# This Lef is suitable for top metal5 design.
#
# ==================STATEMENT===================================
# Copyright (c) 2001-2019 Grace Semiconductor Manufacturing Corporation.
# All Rights Reserved.
# Forwarding or copying of this document, in any medium, in whole or 
# in part, or disclosure of its contents, to other than an authorized 
# recipient, is strictly prohibited.
#
# =============IMPORTANT APPLICATION NOTES======================
# M1~ M5 layers Must NOT be used for routing over the IP region. 
# 
# LEF OUT API 
# User Name : daisb 
# Date : Thu Mar 28 11:13:39 2019
# 
NAMESCASESENSITIVE ON ;
BUSBITCHARS "[]" ;
DIVIDERCHAR "/" ;
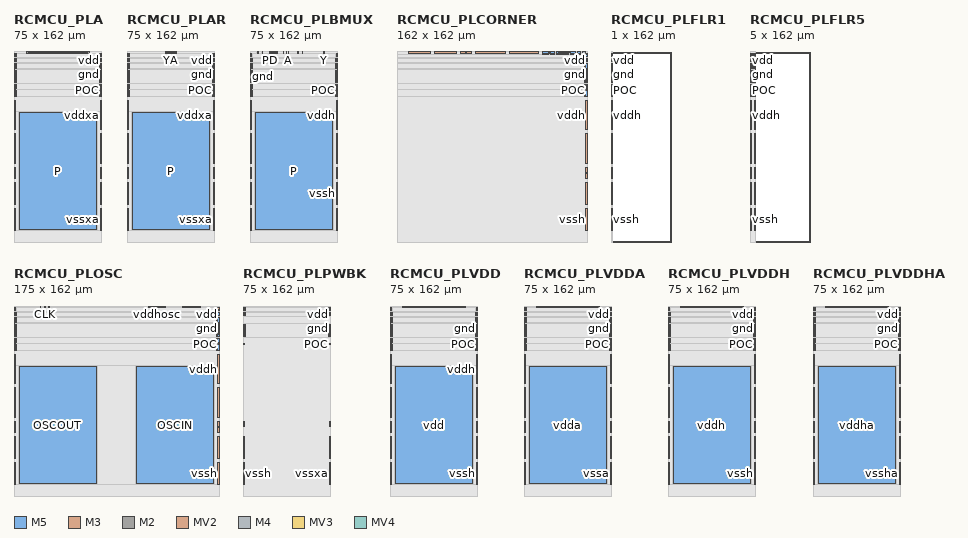
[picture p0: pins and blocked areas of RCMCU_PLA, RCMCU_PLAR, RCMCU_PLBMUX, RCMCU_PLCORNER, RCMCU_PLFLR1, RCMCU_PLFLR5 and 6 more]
MACRO RCMCU_PLA
 CLASS PAD ;
 FOREIGN RCMCU_PLA ;
 ORIGIN 0 0 ;
 SIZE 75 BY 162 ;
 SYMMETRY X Y R90 ;
 PIN P
 USE SIGNAL ;
 DIRECTION INOUT ;
 PORT
 LAYER M5 ;
 RECT 4.5 10.5 70.5 110.5 ;
 END
 PORT
 LAYER M3 ;
 RECT 10.77 160.82 64.77 162 ;
 END
 PORT
 LAYER M2 ;
 RECT 10.77 160.82 64.77 162 ;
 END
 PORT
 LAYER MV2 ;
 RECT 25.21 161.515 25.4 161.705 ;
 RECT 30.71 160.965 30.9 161.155 ;
 RECT 30.16 160.965 30.35 161.155 ;
 RECT 29.61 160.965 29.8 161.155 ;
 RECT 29.06 160.965 29.25 161.155 ;
 RECT 28.51 160.965 28.7 161.155 ;
 RECT 30.71 161.515 30.9 161.705 ;
 RECT 28.51 161.515 28.7 161.705 ;
 RECT 29.06 161.515 29.25 161.705 ;
 RECT 29.61 161.515 29.8 161.705 ;
 RECT 30.16 161.515 30.35 161.705 ;
 RECT 34.01 160.965 34.2 161.155 ;
 RECT 33.46 160.965 33.65 161.155 ;
 RECT 32.91 160.965 33.1 161.155 ;
 RECT 32.36 160.965 32.55 161.155 ;
 RECT 31.81 160.965 32 161.155 ;
 RECT 32.91 161.515 33.1 161.705 ;
 RECT 33.46 161.515 33.65 161.705 ;
 RECT 34.01 161.515 34.2 161.705 ;
 RECT 32.36 161.515 32.55 161.705 ;
 RECT 31.81 161.515 32 161.705 ;
 RECT 35.66 160.965 35.85 161.155 ;
 RECT 36.21 160.965 36.4 161.155 ;
 RECT 36.76 160.965 36.95 161.155 ;
 RECT 37.31 160.965 37.5 161.155 ;
 RECT 35.11 160.965 35.3 161.155 ;
 RECT 34.56 160.965 34.75 161.155 ;
 RECT 35.11 161.515 35.3 161.705 ;
 RECT 37.31 161.515 37.5 161.705 ;
 RECT 36.76 161.515 36.95 161.705 ;
 RECT 36.21 161.515 36.4 161.705 ;
 RECT 35.66 161.515 35.85 161.705 ;
 RECT 34.56 161.515 34.75 161.705 ;
 RECT 31.26 160.965 31.45 161.155 ;
 RECT 31.26 161.515 31.45 161.705 ;
 RECT 40.06 160.965 40.25 161.155 ;
 RECT 40.61 160.965 40.8 161.155 ;
 RECT 39.51 160.965 39.7 161.155 ;
 RECT 38.96 160.965 39.15 161.155 ;
 RECT 38.41 160.965 38.6 161.155 ;
 RECT 37.86 160.965 38.05 161.155 ;
 RECT 40.61 161.515 40.8 161.705 ;
 RECT 40.06 161.515 40.25 161.705 ;
 RECT 37.86 161.515 38.05 161.705 ;
 RECT 38.41 161.515 38.6 161.705 ;
 RECT 38.96 161.515 39.15 161.705 ;
 RECT 39.51 161.515 39.7 161.705 ;
 RECT 42.26 160.965 42.45 161.155 ;
 RECT 42.81 160.965 43 161.155 ;
 RECT 43.36 160.965 43.55 161.155 ;
 RECT 41.16 160.965 41.35 161.155 ;
 RECT 41.71 160.965 41.9 161.155 ;
 RECT 42.26 161.515 42.45 161.705 ;
 RECT 42.81 161.515 43 161.705 ;
 RECT 43.36 161.515 43.55 161.705 ;
 RECT 41.71 161.515 41.9 161.705 ;
 RECT 41.16 161.515 41.35 161.705 ;
 RECT 44.46 160.965 44.65 161.155 ;
 RECT 45.01 160.965 45.2 161.155 ;
 RECT 45.56 160.965 45.75 161.155 ;
 RECT 46.11 160.965 46.3 161.155 ;
 RECT 46.66 160.965 46.85 161.155 ;
 RECT 44.46 161.515 44.65 161.705 ;
 RECT 46.66 161.515 46.85 161.705 ;
 RECT 46.11 161.515 46.3 161.705 ;
 RECT 45.56 161.515 45.75 161.705 ;
 RECT 45.01 161.515 45.2 161.705 ;
 RECT 49.96 160.965 50.15 161.155 ;
 RECT 49.41 160.965 49.6 161.155 ;
 RECT 48.86 160.965 49.05 161.155 ;
 RECT 48.31 160.965 48.5 161.155 ;
 RECT 47.76 160.965 47.95 161.155 ;
 RECT 47.21 160.965 47.4 161.155 ;
 RECT 49.96 161.515 50.15 161.705 ;
 RECT 49.41 161.515 49.6 161.705 ;
 RECT 47.21 161.515 47.4 161.705 ;
 RECT 47.76 161.515 47.95 161.705 ;
 RECT 48.31 161.515 48.5 161.705 ;
 RECT 48.86 161.515 49.05 161.705 ;
 RECT 43.91 160.965 44.1 161.155 ;
 RECT 43.91 161.515 44.1 161.705 ;
 RECT 51.61 160.965 51.8 161.155 ;
 RECT 52.16 160.965 52.35 161.155 ;
 RECT 52.71 160.965 52.9 161.155 ;
 RECT 50.51 160.965 50.7 161.155 ;
 RECT 51.06 160.965 51.25 161.155 ;
 RECT 51.61 161.515 51.8 161.705 ;
 RECT 52.16 161.515 52.35 161.705 ;
 RECT 52.71 161.515 52.9 161.705 ;
 RECT 51.06 161.515 51.25 161.705 ;
 RECT 50.51 161.515 50.7 161.705 ;
 RECT 53.81 160.965 54 161.155 ;
 RECT 54.36 160.965 54.55 161.155 ;
 RECT 54.91 160.965 55.1 161.155 ;
 RECT 56.01 160.965 56.2 161.155 ;
 RECT 55.46 160.965 55.65 161.155 ;
 RECT 53.81 161.515 54 161.705 ;
 RECT 56.01 161.515 56.2 161.705 ;
 RECT 55.46 161.515 55.65 161.705 ;
 RECT 54.91 161.515 55.1 161.705 ;
 RECT 54.36 161.515 54.55 161.705 ;
 RECT 53.26 160.965 53.45 161.155 ;
 RECT 53.26 161.515 53.45 161.705 ;
 RECT 59.31 160.965 59.5 161.155 ;
 RECT 58.76 160.965 58.95 161.155 ;
 RECT 57.11 160.965 57.3 161.155 ;
 RECT 56.56 160.965 56.75 161.155 ;
 RECT 58.21 160.965 58.4 161.155 ;
 RECT 57.66 160.965 57.85 161.155 ;
 RECT 59.31 161.515 59.5 161.705 ;
 RECT 58.76 161.515 58.95 161.705 ;
 RECT 56.56 161.515 56.75 161.705 ;
 RECT 57.11 161.515 57.3 161.705 ;
 RECT 57.66 161.515 57.85 161.705 ;
 RECT 58.21 161.515 58.4 161.705 ;
 RECT 60.96 160.965 61.15 161.155 ;
 RECT 61.51 160.965 61.7 161.155 ;
 RECT 62.06 160.965 62.25 161.155 ;
 RECT 62.61 160.965 62.8 161.155 ;
 RECT 60.41 160.965 60.6 161.155 ;
 RECT 59.86 160.965 60.05 161.155 ;
 RECT 60.96 161.515 61.15 161.705 ;
 RECT 61.51 161.515 61.7 161.705 ;
 RECT 62.61 161.515 62.8 161.705 ;
 RECT 62.06 161.515 62.25 161.705 ;
 RECT 60.41 161.515 60.6 161.705 ;
 RECT 59.86 161.515 60.05 161.705 ;
 RECT 15.31 160.965 15.5 161.155 ;
 RECT 14.76 160.965 14.95 161.155 ;
 RECT 14.21 160.965 14.4 161.155 ;
 RECT 12.56 160.965 12.75 161.155 ;
 RECT 13.11 160.965 13.3 161.155 ;
 RECT 13.66 160.965 13.85 161.155 ;
 RECT 14.21 161.515 14.4 161.705 ;
 RECT 14.76 161.515 14.95 161.705 ;
 RECT 15.31 161.515 15.5 161.705 ;
 RECT 12.56 161.515 12.75 161.705 ;
 RECT 13.11 161.515 13.3 161.705 ;
 RECT 13.66 161.515 13.85 161.705 ;
 RECT 18.61 160.965 18.8 161.155 ;
 RECT 16.96 160.965 17.15 161.155 ;
 RECT 16.41 160.965 16.6 161.155 ;
 RECT 18.06 160.965 18.25 161.155 ;
 RECT 17.51 160.965 17.7 161.155 ;
 RECT 15.86 160.965 16.05 161.155 ;
 RECT 18.61 161.515 18.8 161.705 ;
 RECT 16.41 161.515 16.6 161.705 ;
 RECT 18.06 161.515 18.25 161.705 ;
 RECT 17.51 161.515 17.7 161.705 ;
 RECT 16.96 161.515 17.15 161.705 ;
 RECT 15.86 161.515 16.05 161.705 ;
 RECT 21.36 160.965 21.55 161.155 ;
 RECT 20.81 160.965 21 161.155 ;
 RECT 20.26 160.965 20.45 161.155 ;
 RECT 19.71 160.965 19.9 161.155 ;
 RECT 19.16 160.965 19.35 161.155 ;
 RECT 21.36 161.515 21.55 161.705 ;
 RECT 19.16 161.515 19.35 161.705 ;
 RECT 19.71 161.515 19.9 161.705 ;
 RECT 20.26 161.515 20.45 161.705 ;
 RECT 20.81 161.515 21 161.705 ;
 RECT 23.56 160.965 23.75 161.155 ;
 RECT 24.11 160.965 24.3 161.155 ;
 RECT 24.66 160.965 24.85 161.155 ;
 RECT 22.46 160.965 22.65 161.155 ;
 RECT 23.01 160.965 23.2 161.155 ;
 RECT 23.56 161.515 23.75 161.705 ;
 RECT 24.11 161.515 24.3 161.705 ;
 RECT 24.66 161.515 24.85 161.705 ;
 RECT 23.01 161.515 23.2 161.705 ;
 RECT 22.46 161.515 22.65 161.705 ;
 RECT 21.91 160.965 22.1 161.155 ;
 RECT 21.91 161.515 22.1 161.705 ;
 RECT 27.96 160.965 28.15 161.155 ;
 RECT 25.76 160.965 25.95 161.155 ;
 RECT 26.31 160.965 26.5 161.155 ;
 RECT 26.86 160.965 27.05 161.155 ;
 RECT 27.41 160.965 27.6 161.155 ;
 RECT 25.21 160.965 25.4 161.155 ;
 RECT 27.96 161.515 28.15 161.705 ;
 RECT 25.76 161.515 25.95 161.705 ;
 RECT 27.41 161.515 27.6 161.705 ;
 RECT 26.86 161.515 27.05 161.705 ;
 RECT 26.31 161.515 26.5 161.705 ;
 END
 END P
 PIN POC
 USE POWER ;
 DIRECTION INOUT ;
 PORT
 LAYER M3 ;
 RECT 73.72 129.1 75 130 ;
 END
 PORT
 LAYER M3 ;
 RECT 0 129.1 1.28 130 ;
 END
 END POC
 PIN gnd
 USE GROUND ;
 DIRECTION INOUT ;
 PORT
 LAYER M5 ;
 RECT 73.415 135.99 75 146.46 ;
 END
 PORT
 LAYER M5 ;
 RECT 0 135.99 1.585 146.46 ;
 END
 PORT
 LAYER M5 ;
 RECT 0 157.97 1.585 160.47 ;
 END
 PORT
 LAYER M5 ;
 RECT 73.415 157.97 75 160.47 ;
 END
 PORT
 LAYER M4 ;
 RECT 73 135.99 75 146.46 ;
 END
 PORT
 LAYER M4 ;
 RECT 0 135.99 2 146.46 ;
 END
 PORT
 LAYER M4 ;
 RECT 0 157.97 2 160.47 ;
 END
 PORT
 LAYER M4 ;
 RECT 73 157.97 75 160.47 ;
 END
 PORT
 LAYER M3 ;
 RECT 73.72 59.66 75 63.66 ;
 END
 PORT
 LAYER M3 ;
 RECT 0 59.66 1.28 63.66 ;
 END
 END gnd
 PIN vdd
 USE POWER ;
 DIRECTION INOUT ;
 PORT
 LAYER M5 ;
 RECT 73.415 153.8 75 156.3 ;
 END
 PORT
 LAYER M5 ;
 RECT 0 153.8 1.585 156.3 ;
 END
 PORT
 LAYER M4 ;
 RECT 73 153.8 75 156.3 ;
 END
 PORT
 LAYER M4 ;
 RECT 0 153.8 2 156.3 ;
 END
 END vdd
 PIN vddxa
 USE POWER ;
 DIRECTION INOUT ;
 PORT
 LAYER M5 ;
 RECT 73.415 130.82 75 134.32 ;
 END
 PORT
 LAYER M5 ;
 RECT 0 130.82 1.585 134.32 ;
 END
 PORT
 LAYER M4 ;
 RECT 73 130.82 75 134.32 ;
 END
 PORT
 LAYER M4 ;
 RECT 0 130.82 2 134.32 ;
 END
 PORT
 LAYER M3 ;
 RECT 73.72 53.99 75 57.99 ;
 END
 PORT
 LAYER M3 ;
 RECT 0 53.99 1.28 57.99 ;
 END
 PORT
 LAYER M3 ;
 RECT 73.72 66.96 75 92.24 ;
 END
 PORT
 LAYER M3 ;
 RECT 0 66.96 1.28 92.24 ;
 END
 PORT
 LAYER M3 ;
 RECT 0 95.54 1.28 120.85 ;
 END
 PORT
 LAYER M3 ;
 RECT 73.72 95.54 75 120.85 ;
 END
 PORT
 LAYER M3 ;
 RECT 0 137.66 0.6 150.47 ;
 END
 PORT
 LAYER M3 ;
 RECT 74.4 137.66 75 150.47 ;
 END
 END vddxa
 PIN vssxa
 USE GROUND ;
 DIRECTION INOUT ;
 PORT
 LAYER M5 ;
 RECT 73.415 124.15 75 129.15 ;
 END
 PORT
 LAYER M5 ;
 RECT 0 124.15 1.585 129.15 ;
 END
 PORT
 LAYER M5 ;
 RECT 0 148.13 1.585 152.13 ;
 END
 PORT
 LAYER M5 ;
 RECT 73.415 148.13 75 152.13 ;
 END
 PORT
 LAYER M4 ;
 RECT 73 124.15 75 129.15 ;
 END
 PORT
 LAYER M4 ;
 RECT 0 124.15 2 129.15 ;
 END
 PORT
 LAYER M4 ;
 RECT 0 148.13 2 152.13 ;
 END
 PORT
 LAYER M4 ;
 RECT 73 148.13 75 152.13 ;
 END
 PORT
 LAYER M3 ;
 RECT 73.72 9.91 75 28.65 ;
 END
 PORT
 LAYER M3 ;
 RECT 0 9.91 1.28 28.65 ;
 END
 PORT
 LAYER M3 ;
 RECT 0 31.95 1.28 50.69 ;
 END
 PORT
 LAYER M3 ;
 RECT 73.72 31.95 75 50.69 ;
 END
 END vssxa
 OBS
 LAYER GATE ;
 RECT 0 0 75 162 ;
 LAYER MV1 ;
 RECT 0 0 75 162 ;
 LAYER MV2 ;
 RECT 0 0 75 162 ;
 LAYER MV3 ;
 RECT 0 0 75 162 ;
 LAYER MV4 ;
 RECT 0 0 75 162 ;
 LAYER M1 ;
 RECT 0 0 75 162 ;
 LAYER M2 ;
 RECT 65.37 160.22 75 162 ;
 RECT 0 160.22 10.17 162 ;
 RECT 0 0 75 160.22 ;
 LAYER M3 ;
 RECT 0 0 75 9.31 ;
 RECT 0 29.25 75 31.35 ;
 RECT 1.88 9.31 73.12 29.25 ;
 RECT 0 160.22 10.17 162 ;
 RECT 0 51.29 75 53.75 ;
 RECT 1.88 31.35 73.12 51.29 ;
 RECT 0 58.23 75 59.42 ;
 RECT 1.52 53.75 73.48 58.23 ;
 RECT 1.88 66.36 73.12 92.84 ;
 RECT 1.88 94.94 73.12 121.45 ;
 RECT 0 63.9 75 66.36 ;
 RECT 1.52 59.42 73.48 63.9 ;
 RECT 0 92.84 75 94.94 ;
 RECT 0 121.45 75 128.86 ;
 RECT 0 130.24 75 137.06 ;
 RECT 1.52 128.86 73.48 130.24 ;
 RECT 0 151.07 75 160.22 ;
 RECT 1.2 137.06 73.8 151.07 ;
 RECT 65.37 160.22 75 162 ;
 LAYER M4 ;
 RECT 0 0 75 123.91 ;
 RECT 0 129.39 75 130.58 ;
 RECT 2.24 123.91 72.76 129.39 ;
 RECT 2.6 135.39 72.4 147.06 ;
 RECT 0 134.56 75 135.39 ;
 RECT 2.24 130.58 72.76 134.56 ;
 RECT 0 147.06 75 147.89 ;
 RECT 0 152.37 75 153.56 ;
 RECT 2.24 147.89 72.76 152.37 ;
 RECT 0 156.54 75 157.73 ;
 RECT 2.24 153.56 72.76 156.54 ;
 RECT 0 160.71 75 162 ;
 RECT 2.24 157.73 72.76 160.71 ;
 LAYER M5 ;
 RECT 0 9.9 3.9 111.1 ;
 RECT 71.1 9.9 75 111.1 ;
 RECT 0 0 75 9.9 ;
 RECT 0 111.1 75 123.69 ;
 RECT 0 129.61 75 130.36 ;
 RECT 2.045 123.69 72.955 129.61 ;
 RECT 2.185 135.39 72.815 147.06 ;
 RECT 0 134.78 75 135.39 ;
 RECT 2.045 130.36 72.955 134.78 ;
 RECT 0 147.06 75 147.67 ;
 RECT 0 152.59 75 153.34 ;
 RECT 2.045 147.67 72.955 152.59 ;
 RECT 0 156.76 75 157.51 ;
 RECT 2.045 153.34 72.955 156.76 ;
 RECT 0 160.93 75 162 ;
 RECT 2.045 157.51 72.955 160.93 ;
 END
END RCMCU_PLA

MACRO RCMCU_PLAR
 CLASS PAD ;
 FOREIGN RCMCU_PLAR ;
 ORIGIN 0 0 ;
 SIZE 75 BY 162 ;
 SYMMETRY X Y R90 ;
 PIN P
 USE SIGNAL ;
 DIRECTION INOUT ;
 PORT
 LAYER M5 ;
 RECT 4.5 10.5 70.5 110.5 ;
 END
 END P
 PIN POC
 USE POWER ;
 DIRECTION INOUT ;
 PORT
 LAYER M3 ;
 RECT 73.72 129.1 75 130 ;
 END
 PORT
 LAYER M3 ;
 RECT 0 129.1 1.28 130 ;
 END
 END POC
 PIN YA
 USE SIGNAL ;
 DIRECTION OUTPUT ;
 PORT
 LAYER M3 ;
 RECT 32.5 160.82 42.5 162 ;
 END
 PORT
 LAYER M2 ;
 RECT 32.5 160.82 42.5 162 ;
 END
 PORT
 LAYER MV2 ;
 RECT 35.475 160.965 35.665 161.155 ;
 RECT 36.575 160.965 36.765 161.155 ;
 RECT 37.125 160.965 37.315 161.155 ;
 RECT 36.025 160.965 36.215 161.155 ;
 RECT 34.375 160.965 34.565 161.155 ;
 RECT 33.825 160.965 34.015 161.155 ;
 RECT 33.275 160.965 33.465 161.155 ;
 RECT 34.925 160.965 35.115 161.155 ;
 RECT 35.475 161.515 35.665 161.705 ;
 RECT 36.025 161.515 36.215 161.705 ;
 RECT 37.125 161.515 37.315 161.705 ;
 RECT 36.575 161.515 36.765 161.705 ;
 RECT 33.275 161.515 33.465 161.705 ;
 RECT 33.825 161.515 34.015 161.705 ;
 RECT 34.375 161.515 34.565 161.705 ;
 RECT 34.925 161.515 35.115 161.705 ;
 RECT 39.875 160.965 40.065 161.155 ;
 RECT 40.425 160.965 40.615 161.155 ;
 RECT 40.975 160.965 41.165 161.155 ;
 RECT 41.525 160.965 41.715 161.155 ;
 RECT 38.225 160.965 38.415 161.155 ;
 RECT 39.325 160.965 39.515 161.155 ;
 RECT 38.775 160.965 38.965 161.155 ;
 RECT 37.675 160.965 37.865 161.155 ;
 RECT 41.525 161.515 41.715 161.705 ;
 RECT 40.975 161.515 41.165 161.705 ;
 RECT 40.425 161.515 40.615 161.705 ;
 RECT 39.875 161.515 40.065 161.705 ;
 RECT 39.325 161.515 39.515 161.705 ;
 RECT 38.775 161.515 38.965 161.705 ;
 RECT 38.225 161.515 38.415 161.705 ;
 RECT 37.675 161.515 37.865 161.705 ;
 END
 END YA
 PIN gnd
 USE GROUND ;
 DIRECTION INOUT ;
 PORT
 LAYER M5 ;
 RECT 73.415 135.99 75 146.46 ;
 END
 PORT
 LAYER M5 ;
 RECT 0 135.99 1.585 146.46 ;
 END
 PORT
 LAYER M5 ;
 RECT 0 157.97 1.585 160.47 ;
 END
 PORT
 LAYER M5 ;
 RECT 73.415 157.97 75 160.47 ;
 END
 PORT
 LAYER M4 ;
 RECT 73 135.99 75 146.46 ;
 END
 PORT
 LAYER M4 ;
 RECT 0 135.99 2 146.46 ;
 END
 PORT
 LAYER M4 ;
 RECT 0 157.97 2 160.47 ;
 END
 PORT
 LAYER M4 ;
 RECT 73 157.97 75 160.47 ;
 END
 PORT
 LAYER M3 ;
 RECT 73.72 59.66 75 63.66 ;
 END
 PORT
 LAYER M3 ;
 RECT 0 59.66 1.28 63.66 ;
 END
 END gnd
 PIN vdd
 USE POWER ;
 DIRECTION INOUT ;
 PORT
 LAYER M5 ;
 RECT 73.415 153.8 75 156.3 ;
 END
 PORT
 LAYER M5 ;
 RECT 0 153.8 1.585 156.3 ;
 END
 PORT
 LAYER M4 ;
 RECT 73 153.8 75 156.3 ;
 END
 PORT
 LAYER M4 ;
 RECT 0 153.8 2 156.3 ;
 END
 END vdd
 PIN vddxa
 USE POWER ;
 DIRECTION INOUT ;
 PORT
 LAYER M5 ;
 RECT 73.415 130.82 75 134.32 ;
 END
 PORT
 LAYER M5 ;
 RECT 0 130.82 1.585 134.32 ;
 END
 PORT
 LAYER M4 ;
 RECT 73 130.82 75 134.32 ;
 END
 PORT
 LAYER M4 ;
 RECT 0 130.82 2 134.32 ;
 END
 PORT
 LAYER M3 ;
 RECT 73.72 53.99 75 57.99 ;
 END
 PORT
 LAYER M3 ;
 RECT 0 53.99 1.28 57.99 ;
 END
 PORT
 LAYER M3 ;
 RECT 73.72 66.96 75 92.24 ;
 END
 PORT
 LAYER M3 ;
 RECT 0 66.96 1.28 92.24 ;
 END
 PORT
 LAYER M3 ;
 RECT 0 95.54 1.28 120.85 ;
 END
 PORT
 LAYER M3 ;
 RECT 73.72 95.54 75 120.85 ;
 END
 PORT
 LAYER M3 ;
 RECT 0 137.66 0.6 150.47 ;
 END
 PORT
 LAYER M3 ;
 RECT 74.4 137.66 75 150.47 ;
 END
 END vddxa
 PIN vssxa
 USE GROUND ;
 DIRECTION INOUT ;
 PORT
 LAYER M5 ;
 RECT 73.415 124.15 75 129.15 ;
 END
 PORT
 LAYER M5 ;
 RECT 0 124.15 1.585 129.15 ;
 END
 PORT
 LAYER M5 ;
 RECT 0 148.13 1.585 152.13 ;
 END
 PORT
 LAYER M5 ;
 RECT 73.415 148.13 75 152.13 ;
 END
 PORT
 LAYER M4 ;
 RECT 73 124.15 75 129.15 ;
 END
 PORT
 LAYER M4 ;
 RECT 0 124.15 2 129.15 ;
 END
 PORT
 LAYER M4 ;
 RECT 0 148.13 2 152.13 ;
 END
 PORT
 LAYER M4 ;
 RECT 73 148.13 75 152.13 ;
 END
 PORT
 LAYER M3 ;
 RECT 73.72 9.91 75 28.65 ;
 END
 PORT
 LAYER M3 ;
 RECT 0 9.91 1.28 28.65 ;
 END
 PORT
 LAYER M3 ;
 RECT 0 31.95 1.28 50.69 ;
 END
 PORT
 LAYER M3 ;
 RECT 73.72 31.95 75 50.69 ;
 END
 END vssxa
 OBS
 LAYER GATE ;
 RECT 0 0 75 162 ;
 LAYER MV1 ;
 RECT 0 0 75 162 ;
 LAYER MV2 ;
 RECT 0 0 75 162 ;
 LAYER MV3 ;
 RECT 0 0 75 162 ;
 LAYER MV4 ;
 RECT 0 0 75 162 ;
 LAYER M1 ;
 RECT 0 0 75 162 ;
 LAYER M2 ;
 RECT 42.74 160.58 75 162 ;
 RECT 0 160.58 32.26 162 ;
 RECT 0 0 75 160.58 ;
 LAYER M3 ;
 RECT 0 0 75 9.31 ;
 RECT 0 29.25 75 31.35 ;
 RECT 1.88 9.31 73.12 29.25 ;
 RECT 0 160.58 32.26 162 ;
 RECT 0 51.29 75 53.75 ;
 RECT 1.88 31.35 73.12 51.29 ;
 RECT 0 58.23 75 59.42 ;
 RECT 1.52 53.75 73.48 58.23 ;
 RECT 1.88 66.36 73.12 92.84 ;
 RECT 1.88 94.94 73.12 121.45 ;
 RECT 0 63.9 75 66.36 ;
 RECT 1.52 59.42 73.48 63.9 ;
 RECT 0 92.84 75 94.94 ;
 RECT 0 121.45 75 128.86 ;
 RECT 0 130.24 75 137.06 ;
 RECT 1.52 128.86 73.48 130.24 ;
 RECT 0 151.07 75 160.58 ;
 RECT 1.2 137.06 73.8 151.07 ;
 RECT 42.74 160.58 75 162 ;
 LAYER M4 ;
 RECT 0 0 75 123.91 ;
 RECT 0 129.39 75 130.58 ;
 RECT 2.24 123.91 72.76 129.39 ;
 RECT 2.6 135.39 72.4 147.06 ;
 RECT 0 134.56 75 135.39 ;
 RECT 2.24 130.58 72.76 134.56 ;
 RECT 0 147.06 75 147.89 ;
 RECT 0 152.37 75 153.56 ;
 RECT 2.24 147.89 72.76 152.37 ;
 RECT 0 156.54 75 157.73 ;
 RECT 2.24 153.56 72.76 156.54 ;
 RECT 0 160.71 75 162 ;
 RECT 2.24 157.73 72.76 160.71 ;
 LAYER M5 ;
 RECT 0 9.9 3.9 111.1 ;
 RECT 71.1 9.9 75 111.1 ;
 RECT 0 0 75 9.9 ;
 RECT 0 111.1 75 123.69 ;
 RECT 0 129.61 75 130.36 ;
 RECT 2.045 123.69 72.955 129.61 ;
 RECT 2.185 135.39 72.815 147.06 ;
 RECT 0 134.78 75 135.39 ;
 RECT 2.045 130.36 72.955 134.78 ;
 RECT 0 147.06 75 147.67 ;
 RECT 0 152.59 75 153.34 ;
 RECT 2.045 147.67 72.955 152.59 ;
 RECT 0 156.76 75 157.51 ;
 RECT 2.045 153.34 72.955 156.76 ;
 RECT 0 160.93 75 162 ;
 RECT 2.045 157.51 72.955 160.93 ;
 END
END RCMCU_PLAR


MACRO RCMCU_PLBMUX
  CLASS PAD ;
  ORIGIN 0 0 ;
  FOREIGN RCMCU_PLBMUX 0 0 ;
  SIZE 75 BY 162 ;
  SYMMETRY X Y R90 ;
  PIN A
    DIRECTION INPUT ;
    USE SIGNAL ;
    PORT
      LAYER MV2 ;
        RECT 32.645 160.885 32.835 161.075 ;
        RECT 32.645 161.405 32.835 161.595 ;
    END
    PORT
      LAYER M2 ;
        RECT 32.49 160.79 32.99 162 ;
    END
    PORT
      LAYER M3 ;
        RECT 32.49 160.79 32.99 162 ;
    END
  END A
  PIN CS
    DIRECTION INPUT ;
    USE SIGNAL ;
    PORT
      LAYER MV2 ;
        RECT 44.685 161.405 44.875 161.595 ;
        RECT 44.685 160.885 44.875 161.075 ;
    END
    PORT
      LAYER M2 ;
        RECT 44.53 160.79 45.03 162 ;
    END
    PORT
      LAYER M3 ;
        RECT 44.53 160.79 45.03 162 ;
    END
  END CS
  PIN DR
    DIRECTION INPUT ;
    USE SIGNAL ;
    PORT
      LAYER MV2 ;
        RECT 23.505 160.885 23.695 161.075 ;
        RECT 23.505 161.405 23.695 161.595 ;
    END
    PORT
      LAYER M2 ;
        RECT 23.35 160.79 23.85 162 ;
    END
    PORT
      LAYER M3 ;
        RECT 23.35 160.79 23.85 162 ;
    END
  END DR
  PIN IE
    DIRECTION INPUT ;
    USE SIGNAL ;
    PORT
      LAYER MV2 ;
        RECT 40.885 161.405 41.075 161.595 ;
        RECT 40.885 160.885 41.075 161.075 ;
    END
    PORT
      LAYER M2 ;
        RECT 40.73 160.79 41.23 162 ;
    END
    PORT
      LAYER M3 ;
        RECT 40.73 160.79 41.23 162 ;
    END
  END IE
  PIN OD
    DIRECTION INPUT ;
    USE SIGNAL ;
    PORT
      LAYER MV2 ;
        RECT 28.585 161.405 28.775 161.595 ;
        RECT 28.585 160.885 28.775 161.075 ;
    END
    PORT
      LAYER M2 ;
        RECT 28.43 160.79 28.93 162 ;
    END
    PORT
      LAYER M3 ;
        RECT 28.43 160.79 28.93 162 ;
    END
  END OD
  PIN OE
    DIRECTION INPUT ;
    USE SIGNAL ;
    PORT
      LAYER MV2 ;
        RECT 31.105 161.405 31.295 161.595 ;
        RECT 31.105 160.885 31.295 161.075 ;
    END
    PORT
      LAYER M2 ;
        RECT 30.95 160.79 31.45 162 ;
    END
    PORT
      LAYER M3 ;
        RECT 30.95 160.79 31.45 162 ;
    END
  END OE
  PIN OS
    DIRECTION INPUT ;
    USE SIGNAL ;
    PORT
      LAYER MV2 ;
        RECT 21.855 160.885 22.045 161.075 ;
        RECT 21.855 161.405 22.045 161.595 ;
    END
    PORT
      LAYER M2 ;
        RECT 21.7 160.79 22.2 162 ;
    END
    PORT
      LAYER M3 ;
        RECT 21.7 160.79 22.2 162 ;
    END
  END OS
  PIN P
    DIRECTION INOUT ;
    USE SIGNAL ;
    PORT
      LAYER M5 ;
        RECT 4.5 10.5 70.5 110.5 ;
    END
  END P
  PIN PD
    DIRECTION INPUT ;
    USE SIGNAL ;
    PORT
      LAYER MV2 ;
        RECT 17.065 160.885 17.255 161.075 ;
        RECT 17.065 161.405 17.255 161.595 ;
    END
    PORT
      LAYER M2 ;
        RECT 16.91 160.79 17.41 162 ;
    END
    PORT
      LAYER M3 ;
        RECT 16.91 160.79 17.41 162 ;
    END
  END PD
  PIN POC
    DIRECTION OUTPUT ;
    USE POWER ;
    PORT
      LAYER MV2 ;
        RECT 6.655 160.905 6.845 161.095 ;
    END
    PORT
      LAYER MV2 ;
        RECT 6.655 161.385 6.845 161.575 ;
    END
    PORT
      LAYER M3 ;
        RECT 6.06 160.79 6.96 162 ;
    END
    PORT
      LAYER MV2 ;
        RECT 6.175 160.905 6.365 161.095 ;
    END
    PORT
      LAYER MV2 ;
        RECT 6.175 161.385 6.365 161.575 ;
    END
    PORT
      LAYER M2 ;
        RECT 6.06 160.79 6.96 162 ;
    END
    PORT
      LAYER M3 ;
        RECT 0 129.1 1.28 130 ;
    END
    PORT
      LAYER M3 ;
        RECT 73.72 129.1 75 130 ;
    END
  END POC
  PIN PU
    DIRECTION INPUT ;
    USE SIGNAL ;
    PORT
      LAYER MV2 ;
        RECT 18.605 161.405 18.795 161.595 ;
        RECT 18.605 160.885 18.795 161.075 ;
    END
    PORT
      LAYER M2 ;
        RECT 18.45 160.79 18.95 162 ;
    END
    PORT
      LAYER M3 ;
        RECT 18.45 160.79 18.95 162 ;
    END
  END PU
  PIN SR
    DIRECTION INPUT ;
    USE SIGNAL ;
    PORT
      LAYER MV2 ;
        RECT 20.315 160.885 20.505 161.075 ;
        RECT 20.315 161.405 20.505 161.595 ;
    END
    PORT
      LAYER M2 ;
        RECT 20.16 160.79 20.66 162 ;
    END
    PORT
      LAYER M3 ;
        RECT 20.16 160.79 20.66 162 ;
    END
  END SR
  PIN Y
    DIRECTION OUTPUT ;
    USE SIGNAL ;
    PORT
      LAYER MV2 ;
        RECT 62.955 161.405 63.145 161.595 ;
        RECT 62.955 160.885 63.145 161.075 ;
    END
    PORT
      LAYER M2 ;
        RECT 62.8 160.79 63.3 162 ;
    END
    PORT
      LAYER M3 ;
        RECT 62.8 160.79 63.3 162 ;
    END
  END Y
  PIN YA
    DIRECTION INOUT ;
    USE SIGNAL ;
    PORT
      LAYER MV2 ;
        RECT 10.425 160.885 10.615 161.075 ;
        RECT 10.425 161.405 10.615 161.595 ;
    END
    PORT
      LAYER M2 ;
        RECT 10.27 160.79 10.77 162 ;
    END
    PORT
      LAYER M3 ;
        RECT 10.27 160.79 10.77 162 ;
    END
  END YA
  PIN gnd
    DIRECTION INOUT ;
    USE GROUND ;
    PORT
      LAYER MV3 ;
        RECT 73.6 158.44 73.79 158.63 ;
        RECT 74.21 158.44 74.4 158.63 ;
        RECT 73.6 159.05 73.79 159.24 ;
        RECT 74.21 159.05 74.4 159.24 ;
        RECT 73.6 159.66 73.79 159.85 ;
        RECT 74.21 159.66 74.4 159.85 ;
        RECT 0.6 158.44 0.79 158.63 ;
        RECT 1.21 158.44 1.4 158.63 ;
        RECT 0.6 159.05 0.79 159.24 ;
        RECT 1.21 159.05 1.4 159.24 ;
        RECT 0.6 159.66 0.79 159.85 ;
        RECT 1.21 159.66 1.4 159.85 ;
    END
    PORT
      LAYER M3 ;
        RECT 73.415 157.97 75 160.37 ;
    END
    PORT
      LAYER M3 ;
        RECT 0 157.97 1.585 160.37 ;
    END
    PORT
      LAYER M3 ;
        RECT 0 59.66 1.28 63.66 ;
    END
    PORT
      LAYER M3 ;
        RECT 73.72 59.66 75 63.66 ;
    END
    PORT
      LAYER M4 ;
        RECT 73.415 157.97 75 160.47 ;
    END
    PORT
      LAYER M4 ;
        RECT 0 157.97 1.585 160.47 ;
    END
    PORT
      LAYER M4 ;
        RECT 0 135.99 2 146.46 ;
    END
    PORT
      LAYER M4 ;
        RECT 73 135.99 75 146.46 ;
    END
    PORT
      LAYER M5 ;
        RECT 73.415 157.97 75 160.47 ;
    END
    PORT
      LAYER M5 ;
        RECT 0 157.97 1.585 160.47 ;
    END
    PORT
      LAYER M5 ;
        RECT 0 135.99 1.585 146.46 ;
    END
    PORT
      LAYER M5 ;
        RECT 73.415 135.99 75 146.46 ;
    END
  END gnd
  PIN vdd
    DIRECTION INOUT ;
    USE POWER ;
    PORT
      LAYER M4 ;
        RECT 0 153.8 2 156.3 ;
    END
    PORT
      LAYER M4 ;
        RECT 73 153.8 75 156.3 ;
    END
    PORT
      LAYER M5 ;
        RECT 0 153.8 1.585 156.3 ;
    END
    PORT
      LAYER M5 ;
        RECT 73.415 153.8 75 156.3 ;
    END
  END vdd
  PIN vddh
    DIRECTION INOUT ;
    USE POWER ;
    PORT
      LAYER M3 ;
        RECT 74.4 137.66 75 150.47 ;
    END
    PORT
      LAYER M3 ;
        RECT 0 137.66 0.6 150.47 ;
    END
    PORT
      LAYER M3 ;
        RECT 73.72 95.54 75 120.85 ;
    END
    PORT
      LAYER M3 ;
        RECT 0 95.54 1.28 120.85 ;
    END
    PORT
      LAYER M3 ;
        RECT 0 66.96 1.28 92.24 ;
    END
    PORT
      LAYER M3 ;
        RECT 73.72 66.96 75 92.24 ;
    END
    PORT
      LAYER M3 ;
        RECT 0 53.99 1.28 57.99 ;
    END
    PORT
      LAYER M3 ;
        RECT 73.72 53.99 75 57.99 ;
    END
    PORT
      LAYER M4 ;
        RECT 0 130.82 2 134.32 ;
    END
    PORT
      LAYER M4 ;
        RECT 73 130.82 75 134.32 ;
    END
    PORT
      LAYER M5 ;
        RECT 0 130.82 1.585 134.32 ;
    END
    PORT
      LAYER M5 ;
        RECT 73.415 130.82 75 134.32 ;
    END
  END vddh
  PIN vssh
    DIRECTION INOUT ;
    USE GROUND ;
    PORT
      LAYER M3 ;
        RECT 73.72 31.95 75 50.69 ;
    END
    PORT
      LAYER M3 ;
        RECT 0 31.95 1.28 50.69 ;
    END
    PORT
      LAYER M3 ;
        RECT 0 9.91 1.28 28.65 ;
    END
    PORT
      LAYER M3 ;
        RECT 73.72 9.91 75 28.65 ;
    END
    PORT
      LAYER M4 ;
        RECT 73 148.13 75 152.13 ;
    END
    PORT
      LAYER M4 ;
        RECT 0 148.13 2 152.13 ;
    END
    PORT
      LAYER M4 ;
        RECT 0 124.15 2 129.15 ;
    END
    PORT
      LAYER M4 ;
        RECT 73 124.15 75 129.15 ;
    END
    PORT
      LAYER M5 ;
        RECT 73.415 148.13 75 152.13 ;
    END
    PORT
      LAYER M5 ;
        RECT 0 148.13 1.585 152.13 ;
    END
    PORT
      LAYER M5 ;
        RECT 0 124.15 1.585 129.15 ;
    END
    PORT
      LAYER M5 ;
        RECT 73.415 124.15 75 129.15 ;
    END
  END vssh
  OBS
    LAYER GATE ;
      RECT 0 0 75 162 ;
    LAYER MV1 ;
      RECT 0 0 75 162 ;
    LAYER MV2 ;
      RECT 0 0 75 162 ;
    LAYER MV3 ;
      RECT 0 0 75 162 ;
    LAYER MV4 ;
      RECT 0 0 75 162 ;
    LAYER M1 ;
      RECT 0 0 75 162 ;
    LAYER M2 ;
      RECT 0 0 75 160.55 ;
      RECT 11.01 160.55 16.67 162 ;
      RECT 17.65 160.55 18.21 162 ;
      RECT 19.19 160.55 19.92 162 ;
      RECT 20.9 160.55 21.46 162 ;
      RECT 22.44 160.55 23.11 162 ;
      RECT 24.09 160.55 28.19 162 ;
      RECT 29.17 160.55 30.71 162 ;
      RECT 31.69 160.55 32.25 162 ;
      RECT 33.23 160.55 40.49 162 ;
      RECT 41.47 160.55 44.29 162 ;
      RECT 45.27 160.55 62.56 162 ;
      RECT 63.54 160.55 75 162 ;
    LAYER M3 ;
      RECT 7.2 160.55 10.03 160.61 ;
    LAYER M2 ;
      RECT 7.2 160.55 10.03 162 ;
    LAYER M3 ;
      RECT 11.01 160.55 16.67 162 ;
      RECT 17.65 160.55 18.21 162 ;
      RECT 19.19 160.55 19.92 162 ;
      RECT 20.9 160.55 21.46 162 ;
      RECT 22.44 160.55 23.11 162 ;
      RECT 24.09 160.55 28.19 162 ;
      RECT 29.17 160.55 30.71 162 ;
      RECT 31.69 160.55 32.25 162 ;
      RECT 33.23 160.55 40.49 162 ;
      RECT 41.47 160.55 44.29 162 ;
      RECT 45.27 160.55 62.56 162 ;
      RECT 1.825 157.73 73.175 160.55 ;
      RECT 63.54 160.61 75 162 ;
      RECT 63.54 160.55 73.175 160.61 ;
      RECT 1.88 94.94 73.12 121.45 ;
      RECT 1.88 31.35 73.12 51.29 ;
      RECT 1.88 9.31 73.12 29.25 ;
      RECT 1.88 66.36 73.12 92.84 ;
      RECT 0 151.07 75 157.73 ;
      RECT 1.52 128.86 73.48 130.24 ;
      RECT 1.52 59.42 73.48 63.9 ;
      RECT 1.52 53.75 73.48 58.23 ;
      RECT 0 130.24 75 137.06 ;
      RECT 1.2 137.06 73.8 151.07 ;
      RECT 0 121.45 75 128.86 ;
      RECT 0 92.84 75 94.94 ;
      RECT 0 58.23 75 59.42 ;
      RECT 0 63.9 75 66.36 ;
      RECT 0 51.29 75 53.75 ;
      RECT 0 29.25 75 31.35 ;
      RECT 0 0 75 9.31 ;
    LAYER M4 ;
      RECT 0 0 75 123.91 ;
      RECT 0 129.39 75 130.58 ;
      RECT 2.24 123.91 72.76 129.39 ;
      RECT 2.6 135.39 72.4 147.06 ;
      RECT 0 134.56 75 135.39 ;
      RECT 2.24 130.58 72.76 134.56 ;
      RECT 0 147.06 75 147.89 ;
      RECT 0 152.37 75 153.56 ;
      RECT 2.24 147.89 72.76 152.37 ;
      RECT 0 156.54 75 157.73 ;
      RECT 2.24 153.56 72.76 156.54 ;
      RECT 0 160.71 75 162 ;
      RECT 1.825 157.73 73.175 160.71 ;
    LAYER M5 ;
      RECT 0 9.9 3.9 111.1 ;
      RECT 71.1 9.9 75 111.1 ;
      RECT 0 0 75 9.9 ;
      RECT 0 111.1 75 123.69 ;
      RECT 0 129.61 75 130.36 ;
      RECT 2.045 123.69 72.955 129.61 ;
      RECT 2.185 135.39 72.815 147.06 ;
      RECT 0 134.78 75 135.39 ;
      RECT 2.045 130.36 72.955 134.78 ;
      RECT 0 147.06 75 147.67 ;
      RECT 0 152.59 75 153.34 ;
      RECT 2.045 147.67 72.955 152.59 ;
      RECT 0 156.76 75 157.51 ;
      RECT 2.045 153.34 72.955 156.76 ;
      RECT 0 160.93 75 162 ;
      RECT 2.045 157.51 72.955 160.93 ;
    LAYER M3 ;
      RECT 7.2 160.61 10.03 162 ;
      RECT 0 160.61 5.82 162 ;
      RECT 1.825 160.55 5.82 160.61 ;
    LAYER M2 ;
      RECT 0 160.55 5.82 162 ;
  END
END RCMCU_PLBMUX


#MACRO RCMCU_PLBMUX
# CLASS PAD ;
# FOREIGN RCMCU_PLBMUX ;
# ORIGIN 0 0 ;
# SIZE 75 BY 162 ;
# SYMMETRY X Y R90 ;
# PIN A
# USE SIGNAL ;
# DIRECTION INPUT ;
# PORT
# LAYER M3 ;
# RECT 32.49 160.79 32.99 162 ;
# END
# PORT
# LAYER M2 ;
# RECT 32.49 160.79 32.99 162 ;
# END
# PORT
# LAYER MV2 ;
# RECT 32.645 160.885 32.835 161.075 ;
# RECT 32.645 161.405 32.835 161.595 ;
# END
# END A
# PIN CS
# USE SIGNAL ;
# DIRECTION INPUT ;
# PORT
# LAYER M3 ;
# RECT 44.53 160.79 45.03 162 ;
# END
# PORT
# LAYER M2 ;
# RECT 44.53 160.79 45.03 162 ;
# END
# PORT
# LAYER MV2 ;
# RECT 44.685 161.405 44.875 161.595 ;
# RECT 44.685 160.885 44.875 161.075 ;
# END
# END CS
# PIN DR
# USE SIGNAL ;
# DIRECTION INPUT ;
# PORT
# LAYER M3 ;
# RECT 23.35 160.79 23.85 162 ;
# END
# PORT
# LAYER M2 ;
# RECT 23.35 160.79 23.85 162 ;
# END
# PORT
# LAYER MV2 ;
# RECT 23.505 160.885 23.695 161.075 ;
# RECT 23.505 161.405 23.695 161.595 ;
# END
# END DR
# PIN IE
# USE SIGNAL ;
# DIRECTION INPUT ;
# PORT
# LAYER M3 ;
# RECT 40.73 160.79 41.23 162 ;
# END
# PORT
# LAYER M2 ;
# RECT 40.73 160.79 41.23 162 ;
# END
# PORT
# LAYER MV2 ;
# RECT 40.885 161.405 41.075 161.595 ;
# RECT 40.885 160.885 41.075 161.075 ;
# END
# END IE
# PIN OD
# USE SIGNAL ;
# DIRECTION INPUT ;
# PORT
# LAYER M3 ;
# RECT 28.43 160.79 28.93 162 ;
# END
# PORT
# LAYER M2 ;
# RECT 28.43 160.79 28.93 162 ;
# END
# PORT
# LAYER MV2 ;
# RECT 28.585 161.405 28.775 161.595 ;
# RECT 28.585 160.885 28.775 161.075 ;
# END
# END OD
# PIN OE
# USE SIGNAL ;
# DIRECTION INPUT ;
# PORT
# LAYER M3 ;
# RECT 30.95 160.79 31.45 162 ;
# END
# PORT
# LAYER M2 ;
# RECT 30.95 160.79 31.45 162 ;
# END
# PORT
# LAYER MV2 ;
# RECT 31.105 161.405 31.295 161.595 ;
# RECT 31.105 160.885 31.295 161.075 ;
# END
# END OE
# PIN OS
# USE SIGNAL ;
# DIRECTION INPUT ;
# PORT
# LAYER M3 ;
# RECT 21.7 160.79 22.2 162 ;
# END
# PORT
# LAYER M2 ;
# RECT 21.7 160.79 22.2 162 ;
# END
# PORT
# LAYER MV2 ;
# RECT 21.855 160.885 22.045 161.075 ;
# RECT 21.855 161.405 22.045 161.595 ;
# END
# END OS
# PIN P
# USE SIGNAL ;
# DIRECTION INOUT ;
# PORT
# LAYER M5 ;
# RECT 4.5 10.5 70.5 110.5 ;
# END
# END P
# PIN PD
# USE SIGNAL ;
# DIRECTION INPUT ;
# PORT
# LAYER M3 ;
# RECT 16.91 160.79 17.41 162 ;
# END
# PORT
# LAYER M2 ;
# RECT 16.91 160.79 17.41 162 ;
# END
# PORT
# LAYER MV2 ;
# RECT 17.065 160.885 17.255 161.075 ;
# RECT 17.065 161.405 17.255 161.595 ;
# END
# END PD
# PIN POC
# USE POWER ;
# DIRECTION INOUT ;
# PORT
# LAYER M3 ;
# RECT 73.72 129.1 75 130 ;
# END
# PORT
# LAYER M3 ;
# RECT 0 129.1 1.28 130 ;
# END
# END POC
# PIN PU
# USE SIGNAL ;
# DIRECTION INPUT ;
# PORT
# LAYER M3 ;
# RECT 18.45 160.79 18.95 162 ;
# END
# PORT
# LAYER M2 ;
# RECT 18.45 160.79 18.95 162 ;
# END
# PORT
# LAYER MV2 ;
# RECT 18.605 161.405 18.795 161.595 ;
# RECT 18.605 160.885 18.795 161.075 ;
# END
# END PU
# PIN SR
# USE SIGNAL ;
# DIRECTION INPUT ;
# PORT
# LAYER M3 ;
# RECT 20.16 160.79 20.66 162 ;
# END
# PORT
# LAYER M2 ;
# RECT 20.16 160.79 20.66 162 ;
# END
# PORT
# LAYER MV2 ;
# RECT 20.315 160.885 20.505 161.075 ;
# RECT 20.315 161.405 20.505 161.595 ;
# END
# END SR
# PIN Y
# USE SIGNAL ;
# DIRECTION OUTPUT ;
# PORT
# LAYER M3 ;
# RECT 62.8 160.79 63.3 162 ;
# END
# PORT
# LAYER M2 ;
# RECT 62.8 160.79 63.3 162 ;
# END
# PORT
# LAYER MV2 ;
# RECT 62.955 161.405 63.145 161.595 ;
# RECT 62.955 160.885 63.145 161.075 ;
# END
# END Y
# PIN YA
# USE SIGNAL ;
# DIRECTION INOUT ;
# PORT
# LAYER M3 ;
# RECT 10.27 160.79 10.77 162 ;
# END
# PORT
# LAYER M2 ;
# RECT 10.27 160.79 10.77 162 ;
# END
# PORT
# LAYER MV2 ;
# RECT 10.425 160.885 10.615 161.075 ;
# RECT 10.425 161.405 10.615 161.595 ;
# END
# END YA
# PIN gnd
# USE GROUND ;
# DIRECTION INOUT ;
# PORT
# LAYER M5 ;
# RECT 73.415 135.99 75 146.46 ;
# END
# PORT
# LAYER M5 ;
# RECT 0 135.99 1.585 146.46 ;
# END
# PORT
# LAYER M5 ;
# RECT 0 157.97 1.585 160.47 ;
# END
# PORT
# LAYER M5 ;
# RECT 73.415 157.97 75 160.47 ;
# END
# PORT
# LAYER M4 ;
# RECT 73 135.99 75 146.46 ;
# END
# PORT
# LAYER M4 ;
# RECT 0 135.99 2 146.46 ;
# END
# PORT
# LAYER M4 ;
# RECT 0 157.97 1.585 160.47 ;
# END
# PORT
# LAYER M4 ;
# RECT 73.415 157.97 75 160.47 ;
# END
# PORT
# LAYER M3 ;
# RECT 73.72 59.66 75 63.66 ;
# END
# PORT
# LAYER M3 ;
# RECT 0 59.66 1.28 63.66 ;
# END
# PORT
# LAYER M3 ;
# RECT 0 157.97 1.585 160.37 ;
# END
# PORT
# LAYER M3 ;
# RECT 73.415 157.97 75 160.37 ;
# END
# PORT
# LAYER MV3 ;
# RECT 73.6 158.44 73.79 158.63 ;
# RECT 74.21 158.44 74.4 158.63 ;
# RECT 73.6 159.05 73.79 159.24 ;
# RECT 74.21 159.05 74.4 159.24 ;
# RECT 73.6 159.66 73.79 159.85 ;
# RECT 74.21 159.66 74.4 159.85 ;
# RECT 0.6 158.44 0.79 158.63 ;
# RECT 1.21 158.44 1.4 158.63 ;
# RECT 0.6 159.05 0.79 159.24 ;
# RECT 1.21 159.05 1.4 159.24 ;
# RECT 0.6 159.66 0.79 159.85 ;
# RECT 1.21 159.66 1.4 159.85 ;
# END
# END gnd
# PIN vdd
# USE POWER ;
# DIRECTION INOUT ;
# PORT
# LAYER M5 ;
# RECT 73.415 153.8 75 156.3 ;
# END
# PORT
# LAYER M5 ;
# RECT 0 153.8 1.585 156.3 ;
# END
# PORT
# LAYER M4 ;
# RECT 73 153.8 75 156.3 ;
# END
# PORT
# LAYER M4 ;
# RECT 0 153.8 2 156.3 ;
# END
# END vdd
# PIN vddh
# USE POWER ;
# DIRECTION INOUT ;
# PORT
# LAYER M5 ;
# RECT 73.415 130.82 75 134.32 ;
# END
# PORT
# LAYER M5 ;
# RECT 0 130.82 1.585 134.32 ;
# END
# PORT
# LAYER M4 ;
# RECT 73 130.82 75 134.32 ;
# END
# PORT
# LAYER M4 ;
# RECT 0 130.82 2 134.32 ;
# END
# PORT
# LAYER M3 ;
# RECT 73.72 53.99 75 57.99 ;
# END
# PORT
# LAYER M3 ;
# RECT 0 53.99 1.28 57.99 ;
# END
# PORT
# LAYER M3 ;
# RECT 73.72 66.96 75 92.24 ;
# END
# PORT
# LAYER M3 ;
# RECT 0 66.96 1.28 92.24 ;
# END
# PORT
# LAYER M3 ;
# RECT 0 95.54 1.28 120.85 ;
# END
# PORT
# LAYER M3 ;
# RECT 73.72 95.54 75 120.85 ;
# END
# PORT
# LAYER M3 ;
# RECT 0 137.66 0.6 150.47 ;
# END
# PORT
# LAYER M3 ;
# RECT 74.4 137.66 75 150.47 ;
# END
# END vddh
# PIN vssh
# USE GROUND ;
# DIRECTION INOUT ;
# PORT
# LAYER M5 ;
# RECT 73.415 124.15 75 129.15 ;
# END
# PORT
# LAYER M5 ;
# RECT 0 124.15 1.585 129.15 ;
# END
# PORT
# LAYER M5 ;
# RECT 0 148.13 1.585 152.13 ;
# END
# PORT
# LAYER M5 ;
# RECT 73.415 148.13 75 152.13 ;
# END
# PORT
# LAYER M4 ;
# RECT 73 124.15 75 129.15 ;
# END
# PORT
# LAYER M4 ;
# RECT 0 124.15 2 129.15 ;
# END
# PORT
# LAYER M4 ;
# RECT 0 148.13 2 152.13 ;
# END
# PORT
# LAYER M4 ;
# RECT 73 148.13 75 152.13 ;
# END
# PORT
# LAYER M3 ;
# RECT 73.72 9.91 75 28.65 ;
# END
# PORT
# LAYER M3 ;
# RECT 0 9.91 1.28 28.65 ;
# END
# PORT
# LAYER M3 ;
# RECT 0 31.95 1.28 50.69 ;
# END
# PORT
# LAYER M3 ;
# RECT 73.72 31.95 75 50.69 ;
# END
# END vssh
# OBS
# LAYER GATE ;
# RECT 0 0 75 162 ;
# LAYER MV1 ;
# RECT 0 0 75 162 ;
# LAYER MV2 ;
# RECT 0 0 75 162 ;
# LAYER MV3 ;
# RECT 0 0 75 162 ;
# LAYER MV4 ;
# RECT 0 0 75 162 ;
# LAYER M1 ;
# RECT 0 0 75 162 ;
# LAYER M2 ;
# RECT 0 0 75 160.55 ;
# RECT 11.01 160.55 16.67 162 ;
# RECT 0 160.55 10.03 162 ;
# RECT 17.65 160.55 18.21 162 ;
# RECT 19.19 160.55 19.92 162 ;
# RECT 20.9 160.55 21.46 162 ;
# RECT 22.44 160.55 23.11 162 ;
# RECT 24.09 160.55 28.19 162 ;
# RECT 29.17 160.55 30.71 162 ;
# RECT 31.69 160.55 32.25 162 ;
# RECT 33.23 160.55 40.49 162 ;
# RECT 41.47 160.55 44.29 162 ;
# RECT 45.27 160.55 62.56 162 ;
# RECT 63.54 160.55 75 162 ;
# LAYER M3 ;
# RECT 0 160.61 10.03 162 ;
# RECT 1.825 160.55 10.03 160.61 ;
# RECT 11.01 160.55 16.67 162 ;
# RECT 17.65 160.55 18.21 162 ;
# RECT 19.19 160.55 19.92 162 ;
# RECT 20.9 160.55 21.46 162 ;
# RECT 22.44 160.55 23.11 162 ;
# RECT 24.09 160.55 28.19 162 ;
# RECT 29.17 160.55 30.71 162 ;
# RECT 31.69 160.55 32.25 162 ;
# RECT 33.23 160.55 40.49 162 ;
# RECT 41.47 160.55 44.29 162 ;
# RECT 45.27 160.55 62.56 162 ;
# RECT 1.825 157.73 73.175 160.55 ;
# RECT 63.54 160.61 75 162 ;
# RECT 63.54 160.55 73.175 160.61 ;
# RECT 1.88 94.94 73.12 121.45 ;
# RECT 1.88 31.35 73.12 51.29 ;
# RECT 1.88 9.31 73.12 29.25 ;
# RECT 1.88 66.36 73.12 92.84 ;
# RECT 0 151.07 75 157.73 ;
# RECT 1.52 128.86 73.48 130.24 ;
# RECT 1.52 59.42 73.48 63.9 ;
# RECT 1.52 53.75 73.48 58.23 ;
# RECT 0 130.24 75 137.06 ;
# RECT 1.2 137.06 73.8 151.07 ;
# RECT 0 121.45 75 128.86 ;
# RECT 0 92.84 75 94.94 ;
# RECT 0 58.23 75 59.42 ;
# RECT 0 63.9 75 66.36 ;
# RECT 0 51.29 75 53.75 ;
# RECT 0 29.25 75 31.35 ;
# RECT 0 0 75 9.31 ;
# LAYER M4 ;
# RECT 0 0 75 123.91 ;
# RECT 0 129.39 75 130.58 ;
# RECT 2.24 123.91 72.76 129.39 ;
# RECT 2.6 135.39 72.4 147.06 ;
# RECT 0 134.56 75 135.39 ;
# RECT 2.24 130.58 72.76 134.56 ;
# RECT 0 147.06 75 147.89 ;
# RECT 0 152.37 75 153.56 ;
# RECT 2.24 147.89 72.76 152.37 ;
# RECT 0 156.54 75 157.73 ;
# RECT 2.24 153.56 72.76 156.54 ;
# RECT 0 160.71 75 162 ;
# RECT 1.825 157.73 73.175 160.71 ;
# LAYER M5 ;
# RECT 0 9.9 3.9 111.1 ;
# RECT 71.1 9.9 75 111.1 ;
# RECT 0 0 75 9.9 ;
# RECT 0 111.1 75 123.69 ;
# RECT 0 129.61 75 130.36 ;
# RECT 2.045 123.69 72.955 129.61 ;
# RECT 2.185 135.39 72.815 147.06 ;
# RECT 0 134.78 75 135.39 ;
# RECT 2.045 130.36 72.955 134.78 ;
# RECT 0 147.06 75 147.67 ;
# RECT 0 152.59 75 153.34 ;
# RECT 2.045 147.67 72.955 152.59 ;
# RECT 0 156.76 75 157.51 ;
# RECT 2.045 153.34 72.955 156.76 ;
# RECT 0 160.93 75 162 ;
# RECT 2.045 157.51 72.955 160.93 ;
# END
#END RCMCU_PLBMUX

MACRO RCMCU_PLCORNER
 CLASS PAD SPACER ;
 FOREIGN RCMCU_PLCORNER ;
 ORIGIN 0 0 ;
 SIZE 162 BY 162 ;
 SYMMETRY X Y R90 ;
 PIN POC
 USE POWER ;
 DIRECTION INOUT ;
 PORT
 LAYER M3 ;
 RECT 160.72 129.1 162 130 ;
 END
 PORT
 LAYER M3 ;
 RECT 129.1 160.72 130 162 ;
 END
 END POC
 PIN gnd
 USE GROUND ;
 DIRECTION INOUT ;
 PORT
 LAYER M5 ;
 RECT 160.415 135.99 162 146.46 ;
 END
 PORT
 LAYER M5 ;
 RECT 157.97 160.47 160.47 162 ;
 RECT 157.97 160.415 162 160.47 ;
 RECT 160.415 157.97 162 160.415 ;
 END
 PORT
 LAYER M5 ;
 RECT 135.99 160.415 146.46 162 ;
 END
 PORT
 LAYER M4 ;
 RECT 160 135.99 162 146.46 ;
 END
 PORT
 LAYER M4 ;
 RECT 157.97 160.47 160.47 162 ;
 RECT 157.97 160 162 160.47 ;
 RECT 160 157.97 162 160 ;
 END
 PORT
 LAYER M4 ;
 RECT 135.99 160 146.46 162 ;
 END
 PORT
 LAYER M3 ;
 RECT 160.72 59.66 162 63.66 ;
 END
 PORT
 LAYER M3 ;
 RECT 59.66 160.72 63.66 162 ;
 END
 PORT
 LAYER MV4 ;
 RECT 161.27 136.095 161.63 136.455 ;
 RECT 160.415 136.095 160.73 136.455 ;
 RECT 160.415 136.995 160.73 137.355 ;
 RECT 161.27 136.995 161.63 137.355 ;
 RECT 160.415 137.895 160.73 138.255 ;
 RECT 161.27 137.895 161.63 138.255 ;
 RECT 160.415 138.795 160.73 139.155 ;
 RECT 161.27 138.795 161.63 139.155 ;
 RECT 160.415 139.695 160.73 140.055 ;
 RECT 161.27 139.695 161.63 140.055 ;
 RECT 160.415 140.595 160.73 140.955 ;
 RECT 161.27 140.595 161.63 140.955 ;
 RECT 160.415 141.495 160.73 141.855 ;
 RECT 161.27 141.495 161.63 141.855 ;
 RECT 160.415 142.395 160.73 142.755 ;
 RECT 161.27 142.395 161.63 142.755 ;
 RECT 160.415 143.295 160.73 143.655 ;
 RECT 161.27 143.295 161.63 143.655 ;
 RECT 160.415 144.195 160.73 144.555 ;
 RECT 161.27 144.195 161.63 144.555 ;
 RECT 161.27 145.095 161.63 145.455 ;
 RECT 160.415 145.095 160.73 145.455 ;
 RECT 160.415 145.995 160.73 146.355 ;
 RECT 161.27 145.995 161.63 146.355 ;
 RECT 160.415 158.14 160.73 158.5 ;
 RECT 161.27 158.14 161.63 158.5 ;
 RECT 160.415 159.04 160.73 159.4 ;
 RECT 161.27 159.04 161.63 159.4 ;
 RECT 161.27 159.94 161.63 160.3 ;
 RECT 160.415 159.94 160.73 160.3 ;
 RECT 141.805 160.415 142.165 160.665 ;
 RECT 142.705 160.415 143.065 160.665 ;
 RECT 143.605 160.415 143.965 160.665 ;
 RECT 140.905 160.415 141.265 160.665 ;
 RECT 140.005 160.415 140.365 160.665 ;
 RECT 139.105 160.415 139.465 160.665 ;
 RECT 138.205 160.415 138.565 160.665 ;
 RECT 137.305 160.415 137.665 160.665 ;
 RECT 136.405 160.415 136.765 160.665 ;
 RECT 158.445 160.515 158.805 160.875 ;
 RECT 144.835 160.565 145.195 160.925 ;
 RECT 145.735 160.565 146.095 160.925 ;
 END
 END gnd
 PIN vdd
 USE POWER ;
 DIRECTION INOUT ;
 PORT
 LAYER M5 ;
 RECT 160.415 153.8 162 156.3 ;
 END
 PORT
 LAYER M5 ;
 RECT 153.8 160.415 156.3 162 ;
 END
 PORT
 LAYER M4 ;
 RECT 160 153.8 162 156.3 ;
 END
 PORT
 LAYER M4 ;
 RECT 153.8 160 156.3 162 ;
 END
 PORT
 LAYER MV4 ;
 RECT 161.27 155.77 161.63 156.13 ;
 RECT 160.415 155.77 160.73 156.13 ;
 RECT 161.27 154.87 161.63 155.23 ;
 RECT 160.415 154.87 160.73 155.23 ;
 RECT 161.27 153.97 161.63 154.33 ;
 RECT 160.415 153.97 160.73 154.33 ;
 RECT 155.77 160.415 156.13 160.76 ;
 RECT 154.87 160.415 155.23 160.76 ;
 RECT 153.97 160.415 154.33 160.76 ;
 END
 END vdd
 PIN vddh
 USE POWER ;
 DIRECTION INOUT ;
 PORT
 LAYER M5 ;
 RECT 160.415 130.82 162 134.32 ;
 END
 PORT
 LAYER M5 ;
 RECT 130.82 160.415 134.32 162 ;
 END
 PORT
 LAYER M4 ;
 RECT 160 130.82 162 134.32 ;
 END
 PORT
 LAYER M4 ;
 RECT 130.82 160 134.32 162 ;
 END
 PORT
 LAYER M3 ;
 RECT 160.72 54.39 162 57.99 ;
 END
 PORT
 LAYER M3 ;
 RECT 160.72 66.96 162 92.24 ;
 END
 PORT
 LAYER M3 ;
 RECT 160.72 95.54 162 120.85 ;
 END
 PORT
 LAYER M3 ;
 RECT 161.4 137.66 162 150.47 ;
 END
 PORT
 LAYER M3 ;
 RECT 66.96 160.72 92.24 162 ;
 END
 PORT
 LAYER M3 ;
 RECT 95.54 160.72 120.85 162 ;
 END
 PORT
 LAYER M3 ;
 RECT 53.99 160.72 57.99 162 ;
 END
 PORT
 LAYER M3 ;
 RECT 137.66 161.4 150.47 162 ;
 END
 PORT
 LAYER MV4 ;
 RECT 160.415 131.94 160.73 132.3 ;
 RECT 161.27 131.94 161.63 132.3 ;
 RECT 160.415 132.84 160.73 133.2 ;
 RECT 161.27 132.84 161.63 133.2 ;
 RECT 160.415 133.74 160.73 134.1 ;
 RECT 161.27 133.74 161.63 134.1 ;
 RECT 160.415 131.04 160.73 131.4 ;
 RECT 161.27 131.04 161.63 131.4 ;
 RECT 131.94 160.645 132.3 161.005 ;
 RECT 133.74 160.645 134.1 161.005 ;
 RECT 132.84 160.645 133.2 161.005 ;
 RECT 131.04 160.645 131.4 161.005 ;
 END
 END vddh
 PIN vssh
 USE GROUND ;
 DIRECTION INOUT ;
 PORT
 LAYER M5 ;
 RECT 160.415 124.15 162 129.15 ;
 END
 PORT
 LAYER M5 ;
 RECT 160.415 148.13 162 152.13 ;
 END
 PORT
 LAYER M5 ;
 RECT 148.13 160.415 152.13 162 ;
 END
 PORT
 LAYER M5 ;
 RECT 124.15 160.415 129.15 162 ;
 END
 PORT
 LAYER M4 ;
 RECT 160 124.15 162 129.15 ;
 END
 PORT
 LAYER M4 ;
 RECT 160 148.13 162 152.13 ;
 END
 PORT
 LAYER M4 ;
 RECT 148.13 160 152.13 162 ;
 END
 PORT
 LAYER M4 ;
 RECT 124.15 160 129.15 162 ;
 END
 PORT
 LAYER M3 ;
 RECT 160.72 9.91 162 28.65 ;
 END
 PORT
 LAYER M3 ;
 RECT 160.72 31.95 162 50.69 ;
 END
 PORT
 LAYER M3 ;
 RECT 31.95 160.72 50.69 162 ;
 END
 PORT
 LAYER M3 ;
 RECT 9.91 160.72 28.65 162 ;
 END
 PORT
 LAYER MV4 ;
 RECT 160.415 124.67 160.73 125.03 ;
 RECT 161.27 124.67 161.63 125.03 ;
 RECT 160.415 125.57 160.73 125.93 ;
 RECT 161.27 125.57 161.63 125.93 ;
 RECT 160.415 126.47 160.73 126.83 ;
 RECT 161.27 126.47 161.63 126.83 ;
 RECT 160.415 127.37 160.73 127.73 ;
 RECT 161.27 127.37 161.63 127.73 ;
 RECT 160.415 128.27 160.73 128.63 ;
 RECT 161.27 128.27 161.63 128.63 ;
 RECT 160.415 148.6 160.73 148.96 ;
 RECT 161.27 148.6 161.63 148.96 ;
 RECT 161.27 149.5 161.63 149.86 ;
 RECT 160.415 149.5 160.73 149.86 ;
 RECT 161.27 150.4 161.63 150.76 ;
 RECT 160.415 150.4 160.73 150.76 ;
 RECT 161.27 151.3 161.63 151.66 ;
 RECT 160.415 151.3 160.73 151.66 ;
 RECT 148.6 160.415 148.96 160.705 ;
 RECT 149.5 160.415 149.86 160.705 ;
 RECT 150.4 160.415 150.76 160.705 ;
 RECT 151.3 160.415 151.66 160.705 ;
 RECT 128.27 160.7 128.63 161.06 ;
 RECT 127.37 160.7 127.73 161.06 ;
 RECT 126.47 160.7 126.83 161.06 ;
 RECT 125.57 160.7 125.93 161.06 ;
 RECT 124.67 160.7 125.03 161.06 ;
 END
 END vssh
 OBS
 LAYER GATE ;
 RECT 0 0 162 162 ;
 LAYER MV1 ;
 RECT 0 0 162 162 ;
 LAYER MV2 ;
 RECT 0 0 162 162 ;
 LAYER MV3 ;
 RECT 0 0 162 162 ;
 LAYER MV4 ;
 RECT 0 0 162 162 ;
 LAYER M1 ;
 RECT 0 0 162 162 ;
 LAYER M2 ;
 RECT 0 0 162 162 ;
 LAYER M3 ;
 RECT 29.25 160.12 31.35 162 ;
 RECT 0 160.12 9.31 162 ;
 RECT 51.29 160.12 66.36 160.48 ;
 RECT 51.29 160.48 53.75 162 ;
 RECT 58.23 160.48 59.42 162 ;
 RECT 63.9 160.48 66.36 162 ;
 RECT 92.84 160.12 94.94 162 ;
 RECT 121.45 160.48 128.86 162 ;
 RECT 130.24 160.8 137.06 162 ;
 RECT 0 9.31 160.12 29.25 ;
 RECT 0 0 162 9.31 ;
 RECT 0 29.25 162 31.35 ;
 RECT 0 31.35 160.12 51.29 ;
 RECT 0 51.29 162 54.15 ;
 RECT 0 66.36 160.12 92.84 ;
 RECT 0 94.94 160.12 121.45 ;
 RECT 0 54.15 160.48 58.23 ;
 RECT 0 58.23 162 59.42 ;
 RECT 0 59.42 160.48 63.9 ;
 RECT 0 63.9 162 66.36 ;
 RECT 0 92.84 162 94.94 ;
 RECT 0 121.45 162 128.86 ;
 RECT 0 128.86 160.48 130.24 ;
 RECT 0 130.24 162 137.06 ;
 RECT 0 137.06 160.8 151.07 ;
 RECT 0 151.07 162 160.12 ;
 RECT 121.45 160.12 162 160.48 ;
 RECT 130.24 160.48 162 160.8 ;
 RECT 151.07 160.8 162 162 ;
 LAYER M4 ;
 RECT 134.56 159.76 135.39 162 ;
 RECT 147.06 159.76 147.89 162 ;
 RECT 152.37 159.76 153.56 162 ;
 RECT 0 157.73 159.76 159.4 ;
 RECT 147.06 159.4 159.76 159.76 ;
 RECT 0 156.54 162 157.73 ;
 RECT 160.71 160.71 162 162 ;
 RECT 0 123.91 159.76 129.39 ;
 RECT 0 0 162 123.91 ;
 RECT 0 129.39 162 130.58 ;
 RECT 0 130.58 159.76 134.56 ;
 RECT 0 134.56 162 135.39 ;
 RECT 0 147.06 162 147.89 ;
 RECT 0 147.89 159.76 152.37 ;
 RECT 0 152.37 162 153.56 ;
 RECT 0 153.56 159.76 156.54 ;
 RECT 156.54 159.76 157.73 162 ;
 RECT 0 135.39 159.4 147.06 ;
 RECT 0 159.4 135.39 159.76 ;
 RECT 129.39 159.76 130.58 162 ;
 RECT 0 159.76 123.91 162 ;
 LAYER M5 ;
 RECT 0 159.815 135.39 159.955 ;
 RECT 129.61 159.955 130.36 162 ;
 RECT 0 159.955 123.69 162 ;
 RECT 134.78 159.955 135.39 162 ;
 RECT 147.06 159.955 147.67 162 ;
 RECT 152.59 159.955 153.34 162 ;
 RECT 156.76 159.955 157.51 162 ;
 RECT 0 135.39 159.815 147.06 ;
 RECT 0 123.69 159.955 129.61 ;
 RECT 0 0 162 123.69 ;
 RECT 0 129.61 162 130.36 ;
 RECT 0 130.36 159.955 134.78 ;
 RECT 0 134.78 162 135.39 ;
 RECT 0 147.06 162 147.67 ;
 RECT 0 147.67 159.955 152.59 ;
 RECT 0 152.59 162 153.34 ;
 RECT 0 153.34 159.955 156.76 ;
 RECT 0 156.76 162 157.51 ;
 RECT 147.06 159.815 159.955 159.955 ;
 RECT 0 157.51 159.955 159.815 ;
 RECT 160.93 160.93 162 162 ;
 END
END RCMCU_PLCORNER

MACRO RCMCU_PLFLR1
 CLASS PAD SPACER ;
 FOREIGN RCMCU_PLFLR1 ;
 ORIGIN 0 0 ;
 SIZE 1 BY 162 ;
 SYMMETRY X Y R90 ;
 PIN POC
 USE POWER ;
 DIRECTION INOUT ;
 PORT
 LAYER M3 ;
 RECT 0 129.1 1 130 ;
 END
 END POC
 PIN gnd
 USE GROUND ;
 DIRECTION INOUT ;
 PORT
 LAYER M5 ;
 RECT 0 135.99 1 146.46 ;
 END
 PORT
 LAYER M5 ;
 RECT 0 157.97 1 160.47 ;
 END
 PORT
 LAYER M4 ;
 RECT 0 135.99 1 146.46 ;
 END
 PORT
 LAYER M4 ;
 RECT 0 157.97 1 160.47 ;
 END
 PORT
 LAYER M3 ;
 RECT 0 59.66 1 63.66 ;
 END
 PORT
 LAYER MV4 ;
 RECT 0.32 158.33 0.68 158.69 ;
 RECT 0.32 159.04 0.68 159.4 ;
 RECT 0.32 159.75 0.68 160.11 ;
 RECT 0.32 141.4 0.68 141.76 ;
 RECT 0.32 142.11 0.68 142.47 ;
 RECT 0.32 142.82 0.68 143.18 ;
 RECT 0.32 143.53 0.68 143.89 ;
 RECT 0.32 144.95 0.68 145.31 ;
 RECT 0.32 145.66 0.68 146.02 ;
 RECT 0.32 144.24 0.68 144.6 ;
 RECT 0.32 136.43 0.68 136.79 ;
 RECT 0.32 137.14 0.68 137.5 ;
 RECT 0.32 137.85 0.68 138.21 ;
 RECT 0.32 138.56 0.68 138.92 ;
 RECT 0.32 139.27 0.68 139.63 ;
 RECT 0.32 139.98 0.68 140.34 ;
 RECT 0.32 140.69 0.68 141.05 ;
 END
 END gnd
 PIN vdd
 USE POWER ;
 DIRECTION INOUT ;
 PORT
 LAYER M5 ;
 RECT 0 153.8 1 156.3 ;
 END
 PORT
 LAYER M4 ;
 RECT 0 153.8 1 156.3 ;
 END
 PORT
 LAYER MV4 ;
 RECT 0.32 154.16 0.68 154.52 ;
 RECT 0.32 154.87 0.68 155.23 ;
 RECT 0.32 155.58 0.68 155.94 ;
 END
 END vdd
 PIN vddh
 USE POWER ;
 DIRECTION INOUT ;
 PORT
 LAYER M5 ;
 RECT 0 130.82 1 134.32 ;
 END
 PORT
 LAYER M4 ;
 RECT 0 130.82 1 134.32 ;
 END
 PORT
 LAYER M3 ;
 RECT 0 53.99 1 57.99 ;
 END
 PORT
 LAYER M3 ;
 RECT 0 66.96 1 92.24 ;
 END
 PORT
 LAYER M3 ;
 RECT 0 95.54 1 120.85 ;
 END
 PORT
 LAYER M3 ;
 RECT 0 137.66 1 150.47 ;
 END
 PORT
 LAYER MV4 ;
 RECT 0.32 131.68 0.68 132.04 ;
 RECT 0.32 132.39 0.68 132.75 ;
 RECT 0.32 133.1 0.68 133.46 ;
 RECT 0.32 133.81 0.68 134.17 ;
 RECT 0.32 130.97 0.68 131.33 ;
 END
 END vddh
 PIN vssh
 USE GROUND ;
 DIRECTION INOUT ;
 PORT
 LAYER M5 ;
 RECT 0 124.15 1 129.15 ;
 END
 PORT
 LAYER M5 ;
 RECT 0 148.13 1 152.13 ;
 END
 PORT
 LAYER M4 ;
 RECT 0 124.15 1 129.15 ;
 END
 PORT
 LAYER M4 ;
 RECT 0 148.13 1 152.13 ;
 END
 PORT
 LAYER M3 ;
 RECT 0 9.91 1 28.65 ;
 END
 PORT
 LAYER M3 ;
 RECT 0 31.95 1 50.69 ;
 END
 PORT
 LAYER MV4 ;
 RECT 0.32 148.53 0.68 148.89 ;
 RECT 0.32 149.24 0.68 149.6 ;
 RECT 0.32 149.95 0.68 150.31 ;
 RECT 0.32 150.66 0.68 151.02 ;
 RECT 0.32 151.37 0.68 151.73 ;
 RECT 0.32 124.34 0.68 124.7 ;
 RECT 0.32 125.05 0.68 125.41 ;
 RECT 0.32 125.76 0.68 126.12 ;
 RECT 0.32 126.47 0.68 126.83 ;
 RECT 0.32 127.18 0.68 127.54 ;
 RECT 0.32 127.89 0.68 128.25 ;
 RECT 0.32 128.6 0.68 128.96 ;
 END
 END vssh
 OBS
 LAYER GATE ;
 RECT 0 0 1 162 ;
 LAYER MV1 ;
 RECT 0 0 1 162 ;
 LAYER MV2 ;
 RECT 0 0 1 162 ;
 LAYER MV3 ;
 RECT 0 0 1 162 ;
 LAYER MV4 ;
 RECT 0 0 1 162 ;
 LAYER M1 ;
 RECT 0 0 1 162 ;
 LAYER M2 ;
 RECT 0 0 1 162 ;
 LAYER M3 ;
 RECT 0 0 1 9.31 ;
 RECT 0 29.25 1 31.35 ;
 RECT 0 51.29 1 53.75 ;
 RECT 0 58.23 1 59.42 ;
 RECT 0 63.9 1 66.36 ;
 RECT 0 92.84 1 94.94 ;
 RECT 0 121.45 1 128.86 ;
 RECT 0 130.24 1 137.06 ;
 RECT 0 151.07 1 162 ;
 LAYER M4 ;
 RECT 0 0 1 123.91 ;
 RECT 0 129.39 1 130.58 ;
 RECT 0 134.56 1 135.39 ;
 RECT 0 147.06 1 147.89 ;
 RECT 0 152.37 1 153.56 ;
 RECT 0 156.54 1 157.73 ;
 RECT 0 160.71 1 162 ;
 LAYER M5 ;
 RECT 0 0 1 123.69 ;
 RECT 0 129.61 1 130.36 ;
 RECT 0 134.78 1 135.39 ;
 RECT 0 147.06 1 147.67 ;
 RECT 0 152.59 1 153.34 ;
 RECT 0 156.76 1 157.51 ;
 RECT 0 160.93 1 162 ;
 END
END RCMCU_PLFLR1

MACRO RCMCU_PLFLR5
 CLASS PAD SPACER ;
 FOREIGN RCMCU_PLFLR5 ;
 ORIGIN 0 0 ;
 SIZE 5 BY 162 ;
 SYMMETRY X Y R90 ;
 PIN POC
 USE POWER ;
 DIRECTION INOUT ;
 PORT
 LAYER M3 ;
 RECT 3.72 129.1 5 130 ;
 END
 PORT
 LAYER M3 ;
 RECT 0 129.1 1.28 130 ;
 END
 END POC
 PIN gnd
 USE GROUND ;
 DIRECTION INOUT ;
 PORT
 LAYER M5 ;
 RECT 3.415 135.99 5 146.46 ;
 END
 PORT
 LAYER M5 ;
 RECT 0 135.99 1.585 146.46 ;
 END
 PORT
 LAYER M5 ;
 RECT 0 157.97 1.585 160.47 ;
 END
 PORT
 LAYER M5 ;
 RECT 3.415 157.97 5 160.47 ;
 END
 PORT
 LAYER M4 ;
 RECT 3 135.99 5 146.46 ;
 END
 PORT
 LAYER M4 ;
 RECT 0 135.99 2 146.46 ;
 END
 PORT
 LAYER M4 ;
 RECT 0 157.97 2 160.47 ;
 END
 PORT
 LAYER M4 ;
 RECT 3 157.97 5 160.47 ;
 END
 PORT
 LAYER M3 ;
 RECT 3.72 59.66 5 63.66 ;
 END
 PORT
 LAYER M3 ;
 RECT 0 59.66 1.28 63.66 ;
 END
 PORT
 LAYER MV4 ;
 RECT 4.11 136.43 4.47 136.79 ;
 RECT 3.415 136.43 3.57 136.79 ;
 RECT 1.41 136.43 1.585 136.79 ;
 RECT 0.51 136.43 0.87 136.79 ;
 RECT 4.11 137.33 4.47 137.69 ;
 RECT 3.415 137.33 3.57 137.69 ;
 RECT 1.41 137.33 1.585 137.69 ;
 RECT 0.51 137.33 0.87 137.69 ;
 RECT 4.11 138.23 4.47 138.59 ;
 RECT 3.415 138.23 3.57 138.59 ;
 RECT 1.41 138.23 1.585 138.59 ;
 RECT 0.51 138.23 0.87 138.59 ;
 RECT 4.11 139.13 4.47 139.49 ;
 RECT 3.415 139.13 3.57 139.49 ;
 RECT 1.41 139.13 1.585 139.49 ;
 RECT 0.51 139.13 0.87 139.49 ;
 RECT 4.11 140.03 4.47 140.39 ;
 RECT 3.415 140.03 3.57 140.39 ;
 RECT 1.41 140.03 1.585 140.39 ;
 RECT 0.51 140.03 0.87 140.39 ;
 RECT 4.11 140.93 4.47 141.29 ;
 RECT 3.415 140.93 3.57 141.29 ;
 RECT 1.41 140.93 1.585 141.29 ;
 RECT 0.51 140.93 0.87 141.29 ;
 RECT 4.11 141.83 4.47 142.19 ;
 RECT 3.415 141.83 3.57 142.19 ;
 RECT 1.41 141.83 1.585 142.19 ;
 RECT 0.51 141.83 0.87 142.19 ;
 RECT 4.11 142.73 4.47 143.09 ;
 RECT 3.415 142.73 3.57 143.09 ;
 RECT 1.41 142.73 1.585 143.09 ;
 RECT 0.51 142.73 0.87 143.09 ;
 RECT 4.11 143.63 4.47 143.99 ;
 RECT 3.415 143.63 3.57 143.99 ;
 RECT 1.41 143.63 1.585 143.99 ;
 RECT 0.51 143.63 0.87 143.99 ;
 RECT 4.11 144.53 4.47 144.89 ;
 RECT 3.415 144.53 3.57 144.89 ;
 RECT 1.41 144.53 1.585 144.89 ;
 RECT 0.51 144.53 0.87 144.89 ;
 RECT 4.11 145.43 4.47 145.79 ;
 RECT 3.415 145.43 3.57 145.79 ;
 RECT 1.41 145.43 1.585 145.79 ;
 RECT 0.51 145.43 0.87 145.79 ;
 RECT 4.11 158.635 4.47 158.995 ;
 RECT 3.415 158.635 3.57 158.995 ;
 RECT 1.41 158.635 1.585 158.995 ;
 RECT 0.51 158.635 0.87 158.995 ;
 RECT 4.11 159.535 4.47 159.895 ;
 RECT 3.415 159.535 3.57 159.895 ;
 RECT 1.41 159.535 1.585 159.895 ;
 RECT 0.51 159.535 0.87 159.895 ;
 END
 END gnd
 PIN vdd
 USE POWER ;
 DIRECTION INOUT ;
 PORT
 LAYER M5 ;
 RECT 3.415 153.8 5 156.3 ;
 END
 PORT
 LAYER M5 ;
 RECT 0 153.8 1.585 156.3 ;
 END
 PORT
 LAYER M4 ;
 RECT 3 153.8 5 156.3 ;
 END
 PORT
 LAYER M4 ;
 RECT 0 153.8 2 156.3 ;
 END
 PORT
 LAYER MV4 ;
 RECT 4.11 155.375 4.47 155.735 ;
 RECT 4.11 154.475 4.47 154.835 ;
 RECT 3.415 155.375 3.57 155.735 ;
 RECT 3.415 154.475 3.57 154.835 ;
 RECT 1.41 155.375 1.585 155.735 ;
 RECT 1.41 154.475 1.585 154.835 ;
 RECT 0.51 155.375 0.87 155.735 ;
 RECT 0.51 154.475 0.87 154.835 ;
 END
 END vdd
 PIN vddh
 USE POWER ;
 DIRECTION INOUT ;
 PORT
 LAYER M5 ;
 RECT 3.415 130.82 5 134.32 ;
 END
 PORT
 LAYER M5 ;
 RECT 0 130.82 1.585 134.32 ;
 END
 PORT
 LAYER M4 ;
 RECT 3 130.82 5 134.32 ;
 END
 PORT
 LAYER M4 ;
 RECT 0 130.82 2 134.32 ;
 END
 PORT
 LAYER M3 ;
 RECT 3.72 53.99 5 57.99 ;
 END
 PORT
 LAYER M3 ;
 RECT 0 53.99 1.28 57.99 ;
 END
 PORT
 LAYER M3 ;
 RECT 3.72 66.96 5 92.24 ;
 END
 PORT
 LAYER M3 ;
 RECT 0 66.96 1.28 92.24 ;
 END
 PORT
 LAYER M3 ;
 RECT 0 95.54 1.28 120.85 ;
 END
 PORT
 LAYER M3 ;
 RECT 3.72 95.54 5 120.85 ;
 END
 PORT
 LAYER M3 ;
 RECT 0 137.67 0.6 150.47 ;
 END
 PORT
 LAYER M3 ;
 RECT 4.4 137.67 5 150.47 ;
 END
 PORT
 LAYER MV4 ;
 RECT 4.11 132.84 4.47 133.2 ;
 RECT 4.11 133.74 4.47 134.1 ;
 RECT 4.11 131.94 4.47 132.3 ;
 RECT 4.11 131.04 4.47 131.4 ;
 RECT 3.415 133.74 3.57 134.1 ;
 RECT 3.415 132.84 3.57 133.2 ;
 RECT 3.415 131.94 3.57 132.3 ;
 RECT 3.415 131.04 3.57 131.4 ;
 RECT 1.41 133.74 1.585 134.1 ;
 RECT 1.41 132.84 1.585 133.2 ;
 RECT 1.41 131.94 1.585 132.3 ;
 RECT 1.41 131.04 1.585 131.4 ;
 RECT 0.51 133.74 0.87 134.1 ;
 RECT 0.51 132.84 0.87 133.2 ;
 RECT 0.51 131.94 0.87 132.3 ;
 RECT 0.51 131.04 0.87 131.4 ;
 END
 END vddh
 PIN vssh
 USE GROUND ;
 DIRECTION INOUT ;
 PORT
 LAYER M5 ;
 RECT 3.415 124.15 5 129.15 ;
 END
 PORT
 LAYER M5 ;
 RECT 0 124.15 1.585 129.15 ;
 END
 PORT
 LAYER M5 ;
 RECT 0 148.13 1.585 152.13 ;
 END
 PORT
 LAYER M5 ;
 RECT 3.415 148.13 5 152.13 ;
 END
 PORT
 LAYER M4 ;
 RECT 3 124.15 5 129.15 ;
 END
 PORT
 LAYER M4 ;
 RECT 0 124.15 2 129.15 ;
 END
 PORT
 LAYER M4 ;
 RECT 0 148.13 2 152.13 ;
 END
 PORT
 LAYER M4 ;
 RECT 3 148.13 5 152.13 ;
 END
 PORT
 LAYER M3 ;
 RECT 3.72 9.91 5 28.65 ;
 END
 PORT
 LAYER M3 ;
 RECT 0 9.91 1.28 28.65 ;
 END
 PORT
 LAYER M3 ;
 RECT 0 31.95 1.28 50.69 ;
 END
 PORT
 LAYER M3 ;
 RECT 3.72 31.95 5 50.69 ;
 END
 PORT
 LAYER MV4 ;
 RECT 4.11 124.67 4.47 125.03 ;
 RECT 3.415 124.67 3.57 125.03 ;
 RECT 1.41 124.67 1.585 125.03 ;
 RECT 0.51 124.67 0.87 125.03 ;
 RECT 4.11 125.57 4.47 125.93 ;
 RECT 3.415 125.57 3.57 125.93 ;
 RECT 1.41 125.57 1.585 125.93 ;
 RECT 0.51 125.57 0.87 125.93 ;
 RECT 4.11 126.47 4.47 126.83 ;
 RECT 3.415 126.47 3.57 126.83 ;
 RECT 1.41 126.47 1.585 126.83 ;
 RECT 0.51 126.47 0.87 126.83 ;
 RECT 4.11 127.37 4.47 127.73 ;
 RECT 3.415 127.37 3.57 127.73 ;
 RECT 1.41 127.37 1.585 127.73 ;
 RECT 0.51 127.37 0.87 127.73 ;
 RECT 4.11 128.27 4.47 128.63 ;
 RECT 3.415 128.27 3.57 128.63 ;
 RECT 1.41 128.27 1.585 128.63 ;
 RECT 0.51 128.27 0.87 128.63 ;
 RECT 4.11 148.53 4.47 148.89 ;
 RECT 3.415 148.53 3.57 148.89 ;
 RECT 1.41 148.53 1.585 148.89 ;
 RECT 0.51 148.53 0.87 148.89 ;
 RECT 4.11 149.43 4.47 149.79 ;
 RECT 3.415 149.43 3.57 149.79 ;
 RECT 1.41 149.43 1.585 149.79 ;
 RECT 0.51 149.43 0.87 149.79 ;
 RECT 4.11 150.33 4.47 150.69 ;
 RECT 3.415 150.33 3.57 150.69 ;
 RECT 1.41 150.33 1.585 150.69 ;
 RECT 0.51 150.33 0.87 150.69 ;
 RECT 4.11 151.23 4.47 151.59 ;
 RECT 3.415 151.23 3.57 151.59 ;
 RECT 1.41 151.23 1.585 151.59 ;
 RECT 0.51 151.23 0.87 151.59 ;
 END
 END vssh
 OBS
 LAYER GATE ;
 RECT 0 0 5 162 ;
 LAYER MV1 ;
 RECT 0 0 5 162 ;
 LAYER MV2 ;
 RECT 0 0 5 162 ;
 LAYER MV3 ;
 RECT 0 0 5 162 ;
 LAYER MV4 ;
 RECT 0 0 5 162 ;
 LAYER M1 ;
 RECT 0 0 5 162 ;
 LAYER M2 ;
 RECT 0 0 5 162 ;
 LAYER M3 ;
 RECT 0 0 5 9.31 ;
 RECT 0 29.25 5 31.35 ;
 RECT 1.88 9.31 3.12 29.25 ;
 RECT 0 51.29 5 53.75 ;
 RECT 1.88 31.35 3.12 51.29 ;
 RECT 0 58.23 5 59.42 ;
 RECT 1.52 53.75 3.48 58.23 ;
 RECT 1.88 66.36 3.12 92.84 ;
 RECT 1.88 94.94 3.12 121.45 ;
 RECT 0 63.9 5 66.36 ;
 RECT 1.52 59.42 3.48 63.9 ;
 RECT 0 92.84 5 94.94 ;
 RECT 0 121.45 5 128.86 ;
 RECT 0 130.24 5 137.07 ;
 RECT 1.52 128.86 3.48 130.24 ;
 RECT 0 151.07 5 162 ;
 RECT 1.2 137.07 3.8 151.07 ;
 LAYER M4 ;
 RECT 0 160.71 5 162 ;
 RECT 2.24 157.73 2.76 160.71 ;
 RECT 0 0 5 123.91 ;
 RECT 0 129.39 5 130.58 ;
 RECT 2.24 123.91 2.76 129.39 ;
 RECT 0 134.56 5 135.39 ;
 RECT 2.24 130.58 2.76 134.56 ;
 RECT 0 147.06 5 147.89 ;
 RECT 0 152.37 5 153.56 ;
 RECT 2.24 147.89 2.76 152.37 ;
 RECT 0 156.54 5 157.73 ;
 RECT 2.24 153.56 2.76 156.54 ;
 LAYER M5 ;
 RECT 0 0 5 123.69 ;
 RECT 0 129.61 5 130.36 ;
 RECT 2.045 123.69 2.955 129.61 ;
 RECT 2.185 135.39 2.815 147.06 ;
 RECT 0 134.78 5 135.39 ;
 RECT 2.045 130.36 2.955 134.78 ;
 RECT 0 147.06 5 147.67 ;
 RECT 0 152.59 5 153.34 ;
 RECT 2.045 147.67 2.955 152.59 ;
 RECT 0 156.76 5 157.51 ;
 RECT 2.045 153.34 2.955 156.76 ;
 RECT 0 160.93 5 162 ;
 RECT 2.045 157.51 2.955 160.93 ;
 END
END RCMCU_PLFLR5

MACRO RCMCU_PLOSC
 CLASS PAD ;
 FOREIGN RCMCU_PLOSC ;
 ORIGIN 0 0 ;
 SIZE 175 BY 162 ;
 SYMMETRY X Y R90 ;
 PIN CLK
 USE SIGNAL ;
 DIRECTION OUTPUT ;
 PORT
 LAYER M3 ;
 RECT 26 160.79 26.5 162 ;
 END
 PORT
 LAYER M2 ;
 RECT 26 160.79 26.5 162 ;
 END
 PORT
 LAYER MV2 ;
 RECT 26.155 161.405 26.345 161.595 ;
 RECT 26.155 160.885 26.345 161.075 ;
 END
 END CLK
 PIN EI
 USE SIGNAL ;
 DIRECTION INPUT ;
 PORT
 LAYER M3 ;
 RECT 29.5 160.79 30 162 ;
 END
 PORT
 LAYER M2 ;
 RECT 29.5 160.79 30 162 ;
 END
 PORT
 LAYER MV2 ;
 RECT 29.655 161.405 29.845 161.595 ;
 RECT 29.655 160.885 29.845 161.075 ;
 END
 END EI
 PIN EO
 USE SIGNAL ;
 DIRECTION INPUT ;
 PORT
 LAYER M3 ;
 RECT 22.5 160.79 23 162 ;
 END
 PORT
 LAYER M2 ;
 RECT 22.5 160.79 23 162 ;
 END
 PORT
 LAYER MV2 ;
 RECT 22.655 161.405 22.845 161.595 ;
 RECT 22.655 160.885 22.845 161.075 ;
 END
 END EO
 PIN OSCIN
 USE SIGNAL ;
 DIRECTION INPUT ;
 PORT
 LAYER M5 ;
 RECT 104.5 10.5 170.5 110.5 ;
 END
 END OSCIN
 PIN OSCOUT
 USE SIGNAL ;
 DIRECTION OUTPUT ;
 PORT
 LAYER M5 ;
 RECT 4.5 10.5 70.5 110.5 ;
 END
 END OSCOUT
 PIN POC
 USE POWER ;
 DIRECTION INOUT ;
 PORT
 LAYER M3 ;
 RECT 173.72 129.1 175 130 ;
 END
 PORT
 LAYER M3 ;
 RECT 0 129.1 1.28 130 ;
 END
 END POC
 PIN gnd
 USE GROUND ;
 DIRECTION INOUT ;
 PORT
 LAYER M5 ;
 RECT 173.415 135.99 175 146.46 ;
 END
 PORT
 LAYER M5 ;
 RECT 0 135.99 1.585 146.46 ;
 END
 PORT
 LAYER M5 ;
 RECT 0 157.97 1.585 160.47 ;
 END
 PORT
 LAYER M5 ;
 RECT 173.415 157.97 175 160.47 ;
 END
 PORT
 LAYER M4 ;
 RECT 173 135.99 175 146.46 ;
 END
 PORT
 LAYER M4 ;
 RECT 0 135.99 2 146.46 ;
 END
 PORT
 LAYER M4 ;
 RECT 0 157.97 1.585 160.47 ;
 END
 PORT
 LAYER M4 ;
 RECT 173.415 157.97 175 160.47 ;
 END
 PORT
 LAYER M3 ;
 RECT 173.72 59.66 175 63.66 ;
 END
 PORT
 LAYER M3 ;
 RECT 0 59.66 1.28 63.66 ;
 END
 PORT
 LAYER M3 ;
 RECT 0 157.97 1.585 160.37 ;
 END
 PORT
 LAYER M3 ;
 RECT 173.415 157.97 175 160.37 ;
 END
 PORT
 LAYER MV3 ;
 RECT 173.6 158.44 173.79 158.63 ;
 RECT 174.21 158.44 174.4 158.63 ;
 RECT 173.6 159.05 173.79 159.24 ;
 RECT 174.21 159.05 174.4 159.24 ;
 RECT 173.6 159.66 173.79 159.85 ;
 RECT 174.21 159.66 174.4 159.85 ;
 RECT 0.6 158.44 0.79 158.63 ;
 RECT 1.21 158.44 1.4 158.63 ;
 RECT 0.6 159.05 0.79 159.24 ;
 RECT 1.21 159.05 1.4 159.24 ;
 RECT 0.6 159.66 0.79 159.85 ;
 RECT 1.21 159.66 1.4 159.85 ;
 END
 END gnd
 PIN vdd
 USE POWER ;
 DIRECTION INOUT ;
 PORT
 LAYER M5 ;
 RECT 173.415 153.8 175 156.3 ;
 END
 PORT
 LAYER M5 ;
 RECT 0 153.8 1.585 156.3 ;
 END
 PORT
 LAYER M4 ;
 RECT 173 153.8 175 156.3 ;
 END
 PORT
 LAYER M4 ;
 RECT 0 153.8 2 156.3 ;
 END
 END vdd
 PIN vddh
 USE POWER ;
 DIRECTION INOUT ;
 PORT
 LAYER M5 ;
 RECT 173.415 130.82 175 134.32 ;
 END
 PORT
 LAYER M5 ;
 RECT 0 130.82 1.585 134.32 ;
 END
 PORT
 LAYER M4 ;
 RECT 173 130.82 175 134.32 ;
 END
 PORT
 LAYER M4 ;
 RECT 0 130.82 2 134.32 ;
 END
 PORT
 LAYER M3 ;
 RECT 173.72 53.99 175 57.99 ;
 END
 PORT
 LAYER M3 ;
 RECT 0 53.99 1.28 57.99 ;
 END
 PORT
 LAYER M3 ;
 RECT 173.72 66.96 175 92.24 ;
 END
 PORT
 LAYER M3 ;
 RECT 0 66.96 1.28 92.24 ;
 END
 PORT
 LAYER M3 ;
 RECT 0 95.54 1.28 120.85 ;
 END
 PORT
 LAYER M3 ;
 RECT 173.72 95.54 175 120.85 ;
 END
 PORT
 LAYER M3 ;
 RECT 0 137.66 0.6 150.47 ;
 END
 PORT
 LAYER M3 ;
 RECT 174.4 137.66 175 150.47 ;
 END
 END vddh
 PIN vddhosc
 USE POWER ;
 DIRECTION INOUT ;
 PORT
 LAYER M3 ;
 RECT 114.385 160.82 129.385 162 ;
 END
 PORT
 LAYER M2 ;
 RECT 114.385 160.82 129.385 162 ;
 END
 PORT
 LAYER MV2 ;
 RECT 117.52 160.955 117.71 161.145 ;
 RECT 114.72 160.955 114.91 161.145 ;
 RECT 115.84 160.955 116.03 161.145 ;
 RECT 116.96 160.955 117.15 161.145 ;
 RECT 116.4 160.955 116.59 161.145 ;
 RECT 115.28 160.955 115.47 161.145 ;
 RECT 117.52 161.515 117.71 161.705 ;
 RECT 114.72 161.515 114.91 161.705 ;
 RECT 115.28 161.515 115.47 161.705 ;
 RECT 115.84 161.515 116.03 161.705 ;
 RECT 116.4 161.515 116.59 161.705 ;
 RECT 116.96 161.515 117.15 161.705 ;
 RECT 120.32 160.955 120.51 161.145 ;
 RECT 120.88 160.955 121.07 161.145 ;
 RECT 121.44 160.955 121.63 161.145 ;
 RECT 118.64 160.955 118.83 161.145 ;
 RECT 119.2 160.955 119.39 161.145 ;
 RECT 119.76 160.955 119.95 161.145 ;
 RECT 120.32 161.515 120.51 161.705 ;
 RECT 120.88 161.515 121.07 161.705 ;
 RECT 121.44 161.515 121.63 161.705 ;
 RECT 118.64 161.515 118.83 161.705 ;
 RECT 119.2 161.515 119.39 161.705 ;
 RECT 119.76 161.515 119.95 161.705 ;
 RECT 118.08 160.955 118.27 161.145 ;
 RECT 118.08 161.515 118.27 161.705 ;
 RECT 124.24 160.955 124.43 161.145 ;
 RECT 124.8 160.955 124.99 161.145 ;
 RECT 123.12 160.955 123.31 161.145 ;
 RECT 123.68 160.955 123.87 161.145 ;
 RECT 122 160.955 122.19 161.145 ;
 RECT 122.56 160.955 122.75 161.145 ;
 RECT 124.8 161.515 124.99 161.705 ;
 RECT 124.24 161.515 124.43 161.705 ;
 RECT 123.68 161.515 123.87 161.705 ;
 RECT 123.12 161.515 123.31 161.705 ;
 RECT 122 161.515 122.19 161.705 ;
 RECT 122.56 161.515 122.75 161.705 ;
 RECT 125.92 160.955 126.11 161.145 ;
 RECT 126.48 160.955 126.67 161.145 ;
 RECT 127.04 160.955 127.23 161.145 ;
 RECT 127.6 160.955 127.79 161.145 ;
 RECT 128.16 160.955 128.35 161.145 ;
 RECT 128.72 160.955 128.91 161.145 ;
 RECT 128.72 161.515 128.91 161.705 ;
 RECT 128.16 161.515 128.35 161.705 ;
 RECT 127.6 161.515 127.79 161.705 ;
 RECT 127.04 161.515 127.23 161.705 ;
 RECT 126.48 161.515 126.67 161.705 ;
 RECT 125.92 161.515 126.11 161.705 ;
 RECT 125.36 160.955 125.55 161.145 ;
 RECT 125.36 161.515 125.55 161.705 ;
 END
 END vddhosc
 PIN vssh
 USE GROUND ;
 DIRECTION INOUT ;
 PORT
 LAYER M5 ;
 RECT 173.415 124.15 175 129.15 ;
 END
 PORT
 LAYER M5 ;
 RECT 0 124.15 1.585 129.15 ;
 END
 PORT
 LAYER M5 ;
 RECT 0 148.13 1.585 152.13 ;
 END
 PORT
 LAYER M5 ;
 RECT 173.415 148.13 175 152.13 ;
 END
 PORT
 LAYER M4 ;
 RECT 173 124.15 175 129.15 ;
 END
 PORT
 LAYER M4 ;
 RECT 0 124.15 2 129.15 ;
 END
 PORT
 LAYER M4 ;
 RECT 0 148.13 2 152.13 ;
 END
 PORT
 LAYER M4 ;
 RECT 173 148.13 175 152.13 ;
 END
 PORT
 LAYER M3 ;
 RECT 173.72 9.91 175 28.65 ;
 END
 PORT
 LAYER M3 ;
 RECT 0 9.91 1.28 28.65 ;
 END
 PORT
 LAYER M3 ;
 RECT 0 31.95 1.28 50.69 ;
 END
 PORT
 LAYER M3 ;
 RECT 173.72 31.95 175 50.69 ;
 END
 END vssh
 PIN vsshosc
 USE GROUND ;
 DIRECTION INOUT ;
 PORT
 LAYER M3 ;
 RECT 143.605 160.82 158.605 162 ;
 END
 PORT
 LAYER M2 ;
 RECT 143.605 160.82 158.605 162 ;
 END
 PORT
 LAYER MV2 ;
 RECT 146.885 160.955 147.075 161.145 ;
 RECT 146.325 160.955 146.515 161.145 ;
 RECT 145.765 160.955 145.955 161.145 ;
 RECT 145.205 160.955 145.395 161.145 ;
 RECT 143.97 160.955 144.16 161.145 ;
 RECT 144.53 160.955 144.72 161.145 ;
 RECT 145.205 161.515 145.395 161.705 ;
 RECT 145.765 161.515 145.955 161.705 ;
 RECT 146.325 161.515 146.515 161.705 ;
 RECT 146.885 161.515 147.075 161.705 ;
 RECT 143.97 161.515 144.16 161.705 ;
 RECT 144.53 161.515 144.72 161.705 ;
 RECT 150.805 160.955 150.995 161.145 ;
 RECT 150.245 160.955 150.435 161.145 ;
 RECT 149.685 160.955 149.875 161.145 ;
 RECT 149.125 160.955 149.315 161.145 ;
 RECT 148.565 160.955 148.755 161.145 ;
 RECT 148.005 160.955 148.195 161.145 ;
 RECT 150.245 161.515 150.435 161.705 ;
 RECT 150.805 161.515 150.995 161.705 ;
 RECT 149.125 161.515 149.315 161.705 ;
 RECT 149.685 161.515 149.875 161.705 ;
 RECT 148.005 161.515 148.195 161.705 ;
 RECT 148.565 161.515 148.755 161.705 ;
 RECT 147.445 160.955 147.635 161.145 ;
 RECT 147.445 161.515 147.635 161.705 ;
 RECT 154.165 160.955 154.355 161.145 ;
 RECT 153.605 160.955 153.795 161.145 ;
 RECT 153.045 160.955 153.235 161.145 ;
 RECT 152.485 160.955 152.675 161.145 ;
 RECT 151.925 160.955 152.115 161.145 ;
 RECT 151.365 160.955 151.555 161.145 ;
 RECT 153.045 161.515 153.235 161.705 ;
 RECT 153.605 161.515 153.795 161.705 ;
 RECT 154.165 161.515 154.355 161.705 ;
 RECT 151.365 161.515 151.555 161.705 ;
 RECT 151.925 161.515 152.115 161.705 ;
 RECT 152.485 161.515 152.675 161.705 ;
 RECT 156.405 160.955 156.595 161.145 ;
 RECT 156.965 160.955 157.155 161.145 ;
 RECT 157.525 160.955 157.715 161.145 ;
 RECT 158.085 160.955 158.275 161.145 ;
 RECT 155.845 160.955 156.035 161.145 ;
 RECT 155.285 160.955 155.475 161.145 ;
 RECT 154.725 160.955 154.915 161.145 ;
 RECT 156.405 161.515 156.595 161.705 ;
 RECT 158.085 161.515 158.275 161.705 ;
 RECT 157.525 161.515 157.715 161.705 ;
 RECT 156.965 161.515 157.155 161.705 ;
 RECT 155.845 161.515 156.035 161.705 ;
 RECT 154.725 161.515 154.915 161.705 ;
 RECT 155.285 161.515 155.475 161.705 ;
 END
 END vsshosc
 OBS
 LAYER GATE ;
 RECT 0 0 175 162 ;
 LAYER MV1 ;
 RECT 0 0 175 162 ;
 LAYER MV2 ;
 RECT 0 0 175 162 ;
 LAYER MV3 ;
 RECT 0 0 175 162 ;
 LAYER MV4 ;
 RECT 0 0 175 162 ;
 LAYER M1 ;
 RECT 0 0 175 162 ;
 LAYER M2 ;
 RECT 0 160.22 113.785 160.55 ;
 RECT 23.24 160.55 25.76 162 ;
 RECT 0 160.55 22.26 162 ;
 RECT 26.74 160.55 29.26 162 ;
 RECT 30.24 160.55 113.785 162 ;
 RECT 0 0 175 160.22 ;
 RECT 129.985 160.22 143.005 162 ;
 RECT 159.205 160.22 175 162 ;
 LAYER M3 ;
 RECT 0 0 175 9.31 ;
 RECT 0 29.25 175 31.35 ;
 RECT 1.88 9.31 173.12 29.25 ;
 RECT 1.825 160.22 113.785 160.55 ;
 RECT 1.825 160.55 22.26 160.61 ;
 RECT 0 160.61 22.26 162 ;
 RECT 23.24 160.55 25.76 162 ;
 RECT 26.74 160.55 29.26 162 ;
 RECT 30.24 160.55 113.785 162 ;
 RECT 129.985 160.22 143.005 162 ;
 RECT 0 51.29 175 53.75 ;
 RECT 1.88 31.35 173.12 51.29 ;
 RECT 0 58.23 175 59.42 ;
 RECT 1.52 53.75 173.48 58.23 ;
 RECT 1.88 66.36 173.12 92.84 ;
 RECT 1.88 94.94 173.12 121.45 ;
 RECT 1.825 157.73 173.175 160.22 ;
 RECT 159.205 160.22 173.175 160.61 ;
 RECT 0 63.9 175 66.36 ;
 RECT 1.52 59.42 173.48 63.9 ;
 RECT 0 92.84 175 94.94 ;
 RECT 0 121.45 175 128.86 ;
 RECT 0 130.24 175 137.06 ;
 RECT 1.52 128.86 173.48 130.24 ;
 RECT 0 151.07 175 157.73 ;
 RECT 1.2 137.06 173.8 151.07 ;
 RECT 159.205 160.61 175 162 ;
 LAYER M4 ;
 RECT 0 0 175 123.91 ;
 RECT 0 129.39 175 130.58 ;
 RECT 2.24 123.91 172.76 129.39 ;
 RECT 2.6 135.39 172.4 147.06 ;
 RECT 0 134.56 175 135.39 ;
 RECT 2.24 130.58 172.76 134.56 ;
 RECT 0 147.06 175 147.89 ;
 RECT 0 152.37 175 153.56 ;
 RECT 2.24 147.89 172.76 152.37 ;
 RECT 0 156.54 175 157.73 ;
 RECT 2.24 153.56 172.76 156.54 ;
 RECT 0 160.71 175 162 ;
 RECT 1.825 157.73 173.175 160.71 ;
 LAYER M5 ;
 RECT 2.045 147.67 172.955 152.59 ;
 RECT 0 156.76 175 157.51 ;
 RECT 2.045 153.34 172.955 156.76 ;
 RECT 0 160.93 175 162 ;
 RECT 2.045 157.51 172.955 160.93 ;
 RECT 0 0 175 9.9 ;
 RECT 0 111.1 175 123.69 ;
 RECT 0 9.9 3.9 111.1 ;
 RECT 71.1 9.9 103.9 111.1 ;
 RECT 171.1 9.9 175 111.1 ;
 RECT 0 129.61 175 130.36 ;
 RECT 2.045 123.69 172.955 129.61 ;
 RECT 2.185 135.39 172.815 147.06 ;
 RECT 0 134.78 175 135.39 ;
 RECT 2.045 130.36 172.955 134.78 ;
 RECT 0 147.06 175 147.67 ;
 RECT 0 152.59 175 153.34 ;
 END
END RCMCU_PLOSC

MACRO RCMCU_PLPWBK
 CLASS PAD ;
 FOREIGN RCMCU_PLPWBK ;
 ORIGIN 0 0 ;
 SIZE 75 BY 162 ;
 SYMMETRY X Y R90 ;
 PIN POC
 USE POWER ;
 DIRECTION INOUT ;
 PORT
 LAYER M3 ;
 RECT 73.72 129.1 75 130 ;
 END
 PORT
 LAYER M3 ;
 RECT 0 129.1 1.28 130 ;
 END
 END POC
 PIN gnd
 USE GROUND ;
 DIRECTION INOUT ;
 PORT
 LAYER M5 ;
 RECT 73.415 135.99 75 146.46 ;
 END
 PORT
 LAYER M5 ;
 RECT 0 135.99 1.585 146.46 ;
 END
 PORT
 LAYER M5 ;
 RECT 0 157.97 1.585 160.47 ;
 END
 PORT
 LAYER M5 ;
 RECT 73.415 157.97 75 160.47 ;
 END
 PORT
 LAYER M4 ;
 RECT 73 135.99 75 146.46 ;
 END
 PORT
 LAYER M4 ;
 RECT 0 135.99 2 146.46 ;
 END
 PORT
 LAYER M4 ;
 RECT 0 157.97 2 160.47 ;
 END
 PORT
 LAYER M4 ;
 RECT 73 157.97 75 160.47 ;
 END
 PORT
 LAYER M3 ;
 RECT 73.72 59.66 75 63.66 ;
 END
 PORT
 LAYER M3 ;
 RECT 0 59.66 1.28 63.66 ;
 END
 PORT
 LAYER M3 ;
 RECT 0 157.97 1.28 160.37 ;
 END
 PORT
 LAYER M3 ;
 RECT 73.72 157.97 75 160.37 ;
 END
 PORT
 LAYER MV3 ;
 RECT 74.175 158.525 74.365 158.715 ;
 RECT 74.175 159.325 74.365 159.515 ;
 RECT 0.635 158.525 0.825 158.715 ;
 RECT 0.635 159.325 0.825 159.515 ;
 END
 END gnd
 PIN vdd
 USE POWER ;
 DIRECTION INOUT ;
 PORT
 LAYER M5 ;
 RECT 73.415 153.8 75 156.3 ;
 END
 PORT
 LAYER M5 ;
 RECT 0 153.8 1.585 156.3 ;
 END
 PORT
 LAYER M4 ;
 RECT 73 153.8 75 156.3 ;
 END
 PORT
 LAYER M4 ;
 RECT 0 153.8 2 156.3 ;
 END
 END vdd
 PIN vssh
 USE GROUND ;
 DIRECTION INOUT ;
 PORT
 LAYER M3 ;
 RECT 0 9.91 1.28 28.65 ;
 END
 PORT
 LAYER M3 ;
 RECT 0 31.95 1.28 50.69 ;
 END
 END vssh
 PIN vssxa
 USE GROUND ;
 DIRECTION INOUT ;
 PORT
 LAYER M3 ;
 RECT 73.72 9.91 75 28.65 ;
 END
 PORT
 LAYER M3 ;
 RECT 73.72 31.95 75 50.69 ;
 END
 END vssxa
 OBS
 LAYER GATE ;
 RECT 0 0 75 162 ;
 LAYER MV1 ;
 RECT 0 0 75 162 ;
 LAYER MV2 ;
 RECT 0 0 75 162 ;
 LAYER MV3 ;
 RECT 0 0 75 162 ;
 LAYER MV4 ;
 RECT 0 0 75 162 ;
 LAYER M1 ;
 RECT 0 0 75 162 ;
 LAYER M2 ;
 RECT 0 0 75 162 ;
 LAYER M3 ;
 RECT 0 0 75 9.31 ;
 RECT 0 29.25 75 31.35 ;
 RECT 1.88 9.31 73.12 29.25 ;
 RECT 0 51.29 75 59.42 ;
 RECT 1.88 31.35 73.12 51.29 ;
 RECT 0 63.9 75 128.86 ;
 RECT 1.52 59.42 73.48 63.9 ;
 RECT 0 130.24 75 157.73 ;
 RECT 1.52 128.86 73.48 130.24 ;
 RECT 0 160.61 75 162 ;
 RECT 1.52 157.73 73.48 160.61 ;
 LAYER M4 ;
 RECT 0 0 75 135.39 ;
 RECT 0 147.06 75 153.56 ;
 RECT 2.6 135.39 72.4 147.06 ;
 RECT 0 156.54 75 157.73 ;
 RECT 2.24 153.56 72.76 156.54 ;
 RECT 0 160.71 75 162 ;
 RECT 2.24 157.73 72.76 160.71 ;
 LAYER M5 ;
 RECT 0 0 75 135.39 ;
 RECT 0 147.06 75 153.34 ;
 RECT 2.185 135.39 72.815 147.06 ;
 RECT 0 156.76 75 157.51 ;
 RECT 2.045 153.34 72.955 156.76 ;
 RECT 0 160.93 75 162 ;
 RECT 2.045 157.51 72.955 160.93 ;
 END
END RCMCU_PLPWBK

MACRO RCMCU_PLVDD
 CLASS PAD ;
 FOREIGN RCMCU_PLVDD ;
 ORIGIN 0 0 ;
 SIZE 75 BY 162 ;
 SYMMETRY X Y R90 ;
 PIN POC
 USE POWER ;
 DIRECTION INOUT ;
 PORT
 LAYER M3 ;
 RECT 73.72 129.1 75 130 ;
 END
 PORT
 LAYER M3 ;
 RECT 0 129.1 1.28 130 ;
 END
 END POC
 PIN gnd
 USE GROUND ;
 DIRECTION INOUT ;
 PORT
 LAYER M5 ;
 RECT 73.415 135.99 75 146.46 ;
 END
 PORT
 LAYER M5 ;
 RECT 0 135.99 1.585 146.46 ;
 END
 PORT
 LAYER M5 ;
 RECT 0 157.97 1.585 160.47 ;
 END
 PORT
 LAYER M5 ;
 RECT 73.415 157.97 75 160.47 ;
 END
 PORT
 LAYER M4 ;
 RECT 73 135.99 75 146.46 ;
 END
 PORT
 LAYER M4 ;
 RECT 0 135.99 2 146.46 ;
 END
 PORT
 LAYER M4 ;
 RECT 0 157.97 1.585 160.47 ;
 END
 PORT
 LAYER M4 ;
 RECT 73.415 157.97 75 160.47 ;
 END
 PORT
 LAYER M3 ;
 RECT 73.72 59.66 75 63.66 ;
 END
 PORT
 LAYER M3 ;
 RECT 0 59.66 1.28 63.66 ;
 END
 PORT
 LAYER M3 ;
 RECT 0 157.97 1.585 160.37 ;
 END
 PORT
 LAYER M3 ;
 RECT 73.415 157.97 75 160.37 ;
 END
 PORT
 LAYER MV3 ;
 RECT 73.6 158.44 73.79 158.63 ;
 RECT 74.21 158.44 74.4 158.63 ;
 RECT 73.6 159.05 73.79 159.24 ;
 RECT 74.21 159.05 74.4 159.24 ;
 RECT 73.6 159.66 73.79 159.85 ;
 RECT 74.21 159.66 74.4 159.85 ;
 RECT 0.6 158.44 0.79 158.63 ;
 RECT 1.21 158.44 1.4 158.63 ;
 RECT 0.6 159.05 0.79 159.24 ;
 RECT 1.21 159.05 1.4 159.24 ;
 RECT 0.6 159.66 0.79 159.85 ;
 RECT 1.21 159.66 1.4 159.85 ;
 END
 END gnd
 PIN vdd
 USE POWER ;
 DIRECTION INOUT ;
 PORT
 LAYER M5 ;
 RECT 4.5 10.5 70.5 110.5 ;
 END
 PORT
 LAYER M5 ;
 RECT 0 153.8 1.585 156.3 ;
 END
 PORT
 LAYER M5 ;
 RECT 73.415 153.8 75 156.3 ;
 END
 PORT
 LAYER M4 ;
 RECT 73 153.8 75 156.3 ;
 END
 PORT
 LAYER M4 ;
 RECT 0 153.8 2 156.3 ;
 END
 PORT
 LAYER M3 ;
 RECT 10.5 160.445 64.5 162 ;
 END
 PORT
 LAYER M2 ;
 RECT 10.5 160.445 64.5 162 ;
 END
 PORT
 LAYER MV2 ;
 RECT 27.59 160.63 27.78 160.82 ;
 RECT 30.39 161.19 30.58 161.38 ;
 RECT 28.15 161.19 28.34 161.38 ;
 RECT 28.71 161.19 28.9 161.38 ;
 RECT 29.27 161.19 29.46 161.38 ;
 RECT 29.83 161.19 30.02 161.38 ;
 RECT 27.59 161.19 27.78 161.38 ;
 RECT 32.63 160.63 32.82 160.82 ;
 RECT 33.75 160.63 33.94 160.82 ;
 RECT 33.19 160.63 33.38 160.82 ;
 RECT 30.95 160.63 31.14 160.82 ;
 RECT 31.51 160.63 31.7 160.82 ;
 RECT 32.07 160.63 32.26 160.82 ;
 RECT 32.63 161.19 32.82 161.38 ;
 RECT 33.19 161.19 33.38 161.38 ;
 RECT 33.75 161.19 33.94 161.38 ;
 RECT 32.07 161.19 32.26 161.38 ;
 RECT 31.51 161.19 31.7 161.38 ;
 RECT 30.95 161.19 31.14 161.38 ;
 RECT 37.11 160.63 37.3 160.82 ;
 RECT 36.55 160.63 36.74 160.82 ;
 RECT 35.99 160.63 36.18 160.82 ;
 RECT 35.43 160.63 35.62 160.82 ;
 RECT 34.87 160.63 35.06 160.82 ;
 RECT 34.31 160.63 34.5 160.82 ;
 RECT 37.11 161.19 37.3 161.38 ;
 RECT 36.55 161.19 36.74 161.38 ;
 RECT 35.99 161.19 36.18 161.38 ;
 RECT 35.43 161.19 35.62 161.38 ;
 RECT 34.31 161.19 34.5 161.38 ;
 RECT 34.87 161.19 35.06 161.38 ;
 RECT 39.91 160.63 40.1 160.82 ;
 RECT 40.47 160.63 40.66 160.82 ;
 RECT 39.35 160.63 39.54 160.82 ;
 RECT 38.79 160.63 38.98 160.82 ;
 RECT 38.23 160.63 38.42 160.82 ;
 RECT 37.67 160.63 37.86 160.82 ;
 RECT 39.91 161.19 40.1 161.38 ;
 RECT 40.47 161.19 40.66 161.38 ;
 RECT 37.67 161.19 37.86 161.38 ;
 RECT 38.23 161.19 38.42 161.38 ;
 RECT 38.79 161.19 38.98 161.38 ;
 RECT 39.35 161.19 39.54 161.38 ;
 RECT 42.15 160.63 42.34 160.82 ;
 RECT 42.71 160.63 42.9 160.82 ;
 RECT 43.27 160.63 43.46 160.82 ;
 RECT 43.83 160.63 44.02 160.82 ;
 RECT 41.03 160.63 41.22 160.82 ;
 RECT 41.59 160.63 41.78 160.82 ;
 RECT 42.15 161.19 42.34 161.38 ;
 RECT 42.71 161.19 42.9 161.38 ;
 RECT 43.27 161.19 43.46 161.38 ;
 RECT 43.83 161.19 44.02 161.38 ;
 RECT 41.59 161.19 41.78 161.38 ;
 RECT 41.03 161.19 41.22 161.38 ;
 RECT 47.19 160.63 47.38 160.82 ;
 RECT 44.39 160.63 44.58 160.82 ;
 RECT 44.95 160.63 45.14 160.82 ;
 RECT 45.51 160.63 45.7 160.82 ;
 RECT 46.07 160.63 46.26 160.82 ;
 RECT 46.63 160.63 46.82 160.82 ;
 RECT 47.19 161.19 47.38 161.38 ;
 RECT 44.39 161.19 44.58 161.38 ;
 RECT 46.63 161.19 46.82 161.38 ;
 RECT 46.07 161.19 46.26 161.38 ;
 RECT 45.51 161.19 45.7 161.38 ;
 RECT 44.95 161.19 45.14 161.38 ;
 RECT 50.55 160.63 50.74 160.82 ;
 RECT 49.99 160.63 50.18 160.82 ;
 RECT 49.43 160.63 49.62 160.82 ;
 RECT 48.87 160.63 49.06 160.82 ;
 RECT 48.31 160.63 48.5 160.82 ;
 RECT 47.75 160.63 47.94 160.82 ;
 RECT 49.43 161.19 49.62 161.38 ;
 RECT 49.99 161.19 50.18 161.38 ;
 RECT 50.55 161.19 50.74 161.38 ;
 RECT 48.87 161.19 49.06 161.38 ;
 RECT 48.31 161.19 48.5 161.38 ;
 RECT 47.75 161.19 47.94 161.38 ;
 RECT 53.91 160.63 54.1 160.82 ;
 RECT 53.35 160.63 53.54 160.82 ;
 RECT 52.79 160.63 52.98 160.82 ;
 RECT 52.23 160.63 52.42 160.82 ;
 RECT 51.67 160.63 51.86 160.82 ;
 RECT 51.11 160.63 51.3 160.82 ;
 RECT 53.91 161.19 54.1 161.38 ;
 RECT 51.67 161.19 51.86 161.38 ;
 RECT 52.23 161.19 52.42 161.38 ;
 RECT 52.79 161.19 52.98 161.38 ;
 RECT 53.35 161.19 53.54 161.38 ;
 RECT 51.11 161.19 51.3 161.38 ;
 RECT 56.15 160.63 56.34 160.82 ;
 RECT 56.71 160.63 56.9 160.82 ;
 RECT 57.27 160.63 57.46 160.82 ;
 RECT 55.03 160.63 55.22 160.82 ;
 RECT 55.59 160.63 55.78 160.82 ;
 RECT 54.47 160.63 54.66 160.82 ;
 RECT 56.15 161.19 56.34 161.38 ;
 RECT 56.71 161.19 56.9 161.38 ;
 RECT 57.27 161.19 57.46 161.38 ;
 RECT 55.59 161.19 55.78 161.38 ;
 RECT 55.03 161.19 55.22 161.38 ;
 RECT 54.47 161.19 54.66 161.38 ;
 RECT 58.95 160.63 59.14 160.82 ;
 RECT 59.51 160.63 59.7 160.82 ;
 RECT 60.07 160.63 60.26 160.82 ;
 RECT 60.63 160.63 60.82 160.82 ;
 RECT 57.83 160.63 58.02 160.82 ;
 RECT 58.39 160.63 58.58 160.82 ;
 RECT 60.63 161.19 60.82 161.38 ;
 RECT 60.07 161.19 60.26 161.38 ;
 RECT 59.51 161.19 59.7 161.38 ;
 RECT 58.95 161.19 59.14 161.38 ;
 RECT 57.83 161.19 58.02 161.38 ;
 RECT 58.39 161.19 58.58 161.38 ;
 RECT 62.31 160.63 62.5 160.82 ;
 RECT 63.43 160.63 63.62 160.82 ;
 RECT 63.99 160.63 64.18 160.82 ;
 RECT 61.75 160.63 61.94 160.82 ;
 RECT 61.19 160.63 61.38 160.82 ;
 RECT 62.87 160.63 63.06 160.82 ;
 RECT 61.19 161.19 61.38 161.38 ;
 RECT 61.75 161.19 61.94 161.38 ;
 RECT 62.31 161.19 62.5 161.38 ;
 RECT 62.87 161.19 63.06 161.38 ;
 RECT 63.43 161.19 63.62 161.38 ;
 RECT 63.99 161.19 64.18 161.38 ;
 RECT 10.79 160.63 10.98 160.82 ;
 RECT 11.91 160.63 12.1 160.82 ;
 RECT 12.47 160.63 12.66 160.82 ;
 RECT 13.03 160.63 13.22 160.82 ;
 RECT 13.59 160.63 13.78 160.82 ;
 RECT 11.35 160.63 11.54 160.82 ;
 RECT 10.79 161.19 10.98 161.38 ;
 RECT 11.35 161.19 11.54 161.38 ;
 RECT 11.91 161.19 12.1 161.38 ;
 RECT 12.47 161.19 12.66 161.38 ;
 RECT 13.03 161.19 13.22 161.38 ;
 RECT 13.59 161.19 13.78 161.38 ;
 RECT 16.95 160.63 17.14 160.82 ;
 RECT 16.39 160.63 16.58 160.82 ;
 RECT 15.83 160.63 16.02 160.82 ;
 RECT 15.27 160.63 15.46 160.82 ;
 RECT 14.71 160.63 14.9 160.82 ;
 RECT 14.15 160.63 14.34 160.82 ;
 RECT 16.39 161.19 16.58 161.38 ;
 RECT 16.95 161.19 17.14 161.38 ;
 RECT 14.15 161.19 14.34 161.38 ;
 RECT 14.71 161.19 14.9 161.38 ;
 RECT 15.27 161.19 15.46 161.38 ;
 RECT 15.83 161.19 16.02 161.38 ;
 RECT 20.31 160.63 20.5 160.82 ;
 RECT 19.75 160.63 19.94 160.82 ;
 RECT 19.19 160.63 19.38 160.82 ;
 RECT 18.63 160.63 18.82 160.82 ;
 RECT 18.07 160.63 18.26 160.82 ;
 RECT 17.51 160.63 17.7 160.82 ;
 RECT 18.63 161.19 18.82 161.38 ;
 RECT 19.19 161.19 19.38 161.38 ;
 RECT 19.75 161.19 19.94 161.38 ;
 RECT 20.31 161.19 20.5 161.38 ;
 RECT 18.07 161.19 18.26 161.38 ;
 RECT 17.51 161.19 17.7 161.38 ;
 RECT 23.67 160.63 23.86 160.82 ;
 RECT 23.11 160.63 23.3 160.82 ;
 RECT 22.55 160.63 22.74 160.82 ;
 RECT 21.99 160.63 22.18 160.82 ;
 RECT 21.43 160.63 21.62 160.82 ;
 RECT 20.87 160.63 21.06 160.82 ;
 RECT 23.67 161.19 23.86 161.38 ;
 RECT 23.11 161.19 23.3 161.38 ;
 RECT 22.55 161.19 22.74 161.38 ;
 RECT 21.99 161.19 22.18 161.38 ;
 RECT 21.43 161.19 21.62 161.38 ;
 RECT 20.87 161.19 21.06 161.38 ;
 RECT 25.91 160.63 26.1 160.82 ;
 RECT 26.47 160.63 26.66 160.82 ;
 RECT 27.03 160.63 27.22 160.82 ;
 RECT 24.23 160.63 24.42 160.82 ;
 RECT 24.79 160.63 24.98 160.82 ;
 RECT 25.35 160.63 25.54 160.82 ;
 RECT 27.03 161.19 27.22 161.38 ;
 RECT 26.47 161.19 26.66 161.38 ;
 RECT 25.91 161.19 26.1 161.38 ;
 RECT 24.23 161.19 24.42 161.38 ;
 RECT 24.79 161.19 24.98 161.38 ;
 RECT 25.35 161.19 25.54 161.38 ;
 RECT 30.39 160.63 30.58 160.82 ;
 RECT 29.83 160.63 30.02 160.82 ;
 RECT 29.27 160.63 29.46 160.82 ;
 RECT 28.71 160.63 28.9 160.82 ;
 RECT 28.15 160.63 28.34 160.82 ;
 END
 END vdd
 PIN vddh
 USE POWER ;
 DIRECTION INOUT ;
 PORT
 LAYER M5 ;
 RECT 73.415 130.82 75 134.32 ;
 END
 PORT
 LAYER M5 ;
 RECT 0 130.82 1.585 134.32 ;
 END
 PORT
 LAYER M4 ;
 RECT 73 130.82 75 134.32 ;
 END
 PORT
 LAYER M4 ;
 RECT 0 130.82 2 134.32 ;
 END
 PORT
 LAYER M3 ;
 RECT 73.72 53.99 75 57.99 ;
 END
 PORT
 LAYER M3 ;
 RECT 0 53.99 1.28 57.99 ;
 END
 PORT
 LAYER M3 ;
 RECT 73.72 66.96 75 92.24 ;
 END
 PORT
 LAYER M3 ;
 RECT 0 66.96 1.28 92.24 ;
 END
 PORT
 LAYER M3 ;
 RECT 0 95.54 1.28 120.85 ;
 END
 PORT
 LAYER M3 ;
 RECT 73.72 95.54 75 120.85 ;
 END
 PORT
 LAYER M3 ;
 RECT 0 137.66 0.6 150.47 ;
 END
 PORT
 LAYER M3 ;
 RECT 74.4 137.66 75 150.47 ;
 END
 END vddh
 PIN vssh
 USE GROUND ;
 DIRECTION INOUT ;
 PORT
 LAYER M5 ;
 RECT 73.415 124.15 75 129.15 ;
 END
 PORT
 LAYER M5 ;
 RECT 0 124.15 1.585 129.15 ;
 END
 PORT
 LAYER M5 ;
 RECT 0 148.13 1.585 152.13 ;
 END
 PORT
 LAYER M5 ;
 RECT 73.415 148.13 75 152.13 ;
 END
 PORT
 LAYER M4 ;
 RECT 73 124.15 75 129.15 ;
 END
 PORT
 LAYER M4 ;
 RECT 0 124.15 2 129.15 ;
 END
 PORT
 LAYER M4 ;
 RECT 0 148.13 2 152.13 ;
 END
 PORT
 LAYER M4 ;
 RECT 73 148.13 75 152.13 ;
 END
 PORT
 LAYER M3 ;
 RECT 73.72 9.91 75 28.65 ;
 END
 PORT
 LAYER M3 ;
 RECT 0 9.91 1.28 28.65 ;
 END
 PORT
 LAYER M3 ;
 RECT 0 31.95 1.28 50.69 ;
 END
 PORT
 LAYER M3 ;
 RECT 73.72 31.95 75 50.69 ;
 END
 END vssh
 OBS
 LAYER GATE ;
 RECT 0 0 75 162 ;
 LAYER MV1 ;
 RECT 0 0 75 162 ;
 LAYER MV2 ;
 RECT 0 0 75 162 ;
 LAYER MV3 ;
 RECT 0 0 75 162 ;
 LAYER MV4 ;
 RECT 0 0 75 162 ;
 LAYER M1 ;
 RECT 0 0 75 162 ;
 LAYER M2 ;
 RECT 65.1 159.845 75 162 ;
 RECT 0 159.845 9.9 162 ;
 RECT 0 0 75 159.845 ;
 LAYER M3 ;
 RECT 0 29.25 75 31.35 ;
 RECT 1.88 9.31 73.12 29.25 ;
 RECT 1.825 159.845 9.9 160.61 ;
 RECT 0 160.61 9.9 162 ;
 RECT 0 51.29 75 53.75 ;
 RECT 1.88 31.35 73.12 51.29 ;
 RECT 0 58.23 75 59.42 ;
 RECT 1.52 53.75 73.48 58.23 ;
 RECT 1.88 66.36 73.12 92.84 ;
 RECT 1.88 94.94 73.12 121.45 ;
 RECT 1.825 157.73 73.175 159.845 ;
 RECT 65.1 159.845 73.175 160.61 ;
 RECT 0 63.9 75 66.36 ;
 RECT 1.52 59.42 73.48 63.9 ;
 RECT 0 92.84 75 94.94 ;
 RECT 0 121.45 75 128.86 ;
 RECT 0 130.24 75 137.06 ;
 RECT 1.52 128.86 73.48 130.24 ;
 RECT 0 151.07 75 157.73 ;
 RECT 1.2 137.06 73.8 151.07 ;
 RECT 65.1 160.61 75 162 ;
 RECT 0 0 75 9.31 ;
 LAYER M4 ;
 RECT 0 0 75 123.91 ;
 RECT 0 129.39 75 130.58 ;
 RECT 2.24 123.91 72.76 129.39 ;
 RECT 2.6 135.39 72.4 147.06 ;
 RECT 0 134.56 75 135.39 ;
 RECT 2.24 130.58 72.76 134.56 ;
 RECT 0 147.06 75 147.89 ;
 RECT 0 152.37 75 153.56 ;
 RECT 2.24 147.89 72.76 152.37 ;
 RECT 0 156.54 75 157.73 ;
 RECT 2.24 153.56 72.76 156.54 ;
 RECT 0 160.71 75 162 ;
 RECT 1.825 157.73 73.175 160.71 ;
 LAYER M5 ;
 RECT 0 9.9 3.9 111.1 ;
 RECT 71.1 9.9 75 111.1 ;
 RECT 0 0 75 9.9 ;
 RECT 0 111.1 75 123.69 ;
 RECT 0 129.61 75 130.36 ;
 RECT 2.045 123.69 72.955 129.61 ;
 RECT 2.185 135.39 72.815 147.06 ;
 RECT 0 134.78 75 135.39 ;
 RECT 2.045 130.36 72.955 134.78 ;
 RECT 0 147.06 75 147.67 ;
 RECT 0 152.59 75 153.34 ;
 RECT 2.045 147.67 72.955 152.59 ;
 RECT 0 156.76 75 157.51 ;
 RECT 2.045 153.34 72.955 156.76 ;
 RECT 0 160.93 75 162 ;
 RECT 2.045 157.51 72.955 160.93 ;
 END
END RCMCU_PLVDD

MACRO RCMCU_PLVDDA
 CLASS PAD ;
 FOREIGN RCMCU_PLVDDA ;
 ORIGIN 0 0 ;
 SIZE 75 BY 162 ;
 SYMMETRY X Y R90 ;
 PIN POC
 USE POWER ;
 DIRECTION INOUT ;
 PORT
 LAYER M3 ;
 RECT 73.72 129.1 75 130 ;
 END
 PORT
 LAYER M3 ;
 RECT 0 129.1 1.28 130 ;
 END
 END POC
 PIN gnd
 USE GROUND ;
 DIRECTION INOUT ;
 PORT
 LAYER M5 ;
 RECT 73.415 135.99 75 146.46 ;
 END
 PORT
 LAYER M5 ;
 RECT 0 135.99 1.585 146.46 ;
 END
 PORT
 LAYER M5 ;
 RECT 0 157.97 1.585 160.47 ;
 END
 PORT
 LAYER M5 ;
 RECT 73.415 157.97 75 160.47 ;
 END
 PORT
 LAYER M4 ;
 RECT 73 135.99 75 146.46 ;
 END
 PORT
 LAYER M4 ;
 RECT 0 135.99 2 146.46 ;
 END
 PORT
 LAYER M4 ;
 RECT 0 157.97 2 160.47 ;
 END
 PORT
 LAYER M4 ;
 RECT 73 157.97 75 160.47 ;
 END
 PORT
 LAYER M3 ;
 RECT 73.72 59.66 75 63.66 ;
 END
 PORT
 LAYER M3 ;
 RECT 0 59.66 1.28 63.66 ;
 END
 PORT
 LAYER M3 ;
 RECT 0 157.97 1.28 160.37 ;
 END
 PORT
 LAYER M3 ;
 RECT 73.72 157.97 75 160.37 ;
 END
 PORT
 LAYER MV3 ;
 RECT 74.175 158.525 74.365 158.715 ;
 RECT 74.175 159.325 74.365 159.515 ;
 RECT 0.635 158.525 0.825 158.715 ;
 RECT 0.635 159.325 0.825 159.515 ;
 END
 END gnd
 PIN vdd
 USE POWER ;
 DIRECTION INOUT ;
 PORT
 LAYER M5 ;
 RECT 73.415 153.8 75 156.3 ;
 END
 PORT
 LAYER M5 ;
 RECT 0 153.8 1.585 156.3 ;
 END
 PORT
 LAYER M4 ;
 RECT 73 153.8 75 156.3 ;
 END
 PORT
 LAYER M4 ;
 RECT 0 153.8 2 156.3 ;
 END
 END vdd
 PIN vdda
 USE POWER ;
 DIRECTION INOUT ;
 PORT
 LAYER M5 ;
 RECT 4.5 10.5 70.5 110.5 ;
 END
 PORT
 LAYER M5 ;
 RECT 0 130.82 1.585 134.32 ;
 END
 PORT
 LAYER M5 ;
 RECT 73.415 130.82 75 134.32 ;
 END
 PORT
 LAYER M4 ;
 RECT 73 130.82 75 134.32 ;
 END
 PORT
 LAYER M4 ;
 RECT 0 130.82 2 134.32 ;
 END
 PORT
 LAYER M3 ;
 RECT 73.72 53.99 75 57.99 ;
 END
 PORT
 LAYER M3 ;
 RECT 0 53.99 1.28 57.99 ;
 END
 PORT
 LAYER M3 ;
 RECT 73.72 66.96 75 92.24 ;
 END
 PORT
 LAYER M3 ;
 RECT 0 66.96 1.28 92.24 ;
 END
 PORT
 LAYER M3 ;
 RECT 0 95.54 1.28 120.85 ;
 END
 PORT
 LAYER M3 ;
 RECT 73.72 95.54 75 120.85 ;
 END
 PORT
 LAYER M3 ;
 RECT 0 137.66 0.6 150.47 ;
 END
 PORT
 LAYER M3 ;
 RECT 74.4 137.66 75 150.47 ;
 END
 PORT
 LAYER M3 ;
 RECT 10.5 160.82 64.5 162 ;
 END
 PORT
 LAYER M2 ;
 RECT 10.5 160.82 64.5 162 ;
 END
 PORT
 LAYER MV2 ;
 RECT 29.27 161.515 29.46 161.705 ;
 RECT 29.83 161.515 30.02 161.705 ;
 RECT 27.59 161.515 27.78 161.705 ;
 RECT 32.63 160.955 32.82 161.145 ;
 RECT 33.75 160.955 33.94 161.145 ;
 RECT 33.19 160.955 33.38 161.145 ;
 RECT 30.95 160.955 31.14 161.145 ;
 RECT 31.51 160.955 31.7 161.145 ;
 RECT 32.07 160.955 32.26 161.145 ;
 RECT 32.63 161.515 32.82 161.705 ;
 RECT 33.19 161.515 33.38 161.705 ;
 RECT 33.75 161.515 33.94 161.705 ;
 RECT 32.07 161.515 32.26 161.705 ;
 RECT 31.51 161.515 31.7 161.705 ;
 RECT 30.95 161.515 31.14 161.705 ;
 RECT 37.11 160.955 37.3 161.145 ;
 RECT 36.55 160.955 36.74 161.145 ;
 RECT 35.99 160.955 36.18 161.145 ;
 RECT 35.43 160.955 35.62 161.145 ;
 RECT 34.87 160.955 35.06 161.145 ;
 RECT 34.31 160.955 34.5 161.145 ;
 RECT 37.11 161.515 37.3 161.705 ;
 RECT 36.55 161.515 36.74 161.705 ;
 RECT 35.99 161.515 36.18 161.705 ;
 RECT 35.43 161.515 35.62 161.705 ;
 RECT 34.31 161.515 34.5 161.705 ;
 RECT 34.87 161.515 35.06 161.705 ;
 RECT 39.91 160.955 40.1 161.145 ;
 RECT 40.47 160.955 40.66 161.145 ;
 RECT 39.35 160.955 39.54 161.145 ;
 RECT 38.79 160.955 38.98 161.145 ;
 RECT 38.23 160.955 38.42 161.145 ;
 RECT 37.67 160.955 37.86 161.145 ;
 RECT 39.91 161.515 40.1 161.705 ;
 RECT 40.47 161.515 40.66 161.705 ;
 RECT 37.67 161.515 37.86 161.705 ;
 RECT 38.23 161.515 38.42 161.705 ;
 RECT 38.79 161.515 38.98 161.705 ;
 RECT 39.35 161.515 39.54 161.705 ;
 RECT 42.15 160.955 42.34 161.145 ;
 RECT 42.71 160.955 42.9 161.145 ;
 RECT 43.27 160.955 43.46 161.145 ;
 RECT 43.83 160.955 44.02 161.145 ;
 RECT 41.03 160.955 41.22 161.145 ;
 RECT 41.59 160.955 41.78 161.145 ;
 RECT 42.15 161.515 42.34 161.705 ;
 RECT 42.71 161.515 42.9 161.705 ;
 RECT 43.27 161.515 43.46 161.705 ;
 RECT 43.83 161.515 44.02 161.705 ;
 RECT 41.59 161.515 41.78 161.705 ;
 RECT 41.03 161.515 41.22 161.705 ;
 RECT 47.19 160.955 47.38 161.145 ;
 RECT 44.39 160.955 44.58 161.145 ;
 RECT 44.95 160.955 45.14 161.145 ;
 RECT 45.51 160.955 45.7 161.145 ;
 RECT 46.07 160.955 46.26 161.145 ;
 RECT 46.63 160.955 46.82 161.145 ;
 RECT 47.19 161.515 47.38 161.705 ;
 RECT 44.39 161.515 44.58 161.705 ;
 RECT 46.63 161.515 46.82 161.705 ;
 RECT 46.07 161.515 46.26 161.705 ;
 RECT 45.51 161.515 45.7 161.705 ;
 RECT 44.95 161.515 45.14 161.705 ;
 RECT 50.55 160.955 50.74 161.145 ;
 RECT 49.99 160.955 50.18 161.145 ;
 RECT 49.43 160.955 49.62 161.145 ;
 RECT 48.87 160.955 49.06 161.145 ;
 RECT 48.31 160.955 48.5 161.145 ;
 RECT 47.75 160.955 47.94 161.145 ;
 RECT 49.43 161.515 49.62 161.705 ;
 RECT 49.99 161.515 50.18 161.705 ;
 RECT 50.55 161.515 50.74 161.705 ;
 RECT 48.87 161.515 49.06 161.705 ;
 RECT 48.31 161.515 48.5 161.705 ;
 RECT 47.75 161.515 47.94 161.705 ;
 RECT 53.91 160.955 54.1 161.145 ;
 RECT 53.35 160.955 53.54 161.145 ;
 RECT 52.79 160.955 52.98 161.145 ;
 RECT 52.23 160.955 52.42 161.145 ;
 RECT 51.67 160.955 51.86 161.145 ;
 RECT 51.11 160.955 51.3 161.145 ;
 RECT 53.91 161.515 54.1 161.705 ;
 RECT 51.67 161.515 51.86 161.705 ;
 RECT 52.23 161.515 52.42 161.705 ;
 RECT 52.79 161.515 52.98 161.705 ;
 RECT 53.35 161.515 53.54 161.705 ;
 RECT 51.11 161.515 51.3 161.705 ;
 RECT 56.15 160.955 56.34 161.145 ;
 RECT 56.71 160.955 56.9 161.145 ;
 RECT 57.27 160.955 57.46 161.145 ;
 RECT 55.03 160.955 55.22 161.145 ;
 RECT 55.59 160.955 55.78 161.145 ;
 RECT 54.47 160.955 54.66 161.145 ;
 RECT 56.15 161.515 56.34 161.705 ;
 RECT 56.71 161.515 56.9 161.705 ;
 RECT 57.27 161.515 57.46 161.705 ;
 RECT 55.59 161.515 55.78 161.705 ;
 RECT 55.03 161.515 55.22 161.705 ;
 RECT 54.47 161.515 54.66 161.705 ;
 RECT 58.95 160.955 59.14 161.145 ;
 RECT 59.51 160.955 59.7 161.145 ;
 RECT 60.07 160.955 60.26 161.145 ;
 RECT 60.63 160.955 60.82 161.145 ;
 RECT 57.83 160.955 58.02 161.145 ;
 RECT 58.39 160.955 58.58 161.145 ;
 RECT 60.63 161.515 60.82 161.705 ;
 RECT 60.07 161.515 60.26 161.705 ;
 RECT 59.51 161.515 59.7 161.705 ;
 RECT 58.95 161.515 59.14 161.705 ;
 RECT 57.83 161.515 58.02 161.705 ;
 RECT 58.39 161.515 58.58 161.705 ;
 RECT 62.31 160.955 62.5 161.145 ;
 RECT 63.43 160.955 63.62 161.145 ;
 RECT 63.99 160.955 64.18 161.145 ;
 RECT 61.75 160.955 61.94 161.145 ;
 RECT 61.19 160.955 61.38 161.145 ;
 RECT 62.87 160.955 63.06 161.145 ;
 RECT 61.19 161.515 61.38 161.705 ;
 RECT 61.75 161.515 61.94 161.705 ;
 RECT 62.31 161.515 62.5 161.705 ;
 RECT 62.87 161.515 63.06 161.705 ;
 RECT 63.43 161.515 63.62 161.705 ;
 RECT 63.99 161.515 64.18 161.705 ;
 RECT 10.79 160.955 10.98 161.145 ;
 RECT 11.91 160.955 12.1 161.145 ;
 RECT 12.47 160.955 12.66 161.145 ;
 RECT 13.03 160.955 13.22 161.145 ;
 RECT 13.59 160.955 13.78 161.145 ;
 RECT 11.35 160.955 11.54 161.145 ;
 RECT 10.79 161.515 10.98 161.705 ;
 RECT 11.35 161.515 11.54 161.705 ;
 RECT 11.91 161.515 12.1 161.705 ;
 RECT 12.47 161.515 12.66 161.705 ;
 RECT 13.03 161.515 13.22 161.705 ;
 RECT 13.59 161.515 13.78 161.705 ;
 RECT 16.95 160.955 17.14 161.145 ;
 RECT 16.39 160.955 16.58 161.145 ;
 RECT 15.83 160.955 16.02 161.145 ;
 RECT 15.27 160.955 15.46 161.145 ;
 RECT 14.71 160.955 14.9 161.145 ;
 RECT 14.15 160.955 14.34 161.145 ;
 RECT 16.39 161.515 16.58 161.705 ;
 RECT 16.95 161.515 17.14 161.705 ;
 RECT 14.15 161.515 14.34 161.705 ;
 RECT 14.71 161.515 14.9 161.705 ;
 RECT 15.27 161.515 15.46 161.705 ;
 RECT 15.83 161.515 16.02 161.705 ;
 RECT 20.31 160.955 20.5 161.145 ;
 RECT 19.75 160.955 19.94 161.145 ;
 RECT 19.19 160.955 19.38 161.145 ;
 RECT 18.63 160.955 18.82 161.145 ;
 RECT 18.07 160.955 18.26 161.145 ;
 RECT 17.51 160.955 17.7 161.145 ;
 RECT 18.63 161.515 18.82 161.705 ;
 RECT 19.19 161.515 19.38 161.705 ;
 RECT 19.75 161.515 19.94 161.705 ;
 RECT 20.31 161.515 20.5 161.705 ;
 RECT 18.07 161.515 18.26 161.705 ;
 RECT 17.51 161.515 17.7 161.705 ;
 RECT 23.67 160.955 23.86 161.145 ;
 RECT 23.11 160.955 23.3 161.145 ;
 RECT 22.55 160.955 22.74 161.145 ;
 RECT 21.99 160.955 22.18 161.145 ;
 RECT 21.43 160.955 21.62 161.145 ;
 RECT 20.87 160.955 21.06 161.145 ;
 RECT 23.67 161.515 23.86 161.705 ;
 RECT 23.11 161.515 23.3 161.705 ;
 RECT 22.55 161.515 22.74 161.705 ;
 RECT 21.99 161.515 22.18 161.705 ;
 RECT 21.43 161.515 21.62 161.705 ;
 RECT 20.87 161.515 21.06 161.705 ;
 RECT 25.91 160.955 26.1 161.145 ;
 RECT 26.47 160.955 26.66 161.145 ;
 RECT 27.03 160.955 27.22 161.145 ;
 RECT 24.23 160.955 24.42 161.145 ;
 RECT 24.79 160.955 24.98 161.145 ;
 RECT 25.35 160.955 25.54 161.145 ;
 RECT 27.03 161.515 27.22 161.705 ;
 RECT 26.47 161.515 26.66 161.705 ;
 RECT 25.91 161.515 26.1 161.705 ;
 RECT 24.23 161.515 24.42 161.705 ;
 RECT 24.79 161.515 24.98 161.705 ;
 RECT 25.35 161.515 25.54 161.705 ;
 RECT 30.39 160.955 30.58 161.145 ;
 RECT 29.83 160.955 30.02 161.145 ;
 RECT 29.27 160.955 29.46 161.145 ;
 RECT 28.71 160.955 28.9 161.145 ;
 RECT 28.15 160.955 28.34 161.145 ;
 RECT 27.59 160.955 27.78 161.145 ;
 RECT 30.39 161.515 30.58 161.705 ;
 RECT 28.15 161.515 28.34 161.705 ;
 RECT 28.71 161.515 28.9 161.705 ;
 END
 END vdda
 PIN vssa
 USE GROUND ;
 DIRECTION INOUT ;
 PORT
 LAYER M5 ;
 RECT 73.415 124.15 75 129.15 ;
 END
 PORT
 LAYER M5 ;
 RECT 0 124.15 1.585 129.15 ;
 END
 PORT
 LAYER M5 ;
 RECT 0 148.13 1.585 152.13 ;
 END
 PORT
 LAYER M5 ;
 RECT 73.415 148.13 75 152.13 ;
 END
 PORT
 LAYER M4 ;
 RECT 73 124.15 75 129.15 ;
 END
 PORT
 LAYER M4 ;
 RECT 0 124.15 2 129.15 ;
 END
 PORT
 LAYER M4 ;
 RECT 0 148.13 2 152.13 ;
 END
 PORT
 LAYER M4 ;
 RECT 73 148.13 75 152.13 ;
 END
 PORT
 LAYER M3 ;
 RECT 73.72 9.91 75 28.65 ;
 END
 PORT
 LAYER M3 ;
 RECT 0 9.91 1.28 28.65 ;
 END
 PORT
 LAYER M3 ;
 RECT 0 31.95 1.28 50.69 ;
 END
 PORT
 LAYER M3 ;
 RECT 73.72 31.95 75 50.69 ;
 END
 END vssa
 OBS
 LAYER GATE ;
 RECT 0 0 75 162 ;
 LAYER MV1 ;
 RECT 0 0 75 162 ;
 LAYER MV2 ;
 RECT 0 0 75 162 ;
 LAYER MV3 ;
 RECT 0 0 75 162 ;
 LAYER MV4 ;
 RECT 0 0 75 162 ;
 LAYER M1 ;
 RECT 0 0 75 162 ;
 LAYER M2 ;
 RECT 65.1 160.22 75 162 ;
 RECT 0 160.22 9.9 162 ;
 RECT 0 0 75 160.22 ;
 LAYER M3 ;
 RECT 0 0 75 9.31 ;
 RECT 0 29.25 75 31.35 ;
 RECT 1.88 9.31 73.12 29.25 ;
 RECT 1.52 160.22 9.9 160.61 ;
 RECT 0 160.61 9.9 162 ;
 RECT 0 51.29 75 53.75 ;
 RECT 1.88 31.35 73.12 51.29 ;
 RECT 0 58.23 75 59.42 ;
 RECT 1.52 53.75 73.48 58.23 ;
 RECT 1.88 66.36 73.12 92.84 ;
 RECT 1.88 94.94 73.12 121.45 ;
 RECT 0 63.9 75 66.36 ;
 RECT 1.52 59.42 73.48 63.9 ;
 RECT 0 92.84 75 94.94 ;
 RECT 0 121.45 75 128.86 ;
 RECT 0 130.24 75 137.06 ;
 RECT 1.52 128.86 73.48 130.24 ;
 RECT 0 151.07 75 157.73 ;
 RECT 1.2 137.06 73.8 151.07 ;
 RECT 1.52 157.73 73.48 160.22 ;
 RECT 65.1 160.22 73.48 160.61 ;
 RECT 65.1 160.61 75 162 ;
 LAYER M4 ;
 RECT 0 0 75 123.91 ;
 RECT 0 129.39 75 130.58 ;
 RECT 2.24 123.91 72.76 129.39 ;
 RECT 2.6 135.39 72.4 147.06 ;
 RECT 0 134.56 75 135.39 ;
 RECT 2.24 130.58 72.76 134.56 ;
 RECT 0 147.06 75 147.89 ;
 RECT 0 152.37 75 153.56 ;
 RECT 2.24 147.89 72.76 152.37 ;
 RECT 0 156.54 75 157.73 ;
 RECT 2.24 153.56 72.76 156.54 ;
 RECT 0 160.71 75 162 ;
 RECT 2.24 157.73 72.76 160.71 ;
 LAYER M5 ;
 RECT 0 9.9 3.9 111.1 ;
 RECT 71.1 9.9 75 111.1 ;
 RECT 0 0 75 9.9 ;
 RECT 0 111.1 75 123.69 ;
 RECT 0 129.61 75 130.36 ;
 RECT 2.045 123.69 72.955 129.61 ;
 RECT 2.185 135.39 72.815 147.06 ;
 RECT 0 134.78 75 135.39 ;
 RECT 2.045 130.36 72.955 134.78 ;
 RECT 0 147.06 75 147.67 ;
 RECT 0 152.59 75 153.34 ;
 RECT 2.045 147.67 72.955 152.59 ;
 RECT 0 156.76 75 157.51 ;
 RECT 2.045 153.34 72.955 156.76 ;
 RECT 0 160.93 75 162 ;
 RECT 2.045 157.51 72.955 160.93 ;
 END
END RCMCU_PLVDDA

MACRO RCMCU_PLVDDH
 CLASS PAD ;
 FOREIGN RCMCU_PLVDDH ;
 ORIGIN 0 0 ;
 SIZE 75 BY 162 ;
 SYMMETRY X Y R90 ;
 PIN POC
 USE POWER ;
 DIRECTION INOUT ;
 PORT
 LAYER M3 ;
 RECT 73.72 129.1 75 130 ;
 END
 PORT
 LAYER M3 ;
 RECT 0 129.1 1.28 130 ;
 END
 END POC
 PIN gnd
 USE GROUND ;
 DIRECTION INOUT ;
 PORT
 LAYER M5 ;
 RECT 73.415 135.99 75 146.46 ;
 END
 PORT
 LAYER M5 ;
 RECT 0 135.99 1.585 146.46 ;
 END
 PORT
 LAYER M5 ;
 RECT 0 157.97 1.585 160.47 ;
 END
 PORT
 LAYER M5 ;
 RECT 73.415 157.97 75 160.47 ;
 END
 PORT
 LAYER M4 ;
 RECT 73 135.99 75 146.46 ;
 END
 PORT
 LAYER M4 ;
 RECT 0 135.99 2 146.46 ;
 END
 PORT
 LAYER M4 ;
 RECT 0 157.97 1.585 160.47 ;
 END
 PORT
 LAYER M4 ;
 RECT 73.415 157.97 75 160.47 ;
 END
 PORT
 LAYER M3 ;
 RECT 73.72 59.66 75 63.66 ;
 END
 PORT
 LAYER M3 ;
 RECT 0 59.66 1.28 63.66 ;
 END
 PORT
 LAYER M3 ;
 RECT 0 157.97 1.585 160.37 ;
 END
 PORT
 LAYER M3 ;
 RECT 73.415 157.97 75 160.37 ;
 END
 PORT
 LAYER MV3 ;
 RECT 73.6 158.44 73.79 158.63 ;
 RECT 74.21 158.44 74.4 158.63 ;
 RECT 73.6 159.05 73.79 159.24 ;
 RECT 74.21 159.05 74.4 159.24 ;
 RECT 73.6 159.66 73.79 159.85 ;
 RECT 74.21 159.66 74.4 159.85 ;
 RECT 0.6 158.44 0.79 158.63 ;
 RECT 1.21 158.44 1.4 158.63 ;
 RECT 0.6 159.05 0.79 159.24 ;
 RECT 1.21 159.05 1.4 159.24 ;
 RECT 0.6 159.66 0.79 159.85 ;
 RECT 1.21 159.66 1.4 159.85 ;
 END
 END gnd
 PIN vdd
 USE POWER ;
 DIRECTION INOUT ;
 PORT
 LAYER M5 ;
 RECT 73.415 153.8 75 156.3 ;
 END
 PORT
 LAYER M5 ;
 RECT 0 153.8 1.585 156.3 ;
 END
 PORT
 LAYER M4 ;
 RECT 73 153.8 75 156.3 ;
 END
 PORT
 LAYER M4 ;
 RECT 0 153.8 2 156.3 ;
 END
 END vdd
 PIN vddh
 USE POWER ;
 DIRECTION INOUT ;
 PORT
 LAYER M5 ;
 RECT 4.5 10.5 70.5 110.5 ;
 END
 PORT
 LAYER M5 ;
 RECT 0 130.82 1.585 134.32 ;
 END
 PORT
 LAYER M5 ;
 RECT 73.415 130.82 75 134.32 ;
 END
 PORT
 LAYER M4 ;
 RECT 73 130.82 75 134.32 ;
 END
 PORT
 LAYER M4 ;
 RECT 0 130.82 2 134.32 ;
 END
 PORT
 LAYER M3 ;
 RECT 73.72 53.99 75 57.99 ;
 END
 PORT
 LAYER M3 ;
 RECT 0 53.99 1.28 57.99 ;
 END
 PORT
 LAYER M3 ;
 RECT 73.72 66.96 75 92.24 ;
 END
 PORT
 LAYER M3 ;
 RECT 0 66.96 1.28 92.24 ;
 END
 PORT
 LAYER M3 ;
 RECT 0 95.54 1.28 120.85 ;
 END
 PORT
 LAYER M3 ;
 RECT 73.72 95.54 75 120.85 ;
 END
 PORT
 LAYER M3 ;
 RECT 0 137.66 0.6 150.47 ;
 END
 PORT
 LAYER M3 ;
 RECT 74.4 137.66 75 150.47 ;
 END
 PORT
 LAYER M3 ;
 RECT 10.5 160.82 64.5 162 ;
 END
 PORT
 LAYER M2 ;
 RECT 10.5 160.82 64.5 162 ;
 END
 PORT
 LAYER MV2 ;
 RECT 32.615 160.955 32.805 161.145 ;
 RECT 33.175 161.515 33.365 161.705 ;
 RECT 33.735 161.515 33.925 161.705 ;
 RECT 32.615 161.515 32.805 161.705 ;
 RECT 32.055 161.515 32.245 161.705 ;
 RECT 31.495 161.515 31.685 161.705 ;
 RECT 30.935 161.515 31.125 161.705 ;
 RECT 37.095 160.955 37.285 161.145 ;
 RECT 36.535 160.955 36.725 161.145 ;
 RECT 35.975 160.955 36.165 161.145 ;
 RECT 35.415 160.955 35.605 161.145 ;
 RECT 34.855 160.955 35.045 161.145 ;
 RECT 34.295 160.955 34.485 161.145 ;
 RECT 37.095 161.515 37.285 161.705 ;
 RECT 36.535 161.515 36.725 161.705 ;
 RECT 35.975 161.515 36.165 161.705 ;
 RECT 35.415 161.515 35.605 161.705 ;
 RECT 34.295 161.515 34.485 161.705 ;
 RECT 34.855 161.515 35.045 161.705 ;
 RECT 39.895 160.955 40.085 161.145 ;
 RECT 40.455 160.955 40.645 161.145 ;
 RECT 39.335 160.955 39.525 161.145 ;
 RECT 38.775 160.955 38.965 161.145 ;
 RECT 38.215 160.955 38.405 161.145 ;
 RECT 37.655 160.955 37.845 161.145 ;
 RECT 39.895 161.515 40.085 161.705 ;
 RECT 40.455 161.515 40.645 161.705 ;
 RECT 37.655 161.515 37.845 161.705 ;
 RECT 38.215 161.515 38.405 161.705 ;
 RECT 38.775 161.515 38.965 161.705 ;
 RECT 39.335 161.515 39.525 161.705 ;
 RECT 42.135 160.955 42.325 161.145 ;
 RECT 42.695 160.955 42.885 161.145 ;
 RECT 43.255 160.955 43.445 161.145 ;
 RECT 43.815 160.955 44.005 161.145 ;
 RECT 41.015 160.955 41.205 161.145 ;
 RECT 41.575 160.955 41.765 161.145 ;
 RECT 42.135 161.515 42.325 161.705 ;
 RECT 42.695 161.515 42.885 161.705 ;
 RECT 43.255 161.515 43.445 161.705 ;
 RECT 43.815 161.515 44.005 161.705 ;
 RECT 41.575 161.515 41.765 161.705 ;
 RECT 41.015 161.515 41.205 161.705 ;
 RECT 47.175 160.955 47.365 161.145 ;
 RECT 44.375 160.955 44.565 161.145 ;
 RECT 44.935 160.955 45.125 161.145 ;
 RECT 45.495 160.955 45.685 161.145 ;
 RECT 46.055 160.955 46.245 161.145 ;
 RECT 46.615 160.955 46.805 161.145 ;
 RECT 47.175 161.515 47.365 161.705 ;
 RECT 44.375 161.515 44.565 161.705 ;
 RECT 46.615 161.515 46.805 161.705 ;
 RECT 46.055 161.515 46.245 161.705 ;
 RECT 45.495 161.515 45.685 161.705 ;
 RECT 44.935 161.515 45.125 161.705 ;
 RECT 50.535 160.955 50.725 161.145 ;
 RECT 49.975 160.955 50.165 161.145 ;
 RECT 49.415 160.955 49.605 161.145 ;
 RECT 48.855 160.955 49.045 161.145 ;
 RECT 48.295 160.955 48.485 161.145 ;
 RECT 47.735 160.955 47.925 161.145 ;
 RECT 49.415 161.515 49.605 161.705 ;
 RECT 49.975 161.515 50.165 161.705 ;
 RECT 50.535 161.515 50.725 161.705 ;
 RECT 48.855 161.515 49.045 161.705 ;
 RECT 48.295 161.515 48.485 161.705 ;
 RECT 47.735 161.515 47.925 161.705 ;
 RECT 53.895 160.955 54.085 161.145 ;
 RECT 53.335 160.955 53.525 161.145 ;
 RECT 52.775 160.955 52.965 161.145 ;
 RECT 52.215 160.955 52.405 161.145 ;
 RECT 51.655 160.955 51.845 161.145 ;
 RECT 51.095 160.955 51.285 161.145 ;
 RECT 53.895 161.515 54.085 161.705 ;
 RECT 51.655 161.515 51.845 161.705 ;
 RECT 52.215 161.515 52.405 161.705 ;
 RECT 52.775 161.515 52.965 161.705 ;
 RECT 53.335 161.515 53.525 161.705 ;
 RECT 51.095 161.515 51.285 161.705 ;
 RECT 56.135 160.955 56.325 161.145 ;
 RECT 56.695 160.955 56.885 161.145 ;
 RECT 57.255 160.955 57.445 161.145 ;
 RECT 55.015 160.955 55.205 161.145 ;
 RECT 55.575 160.955 55.765 161.145 ;
 RECT 54.455 160.955 54.645 161.145 ;
 RECT 56.135 161.515 56.325 161.705 ;
 RECT 56.695 161.515 56.885 161.705 ;
 RECT 57.255 161.515 57.445 161.705 ;
 RECT 55.575 161.515 55.765 161.705 ;
 RECT 55.015 161.515 55.205 161.705 ;
 RECT 54.455 161.515 54.645 161.705 ;
 RECT 58.935 160.955 59.125 161.145 ;
 RECT 59.495 160.955 59.685 161.145 ;
 RECT 60.055 160.955 60.245 161.145 ;
 RECT 60.615 160.955 60.805 161.145 ;
 RECT 57.815 160.955 58.005 161.145 ;
 RECT 58.375 160.955 58.565 161.145 ;
 RECT 60.615 161.515 60.805 161.705 ;
 RECT 60.055 161.515 60.245 161.705 ;
 RECT 59.495 161.515 59.685 161.705 ;
 RECT 58.935 161.515 59.125 161.705 ;
 RECT 57.815 161.515 58.005 161.705 ;
 RECT 58.375 161.515 58.565 161.705 ;
 RECT 62.295 160.955 62.485 161.145 ;
 RECT 63.415 160.955 63.605 161.145 ;
 RECT 63.975 160.955 64.165 161.145 ;
 RECT 61.735 160.955 61.925 161.145 ;
 RECT 61.175 160.955 61.365 161.145 ;
 RECT 62.855 160.955 63.045 161.145 ;
 RECT 61.175 161.515 61.365 161.705 ;
 RECT 61.735 161.515 61.925 161.705 ;
 RECT 62.295 161.515 62.485 161.705 ;
 RECT 62.855 161.515 63.045 161.705 ;
 RECT 63.415 161.515 63.605 161.705 ;
 RECT 63.975 161.515 64.165 161.705 ;
 RECT 10.775 160.955 10.965 161.145 ;
 RECT 11.895 160.955 12.085 161.145 ;
 RECT 12.455 160.955 12.645 161.145 ;
 RECT 13.015 160.955 13.205 161.145 ;
 RECT 13.575 160.955 13.765 161.145 ;
 RECT 11.335 160.955 11.525 161.145 ;
 RECT 10.775 161.515 10.965 161.705 ;
 RECT 11.335 161.515 11.525 161.705 ;
 RECT 11.895 161.515 12.085 161.705 ;
 RECT 12.455 161.515 12.645 161.705 ;
 RECT 13.015 161.515 13.205 161.705 ;
 RECT 13.575 161.515 13.765 161.705 ;
 RECT 16.935 160.955 17.125 161.145 ;
 RECT 16.375 160.955 16.565 161.145 ;
 RECT 15.815 160.955 16.005 161.145 ;
 RECT 15.255 160.955 15.445 161.145 ;
 RECT 14.695 160.955 14.885 161.145 ;
 RECT 14.135 160.955 14.325 161.145 ;
 RECT 16.375 161.515 16.565 161.705 ;
 RECT 16.935 161.515 17.125 161.705 ;
 RECT 14.135 161.515 14.325 161.705 ;
 RECT 14.695 161.515 14.885 161.705 ;
 RECT 15.255 161.515 15.445 161.705 ;
 RECT 15.815 161.515 16.005 161.705 ;
 RECT 20.295 160.955 20.485 161.145 ;
 RECT 19.735 160.955 19.925 161.145 ;
 RECT 19.175 160.955 19.365 161.145 ;
 RECT 18.615 160.955 18.805 161.145 ;
 RECT 18.055 160.955 18.245 161.145 ;
 RECT 17.495 160.955 17.685 161.145 ;
 RECT 18.615 161.515 18.805 161.705 ;
 RECT 19.175 161.515 19.365 161.705 ;
 RECT 19.735 161.515 19.925 161.705 ;
 RECT 20.295 161.515 20.485 161.705 ;
 RECT 18.055 161.515 18.245 161.705 ;
 RECT 17.495 161.515 17.685 161.705 ;
 RECT 23.655 160.955 23.845 161.145 ;
 RECT 23.095 160.955 23.285 161.145 ;
 RECT 22.535 160.955 22.725 161.145 ;
 RECT 21.975 160.955 22.165 161.145 ;
 RECT 21.415 160.955 21.605 161.145 ;
 RECT 20.855 160.955 21.045 161.145 ;
 RECT 23.655 161.515 23.845 161.705 ;
 RECT 23.095 161.515 23.285 161.705 ;
 RECT 22.535 161.515 22.725 161.705 ;
 RECT 21.975 161.515 22.165 161.705 ;
 RECT 21.415 161.515 21.605 161.705 ;
 RECT 20.855 161.515 21.045 161.705 ;
 RECT 25.895 160.955 26.085 161.145 ;
 RECT 26.455 160.955 26.645 161.145 ;
 RECT 27.015 160.955 27.205 161.145 ;
 RECT 24.215 160.955 24.405 161.145 ;
 RECT 24.775 160.955 24.965 161.145 ;
 RECT 25.335 160.955 25.525 161.145 ;
 RECT 27.015 161.515 27.205 161.705 ;
 RECT 26.455 161.515 26.645 161.705 ;
 RECT 25.895 161.515 26.085 161.705 ;
 RECT 24.215 161.515 24.405 161.705 ;
 RECT 24.775 161.515 24.965 161.705 ;
 RECT 25.335 161.515 25.525 161.705 ;
 RECT 30.375 160.955 30.565 161.145 ;
 RECT 29.815 160.955 30.005 161.145 ;
 RECT 29.255 160.955 29.445 161.145 ;
 RECT 28.695 160.955 28.885 161.145 ;
 RECT 28.135 160.955 28.325 161.145 ;
 RECT 27.575 160.955 27.765 161.145 ;
 RECT 30.375 161.515 30.565 161.705 ;
 RECT 28.135 161.515 28.325 161.705 ;
 RECT 28.695 161.515 28.885 161.705 ;
 RECT 29.255 161.515 29.445 161.705 ;
 RECT 29.815 161.515 30.005 161.705 ;
 RECT 27.575 161.515 27.765 161.705 ;
 RECT 33.735 160.955 33.925 161.145 ;
 RECT 33.175 160.955 33.365 161.145 ;
 RECT 30.935 160.955 31.125 161.145 ;
 RECT 31.495 160.955 31.685 161.145 ;
 RECT 32.055 160.955 32.245 161.145 ;
 END
 END vddh
 PIN vssh
 USE GROUND ;
 DIRECTION INOUT ;
 PORT
 LAYER M5 ;
 RECT 73.415 124.15 75 129.15 ;
 END
 PORT
 LAYER M5 ;
 RECT 0 124.15 1.585 129.15 ;
 END
 PORT
 LAYER M5 ;
 RECT 0 148.13 1.585 152.13 ;
 END
 PORT
 LAYER M5 ;
 RECT 73.415 148.13 75 152.13 ;
 END
 PORT
 LAYER M4 ;
 RECT 73 124.15 75 129.15 ;
 END
 PORT
 LAYER M4 ;
 RECT 0 124.15 2 129.15 ;
 END
 PORT
 LAYER M4 ;
 RECT 0 148.13 2 152.13 ;
 END
 PORT
 LAYER M4 ;
 RECT 73 148.13 75 152.13 ;
 END
 PORT
 LAYER M3 ;
 RECT 73.72 9.91 75 28.65 ;
 END
 PORT
 LAYER M3 ;
 RECT 0 9.91 1.28 28.65 ;
 END
 PORT
 LAYER M3 ;
 RECT 0 31.95 1.28 50.69 ;
 END
 PORT
 LAYER M3 ;
 RECT 73.72 31.95 75 50.69 ;
 END
 END vssh
 OBS
 LAYER GATE ;
 RECT 0 0 75 162 ;
 LAYER MV1 ;
 RECT 0 0 75 162 ;
 LAYER MV2 ;
 RECT 0 0 75 162 ;
 LAYER MV3 ;
 RECT 0 0 75 162 ;
 LAYER MV4 ;
 RECT 0 0 75 162 ;
 LAYER M1 ;
 RECT 0 0 75 162 ;
 LAYER M2 ;
 RECT 65.1 160.22 75 162 ;
 RECT 0 160.22 9.9 162 ;
 RECT 0 0 75 160.22 ;
 LAYER M3 ;
 RECT 0 29.25 75 31.35 ;
 RECT 1.88 9.31 73.12 29.25 ;
 RECT 1.825 160.22 9.9 160.61 ;
 RECT 0 160.61 9.9 162 ;
 RECT 0 51.29 75 53.75 ;
 RECT 1.88 31.35 73.12 51.29 ;
 RECT 0 58.23 75 59.42 ;
 RECT 1.52 53.75 73.48 58.23 ;
 RECT 1.88 66.36 73.12 92.84 ;
 RECT 1.88 94.94 73.12 121.45 ;
 RECT 1.825 157.73 73.175 160.22 ;
 RECT 65.1 160.22 73.175 160.61 ;
 RECT 0 63.9 75 66.36 ;
 RECT 1.52 59.42 73.48 63.9 ;
 RECT 0 92.84 75 94.94 ;
 RECT 0 121.45 75 128.86 ;
 RECT 0 130.24 75 137.06 ;
 RECT 1.52 128.86 73.48 130.24 ;
 RECT 0 151.07 75 157.73 ;
 RECT 1.2 137.06 73.8 151.07 ;
 RECT 65.1 160.61 75 162 ;
 RECT 0 0 75 9.31 ;
 LAYER M4 ;
 RECT 0 0 75 123.91 ;
 RECT 0 129.39 75 130.58 ;
 RECT 2.24 123.91 72.76 129.39 ;
 RECT 2.6 135.39 72.4 147.06 ;
 RECT 0 134.56 75 135.39 ;
 RECT 2.24 130.58 72.76 134.56 ;
 RECT 0 147.06 75 147.89 ;
 RECT 0 152.37 75 153.56 ;
 RECT 2.24 147.89 72.76 152.37 ;
 RECT 0 156.54 75 157.73 ;
 RECT 2.24 153.56 72.76 156.54 ;
 RECT 0 160.71 75 162 ;
 RECT 1.825 157.73 73.175 160.71 ;
 LAYER M5 ;
 RECT 0 9.9 3.9 111.1 ;
 RECT 71.1 9.9 75 111.1 ;
 RECT 0 0 75 9.9 ;
 RECT 0 111.1 75 123.69 ;
 RECT 0 129.61 75 130.36 ;
 RECT 2.045 123.69 72.955 129.61 ;
 RECT 2.185 135.39 72.815 147.06 ;
 RECT 0 134.78 75 135.39 ;
 RECT 2.045 130.36 72.955 134.78 ;
 RECT 0 147.06 75 147.67 ;
 RECT 0 152.59 75 153.34 ;
 RECT 2.045 147.67 72.955 152.59 ;
 RECT 0 156.76 75 157.51 ;
 RECT 2.045 153.34 72.955 156.76 ;
 RECT 0 160.93 75 162 ;
 RECT 2.045 157.51 72.955 160.93 ;
 END
END RCMCU_PLVDDH

MACRO RCMCU_PLVDDHA
 CLASS PAD ;
 FOREIGN RCMCU_PLVDDHA ;
 ORIGIN 0 0 ;
 SIZE 75 BY 162 ;
 SYMMETRY X Y R90 ;
 PIN POC
 USE POWER ;
 DIRECTION INOUT ;
 PORT
 LAYER M3 ;
 RECT 73.72 129.1 75 130 ;
 END
 PORT
 LAYER M3 ;
 RECT 0 129.1 1.28 130 ;
 END
 END POC
 PIN gnd
 USE GROUND ;
 DIRECTION INOUT ;
 PORT
 LAYER M5 ;
 RECT 73.415 135.99 75 146.46 ;
 END
 PORT
 LAYER M5 ;
 RECT 0 135.99 1.585 146.46 ;
 END
 PORT
 LAYER M5 ;
 RECT 0 157.97 1.585 160.47 ;
 END
 PORT
 LAYER M5 ;
 RECT 73.415 157.97 75 160.47 ;
 END
 PORT
 LAYER M4 ;
 RECT 73 135.99 75 146.46 ;
 END
 PORT
 LAYER M4 ;
 RECT 0 135.99 2 146.46 ;
 END
 PORT
 LAYER M4 ;
 RECT 0 157.97 2 160.47 ;
 END
 PORT
 LAYER M4 ;
 RECT 73 157.97 75 160.47 ;
 END
 PORT
 LAYER M3 ;
 RECT 73.72 59.66 75 63.66 ;
 END
 PORT
 LAYER M3 ;
 RECT 0 59.66 1.28 63.66 ;
 END
 PORT
 LAYER M3 ;
 RECT 0 157.97 1.28 160.37 ;
 END
 PORT
 LAYER M3 ;
 RECT 73.72 157.97 75 160.37 ;
 END
 PORT
 LAYER MV3 ;
 RECT 74.175 158.525 74.365 158.715 ;
 RECT 74.175 159.325 74.365 159.515 ;
 RECT 0.635 158.525 0.825 158.715 ;
 RECT 0.635 159.325 0.825 159.515 ;
 END
 END gnd
 PIN vdd
 USE POWER ;
 DIRECTION INOUT ;
 PORT
 LAYER M5 ;
 RECT 73.415 153.8 75 156.3 ;
 END
 PORT
 LAYER M5 ;
 RECT 0 153.8 1.585 156.3 ;
 END
 PORT
 LAYER M4 ;
 RECT 73 153.8 75 156.3 ;
 END
 PORT
 LAYER M4 ;
 RECT 0 153.8 2 156.3 ;
 END
 END vdd
 PIN vddha
 USE POWER ;
 DIRECTION INOUT ;
 PORT
 LAYER M5 ;
 RECT 4.5 10.5 70.5 110.5 ;
 END
 PORT
 LAYER M5 ;
 RECT 0 130.82 1.585 134.32 ;
 END
 PORT
 LAYER M5 ;
 RECT 73.415 130.82 75 134.32 ;
 END
 PORT
 LAYER M4 ;
 RECT 73 130.82 75 134.32 ;
 END
 PORT
 LAYER M4 ;
 RECT 0 130.82 2 134.32 ;
 END
 PORT
 LAYER M3 ;
 RECT 73.72 53.99 75 57.99 ;
 END
 PORT
 LAYER M3 ;
 RECT 0 53.99 1.28 57.99 ;
 END
 PORT
 LAYER M3 ;
 RECT 73.72 66.96 75 92.24 ;
 END
 PORT
 LAYER M3 ;
 RECT 0 66.96 1.28 92.24 ;
 END
 PORT
 LAYER M3 ;
 RECT 0 95.54 1.28 120.85 ;
 END
 PORT
 LAYER M3 ;
 RECT 73.72 95.54 75 120.85 ;
 END
 PORT
 LAYER M3 ;
 RECT 0 137.66 0.6 150.47 ;
 END
 PORT
 LAYER M3 ;
 RECT 74.4 137.66 75 150.47 ;
 END
 PORT
 LAYER M3 ;
 RECT 10.5 160.82 64.5 162 ;
 END
 PORT
 LAYER M2 ;
 RECT 10.5 160.82 64.5 162 ;
 END
 PORT
 LAYER MV2 ;
 RECT 29.255 161.515 29.445 161.705 ;
 RECT 29.815 161.515 30.005 161.705 ;
 RECT 27.575 161.515 27.765 161.705 ;
 RECT 33.735 160.955 33.925 161.145 ;
 RECT 33.175 160.955 33.365 161.145 ;
 RECT 30.935 160.955 31.125 161.145 ;
 RECT 31.495 160.955 31.685 161.145 ;
 RECT 32.055 160.955 32.245 161.145 ;
 RECT 32.615 160.955 32.805 161.145 ;
 RECT 33.175 161.515 33.365 161.705 ;
 RECT 33.735 161.515 33.925 161.705 ;
 RECT 32.615 161.515 32.805 161.705 ;
 RECT 32.055 161.515 32.245 161.705 ;
 RECT 31.495 161.515 31.685 161.705 ;
 RECT 30.935 161.515 31.125 161.705 ;
 RECT 37.095 160.955 37.285 161.145 ;
 RECT 36.535 160.955 36.725 161.145 ;
 RECT 35.975 160.955 36.165 161.145 ;
 RECT 35.415 160.955 35.605 161.145 ;
 RECT 34.855 160.955 35.045 161.145 ;
 RECT 34.295 160.955 34.485 161.145 ;
 RECT 37.095 161.515 37.285 161.705 ;
 RECT 36.535 161.515 36.725 161.705 ;
 RECT 35.975 161.515 36.165 161.705 ;
 RECT 35.415 161.515 35.605 161.705 ;
 RECT 34.295 161.515 34.485 161.705 ;
 RECT 34.855 161.515 35.045 161.705 ;
 RECT 39.895 160.955 40.085 161.145 ;
 RECT 40.455 160.955 40.645 161.145 ;
 RECT 39.335 160.955 39.525 161.145 ;
 RECT 38.775 160.955 38.965 161.145 ;
 RECT 38.215 160.955 38.405 161.145 ;
 RECT 37.655 160.955 37.845 161.145 ;
 RECT 39.895 161.515 40.085 161.705 ;
 RECT 40.455 161.515 40.645 161.705 ;
 RECT 37.655 161.515 37.845 161.705 ;
 RECT 38.215 161.515 38.405 161.705 ;
 RECT 38.775 161.515 38.965 161.705 ;
 RECT 39.335 161.515 39.525 161.705 ;
 RECT 42.135 160.955 42.325 161.145 ;
 RECT 42.695 160.955 42.885 161.145 ;
 RECT 43.255 160.955 43.445 161.145 ;
 RECT 43.815 160.955 44.005 161.145 ;
 RECT 41.015 160.955 41.205 161.145 ;
 RECT 41.575 160.955 41.765 161.145 ;
 RECT 42.135 161.515 42.325 161.705 ;
 RECT 42.695 161.515 42.885 161.705 ;
 RECT 43.255 161.515 43.445 161.705 ;
 RECT 43.815 161.515 44.005 161.705 ;
 RECT 41.575 161.515 41.765 161.705 ;
 RECT 41.015 161.515 41.205 161.705 ;
 RECT 47.175 160.955 47.365 161.145 ;
 RECT 44.375 160.955 44.565 161.145 ;
 RECT 44.935 160.955 45.125 161.145 ;
 RECT 45.495 160.955 45.685 161.145 ;
 RECT 46.055 160.955 46.245 161.145 ;
 RECT 46.615 160.955 46.805 161.145 ;
 RECT 47.175 161.515 47.365 161.705 ;
 RECT 44.375 161.515 44.565 161.705 ;
 RECT 46.615 161.515 46.805 161.705 ;
 RECT 46.055 161.515 46.245 161.705 ;
 RECT 45.495 161.515 45.685 161.705 ;
 RECT 44.935 161.515 45.125 161.705 ;
 RECT 50.535 160.955 50.725 161.145 ;
 RECT 49.975 160.955 50.165 161.145 ;
 RECT 49.415 160.955 49.605 161.145 ;
 RECT 48.855 160.955 49.045 161.145 ;
 RECT 48.295 160.955 48.485 161.145 ;
 RECT 47.735 160.955 47.925 161.145 ;
 RECT 49.415 161.515 49.605 161.705 ;
 RECT 49.975 161.515 50.165 161.705 ;
 RECT 50.535 161.515 50.725 161.705 ;
 RECT 48.855 161.515 49.045 161.705 ;
 RECT 48.295 161.515 48.485 161.705 ;
 RECT 47.735 161.515 47.925 161.705 ;
 RECT 53.895 160.955 54.085 161.145 ;
 RECT 53.335 160.955 53.525 161.145 ;
 RECT 52.775 160.955 52.965 161.145 ;
 RECT 52.215 160.955 52.405 161.145 ;
 RECT 51.655 160.955 51.845 161.145 ;
 RECT 51.095 160.955 51.285 161.145 ;
 RECT 53.895 161.515 54.085 161.705 ;
 RECT 51.655 161.515 51.845 161.705 ;
 RECT 52.215 161.515 52.405 161.705 ;
 RECT 52.775 161.515 52.965 161.705 ;
 RECT 53.335 161.515 53.525 161.705 ;
 RECT 51.095 161.515 51.285 161.705 ;
 RECT 56.135 160.955 56.325 161.145 ;
 RECT 56.695 160.955 56.885 161.145 ;
 RECT 57.255 160.955 57.445 161.145 ;
 RECT 55.015 160.955 55.205 161.145 ;
 RECT 55.575 160.955 55.765 161.145 ;
 RECT 54.455 160.955 54.645 161.145 ;
 RECT 56.135 161.515 56.325 161.705 ;
 RECT 56.695 161.515 56.885 161.705 ;
 RECT 57.255 161.515 57.445 161.705 ;
 RECT 55.575 161.515 55.765 161.705 ;
 RECT 55.015 161.515 55.205 161.705 ;
 RECT 54.455 161.515 54.645 161.705 ;
 RECT 58.935 160.955 59.125 161.145 ;
 RECT 59.495 160.955 59.685 161.145 ;
 RECT 60.055 160.955 60.245 161.145 ;
 RECT 60.615 160.955 60.805 161.145 ;
 RECT 57.815 160.955 58.005 161.145 ;
 RECT 58.375 160.955 58.565 161.145 ;
 RECT 60.615 161.515 60.805 161.705 ;
 RECT 60.055 161.515 60.245 161.705 ;
 RECT 59.495 161.515 59.685 161.705 ;
 RECT 58.935 161.515 59.125 161.705 ;
 RECT 57.815 161.515 58.005 161.705 ;
 RECT 58.375 161.515 58.565 161.705 ;
 RECT 62.295 160.955 62.485 161.145 ;
 RECT 63.415 160.955 63.605 161.145 ;
 RECT 63.975 160.955 64.165 161.145 ;
 RECT 61.735 160.955 61.925 161.145 ;
 RECT 61.175 160.955 61.365 161.145 ;
 RECT 62.855 160.955 63.045 161.145 ;
 RECT 61.175 161.515 61.365 161.705 ;
 RECT 61.735 161.515 61.925 161.705 ;
 RECT 62.295 161.515 62.485 161.705 ;
 RECT 62.855 161.515 63.045 161.705 ;
 RECT 63.415 161.515 63.605 161.705 ;
 RECT 63.975 161.515 64.165 161.705 ;
 RECT 10.775 160.955 10.965 161.145 ;
 RECT 11.895 160.955 12.085 161.145 ;
 RECT 12.455 160.955 12.645 161.145 ;
 RECT 13.015 160.955 13.205 161.145 ;
 RECT 13.575 160.955 13.765 161.145 ;
 RECT 11.335 160.955 11.525 161.145 ;
 RECT 10.775 161.515 10.965 161.705 ;
 RECT 11.335 161.515 11.525 161.705 ;
 RECT 11.895 161.515 12.085 161.705 ;
 RECT 12.455 161.515 12.645 161.705 ;
 RECT 13.015 161.515 13.205 161.705 ;
 RECT 13.575 161.515 13.765 161.705 ;
 RECT 16.935 160.955 17.125 161.145 ;
 RECT 16.375 160.955 16.565 161.145 ;
 RECT 15.815 160.955 16.005 161.145 ;
 RECT 15.255 160.955 15.445 161.145 ;
 RECT 14.695 160.955 14.885 161.145 ;
 RECT 14.135 160.955 14.325 161.145 ;
 RECT 16.375 161.515 16.565 161.705 ;
 RECT 16.935 161.515 17.125 161.705 ;
 RECT 14.135 161.515 14.325 161.705 ;
 RECT 14.695 161.515 14.885 161.705 ;
 RECT 15.255 161.515 15.445 161.705 ;
 RECT 15.815 161.515 16.005 161.705 ;
 RECT 20.295 160.955 20.485 161.145 ;
 RECT 19.735 160.955 19.925 161.145 ;
 RECT 19.175 160.955 19.365 161.145 ;
 RECT 18.615 160.955 18.805 161.145 ;
 RECT 18.055 160.955 18.245 161.145 ;
 RECT 17.495 160.955 17.685 161.145 ;
 RECT 18.615 161.515 18.805 161.705 ;
 RECT 19.175 161.515 19.365 161.705 ;
 RECT 19.735 161.515 19.925 161.705 ;
 RECT 20.295 161.515 20.485 161.705 ;
 RECT 18.055 161.515 18.245 161.705 ;
 RECT 17.495 161.515 17.685 161.705 ;
 RECT 23.655 160.955 23.845 161.145 ;
 RECT 23.095 160.955 23.285 161.145 ;
 RECT 22.535 160.955 22.725 161.145 ;
 RECT 21.975 160.955 22.165 161.145 ;
 RECT 21.415 160.955 21.605 161.145 ;
 RECT 20.855 160.955 21.045 161.145 ;
 RECT 23.655 161.515 23.845 161.705 ;
 RECT 23.095 161.515 23.285 161.705 ;
 RECT 22.535 161.515 22.725 161.705 ;
 RECT 21.975 161.515 22.165 161.705 ;
 RECT 21.415 161.515 21.605 161.705 ;
 RECT 20.855 161.515 21.045 161.705 ;
 RECT 25.895 160.955 26.085 161.145 ;
 RECT 26.455 160.955 26.645 161.145 ;
 RECT 27.015 160.955 27.205 161.145 ;
 RECT 24.215 160.955 24.405 161.145 ;
 RECT 24.775 160.955 24.965 161.145 ;
 RECT 25.335 160.955 25.525 161.145 ;
 RECT 27.015 161.515 27.205 161.705 ;
 RECT 26.455 161.515 26.645 161.705 ;
 RECT 25.895 161.515 26.085 161.705 ;
 RECT 24.215 161.515 24.405 161.705 ;
 RECT 24.775 161.515 24.965 161.705 ;
 RECT 25.335 161.515 25.525 161.705 ;
 RECT 30.375 160.955 30.565 161.145 ;
 RECT 29.815 160.955 30.005 161.145 ;
 RECT 29.255 160.955 29.445 161.145 ;
 RECT 28.695 160.955 28.885 161.145 ;
 RECT 28.135 160.955 28.325 161.145 ;
 RECT 27.575 160.955 27.765 161.145 ;
 RECT 30.375 161.515 30.565 161.705 ;
 RECT 28.135 161.515 28.325 161.705 ;
 RECT 28.695 161.515 28.885 161.705 ;
 END
 END vddha
 PIN vssha
 USE GROUND ;
 DIRECTION INOUT ;
 PORT
 LAYER M5 ;
 RECT 73.415 124.15 75 129.15 ;
 END
 PORT
 LAYER M5 ;
 RECT 0 124.15 1.585 129.15 ;
 END
 PORT
 LAYER M5 ;
 RECT 0 148.13 1.585 152.13 ;
 END
 PORT
 LAYER M5 ;
 RECT 73.415 148.13 75 152.13 ;
 END
 PORT
 LAYER M4 ;
 RECT 73 124.15 75 129.15 ;
 END
 PORT
 LAYER M4 ;
 RECT 0 124.15 2 129.15 ;
 END
 PORT
 LAYER M4 ;
 RECT 0 148.13 2 152.13 ;
 END
 PORT
 LAYER M4 ;
 RECT 73 148.13 75 152.13 ;
 END
 PORT
 LAYER M3 ;
 RECT 73.72 9.91 75 28.65 ;
 END
 PORT
 LAYER M3 ;
 RECT 0 9.91 1.28 28.65 ;
 END
 PORT
 LAYER M3 ;
 RECT 0 31.95 1.28 50.69 ;
 END
 PORT
 LAYER M3 ;
 RECT 73.72 31.95 75 50.69 ;
 END
 END vssha
 OBS
 LAYER GATE ;
 RECT 0 0 75 162 ;
 LAYER MV1 ;
 RECT 0 0 75 162 ;
 LAYER MV2 ;
 RECT 0 0 75 162 ;
 LAYER MV3 ;
 RECT 0 0 75 162 ;
 LAYER MV4 ;
 RECT 0 0 75 162 ;
 LAYER M1 ;
 RECT 0 0 75 162 ;
 LAYER M2 ;
 RECT 65.1 160.22 75 162 ;
 RECT 0 160.22 9.9 162 ;
 RECT 0 0 75 160.22 ;
 LAYER M3 ;
 RECT 0 0 75 9.31 ;
 RECT 0 29.25 75 31.35 ;
 RECT 1.88 9.31 73.12 29.25 ;
 RECT 1.52 160.22 9.9 160.61 ;
 RECT 0 160.61 9.9 162 ;
 RECT 0 51.29 75 53.75 ;
 RECT 1.88 31.35 73.12 51.29 ;
 RECT 0 58.23 75 59.42 ;
 RECT 1.52 53.75 73.48 58.23 ;
 RECT 1.88 66.36 73.12 92.84 ;
 RECT 1.88 94.94 73.12 121.45 ;
 RECT 0 63.9 75 66.36 ;
 RECT 1.52 59.42 73.48 63.9 ;
 RECT 0 92.84 75 94.94 ;
 RECT 0 121.45 75 128.86 ;
 RECT 0 130.24 75 137.06 ;
 RECT 1.52 128.86 73.48 130.24 ;
 RECT 0 151.07 75 157.73 ;
 RECT 1.2 137.06 73.8 151.07 ;
 RECT 1.52 157.73 73.48 160.22 ;
 RECT 65.1 160.22 73.48 160.61 ;
 RECT 65.1 160.61 75 162 ;
 LAYER M4 ;
 RECT 0 0 75 123.91 ;
 RECT 0 129.39 75 130.58 ;
 RECT 2.24 123.91 72.76 129.39 ;
 RECT 2.6 135.39 72.4 147.06 ;
 RECT 0 134.56 75 135.39 ;
 RECT 2.24 130.58 72.76 134.56 ;
 RECT 0 147.06 75 147.89 ;
 RECT 0 152.37 75 153.56 ;
 RECT 2.24 147.89 72.76 152.37 ;
 RECT 0 156.54 75 157.73 ;
 RECT 2.24 153.56 72.76 156.54 ;
 RECT 0 160.71 75 162 ;
 RECT 2.24 157.73 72.76 160.71 ;
 LAYER M5 ;
 RECT 0 9.9 3.9 111.1 ;
 RECT 71.1 9.9 75 111.1 ;
 RECT 0 0 75 9.9 ;
 RECT 0 111.1 75 123.69 ;
 RECT 0 129.61 75 130.36 ;
 RECT 2.045 123.69 72.955 129.61 ;
 RECT 2.185 135.39 72.815 147.06 ;
 RECT 0 134.78 75 135.39 ;
 RECT 2.045 130.36 72.955 134.78 ;
 RECT 0 147.06 75 147.67 ;
 RECT 0 152.59 75 153.34 ;
 RECT 2.045 147.67 72.955 152.59 ;
 RECT 0 156.76 75 157.51 ;
 RECT 2.045 153.34 72.955 156.76 ;
 RECT 0 160.93 75 162 ;
 RECT 2.045 157.51 72.955 160.93 ;
 END
END RCMCU_PLVDDHA

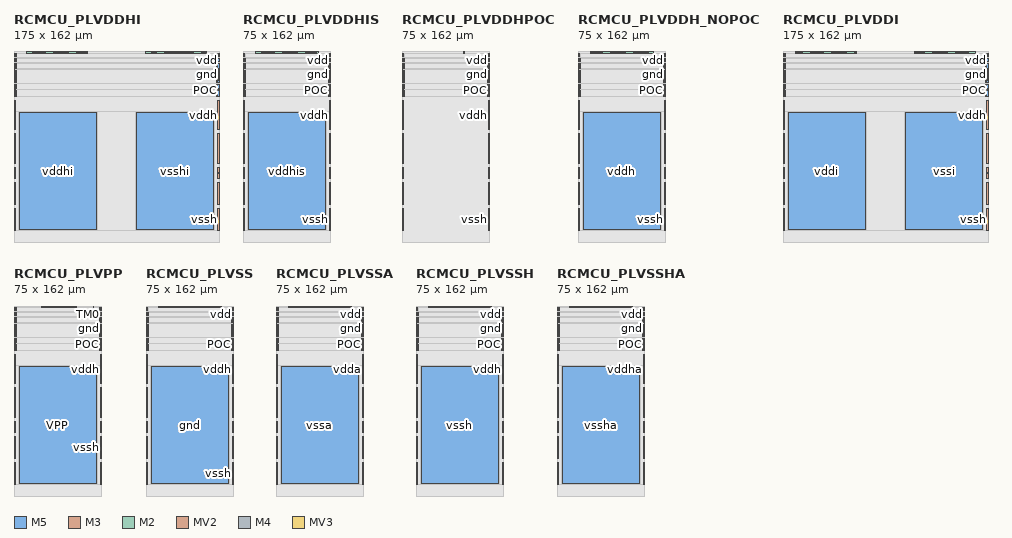
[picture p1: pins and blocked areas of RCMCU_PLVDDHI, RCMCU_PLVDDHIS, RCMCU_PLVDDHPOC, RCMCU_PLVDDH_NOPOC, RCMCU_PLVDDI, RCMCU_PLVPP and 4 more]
MACRO RCMCU_PLVDDHI
 CLASS PAD ;
 FOREIGN RCMCU_PLVDDHI ;
 ORIGIN 0 0 ;
 SIZE 175 BY 162 ;
 SYMMETRY X Y R90 ;
 PIN POC
 USE POWER ;
 DIRECTION INOUT ;
 PORT
 LAYER M3 ;
 RECT 173.72 129.1 175 130 ;
 END
 PORT
 LAYER M3 ;
 RECT 0 129.1 1.28 130 ;
 END
 END POC
 PIN gnd
 USE GROUND ;
 DIRECTION INOUT ;
 PORT
 LAYER M5 ;
 RECT 173.415 135.99 175 146.46 ;
 END
 PORT
 LAYER M5 ;
 RECT 0 135.99 1.585 146.46 ;
 END
 PORT
 LAYER M5 ;
 RECT 0 157.97 1.585 160.47 ;
 END
 PORT
 LAYER M5 ;
 RECT 173.415 157.97 175 160.47 ;
 END
 PORT
 LAYER M4 ;
 RECT 173 135.99 175 146.46 ;
 END
 PORT
 LAYER M4 ;
 RECT 0 135.99 2 146.46 ;
 END
 PORT
 LAYER M4 ;
 RECT 0 157.97 2 160.47 ;
 END
 PORT
 LAYER M4 ;
 RECT 173 157.97 175 160.47 ;
 END
 PORT
 LAYER M3 ;
 RECT 173.72 59.66 175 63.66 ;
 END
 PORT
 LAYER M3 ;
 RECT 0 59.66 1.28 63.66 ;
 END
 PORT
 LAYER M3 ;
 RECT 0 157.97 1.28 160.37 ;
 END
 PORT
 LAYER M3 ;
 RECT 173.72 157.97 175 160.37 ;
 END
 PORT
 LAYER MV3 ;
 RECT 174.175 158.525 174.365 158.715 ;
 RECT 174.175 159.325 174.365 159.515 ;
 RECT 0.635 158.525 0.825 158.715 ;
 RECT 0.635 159.325 0.825 159.515 ;
 END
 END gnd
 PIN vdd
 USE POWER ;
 DIRECTION INOUT ;
 PORT
 LAYER M5 ;
 RECT 173.415 153.8 175 156.3 ;
 END
 PORT
 LAYER M5 ;
 RECT 0 153.8 1.585 156.3 ;
 END
 PORT
 LAYER M4 ;
 RECT 173 153.8 175 156.3 ;
 END
 PORT
 LAYER M4 ;
 RECT 0 153.8 2 156.3 ;
 END
 END vdd
 PIN vddh
 USE POWER ;
 DIRECTION INOUT ;
 PORT
 LAYER M5 ;
 RECT 173.415 130.82 175 134.32 ;
 END
 PORT
 LAYER M5 ;
 RECT 0 130.82 1.585 134.32 ;
 END
 PORT
 LAYER M4 ;
 RECT 173 130.82 175 134.32 ;
 END
 PORT
 LAYER M4 ;
 RECT 0 130.82 2 134.32 ;
 END
 PORT
 LAYER M3 ;
 RECT 173.72 53.99 175 57.99 ;
 END
 PORT
 LAYER M3 ;
 RECT 0 53.99 1.28 57.99 ;
 END
 PORT
 LAYER M3 ;
 RECT 173.72 66.96 175 92.24 ;
 END
 PORT
 LAYER M3 ;
 RECT 0 66.96 1.28 92.24 ;
 END
 PORT
 LAYER M3 ;
 RECT 0 95.54 1.28 120.85 ;
 END
 PORT
 LAYER M3 ;
 RECT 173.72 95.54 175 120.85 ;
 END
 PORT
 LAYER M3 ;
 RECT 0 137.66 0.6 150.47 ;
 END
 PORT
 LAYER M3 ;
 RECT 174.4 137.66 175 150.47 ;
 END
 END vddh
 PIN vddhi
 USE POWER ;
 DIRECTION INOUT ;
 PORT
 LAYER M5 ;
 RECT 4.5 10.5 70.5 110.5 ;
 END
 PORT
 LAYER M3 ;
 RECT 10.5 160.82 62.55 162 ;
 END
 PORT
 LAYER M2 ;
 RECT 10.5 160.82 62.55 162 ;
 END
 PORT
 LAYER MV2 ;
 RECT 40.26 161.515 40.45 161.705 ;
 RECT 40.82 161.515 41.01 161.705 ;
 RECT 43.62 160.955 43.81 161.145 ;
 RECT 44.18 160.955 44.37 161.145 ;
 RECT 44.74 160.955 44.93 161.145 ;
 RECT 45.3 160.955 45.49 161.145 ;
 RECT 45.86 160.955 46.05 161.145 ;
 RECT 43.62 161.515 43.81 161.705 ;
 RECT 44.18 161.515 44.37 161.705 ;
 RECT 44.74 161.515 44.93 161.705 ;
 RECT 45.3 161.515 45.49 161.705 ;
 RECT 45.86 161.515 46.05 161.705 ;
 RECT 49.22 160.955 49.41 161.145 ;
 RECT 46.42 160.955 46.61 161.145 ;
 RECT 46.98 160.955 47.17 161.145 ;
 RECT 48.66 160.955 48.85 161.145 ;
 RECT 48.1 160.955 48.29 161.145 ;
 RECT 47.54 160.955 47.73 161.145 ;
 RECT 49.22 161.515 49.41 161.705 ;
 RECT 46.42 161.515 46.61 161.705 ;
 RECT 46.98 161.515 47.17 161.705 ;
 RECT 47.54 161.515 47.73 161.705 ;
 RECT 48.1 161.515 48.29 161.705 ;
 RECT 48.66 161.515 48.85 161.705 ;
 RECT 43.06 160.955 43.25 161.145 ;
 RECT 43.06 161.515 43.25 161.705 ;
 RECT 52.02 160.955 52.21 161.145 ;
 RECT 49.78 160.955 49.97 161.145 ;
 RECT 50.34 160.955 50.53 161.145 ;
 RECT 50.9 160.955 51.09 161.145 ;
 RECT 51.46 160.955 51.65 161.145 ;
 RECT 52.02 161.515 52.21 161.705 ;
 RECT 51.46 161.515 51.65 161.705 ;
 RECT 50.9 161.515 51.09 161.705 ;
 RECT 50.34 161.515 50.53 161.705 ;
 RECT 49.78 161.515 49.97 161.705 ;
 RECT 54.82 160.955 55.01 161.145 ;
 RECT 55.38 160.955 55.57 161.145 ;
 RECT 53.14 160.955 53.33 161.145 ;
 RECT 54.26 160.955 54.45 161.145 ;
 RECT 53.7 160.955 53.89 161.145 ;
 RECT 54.82 161.515 55.01 161.705 ;
 RECT 55.38 161.515 55.57 161.705 ;
 RECT 54.26 161.515 54.45 161.705 ;
 RECT 53.14 161.515 53.33 161.705 ;
 RECT 53.7 161.515 53.89 161.705 ;
 RECT 52.58 160.955 52.77 161.145 ;
 RECT 52.58 161.515 52.77 161.705 ;
 RECT 57.62 160.955 57.81 161.145 ;
 RECT 58.18 160.955 58.37 161.145 ;
 RECT 58.74 160.955 58.93 161.145 ;
 RECT 55.94 160.955 56.13 161.145 ;
 RECT 56.5 160.955 56.69 161.145 ;
 RECT 57.06 160.955 57.25 161.145 ;
 RECT 57.62 161.515 57.81 161.705 ;
 RECT 58.18 161.515 58.37 161.705 ;
 RECT 58.74 161.515 58.93 161.705 ;
 RECT 55.94 161.515 56.13 161.705 ;
 RECT 56.5 161.515 56.69 161.705 ;
 RECT 57.06 161.515 57.25 161.705 ;
 RECT 60.42 160.955 60.61 161.145 ;
 RECT 60.98 160.955 61.17 161.145 ;
 RECT 61.54 160.955 61.73 161.145 ;
 RECT 62.1 160.955 62.29 161.145 ;
 RECT 59.86 160.955 60.05 161.145 ;
 RECT 59.3 160.955 59.49 161.145 ;
 RECT 62.1 161.515 62.29 161.705 ;
 RECT 60.98 161.515 61.17 161.705 ;
 RECT 60.42 161.515 60.61 161.705 ;
 RECT 61.54 161.515 61.73 161.705 ;
 RECT 59.3 161.515 59.49 161.705 ;
 RECT 59.86 161.515 60.05 161.705 ;
 RECT 13.94 160.955 14.13 161.145 ;
 RECT 11.14 160.955 11.33 161.145 ;
 RECT 11.7 160.955 11.89 161.145 ;
 RECT 12.26 160.955 12.45 161.145 ;
 RECT 12.82 160.955 13.01 161.145 ;
 RECT 13.38 160.955 13.57 161.145 ;
 RECT 13.94 161.515 14.13 161.705 ;
 RECT 13.38 161.515 13.57 161.705 ;
 RECT 12.82 161.515 13.01 161.705 ;
 RECT 12.26 161.515 12.45 161.705 ;
 RECT 11.7 161.515 11.89 161.705 ;
 RECT 11.14 161.515 11.33 161.705 ;
 RECT 16.74 160.955 16.93 161.145 ;
 RECT 17.3 160.955 17.49 161.145 ;
 RECT 14.5 160.955 14.69 161.145 ;
 RECT 16.18 160.955 16.37 161.145 ;
 RECT 15.62 160.955 15.81 161.145 ;
 RECT 15.06 160.955 15.25 161.145 ;
 RECT 17.3 161.515 17.49 161.705 ;
 RECT 16.74 161.515 16.93 161.705 ;
 RECT 14.5 161.515 14.69 161.705 ;
 RECT 16.18 161.515 16.37 161.705 ;
 RECT 15.62 161.515 15.81 161.705 ;
 RECT 15.06 161.515 15.25 161.705 ;
 RECT 18.98 160.955 19.17 161.145 ;
 RECT 19.54 160.955 19.73 161.145 ;
 RECT 20.1 160.955 20.29 161.145 ;
 RECT 17.86 160.955 18.05 161.145 ;
 RECT 18.42 160.955 18.61 161.145 ;
 RECT 20.1 161.515 20.29 161.705 ;
 RECT 19.54 161.515 19.73 161.705 ;
 RECT 18.98 161.515 19.17 161.705 ;
 RECT 18.42 161.515 18.61 161.705 ;
 RECT 17.86 161.515 18.05 161.705 ;
 RECT 21.78 160.955 21.97 161.145 ;
 RECT 22.34 160.955 22.53 161.145 ;
 RECT 22.9 160.955 23.09 161.145 ;
 RECT 23.46 160.955 23.65 161.145 ;
 RECT 21.22 160.955 21.41 161.145 ;
 RECT 23.46 161.515 23.65 161.705 ;
 RECT 22.9 161.515 23.09 161.705 ;
 RECT 22.34 161.515 22.53 161.705 ;
 RECT 21.78 161.515 21.97 161.705 ;
 RECT 21.22 161.515 21.41 161.705 ;
 RECT 20.66 160.955 20.85 161.145 ;
 RECT 20.66 161.515 20.85 161.705 ;
 RECT 24.58 160.955 24.77 161.145 ;
 RECT 25.14 160.955 25.33 161.145 ;
 RECT 26.82 160.955 27.01 161.145 ;
 RECT 26.26 160.955 26.45 161.145 ;
 RECT 25.7 160.955 25.89 161.145 ;
 RECT 24.02 160.955 24.21 161.145 ;
 RECT 25.7 161.515 25.89 161.705 ;
 RECT 26.26 161.515 26.45 161.705 ;
 RECT 26.82 161.515 27.01 161.705 ;
 RECT 25.14 161.515 25.33 161.705 ;
 RECT 24.58 161.515 24.77 161.705 ;
 RECT 24.02 161.515 24.21 161.705 ;
 RECT 27.38 160.955 27.57 161.145 ;
 RECT 27.94 160.955 28.13 161.145 ;
 RECT 28.5 160.955 28.69 161.145 ;
 RECT 29.06 160.955 29.25 161.145 ;
 RECT 29.62 160.955 29.81 161.145 ;
 RECT 27.38 161.515 27.57 161.705 ;
 RECT 27.94 161.515 28.13 161.705 ;
 RECT 28.5 161.515 28.69 161.705 ;
 RECT 29.06 161.515 29.25 161.705 ;
 RECT 29.62 161.515 29.81 161.705 ;
 RECT 32.98 160.955 33.17 161.145 ;
 RECT 30.74 160.955 30.93 161.145 ;
 RECT 32.42 160.955 32.61 161.145 ;
 RECT 31.86 160.955 32.05 161.145 ;
 RECT 31.3 160.955 31.49 161.145 ;
 RECT 32.98 161.515 33.17 161.705 ;
 RECT 30.74 161.515 30.93 161.705 ;
 RECT 31.3 161.515 31.49 161.705 ;
 RECT 31.86 161.515 32.05 161.705 ;
 RECT 32.42 161.515 32.61 161.705 ;
 RECT 35.78 160.955 35.97 161.145 ;
 RECT 36.34 160.955 36.53 161.145 ;
 RECT 33.54 160.955 33.73 161.145 ;
 RECT 34.1 160.955 34.29 161.145 ;
 RECT 34.66 160.955 34.85 161.145 ;
 RECT 35.22 160.955 35.41 161.145 ;
 RECT 35.78 161.515 35.97 161.705 ;
 RECT 36.34 161.515 36.53 161.705 ;
 RECT 35.22 161.515 35.41 161.705 ;
 RECT 34.66 161.515 34.85 161.705 ;
 RECT 34.1 161.515 34.29 161.705 ;
 RECT 33.54 161.515 33.73 161.705 ;
 RECT 30.18 160.955 30.37 161.145 ;
 RECT 30.18 161.515 30.37 161.705 ;
 RECT 38.58 160.955 38.77 161.145 ;
 RECT 39.14 160.955 39.33 161.145 ;
 RECT 39.7 160.955 39.89 161.145 ;
 RECT 38.02 160.955 38.21 161.145 ;
 RECT 37.46 160.955 37.65 161.145 ;
 RECT 36.9 160.955 37.09 161.145 ;
 RECT 38.58 161.515 38.77 161.705 ;
 RECT 39.14 161.515 39.33 161.705 ;
 RECT 39.7 161.515 39.89 161.705 ;
 RECT 36.9 161.515 37.09 161.705 ;
 RECT 37.46 161.515 37.65 161.705 ;
 RECT 38.02 161.515 38.21 161.705 ;
 RECT 41.38 160.955 41.57 161.145 ;
 RECT 41.94 160.955 42.13 161.145 ;
 RECT 42.5 160.955 42.69 161.145 ;
 RECT 40.26 160.955 40.45 161.145 ;
 RECT 40.82 160.955 41.01 161.145 ;
 RECT 41.38 161.515 41.57 161.705 ;
 RECT 41.94 161.515 42.13 161.705 ;
 RECT 42.5 161.515 42.69 161.705 ;
 END
 END vddhi
 PIN vssh
 USE GROUND ;
 DIRECTION INOUT ;
 PORT
 LAYER M5 ;
 RECT 173.415 124.15 175 129.15 ;
 END
 PORT
 LAYER M5 ;
 RECT 0 124.15 1.585 129.15 ;
 END
 PORT
 LAYER M5 ;
 RECT 0 148.13 1.585 152.13 ;
 END
 PORT
 LAYER M5 ;
 RECT 173.415 148.13 175 152.13 ;
 END
 PORT
 LAYER M4 ;
 RECT 173 124.15 175 129.15 ;
 END
 PORT
 LAYER M4 ;
 RECT 0 124.15 2 129.15 ;
 END
 PORT
 LAYER M4 ;
 RECT 0 148.13 2 152.13 ;
 END
 PORT
 LAYER M4 ;
 RECT 173 148.13 175 152.13 ;
 END
 PORT
 LAYER M3 ;
 RECT 173.72 9.91 175 28.65 ;
 END
 PORT
 LAYER M3 ;
 RECT 0 9.91 1.28 28.65 ;
 END
 PORT
 LAYER M3 ;
 RECT 0 31.95 1.28 50.69 ;
 END
 PORT
 LAYER M3 ;
 RECT 173.72 31.95 175 50.69 ;
 END
 END vssh
 PIN vsshi
 USE GROUND ;
 DIRECTION INOUT ;
 PORT
 LAYER M5 ;
 RECT 104.5 10.5 170.5 110.5 ;
 END
 PORT
 LAYER M3 ;
 RECT 112.45 160.82 164.5 162 ;
 END
 PORT
 LAYER M2 ;
 RECT 112.45 160.82 164.5 162 ;
 END
 PORT
 LAYER MV2 ;
 RECT 127.055 161.515 127.245 161.705 ;
 RECT 131.535 160.955 131.725 161.145 ;
 RECT 129.295 160.955 129.485 161.145 ;
 RECT 129.855 160.955 130.045 161.145 ;
 RECT 130.415 160.955 130.605 161.145 ;
 RECT 130.975 160.955 131.165 161.145 ;
 RECT 131.535 161.515 131.725 161.705 ;
 RECT 130.975 161.515 131.165 161.705 ;
 RECT 130.415 161.515 130.605 161.705 ;
 RECT 129.855 161.515 130.045 161.705 ;
 RECT 129.295 161.515 129.485 161.705 ;
 RECT 128.735 160.955 128.925 161.145 ;
 RECT 128.735 161.515 128.925 161.705 ;
 RECT 134.335 160.955 134.525 161.145 ;
 RECT 134.895 160.955 135.085 161.145 ;
 RECT 132.095 160.955 132.285 161.145 ;
 RECT 132.655 160.955 132.845 161.145 ;
 RECT 133.215 160.955 133.405 161.145 ;
 RECT 133.775 160.955 133.965 161.145 ;
 RECT 134.335 161.515 134.525 161.705 ;
 RECT 134.895 161.515 135.085 161.705 ;
 RECT 132.095 161.515 132.285 161.705 ;
 RECT 132.655 161.515 132.845 161.705 ;
 RECT 133.215 161.515 133.405 161.705 ;
 RECT 133.775 161.515 133.965 161.705 ;
 RECT 136.575 160.955 136.765 161.145 ;
 RECT 137.225 160.955 137.415 161.145 ;
 RECT 137.785 160.955 137.975 161.145 ;
 RECT 136.015 160.955 136.205 161.145 ;
 RECT 135.455 160.955 135.645 161.145 ;
 RECT 137.785 161.515 137.975 161.705 ;
 RECT 137.225 161.515 137.415 161.705 ;
 RECT 136.575 161.515 136.765 161.705 ;
 RECT 136.015 161.515 136.205 161.705 ;
 RECT 135.455 161.515 135.645 161.705 ;
 RECT 139.465 160.955 139.655 161.145 ;
 RECT 140.025 160.955 140.215 161.145 ;
 RECT 141.235 160.955 141.425 161.145 ;
 RECT 140.675 160.955 140.865 161.145 ;
 RECT 138.905 160.955 139.095 161.145 ;
 RECT 141.235 161.515 141.425 161.705 ;
 RECT 140.675 161.515 140.865 161.705 ;
 RECT 140.025 161.515 140.215 161.705 ;
 RECT 139.465 161.515 139.655 161.705 ;
 RECT 138.905 161.515 139.095 161.705 ;
 RECT 142.355 160.955 142.545 161.145 ;
 RECT 142.915 160.955 143.105 161.145 ;
 RECT 143.475 160.955 143.665 161.145 ;
 RECT 144.035 160.955 144.225 161.145 ;
 RECT 141.795 160.955 141.985 161.145 ;
 RECT 143.475 161.515 143.665 161.705 ;
 RECT 142.355 161.515 142.545 161.705 ;
 RECT 142.915 161.515 143.105 161.705 ;
 RECT 144.035 161.515 144.225 161.705 ;
 RECT 141.795 161.515 141.985 161.705 ;
 RECT 145.155 160.955 145.345 161.145 ;
 RECT 145.715 160.955 145.905 161.145 ;
 RECT 147.395 160.955 147.585 161.145 ;
 RECT 146.835 160.955 147.025 161.145 ;
 RECT 146.275 160.955 146.465 161.145 ;
 RECT 147.395 161.515 147.585 161.705 ;
 RECT 146.835 161.515 147.025 161.705 ;
 RECT 146.275 161.515 146.465 161.705 ;
 RECT 145.715 161.515 145.905 161.705 ;
 RECT 145.155 161.515 145.345 161.705 ;
 RECT 150.755 160.955 150.945 161.145 ;
 RECT 147.955 160.955 148.145 161.145 ;
 RECT 148.515 160.955 148.705 161.145 ;
 RECT 149.075 160.955 149.265 161.145 ;
 RECT 149.635 160.955 149.825 161.145 ;
 RECT 150.195 160.955 150.385 161.145 ;
 RECT 150.755 161.515 150.945 161.705 ;
 RECT 149.075 161.515 149.265 161.705 ;
 RECT 148.515 161.515 148.705 161.705 ;
 RECT 147.955 161.515 148.145 161.705 ;
 RECT 149.635 161.515 149.825 161.705 ;
 RECT 150.195 161.515 150.385 161.705 ;
 RECT 144.595 160.955 144.785 161.145 ;
 RECT 144.595 161.515 144.785 161.705 ;
 RECT 152.995 160.955 153.185 161.145 ;
 RECT 153.555 160.955 153.745 161.145 ;
 RECT 151.315 160.955 151.505 161.145 ;
 RECT 152.435 160.955 152.625 161.145 ;
 RECT 151.875 160.955 152.065 161.145 ;
 RECT 152.995 161.515 153.185 161.705 ;
 RECT 153.555 161.515 153.745 161.705 ;
 RECT 151.315 161.515 151.505 161.705 ;
 RECT 151.875 161.515 152.065 161.705 ;
 RECT 152.435 161.515 152.625 161.705 ;
 RECT 155.795 160.955 155.985 161.145 ;
 RECT 156.355 160.955 156.545 161.145 ;
 RECT 156.915 160.955 157.105 161.145 ;
 RECT 154.675 160.955 154.865 161.145 ;
 RECT 155.235 160.955 155.425 161.145 ;
 RECT 155.795 161.515 155.985 161.705 ;
 RECT 156.355 161.515 156.545 161.705 ;
 RECT 156.915 161.515 157.105 161.705 ;
 RECT 154.675 161.515 154.865 161.705 ;
 RECT 155.235 161.515 155.425 161.705 ;
 RECT 154.115 160.955 154.305 161.145 ;
 RECT 154.115 161.515 154.305 161.705 ;
 RECT 158.595 160.955 158.785 161.145 ;
 RECT 159.155 160.955 159.345 161.145 ;
 RECT 159.715 160.955 159.905 161.145 ;
 RECT 160.275 160.955 160.465 161.145 ;
 RECT 158.035 160.955 158.225 161.145 ;
 RECT 157.475 160.955 157.665 161.145 ;
 RECT 160.275 161.515 160.465 161.705 ;
 RECT 158.595 161.515 158.785 161.705 ;
 RECT 159.155 161.515 159.345 161.705 ;
 RECT 159.715 161.515 159.905 161.705 ;
 RECT 157.475 161.515 157.665 161.705 ;
 RECT 158.035 161.515 158.225 161.705 ;
 RECT 161.395 160.955 161.585 161.145 ;
 RECT 161.955 160.955 162.145 161.145 ;
 RECT 163.635 160.955 163.825 161.145 ;
 RECT 163.075 160.955 163.265 161.145 ;
 RECT 162.515 160.955 162.705 161.145 ;
 RECT 160.835 160.955 161.025 161.145 ;
 RECT 161.395 161.515 161.585 161.705 ;
 RECT 161.955 161.515 162.145 161.705 ;
 RECT 162.515 161.515 162.705 161.705 ;
 RECT 163.075 161.515 163.265 161.705 ;
 RECT 163.635 161.515 163.825 161.705 ;
 RECT 160.835 161.515 161.025 161.705 ;
 RECT 138.345 160.955 138.535 161.145 ;
 RECT 138.345 161.515 138.535 161.705 ;
 RECT 115.145 160.955 115.335 161.145 ;
 RECT 115.705 160.955 115.895 161.145 ;
 RECT 114.585 160.955 114.775 161.145 ;
 RECT 114.025 160.955 114.215 161.145 ;
 RECT 113.465 160.955 113.655 161.145 ;
 RECT 112.905 160.955 113.095 161.145 ;
 RECT 115.145 161.515 115.335 161.705 ;
 RECT 115.705 161.515 115.895 161.705 ;
 RECT 114.585 161.515 114.775 161.705 ;
 RECT 114.025 161.515 114.215 161.705 ;
 RECT 113.465 161.515 113.655 161.705 ;
 RECT 112.905 161.515 113.095 161.705 ;
 RECT 117.535 160.955 117.725 161.145 ;
 RECT 118.095 160.955 118.285 161.145 ;
 RECT 118.655 160.955 118.845 161.145 ;
 RECT 116.415 160.955 116.605 161.145 ;
 RECT 116.975 160.955 117.165 161.145 ;
 RECT 118.655 161.515 118.845 161.705 ;
 RECT 118.095 161.515 118.285 161.705 ;
 RECT 117.535 161.515 117.725 161.705 ;
 RECT 116.415 161.515 116.605 161.705 ;
 RECT 116.975 161.515 117.165 161.705 ;
 RECT 122.015 160.955 122.205 161.145 ;
 RECT 121.455 160.955 121.645 161.145 ;
 RECT 120.895 160.955 121.085 161.145 ;
 RECT 120.335 160.955 120.525 161.145 ;
 RECT 119.775 160.955 119.965 161.145 ;
 RECT 122.015 161.515 122.205 161.705 ;
 RECT 120.335 161.515 120.525 161.705 ;
 RECT 120.895 161.515 121.085 161.705 ;
 RECT 121.455 161.515 121.645 161.705 ;
 RECT 119.775 161.515 119.965 161.705 ;
 RECT 123.135 160.955 123.325 161.145 ;
 RECT 124.255 160.955 124.445 161.145 ;
 RECT 124.815 160.955 125.005 161.145 ;
 RECT 125.375 160.955 125.565 161.145 ;
 RECT 123.695 160.955 123.885 161.145 ;
 RECT 122.575 160.955 122.765 161.145 ;
 RECT 125.375 161.515 125.565 161.705 ;
 RECT 124.815 161.515 125.005 161.705 ;
 RECT 124.255 161.515 124.445 161.705 ;
 RECT 123.695 161.515 123.885 161.705 ;
 RECT 123.135 161.515 123.325 161.705 ;
 RECT 122.575 161.515 122.765 161.705 ;
 RECT 119.215 160.955 119.405 161.145 ;
 RECT 119.215 161.515 119.405 161.705 ;
 RECT 125.935 160.955 126.125 161.145 ;
 RECT 126.495 160.955 126.685 161.145 ;
 RECT 127.055 160.955 127.245 161.145 ;
 RECT 127.615 160.955 127.805 161.145 ;
 RECT 128.175 160.955 128.365 161.145 ;
 RECT 128.175 161.515 128.365 161.705 ;
 RECT 127.615 161.515 127.805 161.705 ;
 RECT 125.935 161.515 126.125 161.705 ;
 RECT 126.495 161.515 126.685 161.705 ;
 END
 END vsshi
 OBS
 LAYER GATE ;
 RECT 0 0 175 162 ;
 LAYER MV1 ;
 RECT 0 0 175 162 ;
 LAYER MV2 ;
 RECT 0 0 175 162 ;
 LAYER MV3 ;
 RECT 0 0 175 162 ;
 LAYER MV4 ;
 RECT 0 0 175 162 ;
 LAYER M1 ;
 RECT 0 0 175 162 ;
 LAYER M2 ;
 RECT 0 0 175 160.22 ;
 RECT 63.15 160.22 111.85 162 ;
 RECT 0 160.22 9.9 162 ;
 RECT 165.1 160.22 175 162 ;
 LAYER M3 ;
 RECT 0 0 175 9.31 ;
 RECT 0 29.25 175 31.35 ;
 RECT 1.88 9.31 173.12 29.25 ;
 RECT 1.52 160.22 9.9 160.61 ;
 RECT 0 160.61 9.9 162 ;
 RECT 63.15 160.22 111.85 162 ;
 RECT 0 51.29 175 53.75 ;
 RECT 1.88 31.35 173.12 51.29 ;
 RECT 0 58.23 175 59.42 ;
 RECT 1.52 53.75 173.48 58.23 ;
 RECT 1.88 66.36 173.12 92.84 ;
 RECT 1.88 94.94 173.12 121.45 ;
 RECT 0 63.9 175 66.36 ;
 RECT 1.52 59.42 173.48 63.9 ;
 RECT 0 92.84 175 94.94 ;
 RECT 0 121.45 175 128.86 ;
 RECT 0 130.24 175 137.06 ;
 RECT 1.52 128.86 173.48 130.24 ;
 RECT 0 151.07 175 157.73 ;
 RECT 1.2 137.06 173.8 151.07 ;
 RECT 1.52 157.73 173.48 160.22 ;
 RECT 165.1 160.22 173.48 160.61 ;
 RECT 165.1 160.61 175 162 ;
 LAYER M4 ;
 RECT 0 0 175 123.91 ;
 RECT 0 129.39 175 130.58 ;
 RECT 2.24 123.91 172.76 129.39 ;
 RECT 2.6 135.39 172.4 147.06 ;
 RECT 0 134.56 175 135.39 ;
 RECT 2.24 130.58 172.76 134.56 ;
 RECT 0 147.06 175 147.89 ;
 RECT 0 152.37 175 153.56 ;
 RECT 2.24 147.89 172.76 152.37 ;
 RECT 0 156.54 175 157.73 ;
 RECT 2.24 153.56 172.76 156.54 ;
 RECT 0 160.71 175 162 ;
 RECT 2.24 157.73 172.76 160.71 ;
 LAYER M5 ;
 RECT 2.045 123.69 172.955 129.61 ;
 RECT 2.185 135.39 172.815 147.06 ;
 RECT 0 134.78 175 135.39 ;
 RECT 2.045 130.36 172.955 134.78 ;
 RECT 0 147.06 175 147.67 ;
 RECT 0 152.59 175 153.34 ;
 RECT 2.045 147.67 172.955 152.59 ;
 RECT 0 156.76 175 157.51 ;
 RECT 2.045 153.34 172.955 156.76 ;
 RECT 0 160.93 175 162 ;
 RECT 2.045 157.51 172.955 160.93 ;
 RECT 0 0 175 9.9 ;
 RECT 0 111.1 175 123.69 ;
 RECT 0 9.9 3.9 111.1 ;
 RECT 71.1 9.9 103.9 111.1 ;
 RECT 171.1 9.9 175 111.1 ;
 RECT 0 129.61 175 130.36 ;
 END
END RCMCU_PLVDDHI

MACRO RCMCU_PLVDDHIS
 CLASS PAD ;
 FOREIGN RCMCU_PLVDDHIS ;
 ORIGIN 0 0 ;
 SIZE 75 BY 162 ;
 SYMMETRY X Y R90 ;
 PIN POC
 USE POWER ;
 DIRECTION INOUT ;
 PORT
 LAYER M3 ;
 RECT 73.72 129.1 75 130 ;
 END
 PORT
 LAYER M3 ;
 RECT 0 129.1 1.28 130 ;
 END
 END POC
 PIN gnd
 USE GROUND ;
 DIRECTION INOUT ;
 PORT
 LAYER M5 ;
 RECT 73.415 135.99 75 146.46 ;
 END
 PORT
 LAYER M5 ;
 RECT 0 135.99 1.585 146.46 ;
 END
 PORT
 LAYER M5 ;
 RECT 0 157.97 1.585 160.47 ;
 END
 PORT
 LAYER M5 ;
 RECT 73.415 157.97 75 160.47 ;
 END
 PORT
 LAYER M4 ;
 RECT 73 135.99 75 146.46 ;
 END
 PORT
 LAYER M4 ;
 RECT 0 135.99 2 146.46 ;
 END
 PORT
 LAYER M4 ;
 RECT 0 157.97 1.585 160.47 ;
 END
 PORT
 LAYER M4 ;
 RECT 73.415 157.97 75 160.47 ;
 END
 PORT
 LAYER M3 ;
 RECT 73.72 59.66 75 63.66 ;
 END
 PORT
 LAYER M3 ;
 RECT 0 59.66 1.28 63.66 ;
 END
 PORT
 LAYER M3 ;
 RECT 0 157.97 1.585 160.37 ;
 END
 PORT
 LAYER M3 ;
 RECT 73.415 157.97 75 160.37 ;
 END
 PORT
 LAYER MV3 ;
 RECT 73.6 158.44 73.79 158.63 ;
 RECT 74.21 158.44 74.4 158.63 ;
 RECT 73.6 159.05 73.79 159.24 ;
 RECT 74.21 159.05 74.4 159.24 ;
 RECT 73.6 159.66 73.79 159.85 ;
 RECT 74.21 159.66 74.4 159.85 ;
 RECT 0.6 158.44 0.79 158.63 ;
 RECT 1.21 158.44 1.4 158.63 ;
 RECT 0.6 159.05 0.79 159.24 ;
 RECT 1.21 159.05 1.4 159.24 ;
 RECT 0.6 159.66 0.79 159.85 ;
 RECT 1.21 159.66 1.4 159.85 ;
 END
 END gnd
 PIN vdd
 USE POWER ;
 DIRECTION INOUT ;
 PORT
 LAYER M5 ;
 RECT 73.415 153.8 75 156.3 ;
 END
 PORT
 LAYER M5 ;
 RECT 0 153.8 1.585 156.3 ;
 END
 PORT
 LAYER M4 ;
 RECT 73 153.8 75 156.3 ;
 END
 PORT
 LAYER M4 ;
 RECT 0 153.8 2 156.3 ;
 END
 END vdd
 PIN vddh
 USE POWER ;
 DIRECTION INOUT ;
 PORT
 LAYER M5 ;
 RECT 73.415 130.82 75 134.32 ;
 END
 PORT
 LAYER M5 ;
 RECT 0 130.82 1.585 134.32 ;
 END
 PORT
 LAYER M4 ;
 RECT 73 130.82 75 134.32 ;
 END
 PORT
 LAYER M4 ;
 RECT 0 130.82 2 134.32 ;
 END
 PORT
 LAYER M3 ;
 RECT 73.72 53.99 75 57.99 ;
 END
 PORT
 LAYER M3 ;
 RECT 0 53.99 1.28 57.99 ;
 END
 PORT
 LAYER M3 ;
 RECT 73.72 66.96 75 92.24 ;
 END
 PORT
 LAYER M3 ;
 RECT 0 66.96 1.28 92.24 ;
 END
 PORT
 LAYER M3 ;
 RECT 0 95.54 1.28 120.85 ;
 END
 PORT
 LAYER M3 ;
 RECT 73.72 95.54 75 120.85 ;
 END
 PORT
 LAYER M3 ;
 RECT 0 137.66 0.6 150.47 ;
 END
 PORT
 LAYER M3 ;
 RECT 74.4 137.66 75 150.47 ;
 END
 END vddh
 PIN vddhis
 USE POWER ;
 DIRECTION INOUT ;
 PORT
 LAYER M5 ;
 RECT 4.5 10.5 70.5 110.5 ;
 END
 PORT
 LAYER M3 ;
 RECT 10.5 160.82 64.5 162 ;
 END
 PORT
 LAYER M2 ;
 RECT 10.5 160.82 64.5 162 ;
 END
 PORT
 LAYER MV2 ;
 RECT 29.065 160.955 29.255 161.145 ;
 RECT 28.505 160.955 28.695 161.145 ;
 RECT 27.945 160.955 28.135 161.145 ;
 RECT 30.745 161.515 30.935 161.705 ;
 RECT 27.945 161.515 28.135 161.705 ;
 RECT 28.505 161.515 28.695 161.705 ;
 RECT 29.065 161.515 29.255 161.705 ;
 RECT 29.625 161.515 29.815 161.705 ;
 RECT 30.185 161.515 30.375 161.705 ;
 RECT 34.105 160.955 34.295 161.145 ;
 RECT 33.545 160.955 33.735 161.145 ;
 RECT 32.985 160.955 33.175 161.145 ;
 RECT 32.425 160.955 32.615 161.145 ;
 RECT 31.865 160.955 32.055 161.145 ;
 RECT 31.305 160.955 31.495 161.145 ;
 RECT 32.985 161.515 33.175 161.705 ;
 RECT 33.545 161.515 33.735 161.705 ;
 RECT 34.105 161.515 34.295 161.705 ;
 RECT 32.425 161.515 32.615 161.705 ;
 RECT 31.865 161.515 32.055 161.705 ;
 RECT 31.305 161.515 31.495 161.705 ;
 RECT 36.905 160.955 37.095 161.145 ;
 RECT 36.345 160.955 36.535 161.145 ;
 RECT 35.785 160.955 35.975 161.145 ;
 RECT 35.225 160.955 35.415 161.145 ;
 RECT 34.665 160.955 34.855 161.145 ;
 RECT 35.225 161.515 35.415 161.705 ;
 RECT 36.905 161.515 37.095 161.705 ;
 RECT 36.345 161.515 36.535 161.705 ;
 RECT 35.785 161.515 35.975 161.705 ;
 RECT 34.665 161.515 34.855 161.705 ;
 RECT 24.585 160.955 24.775 161.145 ;
 RECT 24.585 161.515 24.775 161.705 ;
 RECT 39.705 160.955 39.895 161.145 ;
 RECT 40.265 160.955 40.455 161.145 ;
 RECT 39.145 160.955 39.335 161.145 ;
 RECT 38.585 160.955 38.775 161.145 ;
 RECT 38.025 160.955 38.215 161.145 ;
 RECT 39.705 161.515 39.895 161.705 ;
 RECT 40.265 161.515 40.455 161.705 ;
 RECT 38.025 161.515 38.215 161.705 ;
 RECT 38.585 161.515 38.775 161.705 ;
 RECT 39.145 161.515 39.335 161.705 ;
 RECT 42.505 160.955 42.695 161.145 ;
 RECT 43.065 160.955 43.255 161.145 ;
 RECT 43.625 160.955 43.815 161.145 ;
 RECT 40.825 160.955 41.015 161.145 ;
 RECT 41.385 160.955 41.575 161.145 ;
 RECT 41.945 160.955 42.135 161.145 ;
 RECT 42.505 161.515 42.695 161.705 ;
 RECT 43.065 161.515 43.255 161.705 ;
 RECT 43.625 161.515 43.815 161.705 ;
 RECT 41.945 161.515 42.135 161.705 ;
 RECT 41.385 161.515 41.575 161.705 ;
 RECT 40.825 161.515 41.015 161.705 ;
 RECT 46.985 160.955 47.175 161.145 ;
 RECT 44.745 160.955 44.935 161.145 ;
 RECT 45.305 160.955 45.495 161.145 ;
 RECT 45.865 160.955 46.055 161.145 ;
 RECT 46.425 160.955 46.615 161.145 ;
 RECT 44.185 160.955 44.375 161.145 ;
 RECT 46.985 161.515 47.175 161.705 ;
 RECT 46.425 161.515 46.615 161.705 ;
 RECT 45.865 161.515 46.055 161.705 ;
 RECT 45.305 161.515 45.495 161.705 ;
 RECT 44.745 161.515 44.935 161.705 ;
 RECT 44.185 161.515 44.375 161.705 ;
 RECT 49.785 160.955 49.975 161.145 ;
 RECT 49.225 160.955 49.415 161.145 ;
 RECT 48.665 160.955 48.855 161.145 ;
 RECT 48.105 160.955 48.295 161.145 ;
 RECT 47.545 160.955 47.735 161.145 ;
 RECT 49.225 161.515 49.415 161.705 ;
 RECT 49.785 161.515 49.975 161.705 ;
 RECT 48.665 161.515 48.855 161.705 ;
 RECT 48.105 161.515 48.295 161.705 ;
 RECT 47.545 161.515 47.735 161.705 ;
 RECT 52.585 160.955 52.775 161.145 ;
 RECT 53.145 160.955 53.335 161.145 ;
 RECT 52.025 160.955 52.215 161.145 ;
 RECT 51.465 160.955 51.655 161.145 ;
 RECT 50.905 160.955 51.095 161.145 ;
 RECT 51.465 161.515 51.655 161.705 ;
 RECT 52.025 161.515 52.215 161.705 ;
 RECT 52.585 161.515 52.775 161.705 ;
 RECT 53.145 161.515 53.335 161.705 ;
 RECT 50.905 161.515 51.095 161.705 ;
 RECT 56.505 160.955 56.695 161.145 ;
 RECT 54.265 160.955 54.455 161.145 ;
 RECT 54.825 160.955 55.015 161.145 ;
 RECT 55.385 160.955 55.575 161.145 ;
 RECT 55.945 160.955 56.135 161.145 ;
 RECT 56.505 161.515 56.695 161.705 ;
 RECT 55.945 161.515 56.135 161.705 ;
 RECT 55.385 161.515 55.575 161.705 ;
 RECT 54.825 161.515 55.015 161.705 ;
 RECT 54.265 161.515 54.455 161.705 ;
 RECT 53.705 160.955 53.895 161.145 ;
 RECT 53.705 161.515 53.895 161.705 ;
 RECT 58.745 160.955 58.935 161.145 ;
 RECT 59.305 160.955 59.495 161.145 ;
 RECT 59.865 160.955 60.055 161.145 ;
 RECT 57.065 160.955 57.255 161.145 ;
 RECT 57.625 160.955 57.815 161.145 ;
 RECT 58.185 160.955 58.375 161.145 ;
 RECT 59.865 161.515 60.055 161.705 ;
 RECT 59.305 161.515 59.495 161.705 ;
 RECT 58.745 161.515 58.935 161.705 ;
 RECT 57.065 161.515 57.255 161.705 ;
 RECT 57.625 161.515 57.815 161.705 ;
 RECT 58.185 161.515 58.375 161.705 ;
 RECT 60.985 160.955 61.175 161.145 ;
 RECT 61.545 160.955 61.735 161.145 ;
 RECT 62.105 160.955 62.295 161.145 ;
 RECT 62.665 160.955 62.855 161.145 ;
 RECT 63.225 160.955 63.415 161.145 ;
 RECT 60.425 160.955 60.615 161.145 ;
 RECT 60.985 161.515 61.175 161.705 ;
 RECT 61.545 161.515 61.735 161.705 ;
 RECT 62.105 161.515 62.295 161.705 ;
 RECT 62.665 161.515 62.855 161.705 ;
 RECT 63.225 161.515 63.415 161.705 ;
 RECT 60.425 161.515 60.615 161.705 ;
 RECT 50.345 160.955 50.535 161.145 ;
 RECT 50.345 161.515 50.535 161.705 ;
 RECT 37.465 160.955 37.655 161.145 ;
 RECT 37.465 161.515 37.655 161.705 ;
 RECT 14.505 160.955 14.695 161.145 ;
 RECT 13.945 160.955 14.135 161.145 ;
 RECT 11.705 160.955 11.895 161.145 ;
 RECT 12.265 160.955 12.455 161.145 ;
 RECT 12.825 160.955 13.015 161.145 ;
 RECT 13.385 160.955 13.575 161.145 ;
 RECT 13.945 161.515 14.135 161.705 ;
 RECT 14.505 161.515 14.695 161.705 ;
 RECT 11.705 161.515 11.895 161.705 ;
 RECT 12.265 161.515 12.455 161.705 ;
 RECT 12.825 161.515 13.015 161.705 ;
 RECT 13.385 161.515 13.575 161.705 ;
 RECT 17.865 160.955 18.055 161.145 ;
 RECT 17.305 160.955 17.495 161.145 ;
 RECT 16.745 160.955 16.935 161.145 ;
 RECT 16.185 160.955 16.375 161.145 ;
 RECT 15.625 160.955 15.815 161.145 ;
 RECT 15.065 160.955 15.255 161.145 ;
 RECT 17.865 161.515 18.055 161.705 ;
 RECT 17.305 161.515 17.495 161.705 ;
 RECT 16.745 161.515 16.935 161.705 ;
 RECT 15.065 161.515 15.255 161.705 ;
 RECT 15.625 161.515 15.815 161.705 ;
 RECT 16.185 161.515 16.375 161.705 ;
 RECT 20.665 160.955 20.855 161.145 ;
 RECT 20.105 160.955 20.295 161.145 ;
 RECT 19.545 160.955 19.735 161.145 ;
 RECT 18.985 160.955 19.175 161.145 ;
 RECT 18.425 160.955 18.615 161.145 ;
 RECT 18.985 161.515 19.175 161.705 ;
 RECT 19.545 161.515 19.735 161.705 ;
 RECT 20.105 161.515 20.295 161.705 ;
 RECT 20.665 161.515 20.855 161.705 ;
 RECT 18.425 161.515 18.615 161.705 ;
 RECT 23.465 160.955 23.655 161.145 ;
 RECT 24.025 160.955 24.215 161.145 ;
 RECT 21.785 160.955 21.975 161.145 ;
 RECT 22.345 160.955 22.535 161.145 ;
 RECT 22.905 160.955 23.095 161.145 ;
 RECT 23.465 161.515 23.655 161.705 ;
 RECT 24.025 161.515 24.215 161.705 ;
 RECT 22.905 161.515 23.095 161.705 ;
 RECT 22.345 161.515 22.535 161.705 ;
 RECT 21.785 161.515 21.975 161.705 ;
 RECT 21.225 160.955 21.415 161.145 ;
 RECT 21.225 161.515 21.415 161.705 ;
 RECT 25.705 160.955 25.895 161.145 ;
 RECT 26.265 160.955 26.455 161.145 ;
 RECT 26.825 160.955 27.015 161.145 ;
 RECT 27.385 160.955 27.575 161.145 ;
 RECT 25.145 160.955 25.335 161.145 ;
 RECT 25.705 161.515 25.895 161.705 ;
 RECT 27.385 161.515 27.575 161.705 ;
 RECT 26.825 161.515 27.015 161.705 ;
 RECT 26.265 161.515 26.455 161.705 ;
 RECT 25.145 161.515 25.335 161.705 ;
 RECT 30.745 160.955 30.935 161.145 ;
 RECT 30.185 160.955 30.375 161.145 ;
 RECT 29.625 160.955 29.815 161.145 ;
 END
 END vddhis
 PIN vssh
 USE GROUND ;
 DIRECTION INOUT ;
 PORT
 LAYER M5 ;
 RECT 73.415 124.15 75 129.15 ;
 END
 PORT
 LAYER M5 ;
 RECT 0 124.15 1.585 129.15 ;
 END
 PORT
 LAYER M5 ;
 RECT 0 148.13 1.585 152.13 ;
 END
 PORT
 LAYER M5 ;
 RECT 73.415 148.13 75 152.13 ;
 END
 PORT
 LAYER M4 ;
 RECT 73 124.15 75 129.15 ;
 END
 PORT
 LAYER M4 ;
 RECT 0 124.15 2 129.15 ;
 END
 PORT
 LAYER M4 ;
 RECT 0 148.13 2 152.13 ;
 END
 PORT
 LAYER M4 ;
 RECT 73 148.13 75 152.13 ;
 END
 PORT
 LAYER M3 ;
 RECT 73.72 9.91 75 28.65 ;
 END
 PORT
 LAYER M3 ;
 RECT 0 9.91 1.28 28.65 ;
 END
 PORT
 LAYER M3 ;
 RECT 0 31.95 1.28 50.69 ;
 END
 PORT
 LAYER M3 ;
 RECT 73.72 31.95 75 50.69 ;
 END
 END vssh
 OBS
 LAYER GATE ;
 RECT 0 0 75 162 ;
 LAYER MV1 ;
 RECT 0 0 75 162 ;
 LAYER MV2 ;
 RECT 0 0 75 162 ;
 LAYER MV3 ;
 RECT 0 0 75 162 ;
 LAYER MV4 ;
 RECT 0 0 75 162 ;
 LAYER M1 ;
 RECT 0 0 75 162 ;
 LAYER M2 ;
 RECT 65.1 160.22 75 162 ;
 RECT 0 160.22 9.9 162 ;
 RECT 0 0 75 160.22 ;
 LAYER M3 ;
 RECT 0 0 75 9.31 ;
 RECT 0 29.25 75 31.35 ;
 RECT 1.88 9.31 73.12 29.25 ;
 RECT 1.825 160.22 9.9 160.61 ;
 RECT 0 160.61 9.9 162 ;
 RECT 0 51.29 75 53.75 ;
 RECT 1.88 31.35 73.12 51.29 ;
 RECT 0 58.23 75 59.42 ;
 RECT 1.52 53.75 73.48 58.23 ;
 RECT 1.88 66.36 73.12 92.84 ;
 RECT 1.88 94.94 73.12 121.45 ;
 RECT 1.825 157.73 73.175 160.22 ;
 RECT 65.1 160.22 73.175 160.61 ;
 RECT 0 63.9 75 66.36 ;
 RECT 1.52 59.42 73.48 63.9 ;
 RECT 0 92.84 75 94.94 ;
 RECT 0 121.45 75 128.86 ;
 RECT 0 130.24 75 137.06 ;
 RECT 1.52 128.86 73.48 130.24 ;
 RECT 0 151.07 75 157.73 ;
 RECT 1.2 137.06 73.8 151.07 ;
 RECT 65.1 160.61 75 162 ;
 LAYER M4 ;
 RECT 0 0 75 123.91 ;
 RECT 0 129.39 75 130.58 ;
 RECT 2.24 123.91 72.76 129.39 ;
 RECT 2.6 135.39 72.4 147.06 ;
 RECT 0 134.56 75 135.39 ;
 RECT 2.24 130.58 72.76 134.56 ;
 RECT 0 147.06 75 147.89 ;
 RECT 0 152.37 75 153.56 ;
 RECT 2.24 147.89 72.76 152.37 ;
 RECT 0 156.54 75 157.73 ;
 RECT 2.24 153.56 72.76 156.54 ;
 RECT 0 160.71 75 162 ;
 RECT 1.825 157.73 73.175 160.71 ;
 LAYER M5 ;
 RECT 0 9.9 3.9 111.1 ;
 RECT 71.1 9.9 75 111.1 ;
 RECT 0 0 75 9.9 ;
 RECT 0 111.1 75 123.69 ;
 RECT 0 129.61 75 130.36 ;
 RECT 2.045 123.69 72.955 129.61 ;
 RECT 2.185 135.39 72.815 147.06 ;
 RECT 0 134.78 75 135.39 ;
 RECT 2.045 130.36 72.955 134.78 ;
 RECT 0 147.06 75 147.67 ;
 RECT 0 152.59 75 153.34 ;
 RECT 2.045 147.67 72.955 152.59 ;
 RECT 0 156.76 75 157.51 ;
 RECT 2.045 153.34 72.955 156.76 ;
 RECT 0 160.93 75 162 ;
 RECT 2.045 157.51 72.955 160.93 ;
 END
END RCMCU_PLVDDHIS

MACRO RCMCU_PLVDDHPOC
 CLASS PAD ;
 FOREIGN RCMCU_PLVDDHPOC ;
 ORIGIN 0 0 ;
 SIZE 75 BY 162 ;
 SYMMETRY X Y R90 ;
 PIN POC
 USE POWER ;
 DIRECTION INOUT ;
 PORT
 LAYER M3 ;
 RECT 73.72 129.1 75 130 ;
 END
 PORT
 LAYER M3 ;
 RECT 0 129.1 1.28 130 ;
 END
 PORT
 LAYER M3 ;
 RECT 52.525 160.79 53.025 162 ;
 END
 PORT
 LAYER M2 ;
 RECT 52.525 160.79 53.025 162 ;
 END
 PORT
 LAYER MV2 ;
 RECT 52.68 160.885 52.87 161.075 ;
 RECT 52.68 161.405 52.87 161.595 ;
 END
 END POC
 PIN gnd
 USE GROUND ;
 DIRECTION INOUT ;
 PORT
 LAYER M5 ;
 RECT 73.415 135.99 75 146.46 ;
 END
 PORT
 LAYER M5 ;
 RECT 0 135.99 1.585 146.46 ;
 END
 PORT
 LAYER M5 ;
 RECT 0 157.97 1.585 160.47 ;
 END
 PORT
 LAYER M5 ;
 RECT 73.415 157.97 75 160.47 ;
 END
 PORT
 LAYER M4 ;
 RECT 73 135.99 75 146.46 ;
 END
 PORT
 LAYER M4 ;
 RECT 0 135.99 2 146.46 ;
 END
 PORT
 LAYER M4 ;
 RECT 0 157.97 1.585 160.47 ;
 END
 PORT
 LAYER M4 ;
 RECT 73.415 157.97 75 160.47 ;
 END
 PORT
 LAYER M3 ;
 RECT 73.72 59.66 75 63.66 ;
 END
 PORT
 LAYER M3 ;
 RECT 0 59.66 1.28 63.66 ;
 END
 PORT
 LAYER M3 ;
 RECT 0 157.97 1.585 160.37 ;
 END
 PORT
 LAYER M3 ;
 RECT 73.415 157.97 75 160.37 ;
 END
 PORT
 LAYER MV3 ;
 RECT 73.6 158.44 73.79 158.63 ;
 RECT 74.21 158.44 74.4 158.63 ;
 RECT 73.6 159.05 73.79 159.24 ;
 RECT 74.21 159.05 74.4 159.24 ;
 RECT 73.6 159.66 73.79 159.85 ;
 RECT 74.21 159.66 74.4 159.85 ;
 RECT 0.6 158.44 0.79 158.63 ;
 RECT 1.21 158.44 1.4 158.63 ;
 RECT 0.6 159.05 0.79 159.24 ;
 RECT 1.21 159.05 1.4 159.24 ;
 RECT 0.6 159.66 0.79 159.85 ;
 RECT 1.21 159.66 1.4 159.85 ;
 END
 END gnd
 PIN vdd
 USE POWER ;
 DIRECTION INOUT ;
 PORT
 LAYER M5 ;
 RECT 73.415 153.8 75 156.3 ;
 END
 PORT
 LAYER M5 ;
 RECT 0 153.8 1.585 156.3 ;
 END
 PORT
 LAYER M4 ;
 RECT 73 153.8 75 156.3 ;
 END
 PORT
 LAYER M4 ;
 RECT 0 153.8 2 156.3 ;
 END
 END vdd
 PIN vddh
 USE POWER ;
 DIRECTION INOUT ;
 PORT
 LAYER M5 ;
 RECT 73.415 130.82 75 134.32 ;
 END
 PORT
 LAYER M5 ;
 RECT 0 130.82 1.585 134.32 ;
 END
 PORT
 LAYER M4 ;
 RECT 73 130.82 75 134.32 ;
 END
 PORT
 LAYER M4 ;
 RECT 0 130.82 2 134.32 ;
 END
 PORT
 LAYER M3 ;
 RECT 73.72 53.99 75 57.99 ;
 END
 PORT
 LAYER M3 ;
 RECT 0 53.99 1.28 57.99 ;
 END
 PORT
 LAYER M3 ;
 RECT 73.72 66.96 75 92.24 ;
 END
 PORT
 LAYER M3 ;
 RECT 0 66.96 1.28 92.24 ;
 END
 PORT
 LAYER M3 ;
 RECT 0 95.54 1.28 120.85 ;
 END
 PORT
 LAYER M3 ;
 RECT 73.72 95.54 75 120.85 ;
 END
 PORT
 LAYER M3 ;
 RECT 0 137.66 0.6 150.47 ;
 END
 PORT
 LAYER M3 ;
 RECT 74.4 137.66 75 150.47 ;
 END
 END vddh
 PIN vssh
 USE GROUND ;
 DIRECTION INOUT ;
 PORT
 LAYER M5 ;
 RECT 73.415 124.15 75 129.15 ;
 END
 PORT
 LAYER M5 ;
 RECT 0 124.15 1.585 129.15 ;
 END
 PORT
 LAYER M5 ;
 RECT 0 148.13 1.585 152.13 ;
 END
 PORT
 LAYER M5 ;
 RECT 73.415 148.13 75 152.13 ;
 END
 PORT
 LAYER M4 ;
 RECT 73 124.15 75 129.15 ;
 END
 PORT
 LAYER M4 ;
 RECT 0 124.15 2 129.15 ;
 END
 PORT
 LAYER M4 ;
 RECT 0 148.13 2 152.13 ;
 END
 PORT
 LAYER M4 ;
 RECT 73 148.13 75 152.13 ;
 END
 PORT
 LAYER M3 ;
 RECT 73.72 9.91 75 28.65 ;
 END
 PORT
 LAYER M3 ;
 RECT 0 9.91 1.28 28.65 ;
 END
 PORT
 LAYER M3 ;
 RECT 0 31.95 1.28 50.69 ;
 END
 PORT
 LAYER M3 ;
 RECT 73.72 31.95 75 50.69 ;
 END
 END vssh
 OBS
 LAYER GATE ;
 RECT 0 0 75 162 ;
 LAYER MV1 ;
 RECT 0 0 75 162 ;
 LAYER MV2 ;
 RECT 0 0 75 162 ;
 LAYER MV3 ;
 RECT 0 0 75 162 ;
 LAYER MV4 ;
 RECT 0 0 75 162 ;
 LAYER M1 ;
 RECT 0 0 75 162 ;
 LAYER M2 ;
 RECT 53.265 160.55 75 162 ;
 RECT 0 160.55 52.285 162 ;
 RECT 0 0 75 160.55 ;
 LAYER M3 ;
 RECT 0 0 75 9.31 ;
 RECT 0 29.25 75 31.35 ;
 RECT 1.88 9.31 73.12 29.25 ;
 RECT 1.825 160.55 52.285 160.61 ;
 RECT 0 160.61 52.285 162 ;
 RECT 0 51.29 75 53.75 ;
 RECT 1.88 31.35 73.12 51.29 ;
 RECT 0 58.23 75 59.42 ;
 RECT 1.52 53.75 73.48 58.23 ;
 RECT 1.88 66.36 73.12 92.84 ;
 RECT 1.88 94.94 73.12 121.45 ;
 RECT 1.825 157.73 73.175 160.55 ;
 RECT 53.265 160.55 73.175 160.61 ;
 RECT 0 63.9 75 66.36 ;
 RECT 1.52 59.42 73.48 63.9 ;
 RECT 0 92.84 75 94.94 ;
 RECT 0 121.45 75 128.86 ;
 RECT 0 130.24 75 137.06 ;
 RECT 1.52 128.86 73.48 130.24 ;
 RECT 0 151.07 75 157.73 ;
 RECT 1.2 137.06 73.8 151.07 ;
 RECT 53.265 160.61 75 162 ;
 LAYER M4 ;
 RECT 0 0 75 123.91 ;
 RECT 0 129.39 75 130.58 ;
 RECT 2.24 123.91 72.76 129.39 ;
 RECT 2.6 135.39 72.4 147.06 ;
 RECT 0 134.56 75 135.39 ;
 RECT 2.24 130.58 72.76 134.56 ;
 RECT 0 147.06 75 147.89 ;
 RECT 0 152.37 75 153.56 ;
 RECT 2.24 147.89 72.76 152.37 ;
 RECT 0 156.54 75 157.73 ;
 RECT 2.24 153.56 72.76 156.54 ;
 RECT 0 160.71 75 162 ;
 RECT 1.825 157.73 73.175 160.71 ;
 LAYER M5 ;
 RECT 0 0 75 123.69 ;
 RECT 0 129.61 75 130.36 ;
 RECT 2.045 123.69 72.955 129.61 ;
 RECT 2.185 135.39 72.815 147.06 ;
 RECT 0 134.78 75 135.39 ;
 RECT 2.045 130.36 72.955 134.78 ;
 RECT 0 147.06 75 147.67 ;
 RECT 0 152.59 75 153.34 ;
 RECT 2.045 147.67 72.955 152.59 ;
 RECT 0 156.76 75 157.51 ;
 RECT 2.045 153.34 72.955 156.76 ;
 RECT 0 160.93 75 162 ;
 RECT 2.045 157.51 72.955 160.93 ;
 END
END RCMCU_PLVDDHPOC

MACRO RCMCU_PLVDDH_NOPOC
 CLASS PAD ;
 FOREIGN RCMCU_PLVDDH_NOPOC ;
 ORIGIN 0 0 ;
 SIZE 75 BY 162 ;
 SYMMETRY X Y R90 ;
 PIN POC
 USE POWER ;
 DIRECTION INOUT ;
 PORT
 LAYER M3 ;
 RECT 73.72 129.1 75 130 ;
 END
 PORT
 LAYER M3 ;
 RECT 0 129.1 1.28 130 ;
 END
 END POC
 PIN gnd
 USE GROUND ;
 DIRECTION INOUT ;
 PORT
 LAYER M5 ;
 RECT 73.415 135.99 75 146.46 ;
 END
 PORT
 LAYER M5 ;
 RECT 0 135.99 1.585 146.46 ;
 END
 PORT
 LAYER M5 ;
 RECT 0 157.97 1.585 160.47 ;
 END
 PORT
 LAYER M5 ;
 RECT 73.415 157.97 75 160.47 ;
 END
 PORT
 LAYER M4 ;
 RECT 73 135.99 75 146.46 ;
 END
 PORT
 LAYER M4 ;
 RECT 0 135.99 2 146.46 ;
 END
 PORT
 LAYER M4 ;
 RECT 0 157.97 1.585 160.47 ;
 END
 PORT
 LAYER M4 ;
 RECT 73.415 157.97 75 160.47 ;
 END
 PORT
 LAYER M3 ;
 RECT 73.72 59.66 75 63.66 ;
 END
 PORT
 LAYER M3 ;
 RECT 0 59.66 1.28 63.66 ;
 END
 PORT
 LAYER M3 ;
 RECT 0 157.97 1.585 160.37 ;
 END
 PORT
 LAYER M3 ;
 RECT 73.415 157.97 75 160.37 ;
 END
 PORT
 LAYER MV3 ;
 RECT 73.6 158.44 73.79 158.63 ;
 RECT 74.21 158.44 74.4 158.63 ;
 RECT 73.6 159.05 73.79 159.24 ;
 RECT 74.21 159.05 74.4 159.24 ;
 RECT 73.6 159.66 73.79 159.85 ;
 RECT 74.21 159.66 74.4 159.85 ;
 RECT 0.6 158.44 0.79 158.63 ;
 RECT 1.21 158.44 1.4 158.63 ;
 RECT 0.6 159.05 0.79 159.24 ;
 RECT 1.21 159.05 1.4 159.24 ;
 RECT 0.6 159.66 0.79 159.85 ;
 RECT 1.21 159.66 1.4 159.85 ;
 END
 END gnd
 PIN vdd
 USE POWER ;
 DIRECTION INOUT ;
 PORT
 LAYER M5 ;
 RECT 73.415 153.8 75 156.3 ;
 END
 PORT
 LAYER M5 ;
 RECT 0 153.8 1.585 156.3 ;
 END
 PORT
 LAYER M4 ;
 RECT 73 153.8 75 156.3 ;
 END
 PORT
 LAYER M4 ;
 RECT 0 153.8 2 156.3 ;
 END
 END vdd
 PIN vddh
 USE POWER ;
 DIRECTION INOUT ;
 PORT
 LAYER M5 ;
 RECT 4.5 10.5 70.5 110.5 ;
 END
 PORT
 LAYER M5 ;
 RECT 0 130.82 1.585 134.32 ;
 END
 PORT
 LAYER M5 ;
 RECT 73.415 130.82 75 134.32 ;
 END
 PORT
 LAYER M4 ;
 RECT 73 130.82 75 134.32 ;
 END
 PORT
 LAYER M4 ;
 RECT 0 130.82 2 134.32 ;
 END
 PORT
 LAYER M3 ;
 RECT 73.72 53.99 75 57.99 ;
 END
 PORT
 LAYER M3 ;
 RECT 0 53.99 1.28 57.99 ;
 END
 PORT
 LAYER M3 ;
 RECT 73.72 66.96 75 92.24 ;
 END
 PORT
 LAYER M3 ;
 RECT 0 66.96 1.28 92.24 ;
 END
 PORT
 LAYER M3 ;
 RECT 0 95.54 1.28 120.85 ;
 END
 PORT
 LAYER M3 ;
 RECT 73.72 95.54 75 120.85 ;
 END
 PORT
 LAYER M3 ;
 RECT 0 137.66 0.6 150.47 ;
 END
 PORT
 LAYER M3 ;
 RECT 74.4 137.66 75 150.47 ;
 END
 PORT
 LAYER M3 ;
 RECT 10.5 160.82 64.5 162 ;
 END
 PORT
 LAYER M2 ;
 RECT 10.5 160.82 64.5 162 ;
 END
 PORT
 LAYER MV2 ;
 RECT 32.615 160.955 32.805 161.145 ;
 RECT 33.175 161.515 33.365 161.705 ;
 RECT 33.735 161.515 33.925 161.705 ;
 RECT 32.615 161.515 32.805 161.705 ;
 RECT 32.055 161.515 32.245 161.705 ;
 RECT 31.495 161.515 31.685 161.705 ;
 RECT 30.935 161.515 31.125 161.705 ;
 RECT 37.095 160.955 37.285 161.145 ;
 RECT 36.535 160.955 36.725 161.145 ;
 RECT 35.975 160.955 36.165 161.145 ;
 RECT 35.415 160.955 35.605 161.145 ;
 RECT 34.855 160.955 35.045 161.145 ;
 RECT 34.295 160.955 34.485 161.145 ;
 RECT 37.095 161.515 37.285 161.705 ;
 RECT 36.535 161.515 36.725 161.705 ;
 RECT 35.975 161.515 36.165 161.705 ;
 RECT 35.415 161.515 35.605 161.705 ;
 RECT 34.295 161.515 34.485 161.705 ;
 RECT 34.855 161.515 35.045 161.705 ;
 RECT 39.895 160.955 40.085 161.145 ;
 RECT 40.455 160.955 40.645 161.145 ;
 RECT 39.335 160.955 39.525 161.145 ;
 RECT 38.775 160.955 38.965 161.145 ;
 RECT 38.215 160.955 38.405 161.145 ;
 RECT 37.655 160.955 37.845 161.145 ;
 RECT 39.895 161.515 40.085 161.705 ;
 RECT 40.455 161.515 40.645 161.705 ;
 RECT 37.655 161.515 37.845 161.705 ;
 RECT 38.215 161.515 38.405 161.705 ;
 RECT 38.775 161.515 38.965 161.705 ;
 RECT 39.335 161.515 39.525 161.705 ;
 RECT 42.135 160.955 42.325 161.145 ;
 RECT 42.695 160.955 42.885 161.145 ;
 RECT 43.255 160.955 43.445 161.145 ;
 RECT 43.815 160.955 44.005 161.145 ;
 RECT 41.015 160.955 41.205 161.145 ;
 RECT 41.575 160.955 41.765 161.145 ;
 RECT 42.135 161.515 42.325 161.705 ;
 RECT 42.695 161.515 42.885 161.705 ;
 RECT 43.255 161.515 43.445 161.705 ;
 RECT 43.815 161.515 44.005 161.705 ;
 RECT 41.575 161.515 41.765 161.705 ;
 RECT 41.015 161.515 41.205 161.705 ;
 RECT 47.175 160.955 47.365 161.145 ;
 RECT 44.375 160.955 44.565 161.145 ;
 RECT 44.935 160.955 45.125 161.145 ;
 RECT 45.495 160.955 45.685 161.145 ;
 RECT 46.055 160.955 46.245 161.145 ;
 RECT 46.615 160.955 46.805 161.145 ;
 RECT 47.175 161.515 47.365 161.705 ;
 RECT 44.375 161.515 44.565 161.705 ;
 RECT 46.615 161.515 46.805 161.705 ;
 RECT 46.055 161.515 46.245 161.705 ;
 RECT 45.495 161.515 45.685 161.705 ;
 RECT 44.935 161.515 45.125 161.705 ;
 RECT 50.535 160.955 50.725 161.145 ;
 RECT 49.975 160.955 50.165 161.145 ;
 RECT 49.415 160.955 49.605 161.145 ;
 RECT 48.855 160.955 49.045 161.145 ;
 RECT 48.295 160.955 48.485 161.145 ;
 RECT 47.735 160.955 47.925 161.145 ;
 RECT 49.415 161.515 49.605 161.705 ;
 RECT 49.975 161.515 50.165 161.705 ;
 RECT 50.535 161.515 50.725 161.705 ;
 RECT 48.855 161.515 49.045 161.705 ;
 RECT 48.295 161.515 48.485 161.705 ;
 RECT 47.735 161.515 47.925 161.705 ;
 RECT 53.895 160.955 54.085 161.145 ;
 RECT 53.335 160.955 53.525 161.145 ;
 RECT 52.775 160.955 52.965 161.145 ;
 RECT 52.215 160.955 52.405 161.145 ;
 RECT 51.655 160.955 51.845 161.145 ;
 RECT 51.095 160.955 51.285 161.145 ;
 RECT 53.895 161.515 54.085 161.705 ;
 RECT 51.655 161.515 51.845 161.705 ;
 RECT 52.215 161.515 52.405 161.705 ;
 RECT 52.775 161.515 52.965 161.705 ;
 RECT 53.335 161.515 53.525 161.705 ;
 RECT 51.095 161.515 51.285 161.705 ;
 RECT 56.135 160.955 56.325 161.145 ;
 RECT 56.695 160.955 56.885 161.145 ;
 RECT 57.255 160.955 57.445 161.145 ;
 RECT 55.015 160.955 55.205 161.145 ;
 RECT 55.575 160.955 55.765 161.145 ;
 RECT 54.455 160.955 54.645 161.145 ;
 RECT 56.135 161.515 56.325 161.705 ;
 RECT 56.695 161.515 56.885 161.705 ;
 RECT 57.255 161.515 57.445 161.705 ;
 RECT 55.575 161.515 55.765 161.705 ;
 RECT 55.015 161.515 55.205 161.705 ;
 RECT 54.455 161.515 54.645 161.705 ;
 RECT 58.935 160.955 59.125 161.145 ;
 RECT 59.495 160.955 59.685 161.145 ;
 RECT 60.055 160.955 60.245 161.145 ;
 RECT 60.615 160.955 60.805 161.145 ;
 RECT 57.815 160.955 58.005 161.145 ;
 RECT 58.375 160.955 58.565 161.145 ;
 RECT 60.615 161.515 60.805 161.705 ;
 RECT 60.055 161.515 60.245 161.705 ;
 RECT 59.495 161.515 59.685 161.705 ;
 RECT 58.935 161.515 59.125 161.705 ;
 RECT 57.815 161.515 58.005 161.705 ;
 RECT 58.375 161.515 58.565 161.705 ;
 RECT 62.295 160.955 62.485 161.145 ;
 RECT 63.415 160.955 63.605 161.145 ;
 RECT 63.975 160.955 64.165 161.145 ;
 RECT 61.735 160.955 61.925 161.145 ;
 RECT 61.175 160.955 61.365 161.145 ;
 RECT 62.855 160.955 63.045 161.145 ;
 RECT 61.175 161.515 61.365 161.705 ;
 RECT 61.735 161.515 61.925 161.705 ;
 RECT 62.295 161.515 62.485 161.705 ;
 RECT 62.855 161.515 63.045 161.705 ;
 RECT 63.415 161.515 63.605 161.705 ;
 RECT 63.975 161.515 64.165 161.705 ;
 RECT 10.775 160.955 10.965 161.145 ;
 RECT 11.895 160.955 12.085 161.145 ;
 RECT 12.455 160.955 12.645 161.145 ;
 RECT 13.015 160.955 13.205 161.145 ;
 RECT 13.575 160.955 13.765 161.145 ;
 RECT 11.335 160.955 11.525 161.145 ;
 RECT 10.775 161.515 10.965 161.705 ;
 RECT 11.335 161.515 11.525 161.705 ;
 RECT 11.895 161.515 12.085 161.705 ;
 RECT 12.455 161.515 12.645 161.705 ;
 RECT 13.015 161.515 13.205 161.705 ;
 RECT 13.575 161.515 13.765 161.705 ;
 RECT 16.935 160.955 17.125 161.145 ;
 RECT 16.375 160.955 16.565 161.145 ;
 RECT 15.815 160.955 16.005 161.145 ;
 RECT 15.255 160.955 15.445 161.145 ;
 RECT 14.695 160.955 14.885 161.145 ;
 RECT 14.135 160.955 14.325 161.145 ;
 RECT 16.375 161.515 16.565 161.705 ;
 RECT 16.935 161.515 17.125 161.705 ;
 RECT 14.135 161.515 14.325 161.705 ;
 RECT 14.695 161.515 14.885 161.705 ;
 RECT 15.255 161.515 15.445 161.705 ;
 RECT 15.815 161.515 16.005 161.705 ;
 RECT 20.295 160.955 20.485 161.145 ;
 RECT 19.735 160.955 19.925 161.145 ;
 RECT 19.175 160.955 19.365 161.145 ;
 RECT 18.615 160.955 18.805 161.145 ;
 RECT 18.055 160.955 18.245 161.145 ;
 RECT 17.495 160.955 17.685 161.145 ;
 RECT 18.615 161.515 18.805 161.705 ;
 RECT 19.175 161.515 19.365 161.705 ;
 RECT 19.735 161.515 19.925 161.705 ;
 RECT 20.295 161.515 20.485 161.705 ;
 RECT 18.055 161.515 18.245 161.705 ;
 RECT 17.495 161.515 17.685 161.705 ;
 RECT 23.655 160.955 23.845 161.145 ;
 RECT 23.095 160.955 23.285 161.145 ;
 RECT 22.535 160.955 22.725 161.145 ;
 RECT 21.975 160.955 22.165 161.145 ;
 RECT 21.415 160.955 21.605 161.145 ;
 RECT 20.855 160.955 21.045 161.145 ;
 RECT 23.655 161.515 23.845 161.705 ;
 RECT 23.095 161.515 23.285 161.705 ;
 RECT 22.535 161.515 22.725 161.705 ;
 RECT 21.975 161.515 22.165 161.705 ;
 RECT 21.415 161.515 21.605 161.705 ;
 RECT 20.855 161.515 21.045 161.705 ;
 RECT 25.895 160.955 26.085 161.145 ;
 RECT 26.455 160.955 26.645 161.145 ;
 RECT 27.015 160.955 27.205 161.145 ;
 RECT 24.215 160.955 24.405 161.145 ;
 RECT 24.775 160.955 24.965 161.145 ;
 RECT 25.335 160.955 25.525 161.145 ;
 RECT 27.015 161.515 27.205 161.705 ;
 RECT 26.455 161.515 26.645 161.705 ;
 RECT 25.895 161.515 26.085 161.705 ;
 RECT 24.215 161.515 24.405 161.705 ;
 RECT 24.775 161.515 24.965 161.705 ;
 RECT 25.335 161.515 25.525 161.705 ;
 RECT 30.375 160.955 30.565 161.145 ;
 RECT 29.815 160.955 30.005 161.145 ;
 RECT 29.255 160.955 29.445 161.145 ;
 RECT 28.695 160.955 28.885 161.145 ;
 RECT 28.135 160.955 28.325 161.145 ;
 RECT 27.575 160.955 27.765 161.145 ;
 RECT 30.375 161.515 30.565 161.705 ;
 RECT 28.135 161.515 28.325 161.705 ;
 RECT 28.695 161.515 28.885 161.705 ;
 RECT 29.255 161.515 29.445 161.705 ;
 RECT 29.815 161.515 30.005 161.705 ;
 RECT 27.575 161.515 27.765 161.705 ;
 RECT 33.735 160.955 33.925 161.145 ;
 RECT 33.175 160.955 33.365 161.145 ;
 RECT 30.935 160.955 31.125 161.145 ;
 RECT 31.495 160.955 31.685 161.145 ;
 RECT 32.055 160.955 32.245 161.145 ;
 END
 END vddh
 PIN vssh
 USE GROUND ;
 DIRECTION INOUT ;
 PORT
 LAYER M5 ;
 RECT 73.415 124.15 75 129.15 ;
 END
 PORT
 LAYER M5 ;
 RECT 0 124.15 1.585 129.15 ;
 END
 PORT
 LAYER M5 ;
 RECT 0 148.13 1.585 152.13 ;
 END
 PORT
 LAYER M5 ;
 RECT 73.415 148.13 75 152.13 ;
 END
 PORT
 LAYER M4 ;
 RECT 73 124.15 75 129.15 ;
 END
 PORT
 LAYER M4 ;
 RECT 0 124.15 2 129.15 ;
 END
 PORT
 LAYER M4 ;
 RECT 0 148.13 2 152.13 ;
 END
 PORT
 LAYER M4 ;
 RECT 73 148.13 75 152.13 ;
 END
 PORT
 LAYER M3 ;
 RECT 73.72 9.91 75 28.65 ;
 END
 PORT
 LAYER M3 ;
 RECT 0 9.91 1.28 28.65 ;
 END
 PORT
 LAYER M3 ;
 RECT 0 31.95 1.28 50.69 ;
 END
 PORT
 LAYER M3 ;
 RECT 73.72 31.95 75 50.69 ;
 END
 END vssh
 OBS
 LAYER GATE ;
 RECT 0 0 75 162 ;
 LAYER MV1 ;
 RECT 0 0 75 162 ;
 LAYER MV2 ;
 RECT 0 0 75 162 ;
 LAYER MV3 ;
 RECT 0 0 75 162 ;
 LAYER MV4 ;
 RECT 0 0 75 162 ;
 LAYER M1 ;
 RECT 0 0 75 162 ;
 LAYER M2 ;
 RECT 65.1 160.22 75 162 ;
 RECT 0 160.22 9.9 162 ;
 RECT 0 0 75 160.22 ;
 LAYER M3 ;
 RECT 0 29.25 75 31.35 ;
 RECT 1.88 9.31 73.12 29.25 ;
 RECT 1.825 160.22 9.9 160.61 ;
 RECT 0 160.61 9.9 162 ;
 RECT 0 51.29 75 53.75 ;
 RECT 1.88 31.35 73.12 51.29 ;
 RECT 0 58.23 75 59.42 ;
 RECT 1.52 53.75 73.48 58.23 ;
 RECT 1.88 66.36 73.12 92.84 ;
 RECT 1.88 94.94 73.12 121.45 ;
 RECT 1.825 157.73 73.175 160.22 ;
 RECT 65.1 160.22 73.175 160.61 ;
 RECT 0 63.9 75 66.36 ;
 RECT 1.52 59.42 73.48 63.9 ;
 RECT 0 92.84 75 94.94 ;
 RECT 0 121.45 75 128.86 ;
 RECT 0 130.24 75 137.06 ;
 RECT 1.52 128.86 73.48 130.24 ;
 RECT 0 151.07 75 157.73 ;
 RECT 1.2 137.06 73.8 151.07 ;
 RECT 65.1 160.61 75 162 ;
 RECT 0 0 75 9.31 ;
 LAYER M4 ;
 RECT 0 0 75 123.91 ;
 RECT 0 129.39 75 130.58 ;
 RECT 2.24 123.91 72.76 129.39 ;
 RECT 2.6 135.39 72.4 147.06 ;
 RECT 0 134.56 75 135.39 ;
 RECT 2.24 130.58 72.76 134.56 ;
 RECT 0 147.06 75 147.89 ;
 RECT 0 152.37 75 153.56 ;
 RECT 2.24 147.89 72.76 152.37 ;
 RECT 0 156.54 75 157.73 ;
 RECT 2.24 153.56 72.76 156.54 ;
 RECT 0 160.71 75 162 ;
 RECT 1.825 157.73 73.175 160.71 ;
 LAYER M5 ;
 RECT 0 9.9 3.9 111.1 ;
 RECT 71.1 9.9 75 111.1 ;
 RECT 0 0 75 9.9 ;
 RECT 0 111.1 75 123.69 ;
 RECT 0 129.61 75 130.36 ;
 RECT 2.045 123.69 72.955 129.61 ;
 RECT 2.185 135.39 72.815 147.06 ;
 RECT 0 134.78 75 135.39 ;
 RECT 2.045 130.36 72.955 134.78 ;
 RECT 0 147.06 75 147.67 ;
 RECT 0 152.59 75 153.34 ;
 RECT 2.045 147.67 72.955 152.59 ;
 RECT 0 156.76 75 157.51 ;
 RECT 2.045 153.34 72.955 156.76 ;
 RECT 0 160.93 75 162 ;
 RECT 2.045 157.51 72.955 160.93 ;
 END
END RCMCU_PLVDDH_NOPOC

MACRO RCMCU_PLVDDI
 CLASS PAD ;
 FOREIGN RCMCU_PLVDDI ;
 ORIGIN 0 0 ;
 SIZE 175 BY 162 ;
 SYMMETRY X Y R90 ;
 PIN POC
 USE POWER ;
 DIRECTION INOUT ;
 PORT
 LAYER M3 ;
 RECT 173.72 129.1 175 130 ;
 END
 PORT
 LAYER M3 ;
 RECT 0 129.1 1.28 130 ;
 END
 END POC
 PIN gnd
 USE GROUND ;
 DIRECTION INOUT ;
 PORT
 LAYER M5 ;
 RECT 173.415 135.99 175 146.46 ;
 END
 PORT
 LAYER M5 ;
 RECT 0 135.99 1.585 146.46 ;
 END
 PORT
 LAYER M5 ;
 RECT 0 157.97 1.585 160.47 ;
 END
 PORT
 LAYER M5 ;
 RECT 173.415 157.97 175 160.47 ;
 END
 PORT
 LAYER M4 ;
 RECT 173 135.99 175 146.46 ;
 END
 PORT
 LAYER M4 ;
 RECT 0 135.99 2 146.46 ;
 END
 PORT
 LAYER M4 ;
 RECT 0 157.97 2 160.47 ;
 END
 PORT
 LAYER M4 ;
 RECT 173 157.97 175 160.47 ;
 END
 PORT
 LAYER M3 ;
 RECT 173.72 59.66 175 63.66 ;
 END
 PORT
 LAYER M3 ;
 RECT 0 59.66 1.28 63.66 ;
 END
 PORT
 LAYER M3 ;
 RECT 0 157.97 1.28 160.37 ;
 END
 PORT
 LAYER M3 ;
 RECT 173.72 157.97 175 160.37 ;
 END
 PORT
 LAYER MV3 ;
 RECT 174.175 158.525 174.365 158.715 ;
 RECT 174.175 159.325 174.365 159.515 ;
 RECT 0.635 158.525 0.825 158.715 ;
 RECT 0.635 159.325 0.825 159.515 ;
 END
 END gnd
 PIN vdd
 USE POWER ;
 DIRECTION INOUT ;
 PORT
 LAYER M5 ;
 RECT 173.415 153.8 175 156.3 ;
 END
 PORT
 LAYER M5 ;
 RECT 0 153.8 1.585 156.3 ;
 END
 PORT
 LAYER M4 ;
 RECT 173 153.8 175 156.3 ;
 END
 PORT
 LAYER M4 ;
 RECT 0 153.8 2 156.3 ;
 END
 END vdd
 PIN vddh
 USE POWER ;
 DIRECTION INOUT ;
 PORT
 LAYER M5 ;
 RECT 173.415 130.82 175 134.32 ;
 END
 PORT
 LAYER M5 ;
 RECT 0 130.82 1.585 134.32 ;
 END
 PORT
 LAYER M4 ;
 RECT 173 130.82 175 134.32 ;
 END
 PORT
 LAYER M4 ;
 RECT 0 130.82 2 134.32 ;
 END
 PORT
 LAYER M3 ;
 RECT 173.72 53.99 175 57.99 ;
 END
 PORT
 LAYER M3 ;
 RECT 0 53.99 1.28 57.99 ;
 END
 PORT
 LAYER M3 ;
 RECT 173.72 66.96 175 92.24 ;
 END
 PORT
 LAYER M3 ;
 RECT 0 66.96 1.28 92.24 ;
 END
 PORT
 LAYER M3 ;
 RECT 0 95.54 1.28 120.85 ;
 END
 PORT
 LAYER M3 ;
 RECT 173.72 95.54 175 120.85 ;
 END
 PORT
 LAYER M3 ;
 RECT 0 137.66 0.6 150.47 ;
 END
 PORT
 LAYER M3 ;
 RECT 174.4 137.66 175 150.47 ;
 END
 END vddh
 PIN vddi
 USE POWER ;
 DIRECTION INOUT ;
 PORT
 LAYER M5 ;
 RECT 4.5 10.5 70.5 110.5 ;
 END
 PORT
 LAYER M3 ;
 RECT 10.5 160.82 62.55 162 ;
 END
 PORT
 LAYER M2 ;
 RECT 10.5 160.82 62.55 162 ;
 END
 PORT
 LAYER MV2 ;
 RECT 40.09 161.515 40.28 161.705 ;
 RECT 40.65 161.515 40.84 161.705 ;
 RECT 44.01 160.955 44.2 161.145 ;
 RECT 44.57 160.955 44.76 161.145 ;
 RECT 45.13 160.955 45.32 161.145 ;
 RECT 45.69 160.955 45.88 161.145 ;
 RECT 43.45 160.955 43.64 161.145 ;
 RECT 44.01 161.515 44.2 161.705 ;
 RECT 44.57 161.515 44.76 161.705 ;
 RECT 45.13 161.515 45.32 161.705 ;
 RECT 45.69 161.515 45.88 161.705 ;
 RECT 43.45 161.515 43.64 161.705 ;
 RECT 49.05 160.955 49.24 161.145 ;
 RECT 46.81 160.955 47 161.145 ;
 RECT 47.37 160.955 47.56 161.145 ;
 RECT 48.49 160.955 48.68 161.145 ;
 RECT 47.93 160.955 48.12 161.145 ;
 RECT 46.25 160.955 46.44 161.145 ;
 RECT 49.05 161.515 49.24 161.705 ;
 RECT 46.81 161.515 47 161.705 ;
 RECT 47.37 161.515 47.56 161.705 ;
 RECT 47.93 161.515 48.12 161.705 ;
 RECT 48.49 161.515 48.68 161.705 ;
 RECT 46.25 161.515 46.44 161.705 ;
 RECT 42.89 160.955 43.08 161.145 ;
 RECT 42.89 161.515 43.08 161.705 ;
 RECT 51.85 160.955 52.04 161.145 ;
 RECT 49.61 160.955 49.8 161.145 ;
 RECT 50.17 160.955 50.36 161.145 ;
 RECT 50.73 160.955 50.92 161.145 ;
 RECT 51.29 160.955 51.48 161.145 ;
 RECT 51.85 161.515 52.04 161.705 ;
 RECT 51.29 161.515 51.48 161.705 ;
 RECT 50.73 161.515 50.92 161.705 ;
 RECT 50.17 161.515 50.36 161.705 ;
 RECT 49.61 161.515 49.8 161.705 ;
 RECT 54.65 160.955 54.84 161.145 ;
 RECT 55.21 160.955 55.4 161.145 ;
 RECT 52.97 160.955 53.16 161.145 ;
 RECT 53.53 160.955 53.72 161.145 ;
 RECT 54.09 160.955 54.28 161.145 ;
 RECT 54.65 161.515 54.84 161.705 ;
 RECT 55.21 161.515 55.4 161.705 ;
 RECT 54.09 161.515 54.28 161.705 ;
 RECT 52.97 161.515 53.16 161.705 ;
 RECT 53.53 161.515 53.72 161.705 ;
 RECT 52.41 160.955 52.6 161.145 ;
 RECT 52.41 161.515 52.6 161.705 ;
 RECT 57.45 160.955 57.64 161.145 ;
 RECT 58.01 160.955 58.2 161.145 ;
 RECT 58.57 160.955 58.76 161.145 ;
 RECT 55.77 160.955 55.96 161.145 ;
 RECT 56.33 160.955 56.52 161.145 ;
 RECT 56.89 160.955 57.08 161.145 ;
 RECT 57.45 161.515 57.64 161.705 ;
 RECT 58.01 161.515 58.2 161.705 ;
 RECT 58.57 161.515 58.76 161.705 ;
 RECT 55.77 161.515 55.96 161.705 ;
 RECT 56.33 161.515 56.52 161.705 ;
 RECT 56.89 161.515 57.08 161.705 ;
 RECT 60.25 160.955 60.44 161.145 ;
 RECT 60.81 160.955 61 161.145 ;
 RECT 61.37 160.955 61.56 161.145 ;
 RECT 61.93 160.955 62.12 161.145 ;
 RECT 59.69 160.955 59.88 161.145 ;
 RECT 59.13 160.955 59.32 161.145 ;
 RECT 61.93 161.515 62.12 161.705 ;
 RECT 60.81 161.515 61 161.705 ;
 RECT 60.25 161.515 60.44 161.705 ;
 RECT 61.37 161.515 61.56 161.705 ;
 RECT 59.13 161.515 59.32 161.705 ;
 RECT 59.69 161.515 59.88 161.705 ;
 RECT 13.77 160.955 13.96 161.145 ;
 RECT 10.97 160.955 11.16 161.145 ;
 RECT 11.53 160.955 11.72 161.145 ;
 RECT 12.09 160.955 12.28 161.145 ;
 RECT 12.65 160.955 12.84 161.145 ;
 RECT 13.21 160.955 13.4 161.145 ;
 RECT 13.77 161.515 13.96 161.705 ;
 RECT 13.21 161.515 13.4 161.705 ;
 RECT 12.65 161.515 12.84 161.705 ;
 RECT 12.09 161.515 12.28 161.705 ;
 RECT 11.53 161.515 11.72 161.705 ;
 RECT 10.97 161.515 11.16 161.705 ;
 RECT 16.57 160.955 16.76 161.145 ;
 RECT 17.13 160.955 17.32 161.145 ;
 RECT 14.33 160.955 14.52 161.145 ;
 RECT 16.01 160.955 16.2 161.145 ;
 RECT 15.45 160.955 15.64 161.145 ;
 RECT 14.89 160.955 15.08 161.145 ;
 RECT 17.13 161.515 17.32 161.705 ;
 RECT 16.57 161.515 16.76 161.705 ;
 RECT 14.33 161.515 14.52 161.705 ;
 RECT 16.01 161.515 16.2 161.705 ;
 RECT 15.45 161.515 15.64 161.705 ;
 RECT 14.89 161.515 15.08 161.705 ;
 RECT 19.37 160.955 19.56 161.145 ;
 RECT 19.93 160.955 20.12 161.145 ;
 RECT 17.69 160.955 17.88 161.145 ;
 RECT 18.25 160.955 18.44 161.145 ;
 RECT 18.81 160.955 19 161.145 ;
 RECT 19.93 161.515 20.12 161.705 ;
 RECT 19.37 161.515 19.56 161.705 ;
 RECT 18.81 161.515 19 161.705 ;
 RECT 18.25 161.515 18.44 161.705 ;
 RECT 17.69 161.515 17.88 161.705 ;
 RECT 22.17 160.955 22.36 161.145 ;
 RECT 22.73 160.955 22.92 161.145 ;
 RECT 23.29 160.955 23.48 161.145 ;
 RECT 21.61 160.955 21.8 161.145 ;
 RECT 21.05 160.955 21.24 161.145 ;
 RECT 23.29 161.515 23.48 161.705 ;
 RECT 22.73 161.515 22.92 161.705 ;
 RECT 22.17 161.515 22.36 161.705 ;
 RECT 21.61 161.515 21.8 161.705 ;
 RECT 21.05 161.515 21.24 161.705 ;
 RECT 20.49 160.955 20.68 161.145 ;
 RECT 20.49 161.515 20.68 161.705 ;
 RECT 24.97 160.955 25.16 161.145 ;
 RECT 25.53 160.955 25.72 161.145 ;
 RECT 26.65 160.955 26.84 161.145 ;
 RECT 26.09 160.955 26.28 161.145 ;
 RECT 23.85 160.955 24.04 161.145 ;
 RECT 24.41 160.955 24.6 161.145 ;
 RECT 26.09 161.515 26.28 161.705 ;
 RECT 26.65 161.515 26.84 161.705 ;
 RECT 25.53 161.515 25.72 161.705 ;
 RECT 24.97 161.515 25.16 161.705 ;
 RECT 24.41 161.515 24.6 161.705 ;
 RECT 23.85 161.515 24.04 161.705 ;
 RECT 27.21 160.955 27.4 161.145 ;
 RECT 27.77 160.955 27.96 161.145 ;
 RECT 28.33 160.955 28.52 161.145 ;
 RECT 28.89 160.955 29.08 161.145 ;
 RECT 29.45 160.955 29.64 161.145 ;
 RECT 27.21 161.515 27.4 161.705 ;
 RECT 27.77 161.515 27.96 161.705 ;
 RECT 28.33 161.515 28.52 161.705 ;
 RECT 28.89 161.515 29.08 161.705 ;
 RECT 29.45 161.515 29.64 161.705 ;
 RECT 32.81 160.955 33 161.145 ;
 RECT 30.57 160.955 30.76 161.145 ;
 RECT 31.13 160.955 31.32 161.145 ;
 RECT 31.69 160.955 31.88 161.145 ;
 RECT 32.25 160.955 32.44 161.145 ;
 RECT 32.81 161.515 33 161.705 ;
 RECT 30.57 161.515 30.76 161.705 ;
 RECT 31.13 161.515 31.32 161.705 ;
 RECT 31.69 161.515 31.88 161.705 ;
 RECT 32.25 161.515 32.44 161.705 ;
 RECT 35.61 160.955 35.8 161.145 ;
 RECT 36.17 160.955 36.36 161.145 ;
 RECT 33.37 160.955 33.56 161.145 ;
 RECT 33.93 160.955 34.12 161.145 ;
 RECT 34.49 160.955 34.68 161.145 ;
 RECT 35.05 160.955 35.24 161.145 ;
 RECT 35.61 161.515 35.8 161.705 ;
 RECT 36.17 161.515 36.36 161.705 ;
 RECT 35.05 161.515 35.24 161.705 ;
 RECT 34.49 161.515 34.68 161.705 ;
 RECT 33.93 161.515 34.12 161.705 ;
 RECT 33.37 161.515 33.56 161.705 ;
 RECT 30.01 160.955 30.2 161.145 ;
 RECT 30.01 161.515 30.2 161.705 ;
 RECT 38.41 160.955 38.6 161.145 ;
 RECT 38.97 160.955 39.16 161.145 ;
 RECT 39.53 160.955 39.72 161.145 ;
 RECT 37.85 160.955 38.04 161.145 ;
 RECT 37.29 160.955 37.48 161.145 ;
 RECT 36.73 160.955 36.92 161.145 ;
 RECT 38.41 161.515 38.6 161.705 ;
 RECT 38.97 161.515 39.16 161.705 ;
 RECT 39.53 161.515 39.72 161.705 ;
 RECT 36.73 161.515 36.92 161.705 ;
 RECT 37.29 161.515 37.48 161.705 ;
 RECT 37.85 161.515 38.04 161.705 ;
 RECT 41.21 160.955 41.4 161.145 ;
 RECT 41.77 160.955 41.96 161.145 ;
 RECT 42.33 160.955 42.52 161.145 ;
 RECT 40.09 160.955 40.28 161.145 ;
 RECT 40.65 160.955 40.84 161.145 ;
 RECT 41.21 161.515 41.4 161.705 ;
 RECT 41.77 161.515 41.96 161.705 ;
 RECT 42.33 161.515 42.52 161.705 ;
 END
 END vddi
 PIN vssh
 USE GROUND ;
 DIRECTION INOUT ;
 PORT
 LAYER M5 ;
 RECT 173.415 124.15 175 129.15 ;
 END
 PORT
 LAYER M5 ;
 RECT 0 124.15 1.585 129.15 ;
 END
 PORT
 LAYER M5 ;
 RECT 0 148.13 1.585 152.13 ;
 END
 PORT
 LAYER M5 ;
 RECT 173.415 148.13 175 152.13 ;
 END
 PORT
 LAYER M4 ;
 RECT 173 124.15 175 129.15 ;
 END
 PORT
 LAYER M4 ;
 RECT 0 124.15 2 129.15 ;
 END
 PORT
 LAYER M4 ;
 RECT 0 148.13 2 152.13 ;
 END
 PORT
 LAYER M4 ;
 RECT 173 148.13 175 152.13 ;
 END
 PORT
 LAYER M3 ;
 RECT 173.72 9.91 175 28.65 ;
 END
 PORT
 LAYER M3 ;
 RECT 0 9.91 1.28 28.65 ;
 END
 PORT
 LAYER M3 ;
 RECT 0 31.95 1.28 50.69 ;
 END
 PORT
 LAYER M3 ;
 RECT 173.72 31.95 175 50.69 ;
 END
 END vssh
 PIN vssi
 USE GROUND ;
 DIRECTION INOUT ;
 PORT
 LAYER M5 ;
 RECT 104.5 10.5 170.5 110.5 ;
 END
 PORT
 LAYER M3 ;
 RECT 112.45 160.82 164.5 162 ;
 END
 PORT
 LAYER M2 ;
 RECT 112.45 160.82 164.5 162 ;
 END
 PORT
 LAYER MV2 ;
 RECT 126.205 161.515 126.395 161.705 ;
 RECT 131.805 160.955 131.995 161.145 ;
 RECT 131.245 160.955 131.435 161.145 ;
 RECT 129.565 160.955 129.755 161.145 ;
 RECT 130.125 160.955 130.315 161.145 ;
 RECT 130.685 160.955 130.875 161.145 ;
 RECT 131.245 161.515 131.435 161.705 ;
 RECT 131.805 161.515 131.995 161.705 ;
 RECT 130.685 161.515 130.875 161.705 ;
 RECT 130.125 161.515 130.315 161.705 ;
 RECT 129.565 161.515 129.755 161.705 ;
 RECT 129.005 160.955 129.195 161.145 ;
 RECT 129.005 161.515 129.195 161.705 ;
 RECT 134.045 160.955 134.235 161.145 ;
 RECT 134.605 160.955 134.795 161.145 ;
 RECT 135.165 160.955 135.355 161.145 ;
 RECT 132.365 160.955 132.555 161.145 ;
 RECT 132.925 160.955 133.115 161.145 ;
 RECT 133.485 160.955 133.675 161.145 ;
 RECT 134.045 161.515 134.235 161.705 ;
 RECT 134.605 161.515 134.795 161.705 ;
 RECT 135.165 161.515 135.355 161.705 ;
 RECT 132.365 161.515 132.555 161.705 ;
 RECT 132.925 161.515 133.115 161.705 ;
 RECT 133.485 161.515 133.675 161.705 ;
 RECT 136.845 160.955 137.035 161.145 ;
 RECT 137.405 160.955 137.595 161.145 ;
 RECT 137.965 160.955 138.155 161.145 ;
 RECT 136.285 160.955 136.475 161.145 ;
 RECT 135.725 160.955 135.915 161.145 ;
 RECT 137.965 161.515 138.155 161.705 ;
 RECT 137.405 161.515 137.595 161.705 ;
 RECT 136.845 161.515 137.035 161.705 ;
 RECT 136.285 161.515 136.475 161.705 ;
 RECT 135.725 161.515 135.915 161.705 ;
 RECT 139.645 160.955 139.835 161.145 ;
 RECT 140.205 160.955 140.395 161.145 ;
 RECT 141.325 160.955 141.515 161.145 ;
 RECT 140.765 160.955 140.955 161.145 ;
 RECT 139.085 160.955 139.275 161.145 ;
 RECT 141.325 161.515 141.515 161.705 ;
 RECT 140.765 161.515 140.955 161.705 ;
 RECT 140.205 161.515 140.395 161.705 ;
 RECT 139.645 161.515 139.835 161.705 ;
 RECT 139.085 161.515 139.275 161.705 ;
 RECT 142.445 160.955 142.635 161.145 ;
 RECT 143.005 160.955 143.195 161.145 ;
 RECT 143.565 160.955 143.755 161.145 ;
 RECT 144.125 160.955 144.315 161.145 ;
 RECT 144.685 160.955 144.875 161.145 ;
 RECT 141.885 160.955 142.075 161.145 ;
 RECT 144.685 161.515 144.875 161.705 ;
 RECT 143.565 161.515 143.755 161.705 ;
 RECT 142.445 161.515 142.635 161.705 ;
 RECT 143.005 161.515 143.195 161.705 ;
 RECT 144.125 161.515 144.315 161.705 ;
 RECT 141.885 161.515 142.075 161.705 ;
 RECT 147.485 160.955 147.675 161.145 ;
 RECT 145.245 160.955 145.435 161.145 ;
 RECT 145.805 160.955 145.995 161.145 ;
 RECT 146.925 160.955 147.115 161.145 ;
 RECT 146.365 160.955 146.555 161.145 ;
 RECT 147.485 161.515 147.675 161.705 ;
 RECT 146.925 161.515 147.115 161.705 ;
 RECT 146.365 161.515 146.555 161.705 ;
 RECT 145.805 161.515 145.995 161.705 ;
 RECT 145.245 161.515 145.435 161.705 ;
 RECT 150.285 160.955 150.475 161.145 ;
 RECT 150.845 160.955 151.035 161.145 ;
 RECT 148.605 160.955 148.795 161.145 ;
 RECT 149.165 160.955 149.355 161.145 ;
 RECT 149.725 160.955 149.915 161.145 ;
 RECT 150.285 161.515 150.475 161.705 ;
 RECT 150.845 161.515 151.035 161.705 ;
 RECT 149.165 161.515 149.355 161.705 ;
 RECT 148.605 161.515 148.795 161.705 ;
 RECT 149.725 161.515 149.915 161.705 ;
 RECT 148.045 160.955 148.235 161.145 ;
 RECT 148.045 161.515 148.235 161.705 ;
 RECT 153.085 160.955 153.275 161.145 ;
 RECT 153.645 160.955 153.835 161.145 ;
 RECT 154.205 160.955 154.395 161.145 ;
 RECT 151.405 160.955 151.595 161.145 ;
 RECT 151.965 160.955 152.155 161.145 ;
 RECT 152.525 160.955 152.715 161.145 ;
 RECT 153.085 161.515 153.275 161.705 ;
 RECT 153.645 161.515 153.835 161.705 ;
 RECT 154.205 161.515 154.395 161.705 ;
 RECT 151.405 161.515 151.595 161.705 ;
 RECT 151.965 161.515 152.155 161.705 ;
 RECT 152.525 161.515 152.715 161.705 ;
 RECT 155.885 160.955 156.075 161.145 ;
 RECT 156.445 160.955 156.635 161.145 ;
 RECT 157.005 160.955 157.195 161.145 ;
 RECT 154.765 160.955 154.955 161.145 ;
 RECT 155.325 160.955 155.515 161.145 ;
 RECT 155.885 161.515 156.075 161.705 ;
 RECT 156.445 161.515 156.635 161.705 ;
 RECT 157.005 161.515 157.195 161.705 ;
 RECT 154.765 161.515 154.955 161.705 ;
 RECT 155.325 161.515 155.515 161.705 ;
 RECT 158.685 160.955 158.875 161.145 ;
 RECT 159.245 160.955 159.435 161.145 ;
 RECT 159.805 160.955 159.995 161.145 ;
 RECT 160.365 160.955 160.555 161.145 ;
 RECT 158.125 160.955 158.315 161.145 ;
 RECT 160.365 161.515 160.555 161.705 ;
 RECT 158.685 161.515 158.875 161.705 ;
 RECT 159.245 161.515 159.435 161.705 ;
 RECT 159.805 161.515 159.995 161.705 ;
 RECT 158.125 161.515 158.315 161.705 ;
 RECT 161.485 160.955 161.675 161.145 ;
 RECT 162.045 160.955 162.235 161.145 ;
 RECT 163.725 160.955 163.915 161.145 ;
 RECT 163.165 160.955 163.355 161.145 ;
 RECT 162.605 160.955 162.795 161.145 ;
 RECT 160.925 160.955 161.115 161.145 ;
 RECT 161.485 161.515 161.675 161.705 ;
 RECT 162.045 161.515 162.235 161.705 ;
 RECT 162.605 161.515 162.795 161.705 ;
 RECT 163.165 161.515 163.355 161.705 ;
 RECT 163.725 161.515 163.915 161.705 ;
 RECT 160.925 161.515 161.115 161.705 ;
 RECT 157.565 160.955 157.755 161.145 ;
 RECT 157.565 161.515 157.755 161.705 ;
 RECT 138.525 160.955 138.715 161.145 ;
 RECT 138.525 161.515 138.715 161.705 ;
 RECT 115.005 160.955 115.195 161.145 ;
 RECT 115.565 160.955 115.755 161.145 ;
 RECT 116.125 160.955 116.315 161.145 ;
 RECT 114.445 160.955 114.635 161.145 ;
 RECT 113.885 160.955 114.075 161.145 ;
 RECT 113.325 160.955 113.515 161.145 ;
 RECT 115.005 161.515 115.195 161.705 ;
 RECT 115.565 161.515 115.755 161.705 ;
 RECT 116.125 161.515 116.315 161.705 ;
 RECT 114.445 161.515 114.635 161.705 ;
 RECT 113.885 161.515 114.075 161.705 ;
 RECT 113.325 161.515 113.515 161.705 ;
 RECT 117.805 160.955 117.995 161.145 ;
 RECT 118.365 160.955 118.555 161.145 ;
 RECT 118.925 160.955 119.115 161.145 ;
 RECT 116.685 160.955 116.875 161.145 ;
 RECT 117.245 160.955 117.435 161.145 ;
 RECT 118.925 161.515 119.115 161.705 ;
 RECT 118.365 161.515 118.555 161.705 ;
 RECT 117.805 161.515 117.995 161.705 ;
 RECT 117.245 161.515 117.435 161.705 ;
 RECT 116.685 161.515 116.875 161.705 ;
 RECT 122.285 160.955 122.475 161.145 ;
 RECT 121.725 160.955 121.915 161.145 ;
 RECT 121.165 160.955 121.355 161.145 ;
 RECT 120.605 160.955 120.795 161.145 ;
 RECT 120.045 160.955 120.235 161.145 ;
 RECT 122.285 161.515 122.475 161.705 ;
 RECT 120.605 161.515 120.795 161.705 ;
 RECT 121.165 161.515 121.355 161.705 ;
 RECT 121.725 161.515 121.915 161.705 ;
 RECT 120.045 161.515 120.235 161.705 ;
 RECT 125.645 160.955 125.835 161.145 ;
 RECT 123.405 160.955 123.595 161.145 ;
 RECT 124.525 160.955 124.715 161.145 ;
 RECT 125.085 160.955 125.275 161.145 ;
 RECT 123.965 160.955 124.155 161.145 ;
 RECT 122.845 160.955 123.035 161.145 ;
 RECT 125.645 161.515 125.835 161.705 ;
 RECT 125.085 161.515 125.275 161.705 ;
 RECT 124.525 161.515 124.715 161.705 ;
 RECT 123.965 161.515 124.155 161.705 ;
 RECT 123.405 161.515 123.595 161.705 ;
 RECT 122.845 161.515 123.035 161.705 ;
 RECT 119.485 160.955 119.675 161.145 ;
 RECT 119.485 161.515 119.675 161.705 ;
 RECT 128.445 160.955 128.635 161.145 ;
 RECT 126.205 160.955 126.395 161.145 ;
 RECT 126.765 160.955 126.955 161.145 ;
 RECT 127.325 160.955 127.515 161.145 ;
 RECT 127.885 160.955 128.075 161.145 ;
 RECT 128.445 161.515 128.635 161.705 ;
 RECT 127.885 161.515 128.075 161.705 ;
 RECT 127.325 161.515 127.515 161.705 ;
 RECT 126.765 161.515 126.955 161.705 ;
 END
 END vssi
 OBS
 LAYER GATE ;
 RECT 0 0 175 162 ;
 LAYER MV1 ;
 RECT 0 0 175 162 ;
 LAYER MV2 ;
 RECT 0 0 175 162 ;
 LAYER MV3 ;
 RECT 0 0 175 162 ;
 LAYER MV4 ;
 RECT 0 0 175 162 ;
 LAYER M1 ;
 RECT 0 0 175 162 ;
 LAYER M2 ;
 RECT 0 0 175 160.22 ;
 RECT 63.15 160.22 111.85 162 ;
 RECT 0 160.22 9.9 162 ;
 RECT 165.1 160.22 175 162 ;
 LAYER M3 ;
 RECT 0 0 175 9.31 ;
 RECT 0 29.25 175 31.35 ;
 RECT 1.88 9.31 173.12 29.25 ;
 RECT 1.52 160.22 9.9 160.61 ;
 RECT 0 160.61 9.9 162 ;
 RECT 63.15 160.22 111.85 162 ;
 RECT 0 51.29 175 53.75 ;
 RECT 1.88 31.35 173.12 51.29 ;
 RECT 0 58.23 175 59.42 ;
 RECT 1.52 53.75 173.48 58.23 ;
 RECT 1.88 66.36 173.12 92.84 ;
 RECT 1.88 94.94 173.12 121.45 ;
 RECT 0 63.9 175 66.36 ;
 RECT 1.52 59.42 173.48 63.9 ;
 RECT 0 92.84 175 94.94 ;
 RECT 0 121.45 175 128.86 ;
 RECT 0 130.24 175 137.06 ;
 RECT 1.52 128.86 173.48 130.24 ;
 RECT 0 151.07 175 157.73 ;
 RECT 1.2 137.06 173.8 151.07 ;
 RECT 1.52 157.73 173.48 160.22 ;
 RECT 165.1 160.22 173.48 160.61 ;
 RECT 165.1 160.61 175 162 ;
 LAYER M4 ;
 RECT 0 0 175 123.91 ;
 RECT 0 129.39 175 130.58 ;
 RECT 2.24 123.91 172.76 129.39 ;
 RECT 2.6 135.39 172.4 147.06 ;
 RECT 0 134.56 175 135.39 ;
 RECT 2.24 130.58 172.76 134.56 ;
 RECT 0 147.06 175 147.89 ;
 RECT 0 152.37 175 153.56 ;
 RECT 2.24 147.89 172.76 152.37 ;
 RECT 0 156.54 175 157.73 ;
 RECT 2.24 153.56 172.76 156.54 ;
 RECT 0 160.71 175 162 ;
 RECT 2.24 157.73 172.76 160.71 ;
 LAYER M5 ;
 RECT 2.045 123.69 172.955 129.61 ;
 RECT 2.185 135.39 172.815 147.06 ;
 RECT 0 134.78 175 135.39 ;
 RECT 2.045 130.36 172.955 134.78 ;
 RECT 0 147.06 175 147.67 ;
 RECT 0 152.59 175 153.34 ;
 RECT 2.045 147.67 172.955 152.59 ;
 RECT 0 156.76 175 157.51 ;
 RECT 2.045 153.34 172.955 156.76 ;
 RECT 0 160.93 175 162 ;
 RECT 2.045 157.51 172.955 160.93 ;
 RECT 0 0 175 9.9 ;
 RECT 0 111.1 175 123.69 ;
 RECT 0 9.9 3.9 111.1 ;
 RECT 71.1 9.9 103.9 111.1 ;
 RECT 171.1 9.9 175 111.1 ;
 RECT 0 129.61 175 130.36 ;
 END
END RCMCU_PLVDDI

MACRO RCMCU_PLVPP
 CLASS PAD ;
 FOREIGN RCMCU_PLVPP ;
 ORIGIN 0 0 ;
 SIZE 75 BY 162 ;
 SYMMETRY X Y R90 ;
 PIN POC
 USE POWER ;
 DIRECTION INOUT ;
 PORT
 LAYER M3 ;
 RECT 73.72 129.1 75 130 ;
 END
 PORT
 LAYER M3 ;
 RECT 0 129.1 1.28 130 ;
 END
 END POC
 PIN TM0
 USE SIGNAL ;
 DIRECTION INOUT ;
 PORT
 LAYER M3 ;
 RECT 67.405 160.82 68.105 162 ;
 END
 PORT
 LAYER M2 ;
 RECT 67.405 160.82 68.105 162 ;
 END
 PORT
 LAYER MV2 ;
 RECT 67.455 160.87 67.645 161.06 ;
 RECT 67.865 160.87 68.055 161.06 ;
 RECT 67.455 161.28 67.645 161.47 ;
 RECT 67.865 161.28 68.055 161.47 ;
 END
 END TM0
 PIN VPP
 USE SIGNAL ;
 DIRECTION INOUT ;
 PORT
 LAYER M5 ;
 RECT 4.5 10.5 70.5 110.5 ;
 END
 PORT
 LAYER M3 ;
 RECT 23.435 160.82 52.905 162 ;
 END
 PORT
 LAYER M2 ;
 RECT 23.435 160.82 52.905 162 ;
 END
 PORT
 LAYER MV2 ;
 RECT 23.71 160.88 23.9 161.07 ;
 RECT 24.12 160.88 24.31 161.07 ;
 RECT 24.53 160.88 24.72 161.07 ;
 RECT 24.94 160.88 25.13 161.07 ;
 RECT 25.35 160.88 25.54 161.07 ;
 RECT 25.76 160.88 25.95 161.07 ;
 RECT 26.17 160.88 26.36 161.07 ;
 RECT 26.58 160.88 26.77 161.07 ;
 RECT 26.99 160.88 27.18 161.07 ;
 RECT 28.22 160.88 28.41 161.07 ;
 RECT 28.63 160.88 28.82 161.07 ;
 RECT 29.04 160.88 29.23 161.07 ;
 RECT 29.45 160.88 29.64 161.07 ;
 RECT 29.86 160.88 30.05 161.07 ;
 RECT 30.27 160.88 30.46 161.07 ;
 RECT 30.68 160.88 30.87 161.07 ;
 RECT 27.4 160.88 27.59 161.07 ;
 RECT 27.81 160.88 28 161.07 ;
 RECT 33.96 160.88 34.15 161.07 ;
 RECT 33.55 160.88 33.74 161.07 ;
 RECT 33.14 160.88 33.33 161.07 ;
 RECT 32.73 160.88 32.92 161.07 ;
 RECT 31.09 160.88 31.28 161.07 ;
 RECT 31.91 160.88 32.1 161.07 ;
 RECT 32.32 160.88 32.51 161.07 ;
 RECT 31.5 160.88 31.69 161.07 ;
 RECT 37.65 160.88 37.84 161.07 ;
 RECT 37.24 160.88 37.43 161.07 ;
 RECT 36.83 160.88 37.02 161.07 ;
 RECT 36.42 160.88 36.61 161.07 ;
 RECT 36.01 160.88 36.2 161.07 ;
 RECT 35.6 160.88 35.79 161.07 ;
 RECT 35.19 160.88 35.38 161.07 ;
 RECT 34.78 160.88 34.97 161.07 ;
 RECT 34.37 160.88 34.56 161.07 ;
 RECT 38.47 160.88 38.66 161.07 ;
 RECT 38.88 160.88 39.07 161.07 ;
 RECT 39.29 160.88 39.48 161.07 ;
 RECT 39.7 160.88 39.89 161.07 ;
 RECT 40.11 160.88 40.3 161.07 ;
 RECT 40.52 160.88 40.71 161.07 ;
 RECT 40.93 160.88 41.12 161.07 ;
 RECT 41.34 160.88 41.53 161.07 ;
 RECT 42.57 160.88 42.76 161.07 ;
 RECT 42.98 160.88 43.17 161.07 ;
 RECT 43.39 160.88 43.58 161.07 ;
 RECT 43.8 160.88 43.99 161.07 ;
 RECT 44.21 160.88 44.4 161.07 ;
 RECT 44.62 160.88 44.81 161.07 ;
 RECT 45.03 160.88 45.22 161.07 ;
 RECT 42.16 160.88 42.35 161.07 ;
 RECT 41.75 160.88 41.94 161.07 ;
 RECT 47.08 160.88 47.27 161.07 ;
 RECT 48.72 160.88 48.91 161.07 ;
 RECT 48.31 160.88 48.5 161.07 ;
 RECT 47.9 160.88 48.09 161.07 ;
 RECT 47.49 160.88 47.68 161.07 ;
 RECT 45.44 160.88 45.63 161.07 ;
 RECT 45.85 160.88 46.04 161.07 ;
 RECT 46.26 160.88 46.45 161.07 ;
 RECT 46.67 160.88 46.86 161.07 ;
 RECT 52.41 160.88 52.6 161.07 ;
 RECT 52 160.88 52.19 161.07 ;
 RECT 51.59 160.88 51.78 161.07 ;
 RECT 51.18 160.88 51.37 161.07 ;
 RECT 50.77 160.88 50.96 161.07 ;
 RECT 50.36 160.88 50.55 161.07 ;
 RECT 49.95 160.88 50.14 161.07 ;
 RECT 49.54 160.88 49.73 161.07 ;
 RECT 49.13 160.88 49.32 161.07 ;
 RECT 38.06 160.88 38.25 161.07 ;
 END
 END VPP
 PIN gnd
 USE GROUND ;
 DIRECTION INOUT ;
 PORT
 LAYER M5 ;
 RECT 73.415 135.99 75 146.46 ;
 END
 PORT
 LAYER M5 ;
 RECT 0 135.99 1.585 146.46 ;
 END
 PORT
 LAYER M5 ;
 RECT 0 157.97 1.585 160.47 ;
 END
 PORT
 LAYER M5 ;
 RECT 73.415 157.97 75 160.47 ;
 END
 PORT
 LAYER M4 ;
 RECT 73 135.99 75 146.46 ;
 END
 PORT
 LAYER M4 ;
 RECT 0 135.99 2 146.46 ;
 END
 PORT
 LAYER M4 ;
 RECT 0 157.97 2 160.47 ;
 END
 PORT
 LAYER M4 ;
 RECT 73 157.97 75 160.47 ;
 END
 PORT
 LAYER M3 ;
 RECT 73.72 59.66 75 63.66 ;
 END
 PORT
 LAYER M3 ;
 RECT 0 59.66 1.28 63.66 ;
 END
 END gnd
 PIN vdd
 USE POWER ;
 DIRECTION INOUT ;
 PORT
 LAYER M5 ;
 RECT 73.415 153.8 75 156.3 ;
 END
 PORT
 LAYER M5 ;
 RECT 0 153.8 1.585 156.3 ;
 END
 PORT
 LAYER M4 ;
 RECT 73 153.8 75 156.3 ;
 END
 PORT
 LAYER M4 ;
 RECT 0 153.8 2 156.3 ;
 END
 END vdd
 PIN vddh
 USE POWER ;
 DIRECTION INOUT ;
 PORT
 LAYER M5 ;
 RECT 73.415 130.82 75 134.32 ;
 END
 PORT
 LAYER M5 ;
 RECT 0 130.82 1.585 134.32 ;
 END
 PORT
 LAYER M4 ;
 RECT 73 130.82 75 134.32 ;
 END
 PORT
 LAYER M4 ;
 RECT 0 130.82 2 134.32 ;
 END
 PORT
 LAYER M3 ;
 RECT 73.72 53.99 75 57.99 ;
 END
 PORT
 LAYER M3 ;
 RECT 0 53.99 1.28 57.99 ;
 END
 PORT
 LAYER M3 ;
 RECT 0 66.995 1.28 92.275 ;
 END
 PORT
 LAYER M3 ;
 RECT 73.72 66.995 75 92.275 ;
 END
 PORT
 LAYER M3 ;
 RECT 0 95.575 1.28 120.885 ;
 END
 PORT
 LAYER M3 ;
 RECT 73.72 95.575 75 120.885 ;
 END
 END vddh
 PIN vssh
 USE GROUND ;
 DIRECTION INOUT ;
 PORT
 LAYER M5 ;
 RECT 73.415 124.15 75 129.15 ;
 END
 PORT
 LAYER M5 ;
 RECT 0 124.15 1.585 129.15 ;
 END
 PORT
 LAYER M5 ;
 RECT 0 148.13 1.585 152.13 ;
 END
 PORT
 LAYER M5 ;
 RECT 73.415 148.13 75 152.125 ;
 END
 PORT
 LAYER M4 ;
 RECT 73 124.15 75 129.15 ;
 END
 PORT
 LAYER M4 ;
 RECT 0 124.15 2 129.15 ;
 END
 PORT
 LAYER M4 ;
 RECT 0 148.13 2 152.13 ;
 END
 PORT
 LAYER M4 ;
 RECT 73 148.13 75 152.13 ;
 END
 PORT
 LAYER M3 ;
 RECT 73.72 9.945 75 28.685 ;
 END
 PORT
 LAYER M3 ;
 RECT 0 9.945 1.28 28.685 ;
 END
 PORT
 LAYER M3 ;
 RECT 0 31.985 1.28 50.725 ;
 END
 PORT
 LAYER M3 ;
 RECT 73.72 31.985 75 50.725 ;
 END
 END vssh
 OBS
 LAYER GATE ;
 RECT 0 0 75 162 ;
 LAYER MV1 ;
 RECT 0 0 75 162 ;
 LAYER MV2 ;
 RECT 0 0 75 162 ;
 LAYER MV3 ;
 RECT 0 0 75 162 ;
 LAYER MV4 ;
 RECT 0 0 75 162 ;
 LAYER M1 ;
 RECT 0 0 75 162 ;
 LAYER M2 ;
 RECT 53.505 160.22 75 160.58 ;
 RECT 0 0 75 160.22 ;
 RECT 68.345 160.58 75 162 ;
 RECT 0 160.22 22.835 162 ;
 RECT 53.505 160.58 67.165 162 ;
 LAYER M3 ;
 RECT 0 0 75 9.345 ;
 RECT 0 29.285 75 31.385 ;
 RECT 1.88 9.345 73.12 29.285 ;
 RECT 0 160.22 22.835 162 ;
 RECT 53.505 160.58 67.165 162 ;
 RECT 0 51.325 75 53.75 ;
 RECT 1.88 31.385 73.12 51.325 ;
 RECT 0 58.23 75 59.42 ;
 RECT 1.52 53.75 73.48 58.23 ;
 RECT 1.88 66.395 73.12 92.875 ;
 RECT 1.88 94.975 73.12 121.485 ;
 RECT 0 63.9 75 66.395 ;
 RECT 1.52 59.42 73.48 63.9 ;
 RECT 0 92.875 75 94.975 ;
 RECT 0 121.485 75 128.86 ;
 RECT 0 130.24 75 160.22 ;
 RECT 1.52 128.86 73.48 130.24 ;
 RECT 53.505 160.22 75 160.58 ;
 RECT 68.345 160.58 75 162 ;
 LAYER M4 ;
 RECT 0 0 75 123.91 ;
 RECT 0 129.39 75 130.58 ;
 RECT 2.24 123.91 72.76 129.39 ;
 RECT 2.6 135.39 72.4 147.06 ;
 RECT 0 134.56 75 135.39 ;
 RECT 2.24 130.58 72.76 134.56 ;
 RECT 0 147.06 75 147.89 ;
 RECT 0 152.37 75 153.56 ;
 RECT 2.24 147.89 72.76 152.37 ;
 RECT 0 156.54 75 157.73 ;
 RECT 2.24 153.56 72.76 156.54 ;
 RECT 0 160.71 75 162 ;
 RECT 2.24 157.73 72.76 160.71 ;
 LAYER M5 ;
 RECT 0 9.9 3.9 111.1 ;
 RECT 71.1 9.9 75 111.1 ;
 RECT 0 0 75 9.9 ;
 RECT 0 111.1 75 123.69 ;
 RECT 0 129.61 75 130.36 ;
 RECT 2.045 123.69 72.955 129.61 ;
 RECT 2.185 135.39 72.815 147.06 ;
 RECT 0 134.78 75 135.39 ;
 RECT 2.045 130.36 72.955 134.78 ;
 RECT 0 147.06 75 147.67 ;
 RECT 2.045 147.67 72.955 152.585 ;
 RECT 2.045 152.585 75 152.59 ;
 RECT 0 152.59 75 153.34 ;
 RECT 0 156.76 75 157.51 ;
 RECT 2.045 153.34 72.955 156.76 ;
 RECT 0 160.93 75 162 ;
 RECT 2.045 157.51 72.955 160.93 ;
 END
END RCMCU_PLVPP

MACRO RCMCU_PLVSS
 CLASS PAD ;
 FOREIGN RCMCU_PLVSS ;
 ORIGIN 0 0 ;
 SIZE 75 BY 162 ;
 SYMMETRY X Y R90 ;
 PIN POC
 USE POWER ;
 DIRECTION INOUT ;
 PORT
 LAYER M3 ;
 RECT 73.72 129.1 75 130 ;
 END
 PORT
 LAYER M3 ;
 RECT 0 129.1 1.28 130 ;
 END
 END POC
 PIN gnd
 USE GROUND ;
 DIRECTION INOUT ;
 PORT
 LAYER M5 ;
 RECT 4.5 10.5 70.5 110.5 ;
 END
 PORT
 LAYER M5 ;
 RECT 0 135.99 1.585 146.46 ;
 END
 PORT
 LAYER M5 ;
 RECT 73.415 135.99 75 146.46 ;
 END
 PORT
 LAYER M5 ;
 RECT 0 157.97 1.585 160.47 ;
 END
 PORT
 LAYER M5 ;
 RECT 73.415 157.97 75 160.47 ;
 END
 PORT
 LAYER M4 ;
 RECT 73 135.99 75 146.46 ;
 END
 PORT
 LAYER M4 ;
 RECT 0 135.99 2 146.46 ;
 END
 PORT
 LAYER M4 ;
 RECT 0 157.97 1.585 160.47 ;
 END
 PORT
 LAYER M4 ;
 RECT 73.415 157.97 75 160.47 ;
 END
 PORT
 LAYER M3 ;
 RECT 73.72 59.66 75 63.66 ;
 END
 PORT
 LAYER M3 ;
 RECT 0 59.66 1.28 63.66 ;
 END
 PORT
 LAYER M3 ;
 RECT 0 157.97 1.585 160.37 ;
 END
 PORT
 LAYER M3 ;
 RECT 73.415 157.97 75 160.37 ;
 END
 PORT
 LAYER M3 ;
 RECT 10.5 160.82 64.5 162 ;
 END
 PORT
 LAYER M2 ;
 RECT 10.5 160.82 64.5 162 ;
 END
 PORT
 LAYER MV2 ;
 RECT 35.835 160.995 36.025 161.185 ;
 RECT 36.355 160.995 36.545 161.185 ;
 RECT 36.875 160.995 37.065 161.185 ;
 RECT 34.275 160.995 34.465 161.185 ;
 RECT 34.795 160.995 34.985 161.185 ;
 RECT 35.315 161.515 35.505 161.705 ;
 RECT 35.835 161.515 36.025 161.705 ;
 RECT 36.875 161.515 37.065 161.705 ;
 RECT 36.355 161.515 36.545 161.705 ;
 RECT 34.275 161.515 34.465 161.705 ;
 RECT 34.795 161.515 34.985 161.705 ;
 RECT 40.515 160.995 40.705 161.185 ;
 RECT 39.995 160.995 40.185 161.185 ;
 RECT 39.475 160.995 39.665 161.185 ;
 RECT 38.955 160.995 39.145 161.185 ;
 RECT 38.435 160.995 38.625 161.185 ;
 RECT 37.915 160.995 38.105 161.185 ;
 RECT 39.995 161.515 40.185 161.705 ;
 RECT 40.515 161.515 40.705 161.705 ;
 RECT 37.915 161.515 38.105 161.705 ;
 RECT 38.435 161.515 38.625 161.705 ;
 RECT 38.955 161.515 39.145 161.705 ;
 RECT 39.475 161.515 39.665 161.705 ;
 RECT 42.075 160.995 42.265 161.185 ;
 RECT 42.595 160.995 42.785 161.185 ;
 RECT 43.115 160.995 43.305 161.185 ;
 RECT 43.635 160.995 43.825 161.185 ;
 RECT 41.035 160.995 41.225 161.185 ;
 RECT 41.555 160.995 41.745 161.185 ;
 RECT 42.075 161.515 42.265 161.705 ;
 RECT 42.595 161.515 42.785 161.705 ;
 RECT 43.115 161.515 43.305 161.705 ;
 RECT 43.635 161.515 43.825 161.705 ;
 RECT 41.555 161.515 41.745 161.705 ;
 RECT 41.035 161.515 41.225 161.705 ;
 RECT 47.275 160.995 47.465 161.185 ;
 RECT 46.755 160.995 46.945 161.185 ;
 RECT 44.675 160.995 44.865 161.185 ;
 RECT 45.195 160.995 45.385 161.185 ;
 RECT 45.715 160.995 45.905 161.185 ;
 RECT 46.235 160.995 46.425 161.185 ;
 RECT 44.155 160.995 44.345 161.185 ;
 RECT 46.755 161.515 46.945 161.705 ;
 RECT 47.275 161.515 47.465 161.705 ;
 RECT 44.675 161.515 44.865 161.705 ;
 RECT 45.195 161.515 45.385 161.705 ;
 RECT 46.235 161.515 46.425 161.705 ;
 RECT 45.715 161.515 45.905 161.705 ;
 RECT 44.155 161.515 44.345 161.705 ;
 RECT 49.355 160.995 49.545 161.185 ;
 RECT 50.395 160.995 50.585 161.185 ;
 RECT 49.875 160.995 50.065 161.185 ;
 RECT 48.835 160.995 49.025 161.185 ;
 RECT 48.315 160.995 48.505 161.185 ;
 RECT 47.795 160.995 47.985 161.185 ;
 RECT 50.395 161.515 50.585 161.705 ;
 RECT 49.875 161.515 50.065 161.705 ;
 RECT 49.355 161.515 49.545 161.705 ;
 RECT 47.795 161.515 47.985 161.705 ;
 RECT 48.315 161.515 48.505 161.705 ;
 RECT 48.835 161.515 49.025 161.705 ;
 RECT 53.515 160.995 53.705 161.185 ;
 RECT 52.995 160.995 53.185 161.185 ;
 RECT 52.475 160.995 52.665 161.185 ;
 RECT 51.955 160.995 52.145 161.185 ;
 RECT 51.435 160.995 51.625 161.185 ;
 RECT 50.915 160.995 51.105 161.185 ;
 RECT 51.435 161.515 51.625 161.705 ;
 RECT 51.955 161.515 52.145 161.705 ;
 RECT 52.475 161.515 52.665 161.705 ;
 RECT 52.995 161.515 53.185 161.705 ;
 RECT 53.515 161.515 53.705 161.705 ;
 RECT 50.915 161.515 51.105 161.705 ;
 RECT 56.635 160.995 56.825 161.185 ;
 RECT 57.155 160.995 57.345 161.185 ;
 RECT 56.115 160.995 56.305 161.185 ;
 RECT 55.595 160.995 55.785 161.185 ;
 RECT 55.075 160.995 55.265 161.185 ;
 RECT 54.555 160.995 54.745 161.185 ;
 RECT 56.115 161.515 56.305 161.705 ;
 RECT 56.635 161.515 56.825 161.705 ;
 RECT 57.155 161.515 57.345 161.705 ;
 RECT 54.555 161.515 54.745 161.705 ;
 RECT 55.595 161.515 55.785 161.705 ;
 RECT 55.075 161.515 55.265 161.705 ;
 RECT 54.035 160.995 54.225 161.185 ;
 RECT 54.035 161.515 54.225 161.705 ;
 RECT 58.715 160.995 58.905 161.185 ;
 RECT 59.235 160.995 59.425 161.185 ;
 RECT 59.755 160.995 59.945 161.185 ;
 RECT 60.275 160.995 60.465 161.185 ;
 RECT 57.675 160.995 57.865 161.185 ;
 RECT 58.195 160.995 58.385 161.185 ;
 RECT 58.715 161.515 58.905 161.705 ;
 RECT 59.235 161.515 59.425 161.705 ;
 RECT 60.275 161.515 60.465 161.705 ;
 RECT 59.755 161.515 59.945 161.705 ;
 RECT 57.675 161.515 57.865 161.705 ;
 RECT 58.195 161.515 58.385 161.705 ;
 RECT 63.395 160.995 63.585 161.185 ;
 RECT 63.915 160.995 64.105 161.185 ;
 RECT 60.795 160.995 60.985 161.185 ;
 RECT 61.315 160.995 61.505 161.185 ;
 RECT 61.835 160.995 62.025 161.185 ;
 RECT 62.355 160.995 62.545 161.185 ;
 RECT 62.875 160.995 63.065 161.185 ;
 RECT 63.915 161.515 64.105 161.705 ;
 RECT 63.395 161.515 63.585 161.705 ;
 RECT 60.795 161.515 60.985 161.705 ;
 RECT 62.875 161.515 63.065 161.705 ;
 RECT 62.355 161.515 62.545 161.705 ;
 RECT 61.835 161.515 62.025 161.705 ;
 RECT 61.315 161.515 61.505 161.705 ;
 RECT 37.395 160.995 37.585 161.185 ;
 RECT 37.395 161.515 37.585 161.705 ;
 RECT 13.995 160.995 14.185 161.185 ;
 RECT 11.915 160.995 12.105 161.185 ;
 RECT 13.475 160.995 13.665 161.185 ;
 RECT 12.955 160.995 13.145 161.185 ;
 RECT 12.435 160.995 12.625 161.185 ;
 RECT 11.395 160.995 11.585 161.185 ;
 RECT 10.875 160.995 11.065 161.185 ;
 RECT 13.995 161.515 14.185 161.705 ;
 RECT 12.435 161.515 12.625 161.705 ;
 RECT 11.915 161.515 12.105 161.705 ;
 RECT 13.475 161.515 13.665 161.705 ;
 RECT 12.955 161.515 13.145 161.705 ;
 RECT 11.395 161.515 11.585 161.705 ;
 RECT 10.875 161.515 11.065 161.705 ;
 RECT 17.115 160.995 17.305 161.185 ;
 RECT 16.595 160.995 16.785 161.185 ;
 RECT 16.075 160.995 16.265 161.185 ;
 RECT 15.555 160.995 15.745 161.185 ;
 RECT 15.035 160.995 15.225 161.185 ;
 RECT 14.515 160.995 14.705 161.185 ;
 RECT 16.595 161.515 16.785 161.705 ;
 RECT 17.115 161.515 17.305 161.705 ;
 RECT 14.515 161.515 14.705 161.705 ;
 RECT 15.035 161.515 15.225 161.705 ;
 RECT 15.555 161.515 15.745 161.705 ;
 RECT 16.075 161.515 16.265 161.705 ;
 RECT 19.715 160.995 19.905 161.185 ;
 RECT 20.235 160.995 20.425 161.185 ;
 RECT 19.195 160.995 19.385 161.185 ;
 RECT 18.675 160.995 18.865 161.185 ;
 RECT 18.155 160.995 18.345 161.185 ;
 RECT 17.635 160.995 17.825 161.185 ;
 RECT 18.675 161.515 18.865 161.705 ;
 RECT 19.195 161.515 19.385 161.705 ;
 RECT 19.715 161.515 19.905 161.705 ;
 RECT 20.235 161.515 20.425 161.705 ;
 RECT 18.155 161.515 18.345 161.705 ;
 RECT 17.635 161.515 17.825 161.705 ;
 RECT 23.875 160.995 24.065 161.185 ;
 RECT 23.355 160.995 23.545 161.185 ;
 RECT 22.835 160.995 23.025 161.185 ;
 RECT 22.315 160.995 22.505 161.185 ;
 RECT 21.795 160.995 21.985 161.185 ;
 RECT 21.275 160.995 21.465 161.185 ;
 RECT 23.355 161.515 23.545 161.705 ;
 RECT 23.875 161.515 24.065 161.705 ;
 RECT 21.275 161.515 21.465 161.705 ;
 RECT 21.795 161.515 21.985 161.705 ;
 RECT 22.835 161.515 23.025 161.705 ;
 RECT 22.315 161.515 22.505 161.705 ;
 RECT 20.755 160.995 20.945 161.185 ;
 RECT 20.755 161.515 20.945 161.705 ;
 RECT 26.995 160.995 27.185 161.185 ;
 RECT 26.475 160.995 26.665 161.185 ;
 RECT 25.955 160.995 26.145 161.185 ;
 RECT 25.435 160.995 25.625 161.185 ;
 RECT 24.915 160.995 25.105 161.185 ;
 RECT 24.395 160.995 24.585 161.185 ;
 RECT 25.955 161.515 26.145 161.705 ;
 RECT 26.475 161.515 26.665 161.705 ;
 RECT 26.995 161.515 27.185 161.705 ;
 RECT 24.395 161.515 24.585 161.705 ;
 RECT 24.915 161.515 25.105 161.705 ;
 RECT 25.435 161.515 25.625 161.705 ;
 RECT 30.635 160.995 30.825 161.185 ;
 RECT 30.115 160.995 30.305 161.185 ;
 RECT 29.595 160.995 29.785 161.185 ;
 RECT 29.075 160.995 29.265 161.185 ;
 RECT 28.555 160.995 28.745 161.185 ;
 RECT 28.035 160.995 28.225 161.185 ;
 RECT 27.515 160.995 27.705 161.185 ;
 RECT 30.635 161.515 30.825 161.705 ;
 RECT 28.035 161.515 28.225 161.705 ;
 RECT 28.555 161.515 28.745 161.705 ;
 RECT 29.075 161.515 29.265 161.705 ;
 RECT 29.595 161.515 29.785 161.705 ;
 RECT 30.115 161.515 30.305 161.705 ;
 RECT 27.515 161.515 27.705 161.705 ;
 RECT 32.715 160.995 32.905 161.185 ;
 RECT 33.235 160.995 33.425 161.185 ;
 RECT 33.755 160.995 33.945 161.185 ;
 RECT 31.155 160.995 31.345 161.185 ;
 RECT 31.675 160.995 31.865 161.185 ;
 RECT 32.195 160.995 32.385 161.185 ;
 RECT 32.715 161.515 32.905 161.705 ;
 RECT 33.235 161.515 33.425 161.705 ;
 RECT 33.755 161.515 33.945 161.705 ;
 RECT 31.155 161.515 31.345 161.705 ;
 RECT 32.195 161.515 32.385 161.705 ;
 RECT 31.675 161.515 31.865 161.705 ;
 RECT 35.315 160.995 35.505 161.185 ;
 LAYER MV3 ;
 RECT 73.6 158.44 73.79 158.63 ;
 RECT 74.21 158.44 74.4 158.63 ;
 RECT 73.6 159.05 73.79 159.24 ;
 RECT 74.21 159.05 74.4 159.24 ;
 RECT 73.6 159.66 73.79 159.85 ;
 RECT 74.21 159.66 74.4 159.85 ;
 RECT 0.6 158.44 0.79 158.63 ;
 RECT 1.21 158.44 1.4 158.63 ;
 RECT 0.6 159.05 0.79 159.24 ;
 RECT 1.21 159.05 1.4 159.24 ;
 RECT 0.6 159.66 0.79 159.85 ;
 RECT 1.21 159.66 1.4 159.85 ;
 END
 END gnd
 PIN vdd
 USE POWER ;
 DIRECTION INOUT ;
 PORT
 LAYER M5 ;
 RECT 73.415 153.8 75 156.3 ;
 END
 PORT
 LAYER M5 ;
 RECT 0 153.8 1.585 156.3 ;
 END
 PORT
 LAYER M4 ;
 RECT 73 153.8 75 156.3 ;
 END
 PORT
 LAYER M4 ;
 RECT 0 153.8 2 156.3 ;
 END
 END vdd
 PIN vddh
 USE POWER ;
 DIRECTION INOUT ;
 PORT
 LAYER M5 ;
 RECT 73.415 130.82 75 134.32 ;
 END
 PORT
 LAYER M5 ;
 RECT 0 130.82 1.585 134.32 ;
 END
 PORT
 LAYER M4 ;
 RECT 73 130.82 75 134.32 ;
 END
 PORT
 LAYER M4 ;
 RECT 0 130.82 2 134.32 ;
 END
 PORT
 LAYER M3 ;
 RECT 73.72 53.99 75 57.99 ;
 END
 PORT
 LAYER M3 ;
 RECT 0 53.99 1.28 57.99 ;
 END
 PORT
 LAYER M3 ;
 RECT 73.72 66.96 75 92.24 ;
 END
 PORT
 LAYER M3 ;
 RECT 0 66.96 1.28 92.24 ;
 END
 PORT
 LAYER M3 ;
 RECT 0 95.54 1.28 120.85 ;
 END
 PORT
 LAYER M3 ;
 RECT 73.72 95.54 75 120.85 ;
 END
 PORT
 LAYER M3 ;
 RECT 0 137.66 0.6 150.47 ;
 END
 PORT
 LAYER M3 ;
 RECT 74.4 137.66 75 150.47 ;
 END
 END vddh
 PIN vssh
 USE GROUND ;
 DIRECTION INOUT ;
 PORT
 LAYER M5 ;
 RECT 73.415 124.15 75 129.15 ;
 END
 PORT
 LAYER M5 ;
 RECT 0 124.15 1.585 129.15 ;
 END
 PORT
 LAYER M5 ;
 RECT 0 148.13 1.585 152.13 ;
 END
 PORT
 LAYER M5 ;
 RECT 73.415 148.13 75 152.13 ;
 END
 PORT
 LAYER M4 ;
 RECT 73 124.15 75 129.15 ;
 END
 PORT
 LAYER M4 ;
 RECT 0 124.15 2 129.15 ;
 END
 PORT
 LAYER M4 ;
 RECT 0 148.13 2 152.13 ;
 END
 PORT
 LAYER M4 ;
 RECT 73 148.13 75 152.13 ;
 END
 PORT
 LAYER M3 ;
 RECT 73.72 9.91 75 28.65 ;
 END
 PORT
 LAYER M3 ;
 RECT 0 9.91 1.28 28.65 ;
 END
 PORT
 LAYER M3 ;
 RECT 0 31.95 1.28 50.69 ;
 END
 PORT
 LAYER M3 ;
 RECT 73.72 31.95 75 50.69 ;
 END
 END vssh
 OBS
 LAYER GATE ;
 RECT 0 0 75 162 ;
 LAYER MV1 ;
 RECT 0 0 75 162 ;
 LAYER MV2 ;
 RECT 0 0 75 162 ;
 LAYER MV3 ;
 RECT 0 0 75 162 ;
 LAYER MV4 ;
 RECT 0 0 75 162 ;
 LAYER M1 ;
 RECT 0 0 75 162 ;
 LAYER M2 ;
 RECT 65.1 160.22 75 162 ;
 RECT 0 160.22 9.9 162 ;
 RECT 0 0 75 160.22 ;
 LAYER M3 ;
 RECT 0 92.84 75 94.94 ;
 RECT 0 121.45 75 128.86 ;
 RECT 0 130.24 75 137.06 ;
 RECT 1.52 128.86 73.48 130.24 ;
 RECT 0 151.07 75 157.73 ;
 RECT 1.2 137.06 73.8 151.07 ;
 RECT 65.1 160.61 75 162 ;
 RECT 0 0 75 9.31 ;
 RECT 0 29.25 75 31.35 ;
 RECT 1.88 9.31 73.12 29.25 ;
 RECT 1.825 160.22 9.9 160.61 ;
 RECT 0 160.61 9.9 162 ;
 RECT 0 51.29 75 53.75 ;
 RECT 1.88 31.35 73.12 51.29 ;
 RECT 0 58.23 75 59.42 ;
 RECT 1.52 53.75 73.48 58.23 ;
 RECT 1.88 66.36 73.12 92.84 ;
 RECT 1.88 94.94 73.12 121.45 ;
 RECT 1.825 157.73 73.175 160.22 ;
 RECT 65.1 160.22 73.175 160.61 ;
 RECT 0 63.9 75 66.36 ;
 RECT 1.52 59.42 73.48 63.9 ;
 LAYER M4 ;
 RECT 0 0 75 123.91 ;
 RECT 0 129.39 75 130.58 ;
 RECT 2.24 123.91 72.76 129.39 ;
 RECT 2.6 135.39 72.4 147.06 ;
 RECT 0 134.56 75 135.39 ;
 RECT 2.24 130.58 72.76 134.56 ;
 RECT 0 147.06 75 147.89 ;
 RECT 0 152.37 75 153.56 ;
 RECT 2.24 147.89 72.76 152.37 ;
 RECT 0 156.54 75 157.73 ;
 RECT 2.24 153.56 72.76 156.54 ;
 RECT 0 160.71 75 162 ;
 RECT 1.825 157.73 73.175 160.71 ;
 LAYER M5 ;
 RECT 0 9.9 3.9 111.1 ;
 RECT 71.1 9.9 75 111.1 ;
 RECT 0 0 75 9.9 ;
 RECT 0 111.1 75 123.69 ;
 RECT 0 129.61 75 130.36 ;
 RECT 2.045 123.69 72.955 129.61 ;
 RECT 2.185 135.39 72.815 147.06 ;
 RECT 0 134.78 75 135.39 ;
 RECT 2.045 130.36 72.955 134.78 ;
 RECT 0 147.06 75 147.67 ;
 RECT 0 152.59 75 153.34 ;
 RECT 2.045 147.67 72.955 152.59 ;
 RECT 0 156.76 75 157.51 ;
 RECT 2.045 153.34 72.955 156.76 ;
 RECT 0 160.93 75 162 ;
 RECT 2.045 157.51 72.955 160.93 ;
 END
END RCMCU_PLVSS

MACRO RCMCU_PLVSSA
 CLASS PAD ;
 FOREIGN RCMCU_PLVSSA ;
 ORIGIN 0 0 ;
 SIZE 75 BY 162 ;
 SYMMETRY X Y R90 ;
 PIN POC
 USE POWER ;
 DIRECTION INOUT ;
 PORT
 LAYER M3 ;
 RECT 73.72 129.1 75 130 ;
 END
 PORT
 LAYER M3 ;
 RECT 0 129.1 1.28 130 ;
 END
 END POC
 PIN gnd
 USE GROUND ;
 DIRECTION INOUT ;
 PORT
 LAYER M5 ;
 RECT 73.415 135.99 75 146.46 ;
 END
 PORT
 LAYER M5 ;
 RECT 0 135.99 1.585 146.46 ;
 END
 PORT
 LAYER M5 ;
 RECT 0 157.97 1.585 160.47 ;
 END
 PORT
 LAYER M5 ;
 RECT 73.415 157.97 75 160.47 ;
 END
 PORT
 LAYER M4 ;
 RECT 73 135.99 75 146.46 ;
 END
 PORT
 LAYER M4 ;
 RECT 0 135.99 2 146.46 ;
 END
 PORT
 LAYER M4 ;
 RECT 0 157.97 2 160.47 ;
 END
 PORT
 LAYER M4 ;
 RECT 73 157.97 75 160.47 ;
 END
 PORT
 LAYER M3 ;
 RECT 73.72 59.66 75 63.66 ;
 END
 PORT
 LAYER M3 ;
 RECT 0 59.66 1.28 63.66 ;
 END
 PORT
 LAYER M3 ;
 RECT 0 157.97 1.28 160.37 ;
 END
 PORT
 LAYER M3 ;
 RECT 73.72 157.97 75 160.37 ;
 END
 PORT
 LAYER MV3 ;
 RECT 74.175 158.525 74.365 158.715 ;
 RECT 74.175 159.325 74.365 159.515 ;
 RECT 0.635 158.525 0.825 158.715 ;
 RECT 0.635 159.325 0.825 159.515 ;
 END
 END gnd
 PIN vdd
 USE POWER ;
 DIRECTION INOUT ;
 PORT
 LAYER M5 ;
 RECT 73.415 153.8 75 156.3 ;
 END
 PORT
 LAYER M5 ;
 RECT 0 153.8 1.585 156.3 ;
 END
 PORT
 LAYER M4 ;
 RECT 73 153.8 75 156.3 ;
 END
 PORT
 LAYER M4 ;
 RECT 0 153.8 2 156.3 ;
 END
 END vdd
 PIN vdda
 USE POWER ;
 DIRECTION INOUT ;
 PORT
 LAYER M5 ;
 RECT 73.415 130.82 75 134.32 ;
 END
 PORT
 LAYER M5 ;
 RECT 0 130.82 1.585 134.32 ;
 END
 PORT
 LAYER M4 ;
 RECT 73 130.82 75 134.32 ;
 END
 PORT
 LAYER M4 ;
 RECT 0 130.82 2 134.32 ;
 END
 PORT
 LAYER M3 ;
 RECT 73.72 53.99 75 57.99 ;
 END
 PORT
 LAYER M3 ;
 RECT 0 53.99 1.28 57.99 ;
 END
 PORT
 LAYER M3 ;
 RECT 73.72 66.96 75 92.24 ;
 END
 PORT
 LAYER M3 ;
 RECT 0 66.96 1.28 92.24 ;
 END
 PORT
 LAYER M3 ;
 RECT 0 95.54 1.28 120.85 ;
 END
 PORT
 LAYER M3 ;
 RECT 73.72 95.54 75 120.85 ;
 END
 PORT
 LAYER M3 ;
 RECT 0 137.66 0.6 150.47 ;
 END
 PORT
 LAYER M3 ;
 RECT 74.4 137.66 75 150.47 ;
 END
 END vdda
 PIN vssa
 USE GROUND ;
 DIRECTION INOUT ;
 PORT
 LAYER M5 ;
 RECT 4.5 10.5 70.5 110.5 ;
 END
 PORT
 LAYER M5 ;
 RECT 0 124.15 1.585 129.15 ;
 END
 PORT
 LAYER M5 ;
 RECT 73.415 124.15 75 129.15 ;
 END
 PORT
 LAYER M5 ;
 RECT 0 148.13 1.585 152.13 ;
 END
 PORT
 LAYER M5 ;
 RECT 73.415 148.13 75 152.13 ;
 END
 PORT
 LAYER M4 ;
 RECT 73 124.15 75 129.15 ;
 END
 PORT
 LAYER M4 ;
 RECT 0 124.15 2 129.15 ;
 END
 PORT
 LAYER M4 ;
 RECT 0 148.13 2 152.13 ;
 END
 PORT
 LAYER M4 ;
 RECT 73 148.13 75 152.13 ;
 END
 PORT
 LAYER M3 ;
 RECT 73.72 9.91 75 28.65 ;
 END
 PORT
 LAYER M3 ;
 RECT 0 9.91 1.28 28.65 ;
 END
 PORT
 LAYER M3 ;
 RECT 0 31.95 1.28 50.69 ;
 END
 PORT
 LAYER M3 ;
 RECT 73.72 31.95 75 50.69 ;
 END
 PORT
 LAYER M3 ;
 RECT 10.5 160.82 64.5 162 ;
 END
 PORT
 LAYER M2 ;
 RECT 10.5 160.82 64.5 162 ;
 END
 PORT
 LAYER MV2 ;
 RECT 29.27 161.515 29.46 161.705 ;
 RECT 29.83 161.515 30.02 161.705 ;
 RECT 27.59 161.515 27.78 161.705 ;
 RECT 32.63 160.955 32.82 161.145 ;
 RECT 33.75 160.955 33.94 161.145 ;
 RECT 33.19 160.955 33.38 161.145 ;
 RECT 30.95 160.955 31.14 161.145 ;
 RECT 31.51 160.955 31.7 161.145 ;
 RECT 32.07 160.955 32.26 161.145 ;
 RECT 32.63 161.515 32.82 161.705 ;
 RECT 33.19 161.515 33.38 161.705 ;
 RECT 33.75 161.515 33.94 161.705 ;
 RECT 32.07 161.515 32.26 161.705 ;
 RECT 31.51 161.515 31.7 161.705 ;
 RECT 30.95 161.515 31.14 161.705 ;
 RECT 37.11 160.955 37.3 161.145 ;
 RECT 36.55 160.955 36.74 161.145 ;
 RECT 35.99 160.955 36.18 161.145 ;
 RECT 35.43 160.955 35.62 161.145 ;
 RECT 34.87 160.955 35.06 161.145 ;
 RECT 34.31 160.955 34.5 161.145 ;
 RECT 37.11 161.515 37.3 161.705 ;
 RECT 36.55 161.515 36.74 161.705 ;
 RECT 35.99 161.515 36.18 161.705 ;
 RECT 35.43 161.515 35.62 161.705 ;
 RECT 34.31 161.515 34.5 161.705 ;
 RECT 34.87 161.515 35.06 161.705 ;
 RECT 39.91 160.955 40.1 161.145 ;
 RECT 40.47 160.955 40.66 161.145 ;
 RECT 39.35 160.955 39.54 161.145 ;
 RECT 38.79 160.955 38.98 161.145 ;
 RECT 38.23 160.955 38.42 161.145 ;
 RECT 37.67 160.955 37.86 161.145 ;
 RECT 39.91 161.515 40.1 161.705 ;
 RECT 40.47 161.515 40.66 161.705 ;
 RECT 37.67 161.515 37.86 161.705 ;
 RECT 38.23 161.515 38.42 161.705 ;
 RECT 38.79 161.515 38.98 161.705 ;
 RECT 39.35 161.515 39.54 161.705 ;
 RECT 42.15 160.955 42.34 161.145 ;
 RECT 42.71 160.955 42.9 161.145 ;
 RECT 43.27 160.955 43.46 161.145 ;
 RECT 43.83 160.955 44.02 161.145 ;
 RECT 41.03 160.955 41.22 161.145 ;
 RECT 41.59 160.955 41.78 161.145 ;
 RECT 42.15 161.515 42.34 161.705 ;
 RECT 42.71 161.515 42.9 161.705 ;
 RECT 43.27 161.515 43.46 161.705 ;
 RECT 43.83 161.515 44.02 161.705 ;
 RECT 41.59 161.515 41.78 161.705 ;
 RECT 41.03 161.515 41.22 161.705 ;
 RECT 47.19 160.955 47.38 161.145 ;
 RECT 44.39 160.955 44.58 161.145 ;
 RECT 44.95 160.955 45.14 161.145 ;
 RECT 45.51 160.955 45.7 161.145 ;
 RECT 46.07 160.955 46.26 161.145 ;
 RECT 46.63 160.955 46.82 161.145 ;
 RECT 47.19 161.515 47.38 161.705 ;
 RECT 44.39 161.515 44.58 161.705 ;
 RECT 46.63 161.515 46.82 161.705 ;
 RECT 46.07 161.515 46.26 161.705 ;
 RECT 45.51 161.515 45.7 161.705 ;
 RECT 44.95 161.515 45.14 161.705 ;
 RECT 50.55 160.955 50.74 161.145 ;
 RECT 49.99 160.955 50.18 161.145 ;
 RECT 49.43 160.955 49.62 161.145 ;
 RECT 48.87 160.955 49.06 161.145 ;
 RECT 48.31 160.955 48.5 161.145 ;
 RECT 47.75 160.955 47.94 161.145 ;
 RECT 49.43 161.515 49.62 161.705 ;
 RECT 49.99 161.515 50.18 161.705 ;
 RECT 50.55 161.515 50.74 161.705 ;
 RECT 48.87 161.515 49.06 161.705 ;
 RECT 48.31 161.515 48.5 161.705 ;
 RECT 47.75 161.515 47.94 161.705 ;
 RECT 53.91 160.955 54.1 161.145 ;
 RECT 53.35 160.955 53.54 161.145 ;
 RECT 52.79 160.955 52.98 161.145 ;
 RECT 52.23 160.955 52.42 161.145 ;
 RECT 51.67 160.955 51.86 161.145 ;
 RECT 51.11 160.955 51.3 161.145 ;
 RECT 53.91 161.515 54.1 161.705 ;
 RECT 51.67 161.515 51.86 161.705 ;
 RECT 52.23 161.515 52.42 161.705 ;
 RECT 52.79 161.515 52.98 161.705 ;
 RECT 53.35 161.515 53.54 161.705 ;
 RECT 51.11 161.515 51.3 161.705 ;
 RECT 56.15 160.955 56.34 161.145 ;
 RECT 56.71 160.955 56.9 161.145 ;
 RECT 57.27 160.955 57.46 161.145 ;
 RECT 55.03 160.955 55.22 161.145 ;
 RECT 55.59 160.955 55.78 161.145 ;
 RECT 54.47 160.955 54.66 161.145 ;
 RECT 56.15 161.515 56.34 161.705 ;
 RECT 56.71 161.515 56.9 161.705 ;
 RECT 57.27 161.515 57.46 161.705 ;
 RECT 55.59 161.515 55.78 161.705 ;
 RECT 55.03 161.515 55.22 161.705 ;
 RECT 54.47 161.515 54.66 161.705 ;
 RECT 58.95 160.955 59.14 161.145 ;
 RECT 59.51 160.955 59.7 161.145 ;
 RECT 60.07 160.955 60.26 161.145 ;
 RECT 60.63 160.955 60.82 161.145 ;
 RECT 57.83 160.955 58.02 161.145 ;
 RECT 58.39 160.955 58.58 161.145 ;
 RECT 60.63 161.515 60.82 161.705 ;
 RECT 60.07 161.515 60.26 161.705 ;
 RECT 59.51 161.515 59.7 161.705 ;
 RECT 58.95 161.515 59.14 161.705 ;
 RECT 57.83 161.515 58.02 161.705 ;
 RECT 58.39 161.515 58.58 161.705 ;
 RECT 62.31 160.955 62.5 161.145 ;
 RECT 63.43 160.955 63.62 161.145 ;
 RECT 63.99 160.955 64.18 161.145 ;
 RECT 61.75 160.955 61.94 161.145 ;
 RECT 61.19 160.955 61.38 161.145 ;
 RECT 62.87 160.955 63.06 161.145 ;
 RECT 61.19 161.515 61.38 161.705 ;
 RECT 61.75 161.515 61.94 161.705 ;
 RECT 62.31 161.515 62.5 161.705 ;
 RECT 62.87 161.515 63.06 161.705 ;
 RECT 63.43 161.515 63.62 161.705 ;
 RECT 63.99 161.515 64.18 161.705 ;
 RECT 10.79 160.955 10.98 161.145 ;
 RECT 11.91 160.955 12.1 161.145 ;
 RECT 12.47 160.955 12.66 161.145 ;
 RECT 13.03 160.955 13.22 161.145 ;
 RECT 13.59 160.955 13.78 161.145 ;
 RECT 11.35 160.955 11.54 161.145 ;
 RECT 10.79 161.515 10.98 161.705 ;
 RECT 11.35 161.515 11.54 161.705 ;
 RECT 11.91 161.515 12.1 161.705 ;
 RECT 12.47 161.515 12.66 161.705 ;
 RECT 13.03 161.515 13.22 161.705 ;
 RECT 13.59 161.515 13.78 161.705 ;
 RECT 16.95 160.955 17.14 161.145 ;
 RECT 16.39 160.955 16.58 161.145 ;
 RECT 15.83 160.955 16.02 161.145 ;
 RECT 15.27 160.955 15.46 161.145 ;
 RECT 14.71 160.955 14.9 161.145 ;
 RECT 14.15 160.955 14.34 161.145 ;
 RECT 16.39 161.515 16.58 161.705 ;
 RECT 16.95 161.515 17.14 161.705 ;
 RECT 14.15 161.515 14.34 161.705 ;
 RECT 14.71 161.515 14.9 161.705 ;
 RECT 15.27 161.515 15.46 161.705 ;
 RECT 15.83 161.515 16.02 161.705 ;
 RECT 20.31 160.955 20.5 161.145 ;
 RECT 19.75 160.955 19.94 161.145 ;
 RECT 19.19 160.955 19.38 161.145 ;
 RECT 18.63 160.955 18.82 161.145 ;
 RECT 18.07 160.955 18.26 161.145 ;
 RECT 17.51 160.955 17.7 161.145 ;
 RECT 18.63 161.515 18.82 161.705 ;
 RECT 19.19 161.515 19.38 161.705 ;
 RECT 19.75 161.515 19.94 161.705 ;
 RECT 20.31 161.515 20.5 161.705 ;
 RECT 18.07 161.515 18.26 161.705 ;
 RECT 17.51 161.515 17.7 161.705 ;
 RECT 23.67 160.955 23.86 161.145 ;
 RECT 23.11 160.955 23.3 161.145 ;
 RECT 22.55 160.955 22.74 161.145 ;
 RECT 21.99 160.955 22.18 161.145 ;
 RECT 21.43 160.955 21.62 161.145 ;
 RECT 20.87 160.955 21.06 161.145 ;
 RECT 23.67 161.515 23.86 161.705 ;
 RECT 23.11 161.515 23.3 161.705 ;
 RECT 22.55 161.515 22.74 161.705 ;
 RECT 21.99 161.515 22.18 161.705 ;
 RECT 21.43 161.515 21.62 161.705 ;
 RECT 20.87 161.515 21.06 161.705 ;
 RECT 25.91 160.955 26.1 161.145 ;
 RECT 26.47 160.955 26.66 161.145 ;
 RECT 27.03 160.955 27.22 161.145 ;
 RECT 24.23 160.955 24.42 161.145 ;
 RECT 24.79 160.955 24.98 161.145 ;
 RECT 25.35 160.955 25.54 161.145 ;
 RECT 27.03 161.515 27.22 161.705 ;
 RECT 26.47 161.515 26.66 161.705 ;
 RECT 25.91 161.515 26.1 161.705 ;
 RECT 24.23 161.515 24.42 161.705 ;
 RECT 24.79 161.515 24.98 161.705 ;
 RECT 25.35 161.515 25.54 161.705 ;
 RECT 30.39 160.955 30.58 161.145 ;
 RECT 29.83 160.955 30.02 161.145 ;
 RECT 29.27 160.955 29.46 161.145 ;
 RECT 28.71 160.955 28.9 161.145 ;
 RECT 28.15 160.955 28.34 161.145 ;
 RECT 27.59 160.955 27.78 161.145 ;
 RECT 30.39 161.515 30.58 161.705 ;
 RECT 28.15 161.515 28.34 161.705 ;
 RECT 28.71 161.515 28.9 161.705 ;
 END
 END vssa
 OBS
 LAYER GATE ;
 RECT 0 0 75 162 ;
 LAYER MV1 ;
 RECT 0 0 75 162 ;
 LAYER MV2 ;
 RECT 0 0 75 162 ;
 LAYER MV3 ;
 RECT 0 0 75 162 ;
 LAYER MV4 ;
 RECT 0 0 75 162 ;
 LAYER M1 ;
 RECT 0 0 75 162 ;
 LAYER M2 ;
 RECT 65.1 160.22 75 162 ;
 RECT 0 160.22 9.9 162 ;
 RECT 0 0 75 160.22 ;
 LAYER M3 ;
 RECT 0 0 75 9.31 ;
 RECT 0 29.25 75 31.35 ;
 RECT 1.88 9.31 73.12 29.25 ;
 RECT 1.52 160.22 9.9 160.61 ;
 RECT 0 160.61 9.9 162 ;
 RECT 0 51.29 75 53.75 ;
 RECT 1.88 31.35 73.12 51.29 ;
 RECT 0 58.23 75 59.42 ;
 RECT 1.52 53.75 73.48 58.23 ;
 RECT 1.88 66.36 73.12 92.84 ;
 RECT 1.88 94.94 73.12 121.45 ;
 RECT 0 63.9 75 66.36 ;
 RECT 1.52 59.42 73.48 63.9 ;
 RECT 0 92.84 75 94.94 ;
 RECT 0 121.45 75 128.86 ;
 RECT 0 130.24 75 137.06 ;
 RECT 1.52 128.86 73.48 130.24 ;
 RECT 0 151.07 75 157.73 ;
 RECT 1.2 137.06 73.8 151.07 ;
 RECT 1.52 157.73 73.48 160.22 ;
 RECT 65.1 160.22 73.48 160.61 ;
 RECT 65.1 160.61 75 162 ;
 LAYER M4 ;
 RECT 0 0 75 123.91 ;
 RECT 0 129.39 75 130.58 ;
 RECT 2.24 123.91 72.76 129.39 ;
 RECT 2.6 135.39 72.4 147.06 ;
 RECT 0 134.56 75 135.39 ;
 RECT 2.24 130.58 72.76 134.56 ;
 RECT 0 147.06 75 147.89 ;
 RECT 0 152.37 75 153.56 ;
 RECT 2.24 147.89 72.76 152.37 ;
 RECT 0 156.54 75 157.73 ;
 RECT 2.24 153.56 72.76 156.54 ;
 RECT 0 160.71 75 162 ;
 RECT 2.24 157.73 72.76 160.71 ;
 LAYER M5 ;
 RECT 0 9.9 3.9 111.1 ;
 RECT 71.1 9.9 75 111.1 ;
 RECT 0 0 75 9.9 ;
 RECT 0 111.1 75 123.69 ;
 RECT 0 129.61 75 130.36 ;
 RECT 2.045 123.69 72.955 129.61 ;
 RECT 2.185 135.39 72.815 147.06 ;
 RECT 0 134.78 75 135.39 ;
 RECT 2.045 130.36 72.955 134.78 ;
 RECT 0 147.06 75 147.67 ;
 RECT 0 152.59 75 153.34 ;
 RECT 2.045 147.67 72.955 152.59 ;
 RECT 0 156.76 75 157.51 ;
 RECT 2.045 153.34 72.955 156.76 ;
 RECT 0 160.93 75 162 ;
 RECT 2.045 157.51 72.955 160.93 ;
 END
END RCMCU_PLVSSA

MACRO RCMCU_PLVSSH
 CLASS PAD ;
 FOREIGN RCMCU_PLVSSH ;
 ORIGIN 0 0 ;
 SIZE 75 BY 162 ;
 SYMMETRY X Y R90 ;
 PIN POC
 USE POWER ;
 DIRECTION INOUT ;
 PORT
 LAYER M3 ;
 RECT 73.72 129.1 75 130 ;
 END
 PORT
 LAYER M3 ;
 RECT 0 129.1 1.28 130 ;
 END
 END POC
 PIN gnd
 USE GROUND ;
 DIRECTION INOUT ;
 PORT
 LAYER M5 ;
 RECT 73.415 135.99 75 146.46 ;
 END
 PORT
 LAYER M5 ;
 RECT 0 135.99 1.585 146.46 ;
 END
 PORT
 LAYER M5 ;
 RECT 0 157.97 1.585 160.47 ;
 END
 PORT
 LAYER M5 ;
 RECT 73.415 157.97 75 160.47 ;
 END
 PORT
 LAYER M4 ;
 RECT 73 135.99 75 146.46 ;
 END
 PORT
 LAYER M4 ;
 RECT 0 135.99 2 146.46 ;
 END
 PORT
 LAYER M4 ;
 RECT 0 157.97 1.585 160.47 ;
 END
 PORT
 LAYER M4 ;
 RECT 73.415 157.97 75 160.47 ;
 END
 PORT
 LAYER M3 ;
 RECT 73.72 59.66 75 63.66 ;
 END
 PORT
 LAYER M3 ;
 RECT 0 59.66 1.28 63.66 ;
 END
 PORT
 LAYER M3 ;
 RECT 0 157.97 1.585 160.37 ;
 END
 PORT
 LAYER M3 ;
 RECT 73.415 157.97 75 160.37 ;
 END
 PORT
 LAYER MV3 ;
 RECT 73.6 158.44 73.79 158.63 ;
 RECT 74.21 158.44 74.4 158.63 ;
 RECT 73.6 159.05 73.79 159.24 ;
 RECT 74.21 159.05 74.4 159.24 ;
 RECT 73.6 159.66 73.79 159.85 ;
 RECT 74.21 159.66 74.4 159.85 ;
 RECT 0.6 158.44 0.79 158.63 ;
 RECT 1.21 158.44 1.4 158.63 ;
 RECT 0.6 159.05 0.79 159.24 ;
 RECT 1.21 159.05 1.4 159.24 ;
 RECT 0.6 159.66 0.79 159.85 ;
 RECT 1.21 159.66 1.4 159.85 ;
 END
 END gnd
 PIN vdd
 USE POWER ;
 DIRECTION INOUT ;
 PORT
 LAYER M5 ;
 RECT 73.415 153.8 75 156.3 ;
 END
 PORT
 LAYER M5 ;
 RECT 0 153.8 1.585 156.3 ;
 END
 PORT
 LAYER M4 ;
 RECT 73 153.8 75 156.3 ;
 END
 PORT
 LAYER M4 ;
 RECT 0 153.8 2 156.3 ;
 END
 END vdd
 PIN vddh
 USE POWER ;
 DIRECTION INOUT ;
 PORT
 LAYER M5 ;
 RECT 73.415 130.82 75 134.32 ;
 END
 PORT
 LAYER M5 ;
 RECT 0 130.82 1.585 134.32 ;
 END
 PORT
 LAYER M4 ;
 RECT 73 130.82 75 134.32 ;
 END
 PORT
 LAYER M4 ;
 RECT 0 130.82 2 134.32 ;
 END
 PORT
 LAYER M3 ;
 RECT 73.72 53.99 75 57.99 ;
 END
 PORT
 LAYER M3 ;
 RECT 0 53.99 1.28 57.99 ;
 END
 PORT
 LAYER M3 ;
 RECT 73.72 66.96 75 92.24 ;
 END
 PORT
 LAYER M3 ;
 RECT 0 66.96 1.28 92.24 ;
 END
 PORT
 LAYER M3 ;
 RECT 0 95.54 1.28 120.85 ;
 END
 PORT
 LAYER M3 ;
 RECT 73.72 95.54 75 120.85 ;
 END
 PORT
 LAYER M3 ;
 RECT 0 137.66 0.6 150.47 ;
 END
 PORT
 LAYER M3 ;
 RECT 74.4 137.66 75 150.47 ;
 END
 END vddh
 PIN vssh
 USE GROUND ;
 DIRECTION INOUT ;
 PORT
 LAYER M5 ;
 RECT 4.5 10.5 70.5 110.5 ;
 END
 PORT
 LAYER M5 ;
 RECT 0 124.15 1.585 129.15 ;
 END
 PORT
 LAYER M5 ;
 RECT 73.415 124.15 75 129.15 ;
 END
 PORT
 LAYER M5 ;
 RECT 0 148.13 1.585 152.13 ;
 END
 PORT
 LAYER M5 ;
 RECT 73.415 148.13 75 152.13 ;
 END
 PORT
 LAYER M4 ;
 RECT 73 124.15 75 129.15 ;
 END
 PORT
 LAYER M4 ;
 RECT 0 124.15 2 129.15 ;
 END
 PORT
 LAYER M4 ;
 RECT 0 148.13 2 152.13 ;
 END
 PORT
 LAYER M4 ;
 RECT 73 148.13 75 152.13 ;
 END
 PORT
 LAYER M3 ;
 RECT 73.72 9.91 75 28.65 ;
 END
 PORT
 LAYER M3 ;
 RECT 0 9.91 1.28 28.65 ;
 END
 PORT
 LAYER M3 ;
 RECT 0 31.95 1.28 50.69 ;
 END
 PORT
 LAYER M3 ;
 RECT 73.72 31.95 75 50.69 ;
 END
 PORT
 LAYER M3 ;
 RECT 10.5 160.82 64.5 162 ;
 END
 PORT
 LAYER M2 ;
 RECT 10.5 160.82 64.5 162 ;
 END
 PORT
 LAYER MV2 ;
 RECT 32.615 160.955 32.805 161.145 ;
 RECT 33.175 161.515 33.365 161.705 ;
 RECT 33.735 161.515 33.925 161.705 ;
 RECT 32.615 161.515 32.805 161.705 ;
 RECT 32.055 161.515 32.245 161.705 ;
 RECT 31.495 161.515 31.685 161.705 ;
 RECT 30.935 161.515 31.125 161.705 ;
 RECT 37.095 160.955 37.285 161.145 ;
 RECT 36.535 160.955 36.725 161.145 ;
 RECT 35.975 160.955 36.165 161.145 ;
 RECT 35.415 160.955 35.605 161.145 ;
 RECT 34.855 160.955 35.045 161.145 ;
 RECT 34.295 160.955 34.485 161.145 ;
 RECT 37.095 161.515 37.285 161.705 ;
 RECT 36.535 161.515 36.725 161.705 ;
 RECT 35.975 161.515 36.165 161.705 ;
 RECT 35.415 161.515 35.605 161.705 ;
 RECT 34.295 161.515 34.485 161.705 ;
 RECT 34.855 161.515 35.045 161.705 ;
 RECT 39.895 160.955 40.085 161.145 ;
 RECT 40.455 160.955 40.645 161.145 ;
 RECT 39.335 160.955 39.525 161.145 ;
 RECT 38.775 160.955 38.965 161.145 ;
 RECT 38.215 160.955 38.405 161.145 ;
 RECT 37.655 160.955 37.845 161.145 ;
 RECT 39.895 161.515 40.085 161.705 ;
 RECT 40.455 161.515 40.645 161.705 ;
 RECT 37.655 161.515 37.845 161.705 ;
 RECT 38.215 161.515 38.405 161.705 ;
 RECT 38.775 161.515 38.965 161.705 ;
 RECT 39.335 161.515 39.525 161.705 ;
 RECT 42.135 160.955 42.325 161.145 ;
 RECT 42.695 160.955 42.885 161.145 ;
 RECT 43.255 160.955 43.445 161.145 ;
 RECT 43.815 160.955 44.005 161.145 ;
 RECT 41.015 160.955 41.205 161.145 ;
 RECT 41.575 160.955 41.765 161.145 ;
 RECT 42.135 161.515 42.325 161.705 ;
 RECT 42.695 161.515 42.885 161.705 ;
 RECT 43.255 161.515 43.445 161.705 ;
 RECT 43.815 161.515 44.005 161.705 ;
 RECT 41.575 161.515 41.765 161.705 ;
 RECT 41.015 161.515 41.205 161.705 ;
 RECT 47.175 160.955 47.365 161.145 ;
 RECT 44.375 160.955 44.565 161.145 ;
 RECT 44.935 160.955 45.125 161.145 ;
 RECT 45.495 160.955 45.685 161.145 ;
 RECT 46.055 160.955 46.245 161.145 ;
 RECT 46.615 160.955 46.805 161.145 ;
 RECT 47.175 161.515 47.365 161.705 ;
 RECT 44.375 161.515 44.565 161.705 ;
 RECT 46.615 161.515 46.805 161.705 ;
 RECT 46.055 161.515 46.245 161.705 ;
 RECT 45.495 161.515 45.685 161.705 ;
 RECT 44.935 161.515 45.125 161.705 ;
 RECT 50.535 160.955 50.725 161.145 ;
 RECT 49.975 160.955 50.165 161.145 ;
 RECT 49.415 160.955 49.605 161.145 ;
 RECT 48.855 160.955 49.045 161.145 ;
 RECT 48.295 160.955 48.485 161.145 ;
 RECT 47.735 160.955 47.925 161.145 ;
 RECT 49.415 161.515 49.605 161.705 ;
 RECT 49.975 161.515 50.165 161.705 ;
 RECT 50.535 161.515 50.725 161.705 ;
 RECT 48.855 161.515 49.045 161.705 ;
 RECT 48.295 161.515 48.485 161.705 ;
 RECT 47.735 161.515 47.925 161.705 ;
 RECT 53.895 160.955 54.085 161.145 ;
 RECT 53.335 160.955 53.525 161.145 ;
 RECT 52.775 160.955 52.965 161.145 ;
 RECT 52.215 160.955 52.405 161.145 ;
 RECT 51.655 160.955 51.845 161.145 ;
 RECT 51.095 160.955 51.285 161.145 ;
 RECT 53.895 161.515 54.085 161.705 ;
 RECT 51.655 161.515 51.845 161.705 ;
 RECT 52.215 161.515 52.405 161.705 ;
 RECT 52.775 161.515 52.965 161.705 ;
 RECT 53.335 161.515 53.525 161.705 ;
 RECT 51.095 161.515 51.285 161.705 ;
 RECT 56.135 160.955 56.325 161.145 ;
 RECT 56.695 160.955 56.885 161.145 ;
 RECT 57.255 160.955 57.445 161.145 ;
 RECT 55.015 160.955 55.205 161.145 ;
 RECT 55.575 160.955 55.765 161.145 ;
 RECT 54.455 160.955 54.645 161.145 ;
 RECT 56.135 161.515 56.325 161.705 ;
 RECT 56.695 161.515 56.885 161.705 ;
 RECT 57.255 161.515 57.445 161.705 ;
 RECT 55.575 161.515 55.765 161.705 ;
 RECT 55.015 161.515 55.205 161.705 ;
 RECT 54.455 161.515 54.645 161.705 ;
 RECT 58.935 160.955 59.125 161.145 ;
 RECT 59.495 160.955 59.685 161.145 ;
 RECT 60.055 160.955 60.245 161.145 ;
 RECT 60.615 160.955 60.805 161.145 ;
 RECT 57.815 160.955 58.005 161.145 ;
 RECT 58.375 160.955 58.565 161.145 ;
 RECT 60.615 161.515 60.805 161.705 ;
 RECT 60.055 161.515 60.245 161.705 ;
 RECT 59.495 161.515 59.685 161.705 ;
 RECT 58.935 161.515 59.125 161.705 ;
 RECT 57.815 161.515 58.005 161.705 ;
 RECT 58.375 161.515 58.565 161.705 ;
 RECT 62.295 160.955 62.485 161.145 ;
 RECT 63.415 160.955 63.605 161.145 ;
 RECT 63.975 160.955 64.165 161.145 ;
 RECT 61.735 160.955 61.925 161.145 ;
 RECT 61.175 160.955 61.365 161.145 ;
 RECT 62.855 160.955 63.045 161.145 ;
 RECT 61.175 161.515 61.365 161.705 ;
 RECT 61.735 161.515 61.925 161.705 ;
 RECT 62.295 161.515 62.485 161.705 ;
 RECT 62.855 161.515 63.045 161.705 ;
 RECT 63.415 161.515 63.605 161.705 ;
 RECT 63.975 161.515 64.165 161.705 ;
 RECT 10.775 160.955 10.965 161.145 ;
 RECT 11.895 160.955 12.085 161.145 ;
 RECT 12.455 160.955 12.645 161.145 ;
 RECT 13.015 160.955 13.205 161.145 ;
 RECT 13.575 160.955 13.765 161.145 ;
 RECT 11.335 160.955 11.525 161.145 ;
 RECT 10.775 161.515 10.965 161.705 ;
 RECT 11.335 161.515 11.525 161.705 ;
 RECT 11.895 161.515 12.085 161.705 ;
 RECT 12.455 161.515 12.645 161.705 ;
 RECT 13.015 161.515 13.205 161.705 ;
 RECT 13.575 161.515 13.765 161.705 ;
 RECT 16.935 160.955 17.125 161.145 ;
 RECT 16.375 160.955 16.565 161.145 ;
 RECT 15.815 160.955 16.005 161.145 ;
 RECT 15.255 160.955 15.445 161.145 ;
 RECT 14.695 160.955 14.885 161.145 ;
 RECT 14.135 160.955 14.325 161.145 ;
 RECT 16.375 161.515 16.565 161.705 ;
 RECT 16.935 161.515 17.125 161.705 ;
 RECT 14.135 161.515 14.325 161.705 ;
 RECT 14.695 161.515 14.885 161.705 ;
 RECT 15.255 161.515 15.445 161.705 ;
 RECT 15.815 161.515 16.005 161.705 ;
 RECT 20.295 160.955 20.485 161.145 ;
 RECT 19.735 160.955 19.925 161.145 ;
 RECT 19.175 160.955 19.365 161.145 ;
 RECT 18.615 160.955 18.805 161.145 ;
 RECT 18.055 160.955 18.245 161.145 ;
 RECT 17.495 160.955 17.685 161.145 ;
 RECT 18.615 161.515 18.805 161.705 ;
 RECT 19.175 161.515 19.365 161.705 ;
 RECT 19.735 161.515 19.925 161.705 ;
 RECT 20.295 161.515 20.485 161.705 ;
 RECT 18.055 161.515 18.245 161.705 ;
 RECT 17.495 161.515 17.685 161.705 ;
 RECT 23.655 160.955 23.845 161.145 ;
 RECT 23.095 160.955 23.285 161.145 ;
 RECT 22.535 160.955 22.725 161.145 ;
 RECT 21.975 160.955 22.165 161.145 ;
 RECT 21.415 160.955 21.605 161.145 ;
 RECT 20.855 160.955 21.045 161.145 ;
 RECT 23.655 161.515 23.845 161.705 ;
 RECT 23.095 161.515 23.285 161.705 ;
 RECT 22.535 161.515 22.725 161.705 ;
 RECT 21.975 161.515 22.165 161.705 ;
 RECT 21.415 161.515 21.605 161.705 ;
 RECT 20.855 161.515 21.045 161.705 ;
 RECT 25.895 160.955 26.085 161.145 ;
 RECT 26.455 160.955 26.645 161.145 ;
 RECT 27.015 160.955 27.205 161.145 ;
 RECT 24.215 160.955 24.405 161.145 ;
 RECT 24.775 160.955 24.965 161.145 ;
 RECT 25.335 160.955 25.525 161.145 ;
 RECT 27.015 161.515 27.205 161.705 ;
 RECT 26.455 161.515 26.645 161.705 ;
 RECT 25.895 161.515 26.085 161.705 ;
 RECT 24.215 161.515 24.405 161.705 ;
 RECT 24.775 161.515 24.965 161.705 ;
 RECT 25.335 161.515 25.525 161.705 ;
 RECT 30.375 160.955 30.565 161.145 ;
 RECT 29.815 160.955 30.005 161.145 ;
 RECT 29.255 160.955 29.445 161.145 ;
 RECT 28.695 160.955 28.885 161.145 ;
 RECT 28.135 160.955 28.325 161.145 ;
 RECT 27.575 160.955 27.765 161.145 ;
 RECT 30.375 161.515 30.565 161.705 ;
 RECT 28.135 161.515 28.325 161.705 ;
 RECT 28.695 161.515 28.885 161.705 ;
 RECT 29.255 161.515 29.445 161.705 ;
 RECT 29.815 161.515 30.005 161.705 ;
 RECT 27.575 161.515 27.765 161.705 ;
 RECT 33.735 160.955 33.925 161.145 ;
 RECT 33.175 160.955 33.365 161.145 ;
 RECT 30.935 160.955 31.125 161.145 ;
 RECT 31.495 160.955 31.685 161.145 ;
 RECT 32.055 160.955 32.245 161.145 ;
 END
 END vssh
 OBS
 LAYER GATE ;
 RECT 0 0 75 162 ;
 LAYER MV1 ;
 RECT 0 0 75 162 ;
 LAYER MV2 ;
 RECT 0 0 75 162 ;
 LAYER MV3 ;
 RECT 0 0 75 162 ;
 LAYER MV4 ;
 RECT 0 0 75 162 ;
 LAYER M1 ;
 RECT 0 0 75 162 ;
 LAYER M2 ;
 RECT 65.1 160.22 75 162 ;
 RECT 0 160.22 9.9 162 ;
 RECT 0 0 75 160.22 ;
 LAYER M3 ;
 RECT 0 29.25 75 31.35 ;
 RECT 1.88 9.31 73.12 29.25 ;
 RECT 1.825 160.22 9.9 160.61 ;
 RECT 0 160.61 9.9 162 ;
 RECT 0 51.29 75 53.75 ;
 RECT 1.88 31.35 73.12 51.29 ;
 RECT 0 58.23 75 59.42 ;
 RECT 1.52 53.75 73.48 58.23 ;
 RECT 1.88 66.36 73.12 92.84 ;
 RECT 1.88 94.94 73.12 121.45 ;
 RECT 1.825 157.73 73.175 160.22 ;
 RECT 65.1 160.22 73.175 160.61 ;
 RECT 0 63.9 75 66.36 ;
 RECT 1.52 59.42 73.48 63.9 ;
 RECT 0 92.84 75 94.94 ;
 RECT 0 121.45 75 128.86 ;
 RECT 0 130.24 75 137.06 ;
 RECT 1.52 128.86 73.48 130.24 ;
 RECT 0 151.07 75 157.73 ;
 RECT 1.2 137.06 73.8 151.07 ;
 RECT 65.1 160.61 75 162 ;
 RECT 0 0 75 9.31 ;
 LAYER M4 ;
 RECT 0 0 75 123.91 ;
 RECT 0 129.39 75 130.58 ;
 RECT 2.24 123.91 72.76 129.39 ;
 RECT 2.6 135.39 72.4 147.06 ;
 RECT 0 134.56 75 135.39 ;
 RECT 2.24 130.58 72.76 134.56 ;
 RECT 0 147.06 75 147.89 ;
 RECT 0 152.37 75 153.56 ;
 RECT 2.24 147.89 72.76 152.37 ;
 RECT 0 156.54 75 157.73 ;
 RECT 2.24 153.56 72.76 156.54 ;
 RECT 0 160.71 75 162 ;
 RECT 1.825 157.73 73.175 160.71 ;
 LAYER M5 ;
 RECT 0 9.9 3.9 111.1 ;
 RECT 71.1 9.9 75 111.1 ;
 RECT 0 0 75 9.9 ;
 RECT 0 111.1 75 123.69 ;
 RECT 0 129.61 75 130.36 ;
 RECT 2.045 123.69 72.955 129.61 ;
 RECT 2.185 135.39 72.815 147.06 ;
 RECT 0 134.78 75 135.39 ;
 RECT 2.045 130.36 72.955 134.78 ;
 RECT 0 147.06 75 147.67 ;
 RECT 0 152.59 75 153.34 ;
 RECT 2.045 147.67 72.955 152.59 ;
 RECT 0 156.76 75 157.51 ;
 RECT 2.045 153.34 72.955 156.76 ;
 RECT 0 160.93 75 162 ;
 RECT 2.045 157.51 72.955 160.93 ;
 END
END RCMCU_PLVSSH

MACRO RCMCU_PLVSSHA
 CLASS PAD ;
 FOREIGN RCMCU_PLVSSHA ;
 ORIGIN 0 0 ;
 SIZE 75 BY 162 ;
 SYMMETRY X Y R90 ;
 PIN POC
 USE POWER ;
 DIRECTION INOUT ;
 PORT
 LAYER M3 ;
 RECT 73.72 129.1 75 130 ;
 END
 PORT
 LAYER M3 ;
 RECT 0 129.1 1.28 130 ;
 END
 END POC
 PIN gnd
 USE GROUND ;
 DIRECTION INOUT ;
 PORT
 LAYER M5 ;
 RECT 73.415 135.99 75 146.46 ;
 END
 PORT
 LAYER M5 ;
 RECT 0 135.99 1.585 146.46 ;
 END
 PORT
 LAYER M5 ;
 RECT 0 157.97 1.585 160.47 ;
 END
 PORT
 LAYER M5 ;
 RECT 73.415 157.97 75 160.47 ;
 END
 PORT
 LAYER M4 ;
 RECT 73 135.99 75 146.46 ;
 END
 PORT
 LAYER M4 ;
 RECT 0 135.99 2 146.46 ;
 END
 PORT
 LAYER M4 ;
 RECT 0 157.97 2 160.47 ;
 END
 PORT
 LAYER M4 ;
 RECT 73 157.97 75 160.47 ;
 END
 PORT
 LAYER M3 ;
 RECT 73.72 59.66 75 63.66 ;
 END
 PORT
 LAYER M3 ;
 RECT 0 59.66 1.28 63.66 ;
 END
 PORT
 LAYER M3 ;
 RECT 0 157.97 1.28 160.37 ;
 END
 PORT
 LAYER M3 ;
 RECT 73.72 157.97 75 160.37 ;
 END
 PORT
 LAYER MV3 ;
 RECT 74.175 158.525 74.365 158.715 ;
 RECT 74.175 159.325 74.365 159.515 ;
 RECT 0.635 158.525 0.825 158.715 ;
 RECT 0.635 159.325 0.825 159.515 ;
 END
 END gnd
 PIN vdd
 USE POWER ;
 DIRECTION INOUT ;
 PORT
 LAYER M5 ;
 RECT 73.415 153.8 75 156.3 ;
 END
 PORT
 LAYER M5 ;
 RECT 0 153.8 1.585 156.3 ;
 END
 PORT
 LAYER M4 ;
 RECT 73 153.8 75 156.3 ;
 END
 PORT
 LAYER M4 ;
 RECT 0 153.8 2 156.3 ;
 END
 END vdd
 PIN vddha
 USE POWER ;
 DIRECTION INOUT ;
 PORT
 LAYER M5 ;
 RECT 73.415 130.82 75 134.32 ;
 END
 PORT
 LAYER M5 ;
 RECT 0 130.82 1.585 134.32 ;
 END
 PORT
 LAYER M4 ;
 RECT 73 130.82 75 134.32 ;
 END
 PORT
 LAYER M4 ;
 RECT 0 130.82 2 134.32 ;
 END
 PORT
 LAYER M3 ;
 RECT 73.72 53.99 75 57.99 ;
 END
 PORT
 LAYER M3 ;
 RECT 0 53.99 1.28 57.99 ;
 END
 PORT
 LAYER M3 ;
 RECT 73.72 66.96 75 92.24 ;
 END
 PORT
 LAYER M3 ;
 RECT 0 66.96 1.28 92.24 ;
 END
 PORT
 LAYER M3 ;
 RECT 0 95.54 1.28 120.85 ;
 END
 PORT
 LAYER M3 ;
 RECT 73.72 95.54 75 120.85 ;
 END
 PORT
 LAYER M3 ;
 RECT 0 137.66 0.6 150.47 ;
 END
 PORT
 LAYER M3 ;
 RECT 74.4 137.66 75 150.47 ;
 END
 END vddha
 PIN vssha
 USE GROUND ;
 DIRECTION INOUT ;
 PORT
 LAYER M5 ;
 RECT 4.5 10.5 70.5 110.5 ;
 END
 PORT
 LAYER M5 ;
 RECT 0 124.15 1.585 129.15 ;
 END
 PORT
 LAYER M5 ;
 RECT 73.415 124.15 75 129.15 ;
 END
 PORT
 LAYER M5 ;
 RECT 0 148.13 1.585 152.13 ;
 END
 PORT
 LAYER M5 ;
 RECT 73.415 148.13 75 152.13 ;
 END
 PORT
 LAYER M4 ;
 RECT 73 124.15 75 129.15 ;
 END
 PORT
 LAYER M4 ;
 RECT 0 124.15 2 129.15 ;
 END
 PORT
 LAYER M4 ;
 RECT 0 148.13 2 152.13 ;
 END
 PORT
 LAYER M4 ;
 RECT 73 148.13 75 152.13 ;
 END
 PORT
 LAYER M3 ;
 RECT 73.72 9.91 75 28.65 ;
 END
 PORT
 LAYER M3 ;
 RECT 0 9.91 1.28 28.65 ;
 END
 PORT
 LAYER M3 ;
 RECT 0 31.95 1.28 50.69 ;
 END
 PORT
 LAYER M3 ;
 RECT 73.72 31.95 75 50.69 ;
 END
 PORT
 LAYER M3 ;
 RECT 10.5 160.82 64.5 162 ;
 END
 PORT
 LAYER M2 ;
 RECT 10.5 160.82 64.5 162 ;
 END
 PORT
 LAYER MV2 ;
 RECT 29.255 161.515 29.445 161.705 ;
 RECT 29.815 161.515 30.005 161.705 ;
 RECT 27.575 161.515 27.765 161.705 ;
 RECT 33.735 160.955 33.925 161.145 ;
 RECT 33.175 160.955 33.365 161.145 ;
 RECT 30.935 160.955 31.125 161.145 ;
 RECT 31.495 160.955 31.685 161.145 ;
 RECT 32.055 160.955 32.245 161.145 ;
 RECT 32.615 160.955 32.805 161.145 ;
 RECT 33.175 161.515 33.365 161.705 ;
 RECT 33.735 161.515 33.925 161.705 ;
 RECT 32.615 161.515 32.805 161.705 ;
 RECT 32.055 161.515 32.245 161.705 ;
 RECT 31.495 161.515 31.685 161.705 ;
 RECT 30.935 161.515 31.125 161.705 ;
 RECT 37.095 160.955 37.285 161.145 ;
 RECT 36.535 160.955 36.725 161.145 ;
 RECT 35.975 160.955 36.165 161.145 ;
 RECT 35.415 160.955 35.605 161.145 ;
 RECT 34.855 160.955 35.045 161.145 ;
 RECT 34.295 160.955 34.485 161.145 ;
 RECT 37.095 161.515 37.285 161.705 ;
 RECT 36.535 161.515 36.725 161.705 ;
 RECT 35.975 161.515 36.165 161.705 ;
 RECT 35.415 161.515 35.605 161.705 ;
 RECT 34.295 161.515 34.485 161.705 ;
 RECT 34.855 161.515 35.045 161.705 ;
 RECT 39.895 160.955 40.085 161.145 ;
 RECT 40.455 160.955 40.645 161.145 ;
 RECT 39.335 160.955 39.525 161.145 ;
 RECT 38.775 160.955 38.965 161.145 ;
 RECT 38.215 160.955 38.405 161.145 ;
 RECT 37.655 160.955 37.845 161.145 ;
 RECT 39.895 161.515 40.085 161.705 ;
 RECT 40.455 161.515 40.645 161.705 ;
 RECT 37.655 161.515 37.845 161.705 ;
 RECT 38.215 161.515 38.405 161.705 ;
 RECT 38.775 161.515 38.965 161.705 ;
 RECT 39.335 161.515 39.525 161.705 ;
 RECT 42.135 160.955 42.325 161.145 ;
 RECT 42.695 160.955 42.885 161.145 ;
 RECT 43.255 160.955 43.445 161.145 ;
 RECT 43.815 160.955 44.005 161.145 ;
 RECT 41.015 160.955 41.205 161.145 ;
 RECT 41.575 160.955 41.765 161.145 ;
 RECT 42.135 161.515 42.325 161.705 ;
 RECT 42.695 161.515 42.885 161.705 ;
 RECT 43.255 161.515 43.445 161.705 ;
 RECT 43.815 161.515 44.005 161.705 ;
 RECT 41.575 161.515 41.765 161.705 ;
 RECT 41.015 161.515 41.205 161.705 ;
 RECT 47.175 160.955 47.365 161.145 ;
 RECT 44.375 160.955 44.565 161.145 ;
 RECT 44.935 160.955 45.125 161.145 ;
 RECT 45.495 160.955 45.685 161.145 ;
 RECT 46.055 160.955 46.245 161.145 ;
 RECT 46.615 160.955 46.805 161.145 ;
 RECT 47.175 161.515 47.365 161.705 ;
 RECT 44.375 161.515 44.565 161.705 ;
 RECT 46.615 161.515 46.805 161.705 ;
 RECT 46.055 161.515 46.245 161.705 ;
 RECT 45.495 161.515 45.685 161.705 ;
 RECT 44.935 161.515 45.125 161.705 ;
 RECT 50.535 160.955 50.725 161.145 ;
 RECT 49.975 160.955 50.165 161.145 ;
 RECT 49.415 160.955 49.605 161.145 ;
 RECT 48.855 160.955 49.045 161.145 ;
 RECT 48.295 160.955 48.485 161.145 ;
 RECT 47.735 160.955 47.925 161.145 ;
 RECT 49.415 161.515 49.605 161.705 ;
 RECT 49.975 161.515 50.165 161.705 ;
 RECT 50.535 161.515 50.725 161.705 ;
 RECT 48.855 161.515 49.045 161.705 ;
 RECT 48.295 161.515 48.485 161.705 ;
 RECT 47.735 161.515 47.925 161.705 ;
 RECT 53.895 160.955 54.085 161.145 ;
 RECT 53.335 160.955 53.525 161.145 ;
 RECT 52.775 160.955 52.965 161.145 ;
 RECT 52.215 160.955 52.405 161.145 ;
 RECT 51.655 160.955 51.845 161.145 ;
 RECT 51.095 160.955 51.285 161.145 ;
 RECT 53.895 161.515 54.085 161.705 ;
 RECT 51.655 161.515 51.845 161.705 ;
 RECT 52.215 161.515 52.405 161.705 ;
 RECT 52.775 161.515 52.965 161.705 ;
 RECT 53.335 161.515 53.525 161.705 ;
 RECT 51.095 161.515 51.285 161.705 ;
 RECT 56.135 160.955 56.325 161.145 ;
 RECT 56.695 160.955 56.885 161.145 ;
 RECT 57.255 160.955 57.445 161.145 ;
 RECT 55.015 160.955 55.205 161.145 ;
 RECT 55.575 160.955 55.765 161.145 ;
 RECT 54.455 160.955 54.645 161.145 ;
 RECT 56.135 161.515 56.325 161.705 ;
 RECT 56.695 161.515 56.885 161.705 ;
 RECT 57.255 161.515 57.445 161.705 ;
 RECT 55.575 161.515 55.765 161.705 ;
 RECT 55.015 161.515 55.205 161.705 ;
 RECT 54.455 161.515 54.645 161.705 ;
 RECT 58.935 160.955 59.125 161.145 ;
 RECT 59.495 160.955 59.685 161.145 ;
 RECT 60.055 160.955 60.245 161.145 ;
 RECT 60.615 160.955 60.805 161.145 ;
 RECT 57.815 160.955 58.005 161.145 ;
 RECT 58.375 160.955 58.565 161.145 ;
 RECT 60.615 161.515 60.805 161.705 ;
 RECT 60.055 161.515 60.245 161.705 ;
 RECT 59.495 161.515 59.685 161.705 ;
 RECT 58.935 161.515 59.125 161.705 ;
 RECT 57.815 161.515 58.005 161.705 ;
 RECT 58.375 161.515 58.565 161.705 ;
 RECT 62.295 160.955 62.485 161.145 ;
 RECT 63.415 160.955 63.605 161.145 ;
 RECT 63.975 160.955 64.165 161.145 ;
 RECT 61.735 160.955 61.925 161.145 ;
 RECT 61.175 160.955 61.365 161.145 ;
 RECT 62.855 160.955 63.045 161.145 ;
 RECT 61.175 161.515 61.365 161.705 ;
 RECT 61.735 161.515 61.925 161.705 ;
 RECT 62.295 161.515 62.485 161.705 ;
 RECT 62.855 161.515 63.045 161.705 ;
 RECT 63.415 161.515 63.605 161.705 ;
 RECT 63.975 161.515 64.165 161.705 ;
 RECT 10.775 160.955 10.965 161.145 ;
 RECT 11.895 160.955 12.085 161.145 ;
 RECT 12.455 160.955 12.645 161.145 ;
 RECT 13.015 160.955 13.205 161.145 ;
 RECT 13.575 160.955 13.765 161.145 ;
 RECT 11.335 160.955 11.525 161.145 ;
 RECT 10.775 161.515 10.965 161.705 ;
 RECT 11.335 161.515 11.525 161.705 ;
 RECT 11.895 161.515 12.085 161.705 ;
 RECT 12.455 161.515 12.645 161.705 ;
 RECT 13.015 161.515 13.205 161.705 ;
 RECT 13.575 161.515 13.765 161.705 ;
 RECT 16.935 160.955 17.125 161.145 ;
 RECT 16.375 160.955 16.565 161.145 ;
 RECT 15.815 160.955 16.005 161.145 ;
 RECT 15.255 160.955 15.445 161.145 ;
 RECT 14.695 160.955 14.885 161.145 ;
 RECT 14.135 160.955 14.325 161.145 ;
 RECT 16.375 161.515 16.565 161.705 ;
 RECT 16.935 161.515 17.125 161.705 ;
 RECT 14.135 161.515 14.325 161.705 ;
 RECT 14.695 161.515 14.885 161.705 ;
 RECT 15.255 161.515 15.445 161.705 ;
 RECT 15.815 161.515 16.005 161.705 ;
 RECT 20.295 160.955 20.485 161.145 ;
 RECT 19.735 160.955 19.925 161.145 ;
 RECT 19.175 160.955 19.365 161.145 ;
 RECT 18.615 160.955 18.805 161.145 ;
 RECT 18.055 160.955 18.245 161.145 ;
 RECT 17.495 160.955 17.685 161.145 ;
 RECT 18.615 161.515 18.805 161.705 ;
 RECT 19.175 161.515 19.365 161.705 ;
 RECT 19.735 161.515 19.925 161.705 ;
 RECT 20.295 161.515 20.485 161.705 ;
 RECT 18.055 161.515 18.245 161.705 ;
 RECT 17.495 161.515 17.685 161.705 ;
 RECT 23.655 160.955 23.845 161.145 ;
 RECT 23.095 160.955 23.285 161.145 ;
 RECT 22.535 160.955 22.725 161.145 ;
 RECT 21.975 160.955 22.165 161.145 ;
 RECT 21.415 160.955 21.605 161.145 ;
 RECT 20.855 160.955 21.045 161.145 ;
 RECT 23.655 161.515 23.845 161.705 ;
 RECT 23.095 161.515 23.285 161.705 ;
 RECT 22.535 161.515 22.725 161.705 ;
 RECT 21.975 161.515 22.165 161.705 ;
 RECT 21.415 161.515 21.605 161.705 ;
 RECT 20.855 161.515 21.045 161.705 ;
 RECT 25.895 160.955 26.085 161.145 ;
 RECT 26.455 160.955 26.645 161.145 ;
 RECT 27.015 160.955 27.205 161.145 ;
 RECT 24.215 160.955 24.405 161.145 ;
 RECT 24.775 160.955 24.965 161.145 ;
 RECT 25.335 160.955 25.525 161.145 ;
 RECT 27.015 161.515 27.205 161.705 ;
 RECT 26.455 161.515 26.645 161.705 ;
 RECT 25.895 161.515 26.085 161.705 ;
 RECT 24.215 161.515 24.405 161.705 ;
 RECT 24.775 161.515 24.965 161.705 ;
 RECT 25.335 161.515 25.525 161.705 ;
 RECT 30.375 160.955 30.565 161.145 ;
 RECT 29.815 160.955 30.005 161.145 ;
 RECT 29.255 160.955 29.445 161.145 ;
 RECT 28.695 160.955 28.885 161.145 ;
 RECT 28.135 160.955 28.325 161.145 ;
 RECT 27.575 160.955 27.765 161.145 ;
 RECT 30.375 161.515 30.565 161.705 ;
 RECT 28.135 161.515 28.325 161.705 ;
 RECT 28.695 161.515 28.885 161.705 ;
 END
 END vssha
 OBS
 LAYER GATE ;
 RECT 0 0 75 162 ;
 LAYER MV1 ;
 RECT 0 0 75 162 ;
 LAYER MV2 ;
 RECT 0 0 75 162 ;
 LAYER MV3 ;
 RECT 0 0 75 162 ;
 LAYER MV4 ;
 RECT 0 0 75 162 ;
 LAYER M1 ;
 RECT 0 0 75 162 ;
 LAYER M2 ;
 RECT 65.1 160.22 75 162 ;
 RECT 0 160.22 9.9 162 ;
 RECT 0 0 75 160.22 ;
 LAYER M3 ;
 RECT 0 0 75 9.31 ;
 RECT 0 29.25 75 31.35 ;
 RECT 1.88 9.31 73.12 29.25 ;
 RECT 1.52 160.22 9.9 160.61 ;
 RECT 0 160.61 9.9 162 ;
 RECT 0 51.29 75 53.75 ;
 RECT 1.88 31.35 73.12 51.29 ;
 RECT 0 58.23 75 59.42 ;
 RECT 1.52 53.75 73.48 58.23 ;
 RECT 1.88 66.36 73.12 92.84 ;
 RECT 1.88 94.94 73.12 121.45 ;
 RECT 0 63.9 75 66.36 ;
 RECT 1.52 59.42 73.48 63.9 ;
 RECT 0 92.84 75 94.94 ;
 RECT 0 121.45 75 128.86 ;
 RECT 0 130.24 75 137.06 ;
 RECT 1.52 128.86 73.48 130.24 ;
 RECT 0 151.07 75 157.73 ;
 RECT 1.2 137.06 73.8 151.07 ;
 RECT 1.52 157.73 73.48 160.22 ;
 RECT 65.1 160.22 73.48 160.61 ;
 RECT 65.1 160.61 75 162 ;
 LAYER M4 ;
 RECT 0 0 75 123.91 ;
 RECT 0 129.39 75 130.58 ;
 RECT 2.24 123.91 72.76 129.39 ;
 RECT 2.6 135.39 72.4 147.06 ;
 RECT 0 134.56 75 135.39 ;
 RECT 2.24 130.58 72.76 134.56 ;
 RECT 0 147.06 75 147.89 ;
 RECT 0 152.37 75 153.56 ;
 RECT 2.24 147.89 72.76 152.37 ;
 RECT 0 156.54 75 157.73 ;
 RECT 2.24 153.56 72.76 156.54 ;
 RECT 0 160.71 75 162 ;
 RECT 2.24 157.73 72.76 160.71 ;
 LAYER M5 ;
 RECT 0 9.9 3.9 111.1 ;
 RECT 71.1 9.9 75 111.1 ;
 RECT 0 0 75 9.9 ;
 RECT 0 111.1 75 123.69 ;
 RECT 0 129.61 75 130.36 ;
 RECT 2.045 123.69 72.955 129.61 ;
 RECT 2.185 135.39 72.815 147.06 ;
 RECT 0 134.78 75 135.39 ;
 RECT 2.045 130.36 72.955 134.78 ;
 RECT 0 147.06 75 147.67 ;
 RECT 0 152.59 75 153.34 ;
 RECT 2.045 147.67 72.955 152.59 ;
 RECT 0 156.76 75 157.51 ;
 RECT 2.045 153.34 72.955 156.76 ;
 RECT 0 160.93 75 162 ;
 RECT 2.045 157.51 72.955 160.93 ;
 END
END RCMCU_PLVSSHA

END LIBRARY
